VERSION 5.8 ;
BUSBITCHARS "[]" ;
DIVIDERCHAR "/" ;
UNITS
    DATABASE MICRONS 1000 ;
END UNITS

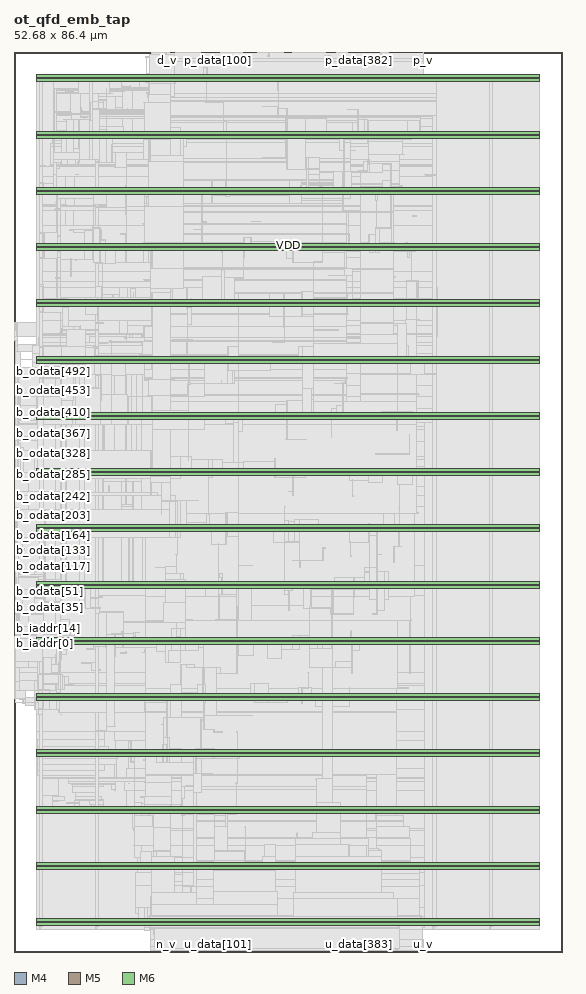
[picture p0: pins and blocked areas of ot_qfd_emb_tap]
MACRO ot_qfd_emb_tap
  FOREIGN ot_qfd_emb_tap 0 0 ;
  CLASS BLOCK ;
  SIZE 52.68 BY 86.4 ;
  PIN b_iaddr[0]
    DIRECTION OUTPUT ;
    USE SIGNAL ;
    PORT
      LAYER M4 ;
        RECT  0 30.384 0.084 30.408 ;
    END
  END b_iaddr[0]
  PIN b_iaddr[10]
    DIRECTION OUTPUT ;
    USE SIGNAL ;
    PORT
      LAYER M4 ;
        RECT  0 30.864 0.084 30.888 ;
    END
  END b_iaddr[10]
  PIN b_iaddr[11]
    DIRECTION OUTPUT ;
    USE SIGNAL ;
    PORT
      LAYER M4 ;
        RECT  0 30.912 0.084 30.936 ;
    END
  END b_iaddr[11]
  PIN b_iaddr[12]
    DIRECTION OUTPUT ;
    USE SIGNAL ;
    PORT
      LAYER M4 ;
        RECT  0 30.96 0.084 30.984 ;
    END
  END b_iaddr[12]
  PIN b_iaddr[13]
    DIRECTION OUTPUT ;
    USE SIGNAL ;
    PORT
      LAYER M4 ;
        RECT  0 31.008 0.084 31.032 ;
    END
  END b_iaddr[13]
  PIN b_iaddr[14]
    DIRECTION OUTPUT ;
    USE SIGNAL ;
    PORT
      LAYER M4 ;
        RECT  0 31.056 0.084 31.08 ;
    END
  END b_iaddr[14]
  PIN b_iaddr[15]
    DIRECTION OUTPUT ;
    USE SIGNAL ;
    PORT
      LAYER M4 ;
        RECT  0 31.104 0.084 31.128 ;
    END
  END b_iaddr[15]
  PIN b_iaddr[16]
    DIRECTION OUTPUT ;
    USE SIGNAL ;
    PORT
      LAYER M4 ;
        RECT  0 31.152 0.084 31.176 ;
    END
  END b_iaddr[16]
  PIN b_iaddr[17]
    DIRECTION OUTPUT ;
    USE SIGNAL ;
    PORT
      LAYER M4 ;
        RECT  0 31.2 0.084 31.224 ;
    END
  END b_iaddr[17]
  PIN b_iaddr[1]
    DIRECTION OUTPUT ;
    USE SIGNAL ;
    PORT
      LAYER M4 ;
        RECT  0 30.432 0.084 30.456 ;
    END
  END b_iaddr[1]
  PIN b_iaddr[2]
    DIRECTION OUTPUT ;
    USE SIGNAL ;
    PORT
      LAYER M4 ;
        RECT  0 30.48 0.084 30.504 ;
    END
  END b_iaddr[2]
  PIN b_iaddr[3]
    DIRECTION OUTPUT ;
    USE SIGNAL ;
    PORT
      LAYER M4 ;
        RECT  0 30.528 0.084 30.552 ;
    END
  END b_iaddr[3]
  PIN b_iaddr[4]
    DIRECTION OUTPUT ;
    USE SIGNAL ;
    PORT
      LAYER M4 ;
        RECT  0 30.576 0.084 30.6 ;
    END
  END b_iaddr[4]
  PIN b_iaddr[5]
    DIRECTION OUTPUT ;
    USE SIGNAL ;
    PORT
      LAYER M4 ;
        RECT  0 30.624 0.084 30.648 ;
    END
  END b_iaddr[5]
  PIN b_iaddr[6]
    DIRECTION OUTPUT ;
    USE SIGNAL ;
    PORT
      LAYER M4 ;
        RECT  0 30.672 0.084 30.696 ;
    END
  END b_iaddr[6]
  PIN b_iaddr[7]
    DIRECTION OUTPUT ;
    USE SIGNAL ;
    PORT
      LAYER M4 ;
        RECT  0 30.72 0.084 30.744 ;
    END
  END b_iaddr[7]
  PIN b_iaddr[8]
    DIRECTION OUTPUT ;
    USE SIGNAL ;
    PORT
      LAYER M4 ;
        RECT  0 30.768 0.084 30.792 ;
    END
  END b_iaddr[8]
  PIN b_iaddr[9]
    DIRECTION OUTPUT ;
    USE SIGNAL ;
    PORT
      LAYER M4 ;
        RECT  0 30.816 0.084 30.84 ;
    END
  END b_iaddr[9]
  PIN b_icr
    DIRECTION INPUT ;
    USE SIGNAL ;
    PORT
      LAYER M4 ;
        RECT  0 31.248 0.084 31.272 ;
    END
  END b_icr
  PIN b_iv
    DIRECTION OUTPUT ;
    USE SIGNAL ;
    PORT
      LAYER M4 ;
        RECT  0 31.296 0.084 31.32 ;
    END
  END b_iv
  PIN b_ocr
    DIRECTION OUTPUT ;
    USE SIGNAL ;
    PORT
      LAYER M4 ;
        RECT  0 31.344 0.084 31.368 ;
    END
  END b_ocr
  PIN b_odata[0]
    DIRECTION INPUT ;
    USE SIGNAL ;
    PORT
      LAYER M4 ;
        RECT  0 31.392 0.084 31.416 ;
    END
  END b_odata[0]
  PIN b_odata[100]
    DIRECTION INPUT ;
    USE SIGNAL ;
    PORT
      LAYER M4 ;
        RECT  0 36.192 0.084 36.216 ;
    END
  END b_odata[100]
  PIN b_odata[101]
    DIRECTION INPUT ;
    USE SIGNAL ;
    PORT
      LAYER M4 ;
        RECT  0 36.24 0.084 36.264 ;
    END
  END b_odata[101]
  PIN b_odata[102]
    DIRECTION INPUT ;
    USE SIGNAL ;
    PORT
      LAYER M4 ;
        RECT  0 36.288 0.084 36.312 ;
    END
  END b_odata[102]
  PIN b_odata[103]
    DIRECTION INPUT ;
    USE SIGNAL ;
    PORT
      LAYER M4 ;
        RECT  0 36.336 0.084 36.36 ;
    END
  END b_odata[103]
  PIN b_odata[104]
    DIRECTION INPUT ;
    USE SIGNAL ;
    PORT
      LAYER M4 ;
        RECT  0 36.384 0.084 36.408 ;
    END
  END b_odata[104]
  PIN b_odata[105]
    DIRECTION INPUT ;
    USE SIGNAL ;
    PORT
      LAYER M4 ;
        RECT  0 36.432 0.084 36.456 ;
    END
  END b_odata[105]
  PIN b_odata[106]
    DIRECTION INPUT ;
    USE SIGNAL ;
    PORT
      LAYER M4 ;
        RECT  0 36.48 0.084 36.504 ;
    END
  END b_odata[106]
  PIN b_odata[107]
    DIRECTION INPUT ;
    USE SIGNAL ;
    PORT
      LAYER M4 ;
        RECT  0 36.528 0.084 36.552 ;
    END
  END b_odata[107]
  PIN b_odata[108]
    DIRECTION INPUT ;
    USE SIGNAL ;
    PORT
      LAYER M4 ;
        RECT  0 36.576 0.084 36.6 ;
    END
  END b_odata[108]
  PIN b_odata[109]
    DIRECTION INPUT ;
    USE SIGNAL ;
    PORT
      LAYER M4 ;
        RECT  0 36.624 0.084 36.648 ;
    END
  END b_odata[109]
  PIN b_odata[10]
    DIRECTION INPUT ;
    USE SIGNAL ;
    PORT
      LAYER M4 ;
        RECT  0 31.872 0.084 31.896 ;
    END
  END b_odata[10]
  PIN b_odata[110]
    DIRECTION INPUT ;
    USE SIGNAL ;
    PORT
      LAYER M4 ;
        RECT  0 36.672 0.084 36.696 ;
    END
  END b_odata[110]
  PIN b_odata[111]
    DIRECTION INPUT ;
    USE SIGNAL ;
    PORT
      LAYER M4 ;
        RECT  0 36.72 0.084 36.744 ;
    END
  END b_odata[111]
  PIN b_odata[112]
    DIRECTION INPUT ;
    USE SIGNAL ;
    PORT
      LAYER M4 ;
        RECT  0 36.768 0.084 36.792 ;
    END
  END b_odata[112]
  PIN b_odata[113]
    DIRECTION INPUT ;
    USE SIGNAL ;
    PORT
      LAYER M4 ;
        RECT  0 36.816 0.084 36.84 ;
    END
  END b_odata[113]
  PIN b_odata[114]
    DIRECTION INPUT ;
    USE SIGNAL ;
    PORT
      LAYER M4 ;
        RECT  0 36.864 0.084 36.888 ;
    END
  END b_odata[114]
  PIN b_odata[115]
    DIRECTION INPUT ;
    USE SIGNAL ;
    PORT
      LAYER M4 ;
        RECT  0 36.912 0.084 36.936 ;
    END
  END b_odata[115]
  PIN b_odata[116]
    DIRECTION INPUT ;
    USE SIGNAL ;
    PORT
      LAYER M4 ;
        RECT  0 36.96 0.084 36.984 ;
    END
  END b_odata[116]
  PIN b_odata[117]
    DIRECTION INPUT ;
    USE SIGNAL ;
    PORT
      LAYER M4 ;
        RECT  0 37.008 0.084 37.032 ;
    END
  END b_odata[117]
  PIN b_odata[118]
    DIRECTION INPUT ;
    USE SIGNAL ;
    PORT
      LAYER M4 ;
        RECT  0 37.056 0.084 37.08 ;
    END
  END b_odata[118]
  PIN b_odata[119]
    DIRECTION INPUT ;
    USE SIGNAL ;
    PORT
      LAYER M4 ;
        RECT  0 37.104 0.084 37.128 ;
    END
  END b_odata[119]
  PIN b_odata[11]
    DIRECTION INPUT ;
    USE SIGNAL ;
    PORT
      LAYER M4 ;
        RECT  0 31.92 0.084 31.944 ;
    END
  END b_odata[11]
  PIN b_odata[120]
    DIRECTION INPUT ;
    USE SIGNAL ;
    PORT
      LAYER M4 ;
        RECT  0 37.152 0.084 37.176 ;
    END
  END b_odata[120]
  PIN b_odata[121]
    DIRECTION INPUT ;
    USE SIGNAL ;
    PORT
      LAYER M4 ;
        RECT  0 37.2 0.084 37.224 ;
    END
  END b_odata[121]
  PIN b_odata[122]
    DIRECTION INPUT ;
    USE SIGNAL ;
    PORT
      LAYER M4 ;
        RECT  0 37.248 0.084 37.272 ;
    END
  END b_odata[122]
  PIN b_odata[123]
    DIRECTION INPUT ;
    USE SIGNAL ;
    PORT
      LAYER M4 ;
        RECT  0 37.296 0.084 37.32 ;
    END
  END b_odata[123]
  PIN b_odata[124]
    DIRECTION INPUT ;
    USE SIGNAL ;
    PORT
      LAYER M4 ;
        RECT  0 37.344 0.084 37.368 ;
    END
  END b_odata[124]
  PIN b_odata[125]
    DIRECTION INPUT ;
    USE SIGNAL ;
    PORT
      LAYER M4 ;
        RECT  0 37.392 0.084 37.416 ;
    END
  END b_odata[125]
  PIN b_odata[126]
    DIRECTION INPUT ;
    USE SIGNAL ;
    PORT
      LAYER M4 ;
        RECT  0 37.44 0.084 37.464 ;
    END
  END b_odata[126]
  PIN b_odata[127]
    DIRECTION INPUT ;
    USE SIGNAL ;
    PORT
      LAYER M4 ;
        RECT  0 37.488 0.084 37.512 ;
    END
  END b_odata[127]
  PIN b_odata[128]
    DIRECTION INPUT ;
    USE SIGNAL ;
    PORT
      LAYER M4 ;
        RECT  0 37.536 0.084 37.56 ;
    END
  END b_odata[128]
  PIN b_odata[129]
    DIRECTION INPUT ;
    USE SIGNAL ;
    PORT
      LAYER M4 ;
        RECT  0 37.584 0.084 37.608 ;
    END
  END b_odata[129]
  PIN b_odata[12]
    DIRECTION INPUT ;
    USE SIGNAL ;
    PORT
      LAYER M4 ;
        RECT  0 31.968 0.084 31.992 ;
    END
  END b_odata[12]
  PIN b_odata[130]
    DIRECTION INPUT ;
    USE SIGNAL ;
    PORT
      LAYER M4 ;
        RECT  0 37.632 0.084 37.656 ;
    END
  END b_odata[130]
  PIN b_odata[131]
    DIRECTION INPUT ;
    USE SIGNAL ;
    PORT
      LAYER M4 ;
        RECT  0 37.68 0.084 37.704 ;
    END
  END b_odata[131]
  PIN b_odata[132]
    DIRECTION INPUT ;
    USE SIGNAL ;
    PORT
      LAYER M4 ;
        RECT  0 37.728 0.084 37.752 ;
    END
  END b_odata[132]
  PIN b_odata[133]
    DIRECTION INPUT ;
    USE SIGNAL ;
    PORT
      LAYER M4 ;
        RECT  0 37.776 0.084 37.8 ;
    END
  END b_odata[133]
  PIN b_odata[134]
    DIRECTION INPUT ;
    USE SIGNAL ;
    PORT
      LAYER M4 ;
        RECT  0 37.824 0.084 37.848 ;
    END
  END b_odata[134]
  PIN b_odata[135]
    DIRECTION INPUT ;
    USE SIGNAL ;
    PORT
      LAYER M4 ;
        RECT  0 37.872 0.084 37.896 ;
    END
  END b_odata[135]
  PIN b_odata[136]
    DIRECTION INPUT ;
    USE SIGNAL ;
    PORT
      LAYER M4 ;
        RECT  0 37.92 0.084 37.944 ;
    END
  END b_odata[136]
  PIN b_odata[137]
    DIRECTION INPUT ;
    USE SIGNAL ;
    PORT
      LAYER M4 ;
        RECT  0 37.968 0.084 37.992 ;
    END
  END b_odata[137]
  PIN b_odata[138]
    DIRECTION INPUT ;
    USE SIGNAL ;
    PORT
      LAYER M4 ;
        RECT  0 38.016 0.084 38.04 ;
    END
  END b_odata[138]
  PIN b_odata[139]
    DIRECTION INPUT ;
    USE SIGNAL ;
    PORT
      LAYER M4 ;
        RECT  0 38.064 0.084 38.088 ;
    END
  END b_odata[139]
  PIN b_odata[13]
    DIRECTION INPUT ;
    USE SIGNAL ;
    PORT
      LAYER M4 ;
        RECT  0 32.016 0.084 32.04 ;
    END
  END b_odata[13]
  PIN b_odata[140]
    DIRECTION INPUT ;
    USE SIGNAL ;
    PORT
      LAYER M4 ;
        RECT  0 38.112 0.084 38.136 ;
    END
  END b_odata[140]
  PIN b_odata[141]
    DIRECTION INPUT ;
    USE SIGNAL ;
    PORT
      LAYER M4 ;
        RECT  0 38.16 0.084 38.184 ;
    END
  END b_odata[141]
  PIN b_odata[142]
    DIRECTION INPUT ;
    USE SIGNAL ;
    PORT
      LAYER M4 ;
        RECT  0 38.208 0.084 38.232 ;
    END
  END b_odata[142]
  PIN b_odata[143]
    DIRECTION INPUT ;
    USE SIGNAL ;
    PORT
      LAYER M4 ;
        RECT  0 38.256 0.084 38.28 ;
    END
  END b_odata[143]
  PIN b_odata[144]
    DIRECTION INPUT ;
    USE SIGNAL ;
    PORT
      LAYER M4 ;
        RECT  0 38.304 0.084 38.328 ;
    END
  END b_odata[144]
  PIN b_odata[145]
    DIRECTION INPUT ;
    USE SIGNAL ;
    PORT
      LAYER M4 ;
        RECT  0 38.352 0.084 38.376 ;
    END
  END b_odata[145]
  PIN b_odata[146]
    DIRECTION INPUT ;
    USE SIGNAL ;
    PORT
      LAYER M4 ;
        RECT  0 38.4 0.084 38.424 ;
    END
  END b_odata[146]
  PIN b_odata[147]
    DIRECTION INPUT ;
    USE SIGNAL ;
    PORT
      LAYER M4 ;
        RECT  0 38.448 0.084 38.472 ;
    END
  END b_odata[147]
  PIN b_odata[148]
    DIRECTION INPUT ;
    USE SIGNAL ;
    PORT
      LAYER M4 ;
        RECT  0 38.496 0.084 38.52 ;
    END
  END b_odata[148]
  PIN b_odata[149]
    DIRECTION INPUT ;
    USE SIGNAL ;
    PORT
      LAYER M4 ;
        RECT  0 38.544 0.084 38.568 ;
    END
  END b_odata[149]
  PIN b_odata[14]
    DIRECTION INPUT ;
    USE SIGNAL ;
    PORT
      LAYER M4 ;
        RECT  0 32.064 0.084 32.088 ;
    END
  END b_odata[14]
  PIN b_odata[150]
    DIRECTION INPUT ;
    USE SIGNAL ;
    PORT
      LAYER M4 ;
        RECT  0 38.592 0.084 38.616 ;
    END
  END b_odata[150]
  PIN b_odata[151]
    DIRECTION INPUT ;
    USE SIGNAL ;
    PORT
      LAYER M4 ;
        RECT  0 38.64 0.084 38.664 ;
    END
  END b_odata[151]
  PIN b_odata[152]
    DIRECTION INPUT ;
    USE SIGNAL ;
    PORT
      LAYER M4 ;
        RECT  0 38.688 0.084 38.712 ;
    END
  END b_odata[152]
  PIN b_odata[153]
    DIRECTION INPUT ;
    USE SIGNAL ;
    PORT
      LAYER M4 ;
        RECT  0 38.736 0.084 38.76 ;
    END
  END b_odata[153]
  PIN b_odata[154]
    DIRECTION INPUT ;
    USE SIGNAL ;
    PORT
      LAYER M4 ;
        RECT  0 38.784 0.084 38.808 ;
    END
  END b_odata[154]
  PIN b_odata[155]
    DIRECTION INPUT ;
    USE SIGNAL ;
    PORT
      LAYER M4 ;
        RECT  0 38.832 0.084 38.856 ;
    END
  END b_odata[155]
  PIN b_odata[156]
    DIRECTION INPUT ;
    USE SIGNAL ;
    PORT
      LAYER M4 ;
        RECT  0 38.88 0.084 38.904 ;
    END
  END b_odata[156]
  PIN b_odata[157]
    DIRECTION INPUT ;
    USE SIGNAL ;
    PORT
      LAYER M4 ;
        RECT  0 38.928 0.084 38.952 ;
    END
  END b_odata[157]
  PIN b_odata[158]
    DIRECTION INPUT ;
    USE SIGNAL ;
    PORT
      LAYER M4 ;
        RECT  0 38.976 0.084 39 ;
    END
  END b_odata[158]
  PIN b_odata[159]
    DIRECTION INPUT ;
    USE SIGNAL ;
    PORT
      LAYER M4 ;
        RECT  0 39.024 0.084 39.048 ;
    END
  END b_odata[159]
  PIN b_odata[15]
    DIRECTION INPUT ;
    USE SIGNAL ;
    PORT
      LAYER M4 ;
        RECT  0 32.112 0.084 32.136 ;
    END
  END b_odata[15]
  PIN b_odata[160]
    DIRECTION INPUT ;
    USE SIGNAL ;
    PORT
      LAYER M4 ;
        RECT  0 39.072 0.084 39.096 ;
    END
  END b_odata[160]
  PIN b_odata[161]
    DIRECTION INPUT ;
    USE SIGNAL ;
    PORT
      LAYER M4 ;
        RECT  0 39.12 0.084 39.144 ;
    END
  END b_odata[161]
  PIN b_odata[162]
    DIRECTION INPUT ;
    USE SIGNAL ;
    PORT
      LAYER M4 ;
        RECT  0 39.168 0.084 39.192 ;
    END
  END b_odata[162]
  PIN b_odata[163]
    DIRECTION INPUT ;
    USE SIGNAL ;
    PORT
      LAYER M4 ;
        RECT  0 39.216 0.084 39.24 ;
    END
  END b_odata[163]
  PIN b_odata[164]
    DIRECTION INPUT ;
    USE SIGNAL ;
    PORT
      LAYER M4 ;
        RECT  0 39.264 0.084 39.288 ;
    END
  END b_odata[164]
  PIN b_odata[165]
    DIRECTION INPUT ;
    USE SIGNAL ;
    PORT
      LAYER M4 ;
        RECT  0 39.312 0.084 39.336 ;
    END
  END b_odata[165]
  PIN b_odata[166]
    DIRECTION INPUT ;
    USE SIGNAL ;
    PORT
      LAYER M4 ;
        RECT  0 39.36 0.084 39.384 ;
    END
  END b_odata[166]
  PIN b_odata[167]
    DIRECTION INPUT ;
    USE SIGNAL ;
    PORT
      LAYER M4 ;
        RECT  0 39.408 0.084 39.432 ;
    END
  END b_odata[167]
  PIN b_odata[168]
    DIRECTION INPUT ;
    USE SIGNAL ;
    PORT
      LAYER M4 ;
        RECT  0 39.456 0.084 39.48 ;
    END
  END b_odata[168]
  PIN b_odata[169]
    DIRECTION INPUT ;
    USE SIGNAL ;
    PORT
      LAYER M4 ;
        RECT  0 39.504 0.084 39.528 ;
    END
  END b_odata[169]
  PIN b_odata[16]
    DIRECTION INPUT ;
    USE SIGNAL ;
    PORT
      LAYER M4 ;
        RECT  0 32.16 0.084 32.184 ;
    END
  END b_odata[16]
  PIN b_odata[170]
    DIRECTION INPUT ;
    USE SIGNAL ;
    PORT
      LAYER M4 ;
        RECT  0 39.552 0.084 39.576 ;
    END
  END b_odata[170]
  PIN b_odata[171]
    DIRECTION INPUT ;
    USE SIGNAL ;
    PORT
      LAYER M4 ;
        RECT  0 39.6 0.084 39.624 ;
    END
  END b_odata[171]
  PIN b_odata[172]
    DIRECTION INPUT ;
    USE SIGNAL ;
    PORT
      LAYER M4 ;
        RECT  0 39.648 0.084 39.672 ;
    END
  END b_odata[172]
  PIN b_odata[173]
    DIRECTION INPUT ;
    USE SIGNAL ;
    PORT
      LAYER M4 ;
        RECT  0 39.696 0.084 39.72 ;
    END
  END b_odata[173]
  PIN b_odata[174]
    DIRECTION INPUT ;
    USE SIGNAL ;
    PORT
      LAYER M4 ;
        RECT  0 39.744 0.084 39.768 ;
    END
  END b_odata[174]
  PIN b_odata[175]
    DIRECTION INPUT ;
    USE SIGNAL ;
    PORT
      LAYER M4 ;
        RECT  0 39.792 0.084 39.816 ;
    END
  END b_odata[175]
  PIN b_odata[176]
    DIRECTION INPUT ;
    USE SIGNAL ;
    PORT
      LAYER M4 ;
        RECT  0 39.84 0.084 39.864 ;
    END
  END b_odata[176]
  PIN b_odata[177]
    DIRECTION INPUT ;
    USE SIGNAL ;
    PORT
      LAYER M4 ;
        RECT  0 39.888 0.084 39.912 ;
    END
  END b_odata[177]
  PIN b_odata[178]
    DIRECTION INPUT ;
    USE SIGNAL ;
    PORT
      LAYER M4 ;
        RECT  0 39.936 0.084 39.96 ;
    END
  END b_odata[178]
  PIN b_odata[179]
    DIRECTION INPUT ;
    USE SIGNAL ;
    PORT
      LAYER M4 ;
        RECT  0 39.984 0.084 40.008 ;
    END
  END b_odata[179]
  PIN b_odata[17]
    DIRECTION INPUT ;
    USE SIGNAL ;
    PORT
      LAYER M4 ;
        RECT  0 32.208 0.084 32.232 ;
    END
  END b_odata[17]
  PIN b_odata[180]
    DIRECTION INPUT ;
    USE SIGNAL ;
    PORT
      LAYER M4 ;
        RECT  0 40.032 0.084 40.056 ;
    END
  END b_odata[180]
  PIN b_odata[181]
    DIRECTION INPUT ;
    USE SIGNAL ;
    PORT
      LAYER M4 ;
        RECT  0 40.08 0.084 40.104 ;
    END
  END b_odata[181]
  PIN b_odata[182]
    DIRECTION INPUT ;
    USE SIGNAL ;
    PORT
      LAYER M4 ;
        RECT  0 40.128 0.084 40.152 ;
    END
  END b_odata[182]
  PIN b_odata[183]
    DIRECTION INPUT ;
    USE SIGNAL ;
    PORT
      LAYER M4 ;
        RECT  0 40.176 0.084 40.2 ;
    END
  END b_odata[183]
  PIN b_odata[184]
    DIRECTION INPUT ;
    USE SIGNAL ;
    PORT
      LAYER M4 ;
        RECT  0 40.224 0.084 40.248 ;
    END
  END b_odata[184]
  PIN b_odata[185]
    DIRECTION INPUT ;
    USE SIGNAL ;
    PORT
      LAYER M4 ;
        RECT  0 40.272 0.084 40.296 ;
    END
  END b_odata[185]
  PIN b_odata[186]
    DIRECTION INPUT ;
    USE SIGNAL ;
    PORT
      LAYER M4 ;
        RECT  0 40.32 0.084 40.344 ;
    END
  END b_odata[186]
  PIN b_odata[187]
    DIRECTION INPUT ;
    USE SIGNAL ;
    PORT
      LAYER M4 ;
        RECT  0 40.368 0.084 40.392 ;
    END
  END b_odata[187]
  PIN b_odata[188]
    DIRECTION INPUT ;
    USE SIGNAL ;
    PORT
      LAYER M4 ;
        RECT  0 40.416 0.084 40.44 ;
    END
  END b_odata[188]
  PIN b_odata[189]
    DIRECTION INPUT ;
    USE SIGNAL ;
    PORT
      LAYER M4 ;
        RECT  0 40.464 0.084 40.488 ;
    END
  END b_odata[189]
  PIN b_odata[18]
    DIRECTION INPUT ;
    USE SIGNAL ;
    PORT
      LAYER M4 ;
        RECT  0 32.256 0.084 32.28 ;
    END
  END b_odata[18]
  PIN b_odata[190]
    DIRECTION INPUT ;
    USE SIGNAL ;
    PORT
      LAYER M4 ;
        RECT  0 40.512 0.084 40.536 ;
    END
  END b_odata[190]
  PIN b_odata[191]
    DIRECTION INPUT ;
    USE SIGNAL ;
    PORT
      LAYER M4 ;
        RECT  0 40.56 0.084 40.584 ;
    END
  END b_odata[191]
  PIN b_odata[192]
    DIRECTION INPUT ;
    USE SIGNAL ;
    PORT
      LAYER M4 ;
        RECT  0 40.608 0.084 40.632 ;
    END
  END b_odata[192]
  PIN b_odata[193]
    DIRECTION INPUT ;
    USE SIGNAL ;
    PORT
      LAYER M4 ;
        RECT  0 40.656 0.084 40.68 ;
    END
  END b_odata[193]
  PIN b_odata[194]
    DIRECTION INPUT ;
    USE SIGNAL ;
    PORT
      LAYER M4 ;
        RECT  0 40.704 0.084 40.728 ;
    END
  END b_odata[194]
  PIN b_odata[195]
    DIRECTION INPUT ;
    USE SIGNAL ;
    PORT
      LAYER M4 ;
        RECT  0 40.752 0.084 40.776 ;
    END
  END b_odata[195]
  PIN b_odata[196]
    DIRECTION INPUT ;
    USE SIGNAL ;
    PORT
      LAYER M4 ;
        RECT  0 40.8 0.084 40.824 ;
    END
  END b_odata[196]
  PIN b_odata[197]
    DIRECTION INPUT ;
    USE SIGNAL ;
    PORT
      LAYER M4 ;
        RECT  0 40.848 0.084 40.872 ;
    END
  END b_odata[197]
  PIN b_odata[198]
    DIRECTION INPUT ;
    USE SIGNAL ;
    PORT
      LAYER M4 ;
        RECT  0 40.896 0.084 40.92 ;
    END
  END b_odata[198]
  PIN b_odata[199]
    DIRECTION INPUT ;
    USE SIGNAL ;
    PORT
      LAYER M4 ;
        RECT  0 40.944 0.084 40.968 ;
    END
  END b_odata[199]
  PIN b_odata[19]
    DIRECTION INPUT ;
    USE SIGNAL ;
    PORT
      LAYER M4 ;
        RECT  0 32.304 0.084 32.328 ;
    END
  END b_odata[19]
  PIN b_odata[1]
    DIRECTION INPUT ;
    USE SIGNAL ;
    PORT
      LAYER M4 ;
        RECT  0 31.44 0.084 31.464 ;
    END
  END b_odata[1]
  PIN b_odata[200]
    DIRECTION INPUT ;
    USE SIGNAL ;
    PORT
      LAYER M4 ;
        RECT  0 40.992 0.084 41.016 ;
    END
  END b_odata[200]
  PIN b_odata[201]
    DIRECTION INPUT ;
    USE SIGNAL ;
    PORT
      LAYER M4 ;
        RECT  0 41.04 0.084 41.064 ;
    END
  END b_odata[201]
  PIN b_odata[202]
    DIRECTION INPUT ;
    USE SIGNAL ;
    PORT
      LAYER M4 ;
        RECT  0 41.088 0.084 41.112 ;
    END
  END b_odata[202]
  PIN b_odata[203]
    DIRECTION INPUT ;
    USE SIGNAL ;
    PORT
      LAYER M4 ;
        RECT  0 41.136 0.084 41.16 ;
    END
  END b_odata[203]
  PIN b_odata[204]
    DIRECTION INPUT ;
    USE SIGNAL ;
    PORT
      LAYER M4 ;
        RECT  0 41.184 0.084 41.208 ;
    END
  END b_odata[204]
  PIN b_odata[205]
    DIRECTION INPUT ;
    USE SIGNAL ;
    PORT
      LAYER M4 ;
        RECT  0 41.232 0.084 41.256 ;
    END
  END b_odata[205]
  PIN b_odata[206]
    DIRECTION INPUT ;
    USE SIGNAL ;
    PORT
      LAYER M4 ;
        RECT  0 41.28 0.084 41.304 ;
    END
  END b_odata[206]
  PIN b_odata[207]
    DIRECTION INPUT ;
    USE SIGNAL ;
    PORT
      LAYER M4 ;
        RECT  0 41.328 0.084 41.352 ;
    END
  END b_odata[207]
  PIN b_odata[208]
    DIRECTION INPUT ;
    USE SIGNAL ;
    PORT
      LAYER M4 ;
        RECT  0 41.376 0.084 41.4 ;
    END
  END b_odata[208]
  PIN b_odata[209]
    DIRECTION INPUT ;
    USE SIGNAL ;
    PORT
      LAYER M4 ;
        RECT  0 41.424 0.084 41.448 ;
    END
  END b_odata[209]
  PIN b_odata[20]
    DIRECTION INPUT ;
    USE SIGNAL ;
    PORT
      LAYER M4 ;
        RECT  0 32.352 0.084 32.376 ;
    END
  END b_odata[20]
  PIN b_odata[210]
    DIRECTION INPUT ;
    USE SIGNAL ;
    PORT
      LAYER M4 ;
        RECT  0 41.472 0.084 41.496 ;
    END
  END b_odata[210]
  PIN b_odata[211]
    DIRECTION INPUT ;
    USE SIGNAL ;
    PORT
      LAYER M4 ;
        RECT  0 41.52 0.084 41.544 ;
    END
  END b_odata[211]
  PIN b_odata[212]
    DIRECTION INPUT ;
    USE SIGNAL ;
    PORT
      LAYER M4 ;
        RECT  0 41.568 0.084 41.592 ;
    END
  END b_odata[212]
  PIN b_odata[213]
    DIRECTION INPUT ;
    USE SIGNAL ;
    PORT
      LAYER M4 ;
        RECT  0 41.616 0.084 41.64 ;
    END
  END b_odata[213]
  PIN b_odata[214]
    DIRECTION INPUT ;
    USE SIGNAL ;
    PORT
      LAYER M4 ;
        RECT  0 41.664 0.084 41.688 ;
    END
  END b_odata[214]
  PIN b_odata[215]
    DIRECTION INPUT ;
    USE SIGNAL ;
    PORT
      LAYER M4 ;
        RECT  0 41.712 0.084 41.736 ;
    END
  END b_odata[215]
  PIN b_odata[216]
    DIRECTION INPUT ;
    USE SIGNAL ;
    PORT
      LAYER M4 ;
        RECT  0 41.76 0.084 41.784 ;
    END
  END b_odata[216]
  PIN b_odata[217]
    DIRECTION INPUT ;
    USE SIGNAL ;
    PORT
      LAYER M4 ;
        RECT  0 41.808 0.084 41.832 ;
    END
  END b_odata[217]
  PIN b_odata[218]
    DIRECTION INPUT ;
    USE SIGNAL ;
    PORT
      LAYER M4 ;
        RECT  0 41.856 0.084 41.88 ;
    END
  END b_odata[218]
  PIN b_odata[219]
    DIRECTION INPUT ;
    USE SIGNAL ;
    PORT
      LAYER M4 ;
        RECT  0 41.904 0.084 41.928 ;
    END
  END b_odata[219]
  PIN b_odata[21]
    DIRECTION INPUT ;
    USE SIGNAL ;
    PORT
      LAYER M4 ;
        RECT  0 32.4 0.084 32.424 ;
    END
  END b_odata[21]
  PIN b_odata[220]
    DIRECTION INPUT ;
    USE SIGNAL ;
    PORT
      LAYER M4 ;
        RECT  0 41.952 0.084 41.976 ;
    END
  END b_odata[220]
  PIN b_odata[221]
    DIRECTION INPUT ;
    USE SIGNAL ;
    PORT
      LAYER M4 ;
        RECT  0 42 0.084 42.024 ;
    END
  END b_odata[221]
  PIN b_odata[222]
    DIRECTION INPUT ;
    USE SIGNAL ;
    PORT
      LAYER M4 ;
        RECT  0 42.048 0.084 42.072 ;
    END
  END b_odata[222]
  PIN b_odata[223]
    DIRECTION INPUT ;
    USE SIGNAL ;
    PORT
      LAYER M4 ;
        RECT  0 42.096 0.084 42.12 ;
    END
  END b_odata[223]
  PIN b_odata[224]
    DIRECTION INPUT ;
    USE SIGNAL ;
    PORT
      LAYER M4 ;
        RECT  0 42.144 0.084 42.168 ;
    END
  END b_odata[224]
  PIN b_odata[225]
    DIRECTION INPUT ;
    USE SIGNAL ;
    PORT
      LAYER M4 ;
        RECT  0 42.192 0.084 42.216 ;
    END
  END b_odata[225]
  PIN b_odata[226]
    DIRECTION INPUT ;
    USE SIGNAL ;
    PORT
      LAYER M4 ;
        RECT  0 42.24 0.084 42.264 ;
    END
  END b_odata[226]
  PIN b_odata[227]
    DIRECTION INPUT ;
    USE SIGNAL ;
    PORT
      LAYER M4 ;
        RECT  0 42.288 0.084 42.312 ;
    END
  END b_odata[227]
  PIN b_odata[228]
    DIRECTION INPUT ;
    USE SIGNAL ;
    PORT
      LAYER M4 ;
        RECT  0 42.336 0.084 42.36 ;
    END
  END b_odata[228]
  PIN b_odata[229]
    DIRECTION INPUT ;
    USE SIGNAL ;
    PORT
      LAYER M4 ;
        RECT  0 42.384 0.084 42.408 ;
    END
  END b_odata[229]
  PIN b_odata[22]
    DIRECTION INPUT ;
    USE SIGNAL ;
    PORT
      LAYER M4 ;
        RECT  0 32.448 0.084 32.472 ;
    END
  END b_odata[22]
  PIN b_odata[230]
    DIRECTION INPUT ;
    USE SIGNAL ;
    PORT
      LAYER M4 ;
        RECT  0 42.432 0.084 42.456 ;
    END
  END b_odata[230]
  PIN b_odata[231]
    DIRECTION INPUT ;
    USE SIGNAL ;
    PORT
      LAYER M4 ;
        RECT  0 42.48 0.084 42.504 ;
    END
  END b_odata[231]
  PIN b_odata[232]
    DIRECTION INPUT ;
    USE SIGNAL ;
    PORT
      LAYER M4 ;
        RECT  0 42.528 0.084 42.552 ;
    END
  END b_odata[232]
  PIN b_odata[233]
    DIRECTION INPUT ;
    USE SIGNAL ;
    PORT
      LAYER M4 ;
        RECT  0 42.576 0.084 42.6 ;
    END
  END b_odata[233]
  PIN b_odata[234]
    DIRECTION INPUT ;
    USE SIGNAL ;
    PORT
      LAYER M4 ;
        RECT  0 42.624 0.084 42.648 ;
    END
  END b_odata[234]
  PIN b_odata[235]
    DIRECTION INPUT ;
    USE SIGNAL ;
    PORT
      LAYER M4 ;
        RECT  0 42.672 0.084 42.696 ;
    END
  END b_odata[235]
  PIN b_odata[236]
    DIRECTION INPUT ;
    USE SIGNAL ;
    PORT
      LAYER M4 ;
        RECT  0 42.72 0.084 42.744 ;
    END
  END b_odata[236]
  PIN b_odata[237]
    DIRECTION INPUT ;
    USE SIGNAL ;
    PORT
      LAYER M4 ;
        RECT  0 42.768 0.084 42.792 ;
    END
  END b_odata[237]
  PIN b_odata[238]
    DIRECTION INPUT ;
    USE SIGNAL ;
    PORT
      LAYER M4 ;
        RECT  0 42.816 0.084 42.84 ;
    END
  END b_odata[238]
  PIN b_odata[239]
    DIRECTION INPUT ;
    USE SIGNAL ;
    PORT
      LAYER M4 ;
        RECT  0 42.864 0.084 42.888 ;
    END
  END b_odata[239]
  PIN b_odata[23]
    DIRECTION INPUT ;
    USE SIGNAL ;
    PORT
      LAYER M4 ;
        RECT  0 32.496 0.084 32.52 ;
    END
  END b_odata[23]
  PIN b_odata[240]
    DIRECTION INPUT ;
    USE SIGNAL ;
    PORT
      LAYER M4 ;
        RECT  0 42.912 0.084 42.936 ;
    END
  END b_odata[240]
  PIN b_odata[241]
    DIRECTION INPUT ;
    USE SIGNAL ;
    PORT
      LAYER M4 ;
        RECT  0 42.96 0.084 42.984 ;
    END
  END b_odata[241]
  PIN b_odata[242]
    DIRECTION INPUT ;
    USE SIGNAL ;
    PORT
      LAYER M4 ;
        RECT  0 43.008 0.084 43.032 ;
    END
  END b_odata[242]
  PIN b_odata[243]
    DIRECTION INPUT ;
    USE SIGNAL ;
    PORT
      LAYER M4 ;
        RECT  0 43.056 0.084 43.08 ;
    END
  END b_odata[243]
  PIN b_odata[244]
    DIRECTION INPUT ;
    USE SIGNAL ;
    PORT
      LAYER M4 ;
        RECT  0 43.104 0.084 43.128 ;
    END
  END b_odata[244]
  PIN b_odata[245]
    DIRECTION INPUT ;
    USE SIGNAL ;
    PORT
      LAYER M4 ;
        RECT  0 43.152 0.084 43.176 ;
    END
  END b_odata[245]
  PIN b_odata[246]
    DIRECTION INPUT ;
    USE SIGNAL ;
    PORT
      LAYER M4 ;
        RECT  0 43.2 0.084 43.224 ;
    END
  END b_odata[246]
  PIN b_odata[247]
    DIRECTION INPUT ;
    USE SIGNAL ;
    PORT
      LAYER M4 ;
        RECT  0 43.248 0.084 43.272 ;
    END
  END b_odata[247]
  PIN b_odata[248]
    DIRECTION INPUT ;
    USE SIGNAL ;
    PORT
      LAYER M4 ;
        RECT  0 43.296 0.084 43.32 ;
    END
  END b_odata[248]
  PIN b_odata[249]
    DIRECTION INPUT ;
    USE SIGNAL ;
    PORT
      LAYER M4 ;
        RECT  0 43.344 0.084 43.368 ;
    END
  END b_odata[249]
  PIN b_odata[24]
    DIRECTION INPUT ;
    USE SIGNAL ;
    PORT
      LAYER M4 ;
        RECT  0 32.544 0.084 32.568 ;
    END
  END b_odata[24]
  PIN b_odata[250]
    DIRECTION INPUT ;
    USE SIGNAL ;
    PORT
      LAYER M4 ;
        RECT  0 43.392 0.084 43.416 ;
    END
  END b_odata[250]
  PIN b_odata[251]
    DIRECTION INPUT ;
    USE SIGNAL ;
    PORT
      LAYER M4 ;
        RECT  0 43.44 0.084 43.464 ;
    END
  END b_odata[251]
  PIN b_odata[252]
    DIRECTION INPUT ;
    USE SIGNAL ;
    PORT
      LAYER M4 ;
        RECT  0 43.488 0.084 43.512 ;
    END
  END b_odata[252]
  PIN b_odata[253]
    DIRECTION INPUT ;
    USE SIGNAL ;
    PORT
      LAYER M4 ;
        RECT  0 43.536 0.084 43.56 ;
    END
  END b_odata[253]
  PIN b_odata[254]
    DIRECTION INPUT ;
    USE SIGNAL ;
    PORT
      LAYER M4 ;
        RECT  0 43.584 0.084 43.608 ;
    END
  END b_odata[254]
  PIN b_odata[255]
    DIRECTION INPUT ;
    USE SIGNAL ;
    PORT
      LAYER M4 ;
        RECT  0 43.632 0.084 43.656 ;
    END
  END b_odata[255]
  PIN b_odata[256]
    DIRECTION INPUT ;
    USE SIGNAL ;
    PORT
      LAYER M4 ;
        RECT  0 43.68 0.084 43.704 ;
    END
  END b_odata[256]
  PIN b_odata[257]
    DIRECTION INPUT ;
    USE SIGNAL ;
    PORT
      LAYER M4 ;
        RECT  0 43.728 0.084 43.752 ;
    END
  END b_odata[257]
  PIN b_odata[258]
    DIRECTION INPUT ;
    USE SIGNAL ;
    PORT
      LAYER M4 ;
        RECT  0 43.776 0.084 43.8 ;
    END
  END b_odata[258]
  PIN b_odata[259]
    DIRECTION INPUT ;
    USE SIGNAL ;
    PORT
      LAYER M4 ;
        RECT  0 43.824 0.084 43.848 ;
    END
  END b_odata[259]
  PIN b_odata[25]
    DIRECTION INPUT ;
    USE SIGNAL ;
    PORT
      LAYER M4 ;
        RECT  0 32.592 0.084 32.616 ;
    END
  END b_odata[25]
  PIN b_odata[260]
    DIRECTION INPUT ;
    USE SIGNAL ;
    PORT
      LAYER M4 ;
        RECT  0 43.872 0.084 43.896 ;
    END
  END b_odata[260]
  PIN b_odata[261]
    DIRECTION INPUT ;
    USE SIGNAL ;
    PORT
      LAYER M4 ;
        RECT  0 43.92 0.084 43.944 ;
    END
  END b_odata[261]
  PIN b_odata[262]
    DIRECTION INPUT ;
    USE SIGNAL ;
    PORT
      LAYER M4 ;
        RECT  0 43.968 0.084 43.992 ;
    END
  END b_odata[262]
  PIN b_odata[263]
    DIRECTION INPUT ;
    USE SIGNAL ;
    PORT
      LAYER M4 ;
        RECT  0 44.016 0.084 44.04 ;
    END
  END b_odata[263]
  PIN b_odata[264]
    DIRECTION INPUT ;
    USE SIGNAL ;
    PORT
      LAYER M4 ;
        RECT  0 44.064 0.084 44.088 ;
    END
  END b_odata[264]
  PIN b_odata[265]
    DIRECTION INPUT ;
    USE SIGNAL ;
    PORT
      LAYER M4 ;
        RECT  0 44.112 0.084 44.136 ;
    END
  END b_odata[265]
  PIN b_odata[266]
    DIRECTION INPUT ;
    USE SIGNAL ;
    PORT
      LAYER M4 ;
        RECT  0 44.16 0.084 44.184 ;
    END
  END b_odata[266]
  PIN b_odata[267]
    DIRECTION INPUT ;
    USE SIGNAL ;
    PORT
      LAYER M4 ;
        RECT  0 44.208 0.084 44.232 ;
    END
  END b_odata[267]
  PIN b_odata[268]
    DIRECTION INPUT ;
    USE SIGNAL ;
    PORT
      LAYER M4 ;
        RECT  0 44.256 0.084 44.28 ;
    END
  END b_odata[268]
  PIN b_odata[269]
    DIRECTION INPUT ;
    USE SIGNAL ;
    PORT
      LAYER M4 ;
        RECT  0 44.304 0.084 44.328 ;
    END
  END b_odata[269]
  PIN b_odata[26]
    DIRECTION INPUT ;
    USE SIGNAL ;
    PORT
      LAYER M4 ;
        RECT  0 32.64 0.084 32.664 ;
    END
  END b_odata[26]
  PIN b_odata[270]
    DIRECTION INPUT ;
    USE SIGNAL ;
    PORT
      LAYER M4 ;
        RECT  0 44.352 0.084 44.376 ;
    END
  END b_odata[270]
  PIN b_odata[271]
    DIRECTION INPUT ;
    USE SIGNAL ;
    PORT
      LAYER M4 ;
        RECT  0 44.4 0.084 44.424 ;
    END
  END b_odata[271]
  PIN b_odata[272]
    DIRECTION INPUT ;
    USE SIGNAL ;
    PORT
      LAYER M4 ;
        RECT  0 44.448 0.084 44.472 ;
    END
  END b_odata[272]
  PIN b_odata[273]
    DIRECTION INPUT ;
    USE SIGNAL ;
    PORT
      LAYER M4 ;
        RECT  0 44.496 0.084 44.52 ;
    END
  END b_odata[273]
  PIN b_odata[274]
    DIRECTION INPUT ;
    USE SIGNAL ;
    PORT
      LAYER M4 ;
        RECT  0 44.544 0.084 44.568 ;
    END
  END b_odata[274]
  PIN b_odata[275]
    DIRECTION INPUT ;
    USE SIGNAL ;
    PORT
      LAYER M4 ;
        RECT  0 44.592 0.084 44.616 ;
    END
  END b_odata[275]
  PIN b_odata[276]
    DIRECTION INPUT ;
    USE SIGNAL ;
    PORT
      LAYER M4 ;
        RECT  0 44.64 0.084 44.664 ;
    END
  END b_odata[276]
  PIN b_odata[277]
    DIRECTION INPUT ;
    USE SIGNAL ;
    PORT
      LAYER M4 ;
        RECT  0 44.688 0.084 44.712 ;
    END
  END b_odata[277]
  PIN b_odata[278]
    DIRECTION INPUT ;
    USE SIGNAL ;
    PORT
      LAYER M4 ;
        RECT  0 44.736 0.084 44.76 ;
    END
  END b_odata[278]
  PIN b_odata[279]
    DIRECTION INPUT ;
    USE SIGNAL ;
    PORT
      LAYER M4 ;
        RECT  0 44.784 0.084 44.808 ;
    END
  END b_odata[279]
  PIN b_odata[27]
    DIRECTION INPUT ;
    USE SIGNAL ;
    PORT
      LAYER M4 ;
        RECT  0 32.688 0.084 32.712 ;
    END
  END b_odata[27]
  PIN b_odata[280]
    DIRECTION INPUT ;
    USE SIGNAL ;
    PORT
      LAYER M4 ;
        RECT  0 44.832 0.084 44.856 ;
    END
  END b_odata[280]
  PIN b_odata[281]
    DIRECTION INPUT ;
    USE SIGNAL ;
    PORT
      LAYER M4 ;
        RECT  0 44.88 0.084 44.904 ;
    END
  END b_odata[281]
  PIN b_odata[282]
    DIRECTION INPUT ;
    USE SIGNAL ;
    PORT
      LAYER M4 ;
        RECT  0 44.928 0.084 44.952 ;
    END
  END b_odata[282]
  PIN b_odata[283]
    DIRECTION INPUT ;
    USE SIGNAL ;
    PORT
      LAYER M4 ;
        RECT  0 44.976 0.084 45 ;
    END
  END b_odata[283]
  PIN b_odata[284]
    DIRECTION INPUT ;
    USE SIGNAL ;
    PORT
      LAYER M4 ;
        RECT  0 45.024 0.084 45.048 ;
    END
  END b_odata[284]
  PIN b_odata[285]
    DIRECTION INPUT ;
    USE SIGNAL ;
    PORT
      LAYER M4 ;
        RECT  0 45.072 0.084 45.096 ;
    END
  END b_odata[285]
  PIN b_odata[286]
    DIRECTION INPUT ;
    USE SIGNAL ;
    PORT
      LAYER M4 ;
        RECT  0 45.12 0.084 45.144 ;
    END
  END b_odata[286]
  PIN b_odata[287]
    DIRECTION INPUT ;
    USE SIGNAL ;
    PORT
      LAYER M4 ;
        RECT  0 45.168 0.084 45.192 ;
    END
  END b_odata[287]
  PIN b_odata[288]
    DIRECTION INPUT ;
    USE SIGNAL ;
    PORT
      LAYER M4 ;
        RECT  0 45.216 0.084 45.24 ;
    END
  END b_odata[288]
  PIN b_odata[289]
    DIRECTION INPUT ;
    USE SIGNAL ;
    PORT
      LAYER M4 ;
        RECT  0 45.264 0.084 45.288 ;
    END
  END b_odata[289]
  PIN b_odata[28]
    DIRECTION INPUT ;
    USE SIGNAL ;
    PORT
      LAYER M4 ;
        RECT  0 32.736 0.084 32.76 ;
    END
  END b_odata[28]
  PIN b_odata[290]
    DIRECTION INPUT ;
    USE SIGNAL ;
    PORT
      LAYER M4 ;
        RECT  0 45.312 0.084 45.336 ;
    END
  END b_odata[290]
  PIN b_odata[291]
    DIRECTION INPUT ;
    USE SIGNAL ;
    PORT
      LAYER M4 ;
        RECT  0 45.36 0.084 45.384 ;
    END
  END b_odata[291]
  PIN b_odata[292]
    DIRECTION INPUT ;
    USE SIGNAL ;
    PORT
      LAYER M4 ;
        RECT  0 45.408 0.084 45.432 ;
    END
  END b_odata[292]
  PIN b_odata[293]
    DIRECTION INPUT ;
    USE SIGNAL ;
    PORT
      LAYER M4 ;
        RECT  0 45.456 0.084 45.48 ;
    END
  END b_odata[293]
  PIN b_odata[294]
    DIRECTION INPUT ;
    USE SIGNAL ;
    PORT
      LAYER M4 ;
        RECT  0 45.504 0.084 45.528 ;
    END
  END b_odata[294]
  PIN b_odata[295]
    DIRECTION INPUT ;
    USE SIGNAL ;
    PORT
      LAYER M4 ;
        RECT  0 45.552 0.084 45.576 ;
    END
  END b_odata[295]
  PIN b_odata[296]
    DIRECTION INPUT ;
    USE SIGNAL ;
    PORT
      LAYER M4 ;
        RECT  0 45.6 0.084 45.624 ;
    END
  END b_odata[296]
  PIN b_odata[297]
    DIRECTION INPUT ;
    USE SIGNAL ;
    PORT
      LAYER M4 ;
        RECT  0 45.648 0.084 45.672 ;
    END
  END b_odata[297]
  PIN b_odata[298]
    DIRECTION INPUT ;
    USE SIGNAL ;
    PORT
      LAYER M4 ;
        RECT  0 45.696 0.084 45.72 ;
    END
  END b_odata[298]
  PIN b_odata[299]
    DIRECTION INPUT ;
    USE SIGNAL ;
    PORT
      LAYER M4 ;
        RECT  0 45.744 0.084 45.768 ;
    END
  END b_odata[299]
  PIN b_odata[29]
    DIRECTION INPUT ;
    USE SIGNAL ;
    PORT
      LAYER M4 ;
        RECT  0 32.784 0.084 32.808 ;
    END
  END b_odata[29]
  PIN b_odata[2]
    DIRECTION INPUT ;
    USE SIGNAL ;
    PORT
      LAYER M4 ;
        RECT  0 31.488 0.084 31.512 ;
    END
  END b_odata[2]
  PIN b_odata[300]
    DIRECTION INPUT ;
    USE SIGNAL ;
    PORT
      LAYER M4 ;
        RECT  0 45.792 0.084 45.816 ;
    END
  END b_odata[300]
  PIN b_odata[301]
    DIRECTION INPUT ;
    USE SIGNAL ;
    PORT
      LAYER M4 ;
        RECT  0 45.84 0.084 45.864 ;
    END
  END b_odata[301]
  PIN b_odata[302]
    DIRECTION INPUT ;
    USE SIGNAL ;
    PORT
      LAYER M4 ;
        RECT  0 45.888 0.084 45.912 ;
    END
  END b_odata[302]
  PIN b_odata[303]
    DIRECTION INPUT ;
    USE SIGNAL ;
    PORT
      LAYER M4 ;
        RECT  0 45.936 0.084 45.96 ;
    END
  END b_odata[303]
  PIN b_odata[304]
    DIRECTION INPUT ;
    USE SIGNAL ;
    PORT
      LAYER M4 ;
        RECT  0 45.984 0.084 46.008 ;
    END
  END b_odata[304]
  PIN b_odata[305]
    DIRECTION INPUT ;
    USE SIGNAL ;
    PORT
      LAYER M4 ;
        RECT  0 46.032 0.084 46.056 ;
    END
  END b_odata[305]
  PIN b_odata[306]
    DIRECTION INPUT ;
    USE SIGNAL ;
    PORT
      LAYER M4 ;
        RECT  0 46.08 0.084 46.104 ;
    END
  END b_odata[306]
  PIN b_odata[307]
    DIRECTION INPUT ;
    USE SIGNAL ;
    PORT
      LAYER M4 ;
        RECT  0 46.128 0.084 46.152 ;
    END
  END b_odata[307]
  PIN b_odata[308]
    DIRECTION INPUT ;
    USE SIGNAL ;
    PORT
      LAYER M4 ;
        RECT  0 46.176 0.084 46.2 ;
    END
  END b_odata[308]
  PIN b_odata[309]
    DIRECTION INPUT ;
    USE SIGNAL ;
    PORT
      LAYER M4 ;
        RECT  0 46.224 0.084 46.248 ;
    END
  END b_odata[309]
  PIN b_odata[30]
    DIRECTION INPUT ;
    USE SIGNAL ;
    PORT
      LAYER M4 ;
        RECT  0 32.832 0.084 32.856 ;
    END
  END b_odata[30]
  PIN b_odata[310]
    DIRECTION INPUT ;
    USE SIGNAL ;
    PORT
      LAYER M4 ;
        RECT  0 46.272 0.084 46.296 ;
    END
  END b_odata[310]
  PIN b_odata[311]
    DIRECTION INPUT ;
    USE SIGNAL ;
    PORT
      LAYER M4 ;
        RECT  0 46.32 0.084 46.344 ;
    END
  END b_odata[311]
  PIN b_odata[312]
    DIRECTION INPUT ;
    USE SIGNAL ;
    PORT
      LAYER M4 ;
        RECT  0 46.368 0.084 46.392 ;
    END
  END b_odata[312]
  PIN b_odata[313]
    DIRECTION INPUT ;
    USE SIGNAL ;
    PORT
      LAYER M4 ;
        RECT  0 46.416 0.084 46.44 ;
    END
  END b_odata[313]
  PIN b_odata[314]
    DIRECTION INPUT ;
    USE SIGNAL ;
    PORT
      LAYER M4 ;
        RECT  0 46.464 0.084 46.488 ;
    END
  END b_odata[314]
  PIN b_odata[315]
    DIRECTION INPUT ;
    USE SIGNAL ;
    PORT
      LAYER M4 ;
        RECT  0 46.512 0.084 46.536 ;
    END
  END b_odata[315]
  PIN b_odata[316]
    DIRECTION INPUT ;
    USE SIGNAL ;
    PORT
      LAYER M4 ;
        RECT  0 46.56 0.084 46.584 ;
    END
  END b_odata[316]
  PIN b_odata[317]
    DIRECTION INPUT ;
    USE SIGNAL ;
    PORT
      LAYER M4 ;
        RECT  0 46.608 0.084 46.632 ;
    END
  END b_odata[317]
  PIN b_odata[318]
    DIRECTION INPUT ;
    USE SIGNAL ;
    PORT
      LAYER M4 ;
        RECT  0 46.656 0.084 46.68 ;
    END
  END b_odata[318]
  PIN b_odata[319]
    DIRECTION INPUT ;
    USE SIGNAL ;
    PORT
      LAYER M4 ;
        RECT  0 46.704 0.084 46.728 ;
    END
  END b_odata[319]
  PIN b_odata[31]
    DIRECTION INPUT ;
    USE SIGNAL ;
    PORT
      LAYER M4 ;
        RECT  0 32.88 0.084 32.904 ;
    END
  END b_odata[31]
  PIN b_odata[320]
    DIRECTION INPUT ;
    USE SIGNAL ;
    PORT
      LAYER M4 ;
        RECT  0 46.752 0.084 46.776 ;
    END
  END b_odata[320]
  PIN b_odata[321]
    DIRECTION INPUT ;
    USE SIGNAL ;
    PORT
      LAYER M4 ;
        RECT  0 46.8 0.084 46.824 ;
    END
  END b_odata[321]
  PIN b_odata[322]
    DIRECTION INPUT ;
    USE SIGNAL ;
    PORT
      LAYER M4 ;
        RECT  0 46.848 0.084 46.872 ;
    END
  END b_odata[322]
  PIN b_odata[323]
    DIRECTION INPUT ;
    USE SIGNAL ;
    PORT
      LAYER M4 ;
        RECT  0 46.896 0.084 46.92 ;
    END
  END b_odata[323]
  PIN b_odata[324]
    DIRECTION INPUT ;
    USE SIGNAL ;
    PORT
      LAYER M4 ;
        RECT  0 46.944 0.084 46.968 ;
    END
  END b_odata[324]
  PIN b_odata[325]
    DIRECTION INPUT ;
    USE SIGNAL ;
    PORT
      LAYER M4 ;
        RECT  0 46.992 0.084 47.016 ;
    END
  END b_odata[325]
  PIN b_odata[326]
    DIRECTION INPUT ;
    USE SIGNAL ;
    PORT
      LAYER M4 ;
        RECT  0 47.04 0.084 47.064 ;
    END
  END b_odata[326]
  PIN b_odata[327]
    DIRECTION INPUT ;
    USE SIGNAL ;
    PORT
      LAYER M4 ;
        RECT  0 47.088 0.084 47.112 ;
    END
  END b_odata[327]
  PIN b_odata[328]
    DIRECTION INPUT ;
    USE SIGNAL ;
    PORT
      LAYER M4 ;
        RECT  0 47.136 0.084 47.16 ;
    END
  END b_odata[328]
  PIN b_odata[329]
    DIRECTION INPUT ;
    USE SIGNAL ;
    PORT
      LAYER M4 ;
        RECT  0 47.184 0.084 47.208 ;
    END
  END b_odata[329]
  PIN b_odata[32]
    DIRECTION INPUT ;
    USE SIGNAL ;
    PORT
      LAYER M4 ;
        RECT  0 32.928 0.084 32.952 ;
    END
  END b_odata[32]
  PIN b_odata[330]
    DIRECTION INPUT ;
    USE SIGNAL ;
    PORT
      LAYER M4 ;
        RECT  0 47.232 0.084 47.256 ;
    END
  END b_odata[330]
  PIN b_odata[331]
    DIRECTION INPUT ;
    USE SIGNAL ;
    PORT
      LAYER M4 ;
        RECT  0 47.28 0.084 47.304 ;
    END
  END b_odata[331]
  PIN b_odata[332]
    DIRECTION INPUT ;
    USE SIGNAL ;
    PORT
      LAYER M4 ;
        RECT  0 47.328 0.084 47.352 ;
    END
  END b_odata[332]
  PIN b_odata[333]
    DIRECTION INPUT ;
    USE SIGNAL ;
    PORT
      LAYER M4 ;
        RECT  0 47.376 0.084 47.4 ;
    END
  END b_odata[333]
  PIN b_odata[334]
    DIRECTION INPUT ;
    USE SIGNAL ;
    PORT
      LAYER M4 ;
        RECT  0 47.424 0.084 47.448 ;
    END
  END b_odata[334]
  PIN b_odata[335]
    DIRECTION INPUT ;
    USE SIGNAL ;
    PORT
      LAYER M4 ;
        RECT  0 47.472 0.084 47.496 ;
    END
  END b_odata[335]
  PIN b_odata[336]
    DIRECTION INPUT ;
    USE SIGNAL ;
    PORT
      LAYER M4 ;
        RECT  0 47.52 0.084 47.544 ;
    END
  END b_odata[336]
  PIN b_odata[337]
    DIRECTION INPUT ;
    USE SIGNAL ;
    PORT
      LAYER M4 ;
        RECT  0 47.568 0.084 47.592 ;
    END
  END b_odata[337]
  PIN b_odata[338]
    DIRECTION INPUT ;
    USE SIGNAL ;
    PORT
      LAYER M4 ;
        RECT  0 47.616 0.084 47.64 ;
    END
  END b_odata[338]
  PIN b_odata[339]
    DIRECTION INPUT ;
    USE SIGNAL ;
    PORT
      LAYER M4 ;
        RECT  0 47.664 0.084 47.688 ;
    END
  END b_odata[339]
  PIN b_odata[33]
    DIRECTION INPUT ;
    USE SIGNAL ;
    PORT
      LAYER M4 ;
        RECT  0 32.976 0.084 33 ;
    END
  END b_odata[33]
  PIN b_odata[340]
    DIRECTION INPUT ;
    USE SIGNAL ;
    PORT
      LAYER M4 ;
        RECT  0 47.712 0.084 47.736 ;
    END
  END b_odata[340]
  PIN b_odata[341]
    DIRECTION INPUT ;
    USE SIGNAL ;
    PORT
      LAYER M4 ;
        RECT  0 47.76 0.084 47.784 ;
    END
  END b_odata[341]
  PIN b_odata[342]
    DIRECTION INPUT ;
    USE SIGNAL ;
    PORT
      LAYER M4 ;
        RECT  0 47.808 0.084 47.832 ;
    END
  END b_odata[342]
  PIN b_odata[343]
    DIRECTION INPUT ;
    USE SIGNAL ;
    PORT
      LAYER M4 ;
        RECT  0 47.856 0.084 47.88 ;
    END
  END b_odata[343]
  PIN b_odata[344]
    DIRECTION INPUT ;
    USE SIGNAL ;
    PORT
      LAYER M4 ;
        RECT  0 47.904 0.084 47.928 ;
    END
  END b_odata[344]
  PIN b_odata[345]
    DIRECTION INPUT ;
    USE SIGNAL ;
    PORT
      LAYER M4 ;
        RECT  0 47.952 0.084 47.976 ;
    END
  END b_odata[345]
  PIN b_odata[346]
    DIRECTION INPUT ;
    USE SIGNAL ;
    PORT
      LAYER M4 ;
        RECT  0 48 0.084 48.024 ;
    END
  END b_odata[346]
  PIN b_odata[347]
    DIRECTION INPUT ;
    USE SIGNAL ;
    PORT
      LAYER M4 ;
        RECT  0 48.048 0.084 48.072 ;
    END
  END b_odata[347]
  PIN b_odata[348]
    DIRECTION INPUT ;
    USE SIGNAL ;
    PORT
      LAYER M4 ;
        RECT  0 48.096 0.084 48.12 ;
    END
  END b_odata[348]
  PIN b_odata[349]
    DIRECTION INPUT ;
    USE SIGNAL ;
    PORT
      LAYER M4 ;
        RECT  0 48.144 0.084 48.168 ;
    END
  END b_odata[349]
  PIN b_odata[34]
    DIRECTION INPUT ;
    USE SIGNAL ;
    PORT
      LAYER M4 ;
        RECT  0 33.024 0.084 33.048 ;
    END
  END b_odata[34]
  PIN b_odata[350]
    DIRECTION INPUT ;
    USE SIGNAL ;
    PORT
      LAYER M4 ;
        RECT  0 48.192 0.084 48.216 ;
    END
  END b_odata[350]
  PIN b_odata[351]
    DIRECTION INPUT ;
    USE SIGNAL ;
    PORT
      LAYER M4 ;
        RECT  0 48.24 0.084 48.264 ;
    END
  END b_odata[351]
  PIN b_odata[352]
    DIRECTION INPUT ;
    USE SIGNAL ;
    PORT
      LAYER M4 ;
        RECT  0 48.288 0.084 48.312 ;
    END
  END b_odata[352]
  PIN b_odata[353]
    DIRECTION INPUT ;
    USE SIGNAL ;
    PORT
      LAYER M4 ;
        RECT  0 48.336 0.084 48.36 ;
    END
  END b_odata[353]
  PIN b_odata[354]
    DIRECTION INPUT ;
    USE SIGNAL ;
    PORT
      LAYER M4 ;
        RECT  0 48.384 0.084 48.408 ;
    END
  END b_odata[354]
  PIN b_odata[355]
    DIRECTION INPUT ;
    USE SIGNAL ;
    PORT
      LAYER M4 ;
        RECT  0 48.432 0.084 48.456 ;
    END
  END b_odata[355]
  PIN b_odata[356]
    DIRECTION INPUT ;
    USE SIGNAL ;
    PORT
      LAYER M4 ;
        RECT  0 48.48 0.084 48.504 ;
    END
  END b_odata[356]
  PIN b_odata[357]
    DIRECTION INPUT ;
    USE SIGNAL ;
    PORT
      LAYER M4 ;
        RECT  0 48.528 0.084 48.552 ;
    END
  END b_odata[357]
  PIN b_odata[358]
    DIRECTION INPUT ;
    USE SIGNAL ;
    PORT
      LAYER M4 ;
        RECT  0 48.576 0.084 48.6 ;
    END
  END b_odata[358]
  PIN b_odata[359]
    DIRECTION INPUT ;
    USE SIGNAL ;
    PORT
      LAYER M4 ;
        RECT  0 48.624 0.084 48.648 ;
    END
  END b_odata[359]
  PIN b_odata[35]
    DIRECTION INPUT ;
    USE SIGNAL ;
    PORT
      LAYER M4 ;
        RECT  0 33.072 0.084 33.096 ;
    END
  END b_odata[35]
  PIN b_odata[360]
    DIRECTION INPUT ;
    USE SIGNAL ;
    PORT
      LAYER M4 ;
        RECT  0 48.672 0.084 48.696 ;
    END
  END b_odata[360]
  PIN b_odata[361]
    DIRECTION INPUT ;
    USE SIGNAL ;
    PORT
      LAYER M4 ;
        RECT  0 48.72 0.084 48.744 ;
    END
  END b_odata[361]
  PIN b_odata[362]
    DIRECTION INPUT ;
    USE SIGNAL ;
    PORT
      LAYER M4 ;
        RECT  0 48.768 0.084 48.792 ;
    END
  END b_odata[362]
  PIN b_odata[363]
    DIRECTION INPUT ;
    USE SIGNAL ;
    PORT
      LAYER M4 ;
        RECT  0 48.816 0.084 48.84 ;
    END
  END b_odata[363]
  PIN b_odata[364]
    DIRECTION INPUT ;
    USE SIGNAL ;
    PORT
      LAYER M4 ;
        RECT  0 48.864 0.084 48.888 ;
    END
  END b_odata[364]
  PIN b_odata[365]
    DIRECTION INPUT ;
    USE SIGNAL ;
    PORT
      LAYER M4 ;
        RECT  0 48.912 0.084 48.936 ;
    END
  END b_odata[365]
  PIN b_odata[366]
    DIRECTION INPUT ;
    USE SIGNAL ;
    PORT
      LAYER M4 ;
        RECT  0 48.96 0.084 48.984 ;
    END
  END b_odata[366]
  PIN b_odata[367]
    DIRECTION INPUT ;
    USE SIGNAL ;
    PORT
      LAYER M4 ;
        RECT  0 49.008 0.084 49.032 ;
    END
  END b_odata[367]
  PIN b_odata[368]
    DIRECTION INPUT ;
    USE SIGNAL ;
    PORT
      LAYER M4 ;
        RECT  0 49.056 0.084 49.08 ;
    END
  END b_odata[368]
  PIN b_odata[369]
    DIRECTION INPUT ;
    USE SIGNAL ;
    PORT
      LAYER M4 ;
        RECT  0 49.104 0.084 49.128 ;
    END
  END b_odata[369]
  PIN b_odata[36]
    DIRECTION INPUT ;
    USE SIGNAL ;
    PORT
      LAYER M4 ;
        RECT  0 33.12 0.084 33.144 ;
    END
  END b_odata[36]
  PIN b_odata[370]
    DIRECTION INPUT ;
    USE SIGNAL ;
    PORT
      LAYER M4 ;
        RECT  0 49.152 0.084 49.176 ;
    END
  END b_odata[370]
  PIN b_odata[371]
    DIRECTION INPUT ;
    USE SIGNAL ;
    PORT
      LAYER M4 ;
        RECT  0 49.2 0.084 49.224 ;
    END
  END b_odata[371]
  PIN b_odata[372]
    DIRECTION INPUT ;
    USE SIGNAL ;
    PORT
      LAYER M4 ;
        RECT  0 49.248 0.084 49.272 ;
    END
  END b_odata[372]
  PIN b_odata[373]
    DIRECTION INPUT ;
    USE SIGNAL ;
    PORT
      LAYER M4 ;
        RECT  0 49.296 0.084 49.32 ;
    END
  END b_odata[373]
  PIN b_odata[374]
    DIRECTION INPUT ;
    USE SIGNAL ;
    PORT
      LAYER M4 ;
        RECT  0 49.344 0.084 49.368 ;
    END
  END b_odata[374]
  PIN b_odata[375]
    DIRECTION INPUT ;
    USE SIGNAL ;
    PORT
      LAYER M4 ;
        RECT  0 49.392 0.084 49.416 ;
    END
  END b_odata[375]
  PIN b_odata[376]
    DIRECTION INPUT ;
    USE SIGNAL ;
    PORT
      LAYER M4 ;
        RECT  0 49.44 0.084 49.464 ;
    END
  END b_odata[376]
  PIN b_odata[377]
    DIRECTION INPUT ;
    USE SIGNAL ;
    PORT
      LAYER M4 ;
        RECT  0 49.488 0.084 49.512 ;
    END
  END b_odata[377]
  PIN b_odata[378]
    DIRECTION INPUT ;
    USE SIGNAL ;
    PORT
      LAYER M4 ;
        RECT  0 49.536 0.084 49.56 ;
    END
  END b_odata[378]
  PIN b_odata[379]
    DIRECTION INPUT ;
    USE SIGNAL ;
    PORT
      LAYER M4 ;
        RECT  0 49.584 0.084 49.608 ;
    END
  END b_odata[379]
  PIN b_odata[37]
    DIRECTION INPUT ;
    USE SIGNAL ;
    PORT
      LAYER M4 ;
        RECT  0 33.168 0.084 33.192 ;
    END
  END b_odata[37]
  PIN b_odata[380]
    DIRECTION INPUT ;
    USE SIGNAL ;
    PORT
      LAYER M4 ;
        RECT  0 49.632 0.084 49.656 ;
    END
  END b_odata[380]
  PIN b_odata[381]
    DIRECTION INPUT ;
    USE SIGNAL ;
    PORT
      LAYER M4 ;
        RECT  0 49.68 0.084 49.704 ;
    END
  END b_odata[381]
  PIN b_odata[382]
    DIRECTION INPUT ;
    USE SIGNAL ;
    PORT
      LAYER M4 ;
        RECT  0 49.728 0.084 49.752 ;
    END
  END b_odata[382]
  PIN b_odata[383]
    DIRECTION INPUT ;
    USE SIGNAL ;
    PORT
      LAYER M4 ;
        RECT  0 49.776 0.084 49.8 ;
    END
  END b_odata[383]
  PIN b_odata[384]
    DIRECTION INPUT ;
    USE SIGNAL ;
    PORT
      LAYER M4 ;
        RECT  0 49.824 0.084 49.848 ;
    END
  END b_odata[384]
  PIN b_odata[385]
    DIRECTION INPUT ;
    USE SIGNAL ;
    PORT
      LAYER M4 ;
        RECT  0 49.872 0.084 49.896 ;
    END
  END b_odata[385]
  PIN b_odata[386]
    DIRECTION INPUT ;
    USE SIGNAL ;
    PORT
      LAYER M4 ;
        RECT  0 49.92 0.084 49.944 ;
    END
  END b_odata[386]
  PIN b_odata[387]
    DIRECTION INPUT ;
    USE SIGNAL ;
    PORT
      LAYER M4 ;
        RECT  0 49.968 0.084 49.992 ;
    END
  END b_odata[387]
  PIN b_odata[388]
    DIRECTION INPUT ;
    USE SIGNAL ;
    PORT
      LAYER M4 ;
        RECT  0 50.016 0.084 50.04 ;
    END
  END b_odata[388]
  PIN b_odata[389]
    DIRECTION INPUT ;
    USE SIGNAL ;
    PORT
      LAYER M4 ;
        RECT  0 50.064 0.084 50.088 ;
    END
  END b_odata[389]
  PIN b_odata[38]
    DIRECTION INPUT ;
    USE SIGNAL ;
    PORT
      LAYER M4 ;
        RECT  0 33.216 0.084 33.24 ;
    END
  END b_odata[38]
  PIN b_odata[390]
    DIRECTION INPUT ;
    USE SIGNAL ;
    PORT
      LAYER M4 ;
        RECT  0 50.112 0.084 50.136 ;
    END
  END b_odata[390]
  PIN b_odata[391]
    DIRECTION INPUT ;
    USE SIGNAL ;
    PORT
      LAYER M4 ;
        RECT  0 50.16 0.084 50.184 ;
    END
  END b_odata[391]
  PIN b_odata[392]
    DIRECTION INPUT ;
    USE SIGNAL ;
    PORT
      LAYER M4 ;
        RECT  0 50.208 0.084 50.232 ;
    END
  END b_odata[392]
  PIN b_odata[393]
    DIRECTION INPUT ;
    USE SIGNAL ;
    PORT
      LAYER M4 ;
        RECT  0 50.256 0.084 50.28 ;
    END
  END b_odata[393]
  PIN b_odata[394]
    DIRECTION INPUT ;
    USE SIGNAL ;
    PORT
      LAYER M4 ;
        RECT  0 50.304 0.084 50.328 ;
    END
  END b_odata[394]
  PIN b_odata[395]
    DIRECTION INPUT ;
    USE SIGNAL ;
    PORT
      LAYER M4 ;
        RECT  0 50.352 0.084 50.376 ;
    END
  END b_odata[395]
  PIN b_odata[396]
    DIRECTION INPUT ;
    USE SIGNAL ;
    PORT
      LAYER M4 ;
        RECT  0 50.4 0.084 50.424 ;
    END
  END b_odata[396]
  PIN b_odata[397]
    DIRECTION INPUT ;
    USE SIGNAL ;
    PORT
      LAYER M4 ;
        RECT  0 50.448 0.084 50.472 ;
    END
  END b_odata[397]
  PIN b_odata[398]
    DIRECTION INPUT ;
    USE SIGNAL ;
    PORT
      LAYER M4 ;
        RECT  0 50.496 0.084 50.52 ;
    END
  END b_odata[398]
  PIN b_odata[399]
    DIRECTION INPUT ;
    USE SIGNAL ;
    PORT
      LAYER M4 ;
        RECT  0 50.544 0.084 50.568 ;
    END
  END b_odata[399]
  PIN b_odata[39]
    DIRECTION INPUT ;
    USE SIGNAL ;
    PORT
      LAYER M4 ;
        RECT  0 33.264 0.084 33.288 ;
    END
  END b_odata[39]
  PIN b_odata[3]
    DIRECTION INPUT ;
    USE SIGNAL ;
    PORT
      LAYER M4 ;
        RECT  0 31.536 0.084 31.56 ;
    END
  END b_odata[3]
  PIN b_odata[400]
    DIRECTION INPUT ;
    USE SIGNAL ;
    PORT
      LAYER M4 ;
        RECT  0 50.592 0.084 50.616 ;
    END
  END b_odata[400]
  PIN b_odata[401]
    DIRECTION INPUT ;
    USE SIGNAL ;
    PORT
      LAYER M4 ;
        RECT  0 50.64 0.084 50.664 ;
    END
  END b_odata[401]
  PIN b_odata[402]
    DIRECTION INPUT ;
    USE SIGNAL ;
    PORT
      LAYER M4 ;
        RECT  0 50.688 0.084 50.712 ;
    END
  END b_odata[402]
  PIN b_odata[403]
    DIRECTION INPUT ;
    USE SIGNAL ;
    PORT
      LAYER M4 ;
        RECT  0 50.736 0.084 50.76 ;
    END
  END b_odata[403]
  PIN b_odata[404]
    DIRECTION INPUT ;
    USE SIGNAL ;
    PORT
      LAYER M4 ;
        RECT  0 50.784 0.084 50.808 ;
    END
  END b_odata[404]
  PIN b_odata[405]
    DIRECTION INPUT ;
    USE SIGNAL ;
    PORT
      LAYER M4 ;
        RECT  0 50.832 0.084 50.856 ;
    END
  END b_odata[405]
  PIN b_odata[406]
    DIRECTION INPUT ;
    USE SIGNAL ;
    PORT
      LAYER M4 ;
        RECT  0 50.88 0.084 50.904 ;
    END
  END b_odata[406]
  PIN b_odata[407]
    DIRECTION INPUT ;
    USE SIGNAL ;
    PORT
      LAYER M4 ;
        RECT  0 50.928 0.084 50.952 ;
    END
  END b_odata[407]
  PIN b_odata[408]
    DIRECTION INPUT ;
    USE SIGNAL ;
    PORT
      LAYER M4 ;
        RECT  0 50.976 0.084 51 ;
    END
  END b_odata[408]
  PIN b_odata[409]
    DIRECTION INPUT ;
    USE SIGNAL ;
    PORT
      LAYER M4 ;
        RECT  0 51.024 0.084 51.048 ;
    END
  END b_odata[409]
  PIN b_odata[40]
    DIRECTION INPUT ;
    USE SIGNAL ;
    PORT
      LAYER M4 ;
        RECT  0 33.312 0.084 33.336 ;
    END
  END b_odata[40]
  PIN b_odata[410]
    DIRECTION INPUT ;
    USE SIGNAL ;
    PORT
      LAYER M4 ;
        RECT  0 51.072 0.084 51.096 ;
    END
  END b_odata[410]
  PIN b_odata[411]
    DIRECTION INPUT ;
    USE SIGNAL ;
    PORT
      LAYER M4 ;
        RECT  0 51.12 0.084 51.144 ;
    END
  END b_odata[411]
  PIN b_odata[412]
    DIRECTION INPUT ;
    USE SIGNAL ;
    PORT
      LAYER M4 ;
        RECT  0 51.168 0.084 51.192 ;
    END
  END b_odata[412]
  PIN b_odata[413]
    DIRECTION INPUT ;
    USE SIGNAL ;
    PORT
      LAYER M4 ;
        RECT  0 51.216 0.084 51.24 ;
    END
  END b_odata[413]
  PIN b_odata[414]
    DIRECTION INPUT ;
    USE SIGNAL ;
    PORT
      LAYER M4 ;
        RECT  0 51.264 0.084 51.288 ;
    END
  END b_odata[414]
  PIN b_odata[415]
    DIRECTION INPUT ;
    USE SIGNAL ;
    PORT
      LAYER M4 ;
        RECT  0 51.312 0.084 51.336 ;
    END
  END b_odata[415]
  PIN b_odata[416]
    DIRECTION INPUT ;
    USE SIGNAL ;
    PORT
      LAYER M4 ;
        RECT  0 51.36 0.084 51.384 ;
    END
  END b_odata[416]
  PIN b_odata[417]
    DIRECTION INPUT ;
    USE SIGNAL ;
    PORT
      LAYER M4 ;
        RECT  0 51.408 0.084 51.432 ;
    END
  END b_odata[417]
  PIN b_odata[418]
    DIRECTION INPUT ;
    USE SIGNAL ;
    PORT
      LAYER M4 ;
        RECT  0 51.456 0.084 51.48 ;
    END
  END b_odata[418]
  PIN b_odata[419]
    DIRECTION INPUT ;
    USE SIGNAL ;
    PORT
      LAYER M4 ;
        RECT  0 51.504 0.084 51.528 ;
    END
  END b_odata[419]
  PIN b_odata[41]
    DIRECTION INPUT ;
    USE SIGNAL ;
    PORT
      LAYER M4 ;
        RECT  0 33.36 0.084 33.384 ;
    END
  END b_odata[41]
  PIN b_odata[420]
    DIRECTION INPUT ;
    USE SIGNAL ;
    PORT
      LAYER M4 ;
        RECT  0 51.552 0.084 51.576 ;
    END
  END b_odata[420]
  PIN b_odata[421]
    DIRECTION INPUT ;
    USE SIGNAL ;
    PORT
      LAYER M4 ;
        RECT  0 51.6 0.084 51.624 ;
    END
  END b_odata[421]
  PIN b_odata[422]
    DIRECTION INPUT ;
    USE SIGNAL ;
    PORT
      LAYER M4 ;
        RECT  0 51.648 0.084 51.672 ;
    END
  END b_odata[422]
  PIN b_odata[423]
    DIRECTION INPUT ;
    USE SIGNAL ;
    PORT
      LAYER M4 ;
        RECT  0 51.696 0.084 51.72 ;
    END
  END b_odata[423]
  PIN b_odata[424]
    DIRECTION INPUT ;
    USE SIGNAL ;
    PORT
      LAYER M4 ;
        RECT  0 51.744 0.084 51.768 ;
    END
  END b_odata[424]
  PIN b_odata[425]
    DIRECTION INPUT ;
    USE SIGNAL ;
    PORT
      LAYER M4 ;
        RECT  0 51.792 0.084 51.816 ;
    END
  END b_odata[425]
  PIN b_odata[426]
    DIRECTION INPUT ;
    USE SIGNAL ;
    PORT
      LAYER M4 ;
        RECT  0 51.84 0.084 51.864 ;
    END
  END b_odata[426]
  PIN b_odata[427]
    DIRECTION INPUT ;
    USE SIGNAL ;
    PORT
      LAYER M4 ;
        RECT  0 51.888 0.084 51.912 ;
    END
  END b_odata[427]
  PIN b_odata[428]
    DIRECTION INPUT ;
    USE SIGNAL ;
    PORT
      LAYER M4 ;
        RECT  0 51.936 0.084 51.96 ;
    END
  END b_odata[428]
  PIN b_odata[429]
    DIRECTION INPUT ;
    USE SIGNAL ;
    PORT
      LAYER M4 ;
        RECT  0 51.984 0.084 52.008 ;
    END
  END b_odata[429]
  PIN b_odata[42]
    DIRECTION INPUT ;
    USE SIGNAL ;
    PORT
      LAYER M4 ;
        RECT  0 33.408 0.084 33.432 ;
    END
  END b_odata[42]
  PIN b_odata[430]
    DIRECTION INPUT ;
    USE SIGNAL ;
    PORT
      LAYER M4 ;
        RECT  0 52.032 0.084 52.056 ;
    END
  END b_odata[430]
  PIN b_odata[431]
    DIRECTION INPUT ;
    USE SIGNAL ;
    PORT
      LAYER M4 ;
        RECT  0 52.08 0.084 52.104 ;
    END
  END b_odata[431]
  PIN b_odata[432]
    DIRECTION INPUT ;
    USE SIGNAL ;
    PORT
      LAYER M4 ;
        RECT  0 52.128 0.084 52.152 ;
    END
  END b_odata[432]
  PIN b_odata[433]
    DIRECTION INPUT ;
    USE SIGNAL ;
    PORT
      LAYER M4 ;
        RECT  0 52.176 0.084 52.2 ;
    END
  END b_odata[433]
  PIN b_odata[434]
    DIRECTION INPUT ;
    USE SIGNAL ;
    PORT
      LAYER M4 ;
        RECT  0 52.224 0.084 52.248 ;
    END
  END b_odata[434]
  PIN b_odata[435]
    DIRECTION INPUT ;
    USE SIGNAL ;
    PORT
      LAYER M4 ;
        RECT  0 52.272 0.084 52.296 ;
    END
  END b_odata[435]
  PIN b_odata[436]
    DIRECTION INPUT ;
    USE SIGNAL ;
    PORT
      LAYER M4 ;
        RECT  0 52.32 0.084 52.344 ;
    END
  END b_odata[436]
  PIN b_odata[437]
    DIRECTION INPUT ;
    USE SIGNAL ;
    PORT
      LAYER M4 ;
        RECT  0 52.368 0.084 52.392 ;
    END
  END b_odata[437]
  PIN b_odata[438]
    DIRECTION INPUT ;
    USE SIGNAL ;
    PORT
      LAYER M4 ;
        RECT  0 52.416 0.084 52.44 ;
    END
  END b_odata[438]
  PIN b_odata[439]
    DIRECTION INPUT ;
    USE SIGNAL ;
    PORT
      LAYER M4 ;
        RECT  0 52.464 0.084 52.488 ;
    END
  END b_odata[439]
  PIN b_odata[43]
    DIRECTION INPUT ;
    USE SIGNAL ;
    PORT
      LAYER M4 ;
        RECT  0 33.456 0.084 33.48 ;
    END
  END b_odata[43]
  PIN b_odata[440]
    DIRECTION INPUT ;
    USE SIGNAL ;
    PORT
      LAYER M4 ;
        RECT  0 52.512 0.084 52.536 ;
    END
  END b_odata[440]
  PIN b_odata[441]
    DIRECTION INPUT ;
    USE SIGNAL ;
    PORT
      LAYER M4 ;
        RECT  0 52.56 0.084 52.584 ;
    END
  END b_odata[441]
  PIN b_odata[442]
    DIRECTION INPUT ;
    USE SIGNAL ;
    PORT
      LAYER M4 ;
        RECT  0 52.608 0.084 52.632 ;
    END
  END b_odata[442]
  PIN b_odata[443]
    DIRECTION INPUT ;
    USE SIGNAL ;
    PORT
      LAYER M4 ;
        RECT  0 52.656 0.084 52.68 ;
    END
  END b_odata[443]
  PIN b_odata[444]
    DIRECTION INPUT ;
    USE SIGNAL ;
    PORT
      LAYER M4 ;
        RECT  0 52.704 0.084 52.728 ;
    END
  END b_odata[444]
  PIN b_odata[445]
    DIRECTION INPUT ;
    USE SIGNAL ;
    PORT
      LAYER M4 ;
        RECT  0 52.752 0.084 52.776 ;
    END
  END b_odata[445]
  PIN b_odata[446]
    DIRECTION INPUT ;
    USE SIGNAL ;
    PORT
      LAYER M4 ;
        RECT  0 52.8 0.084 52.824 ;
    END
  END b_odata[446]
  PIN b_odata[447]
    DIRECTION INPUT ;
    USE SIGNAL ;
    PORT
      LAYER M4 ;
        RECT  0 52.848 0.084 52.872 ;
    END
  END b_odata[447]
  PIN b_odata[448]
    DIRECTION INPUT ;
    USE SIGNAL ;
    PORT
      LAYER M4 ;
        RECT  0 52.896 0.084 52.92 ;
    END
  END b_odata[448]
  PIN b_odata[449]
    DIRECTION INPUT ;
    USE SIGNAL ;
    PORT
      LAYER M4 ;
        RECT  0 52.944 0.084 52.968 ;
    END
  END b_odata[449]
  PIN b_odata[44]
    DIRECTION INPUT ;
    USE SIGNAL ;
    PORT
      LAYER M4 ;
        RECT  0 33.504 0.084 33.528 ;
    END
  END b_odata[44]
  PIN b_odata[450]
    DIRECTION INPUT ;
    USE SIGNAL ;
    PORT
      LAYER M4 ;
        RECT  0 52.992 0.084 53.016 ;
    END
  END b_odata[450]
  PIN b_odata[451]
    DIRECTION INPUT ;
    USE SIGNAL ;
    PORT
      LAYER M4 ;
        RECT  0 53.04 0.084 53.064 ;
    END
  END b_odata[451]
  PIN b_odata[452]
    DIRECTION INPUT ;
    USE SIGNAL ;
    PORT
      LAYER M4 ;
        RECT  0 53.088 0.084 53.112 ;
    END
  END b_odata[452]
  PIN b_odata[453]
    DIRECTION INPUT ;
    USE SIGNAL ;
    PORT
      LAYER M4 ;
        RECT  0 53.136 0.084 53.16 ;
    END
  END b_odata[453]
  PIN b_odata[454]
    DIRECTION INPUT ;
    USE SIGNAL ;
    PORT
      LAYER M4 ;
        RECT  0 53.184 0.084 53.208 ;
    END
  END b_odata[454]
  PIN b_odata[455]
    DIRECTION INPUT ;
    USE SIGNAL ;
    PORT
      LAYER M4 ;
        RECT  0 53.232 0.084 53.256 ;
    END
  END b_odata[455]
  PIN b_odata[456]
    DIRECTION INPUT ;
    USE SIGNAL ;
    PORT
      LAYER M4 ;
        RECT  0 53.28 0.084 53.304 ;
    END
  END b_odata[456]
  PIN b_odata[457]
    DIRECTION INPUT ;
    USE SIGNAL ;
    PORT
      LAYER M4 ;
        RECT  0 53.328 0.084 53.352 ;
    END
  END b_odata[457]
  PIN b_odata[458]
    DIRECTION INPUT ;
    USE SIGNAL ;
    PORT
      LAYER M4 ;
        RECT  0 53.376 0.084 53.4 ;
    END
  END b_odata[458]
  PIN b_odata[459]
    DIRECTION INPUT ;
    USE SIGNAL ;
    PORT
      LAYER M4 ;
        RECT  0 53.424 0.084 53.448 ;
    END
  END b_odata[459]
  PIN b_odata[45]
    DIRECTION INPUT ;
    USE SIGNAL ;
    PORT
      LAYER M4 ;
        RECT  0 33.552 0.084 33.576 ;
    END
  END b_odata[45]
  PIN b_odata[460]
    DIRECTION INPUT ;
    USE SIGNAL ;
    PORT
      LAYER M4 ;
        RECT  0 53.472 0.084 53.496 ;
    END
  END b_odata[460]
  PIN b_odata[461]
    DIRECTION INPUT ;
    USE SIGNAL ;
    PORT
      LAYER M4 ;
        RECT  0 53.52 0.084 53.544 ;
    END
  END b_odata[461]
  PIN b_odata[462]
    DIRECTION INPUT ;
    USE SIGNAL ;
    PORT
      LAYER M4 ;
        RECT  0 53.568 0.084 53.592 ;
    END
  END b_odata[462]
  PIN b_odata[463]
    DIRECTION INPUT ;
    USE SIGNAL ;
    PORT
      LAYER M4 ;
        RECT  0 53.616 0.084 53.64 ;
    END
  END b_odata[463]
  PIN b_odata[464]
    DIRECTION INPUT ;
    USE SIGNAL ;
    PORT
      LAYER M4 ;
        RECT  0 53.664 0.084 53.688 ;
    END
  END b_odata[464]
  PIN b_odata[465]
    DIRECTION INPUT ;
    USE SIGNAL ;
    PORT
      LAYER M4 ;
        RECT  0 53.712 0.084 53.736 ;
    END
  END b_odata[465]
  PIN b_odata[466]
    DIRECTION INPUT ;
    USE SIGNAL ;
    PORT
      LAYER M4 ;
        RECT  0 53.76 0.084 53.784 ;
    END
  END b_odata[466]
  PIN b_odata[467]
    DIRECTION INPUT ;
    USE SIGNAL ;
    PORT
      LAYER M4 ;
        RECT  0 53.808 0.084 53.832 ;
    END
  END b_odata[467]
  PIN b_odata[468]
    DIRECTION INPUT ;
    USE SIGNAL ;
    PORT
      LAYER M4 ;
        RECT  0 53.856 0.084 53.88 ;
    END
  END b_odata[468]
  PIN b_odata[469]
    DIRECTION INPUT ;
    USE SIGNAL ;
    PORT
      LAYER M4 ;
        RECT  0 53.904 0.084 53.928 ;
    END
  END b_odata[469]
  PIN b_odata[46]
    DIRECTION INPUT ;
    USE SIGNAL ;
    PORT
      LAYER M4 ;
        RECT  0 33.6 0.084 33.624 ;
    END
  END b_odata[46]
  PIN b_odata[470]
    DIRECTION INPUT ;
    USE SIGNAL ;
    PORT
      LAYER M4 ;
        RECT  0 53.952 0.084 53.976 ;
    END
  END b_odata[470]
  PIN b_odata[471]
    DIRECTION INPUT ;
    USE SIGNAL ;
    PORT
      LAYER M4 ;
        RECT  0 54 0.084 54.024 ;
    END
  END b_odata[471]
  PIN b_odata[472]
    DIRECTION INPUT ;
    USE SIGNAL ;
    PORT
      LAYER M4 ;
        RECT  0 54.048 0.084 54.072 ;
    END
  END b_odata[472]
  PIN b_odata[473]
    DIRECTION INPUT ;
    USE SIGNAL ;
    PORT
      LAYER M4 ;
        RECT  0 54.096 0.084 54.12 ;
    END
  END b_odata[473]
  PIN b_odata[474]
    DIRECTION INPUT ;
    USE SIGNAL ;
    PORT
      LAYER M4 ;
        RECT  0 54.144 0.084 54.168 ;
    END
  END b_odata[474]
  PIN b_odata[475]
    DIRECTION INPUT ;
    USE SIGNAL ;
    PORT
      LAYER M4 ;
        RECT  0 54.192 0.084 54.216 ;
    END
  END b_odata[475]
  PIN b_odata[476]
    DIRECTION INPUT ;
    USE SIGNAL ;
    PORT
      LAYER M4 ;
        RECT  0 54.24 0.084 54.264 ;
    END
  END b_odata[476]
  PIN b_odata[477]
    DIRECTION INPUT ;
    USE SIGNAL ;
    PORT
      LAYER M4 ;
        RECT  0 54.288 0.084 54.312 ;
    END
  END b_odata[477]
  PIN b_odata[478]
    DIRECTION INPUT ;
    USE SIGNAL ;
    PORT
      LAYER M4 ;
        RECT  0 54.336 0.084 54.36 ;
    END
  END b_odata[478]
  PIN b_odata[479]
    DIRECTION INPUT ;
    USE SIGNAL ;
    PORT
      LAYER M4 ;
        RECT  0 54.384 0.084 54.408 ;
    END
  END b_odata[479]
  PIN b_odata[47]
    DIRECTION INPUT ;
    USE SIGNAL ;
    PORT
      LAYER M4 ;
        RECT  0 33.648 0.084 33.672 ;
    END
  END b_odata[47]
  PIN b_odata[480]
    DIRECTION INPUT ;
    USE SIGNAL ;
    PORT
      LAYER M4 ;
        RECT  0 54.432 0.084 54.456 ;
    END
  END b_odata[480]
  PIN b_odata[481]
    DIRECTION INPUT ;
    USE SIGNAL ;
    PORT
      LAYER M4 ;
        RECT  0 54.48 0.084 54.504 ;
    END
  END b_odata[481]
  PIN b_odata[482]
    DIRECTION INPUT ;
    USE SIGNAL ;
    PORT
      LAYER M4 ;
        RECT  0 54.528 0.084 54.552 ;
    END
  END b_odata[482]
  PIN b_odata[483]
    DIRECTION INPUT ;
    USE SIGNAL ;
    PORT
      LAYER M4 ;
        RECT  0 54.576 0.084 54.6 ;
    END
  END b_odata[483]
  PIN b_odata[484]
    DIRECTION INPUT ;
    USE SIGNAL ;
    PORT
      LAYER M4 ;
        RECT  0 54.624 0.084 54.648 ;
    END
  END b_odata[484]
  PIN b_odata[485]
    DIRECTION INPUT ;
    USE SIGNAL ;
    PORT
      LAYER M4 ;
        RECT  0 54.672 0.084 54.696 ;
    END
  END b_odata[485]
  PIN b_odata[486]
    DIRECTION INPUT ;
    USE SIGNAL ;
    PORT
      LAYER M4 ;
        RECT  0 54.72 0.084 54.744 ;
    END
  END b_odata[486]
  PIN b_odata[487]
    DIRECTION INPUT ;
    USE SIGNAL ;
    PORT
      LAYER M4 ;
        RECT  0 54.768 0.084 54.792 ;
    END
  END b_odata[487]
  PIN b_odata[488]
    DIRECTION INPUT ;
    USE SIGNAL ;
    PORT
      LAYER M4 ;
        RECT  0 54.816 0.084 54.84 ;
    END
  END b_odata[488]
  PIN b_odata[489]
    DIRECTION INPUT ;
    USE SIGNAL ;
    PORT
      LAYER M4 ;
        RECT  0 54.864 0.084 54.888 ;
    END
  END b_odata[489]
  PIN b_odata[48]
    DIRECTION INPUT ;
    USE SIGNAL ;
    PORT
      LAYER M4 ;
        RECT  0 33.696 0.084 33.72 ;
    END
  END b_odata[48]
  PIN b_odata[490]
    DIRECTION INPUT ;
    USE SIGNAL ;
    PORT
      LAYER M4 ;
        RECT  0 54.912 0.084 54.936 ;
    END
  END b_odata[490]
  PIN b_odata[491]
    DIRECTION INPUT ;
    USE SIGNAL ;
    PORT
      LAYER M4 ;
        RECT  0 54.96 0.084 54.984 ;
    END
  END b_odata[491]
  PIN b_odata[492]
    DIRECTION INPUT ;
    USE SIGNAL ;
    PORT
      LAYER M4 ;
        RECT  0 55.008 0.084 55.032 ;
    END
  END b_odata[492]
  PIN b_odata[493]
    DIRECTION INPUT ;
    USE SIGNAL ;
    PORT
      LAYER M4 ;
        RECT  0 55.056 0.084 55.08 ;
    END
  END b_odata[493]
  PIN b_odata[494]
    DIRECTION INPUT ;
    USE SIGNAL ;
    PORT
      LAYER M4 ;
        RECT  0 55.104 0.084 55.128 ;
    END
  END b_odata[494]
  PIN b_odata[495]
    DIRECTION INPUT ;
    USE SIGNAL ;
    PORT
      LAYER M4 ;
        RECT  0 55.152 0.084 55.176 ;
    END
  END b_odata[495]
  PIN b_odata[496]
    DIRECTION INPUT ;
    USE SIGNAL ;
    PORT
      LAYER M4 ;
        RECT  0 55.2 0.084 55.224 ;
    END
  END b_odata[496]
  PIN b_odata[497]
    DIRECTION INPUT ;
    USE SIGNAL ;
    PORT
      LAYER M4 ;
        RECT  0 55.248 0.084 55.272 ;
    END
  END b_odata[497]
  PIN b_odata[498]
    DIRECTION INPUT ;
    USE SIGNAL ;
    PORT
      LAYER M4 ;
        RECT  0 55.296 0.084 55.32 ;
    END
  END b_odata[498]
  PIN b_odata[499]
    DIRECTION INPUT ;
    USE SIGNAL ;
    PORT
      LAYER M4 ;
        RECT  0 55.344 0.084 55.368 ;
    END
  END b_odata[499]
  PIN b_odata[49]
    DIRECTION INPUT ;
    USE SIGNAL ;
    PORT
      LAYER M4 ;
        RECT  0 33.744 0.084 33.768 ;
    END
  END b_odata[49]
  PIN b_odata[4]
    DIRECTION INPUT ;
    USE SIGNAL ;
    PORT
      LAYER M4 ;
        RECT  0 31.584 0.084 31.608 ;
    END
  END b_odata[4]
  PIN b_odata[500]
    DIRECTION INPUT ;
    USE SIGNAL ;
    PORT
      LAYER M4 ;
        RECT  0 55.392 0.084 55.416 ;
    END
  END b_odata[500]
  PIN b_odata[501]
    DIRECTION INPUT ;
    USE SIGNAL ;
    PORT
      LAYER M4 ;
        RECT  0 55.44 0.084 55.464 ;
    END
  END b_odata[501]
  PIN b_odata[502]
    DIRECTION INPUT ;
    USE SIGNAL ;
    PORT
      LAYER M4 ;
        RECT  0 55.488 0.084 55.512 ;
    END
  END b_odata[502]
  PIN b_odata[503]
    DIRECTION INPUT ;
    USE SIGNAL ;
    PORT
      LAYER M4 ;
        RECT  0 55.536 0.084 55.56 ;
    END
  END b_odata[503]
  PIN b_odata[504]
    DIRECTION INPUT ;
    USE SIGNAL ;
    PORT
      LAYER M4 ;
        RECT  0 55.584 0.084 55.608 ;
    END
  END b_odata[504]
  PIN b_odata[505]
    DIRECTION INPUT ;
    USE SIGNAL ;
    PORT
      LAYER M4 ;
        RECT  0 55.632 0.084 55.656 ;
    END
  END b_odata[505]
  PIN b_odata[506]
    DIRECTION INPUT ;
    USE SIGNAL ;
    PORT
      LAYER M4 ;
        RECT  0 55.68 0.084 55.704 ;
    END
  END b_odata[506]
  PIN b_odata[507]
    DIRECTION INPUT ;
    USE SIGNAL ;
    PORT
      LAYER M4 ;
        RECT  0 55.728 0.084 55.752 ;
    END
  END b_odata[507]
  PIN b_odata[508]
    DIRECTION INPUT ;
    USE SIGNAL ;
    PORT
      LAYER M4 ;
        RECT  0 55.776 0.084 55.8 ;
    END
  END b_odata[508]
  PIN b_odata[509]
    DIRECTION INPUT ;
    USE SIGNAL ;
    PORT
      LAYER M4 ;
        RECT  0 55.824 0.084 55.848 ;
    END
  END b_odata[509]
  PIN b_odata[50]
    DIRECTION INPUT ;
    USE SIGNAL ;
    PORT
      LAYER M4 ;
        RECT  0 33.792 0.084 33.816 ;
    END
  END b_odata[50]
  PIN b_odata[510]
    DIRECTION INPUT ;
    USE SIGNAL ;
    PORT
      LAYER M4 ;
        RECT  0 55.872 0.084 55.896 ;
    END
  END b_odata[510]
  PIN b_odata[511]
    DIRECTION INPUT ;
    USE SIGNAL ;
    PORT
      LAYER M4 ;
        RECT  0 55.92 0.084 55.944 ;
    END
  END b_odata[511]
  PIN b_odata[51]
    DIRECTION INPUT ;
    USE SIGNAL ;
    PORT
      LAYER M4 ;
        RECT  0 33.84 0.084 33.864 ;
    END
  END b_odata[51]
  PIN b_odata[52]
    DIRECTION INPUT ;
    USE SIGNAL ;
    PORT
      LAYER M4 ;
        RECT  0 33.888 0.084 33.912 ;
    END
  END b_odata[52]
  PIN b_odata[53]
    DIRECTION INPUT ;
    USE SIGNAL ;
    PORT
      LAYER M4 ;
        RECT  0 33.936 0.084 33.96 ;
    END
  END b_odata[53]
  PIN b_odata[54]
    DIRECTION INPUT ;
    USE SIGNAL ;
    PORT
      LAYER M4 ;
        RECT  0 33.984 0.084 34.008 ;
    END
  END b_odata[54]
  PIN b_odata[55]
    DIRECTION INPUT ;
    USE SIGNAL ;
    PORT
      LAYER M4 ;
        RECT  0 34.032 0.084 34.056 ;
    END
  END b_odata[55]
  PIN b_odata[56]
    DIRECTION INPUT ;
    USE SIGNAL ;
    PORT
      LAYER M4 ;
        RECT  0 34.08 0.084 34.104 ;
    END
  END b_odata[56]
  PIN b_odata[57]
    DIRECTION INPUT ;
    USE SIGNAL ;
    PORT
      LAYER M4 ;
        RECT  0 34.128 0.084 34.152 ;
    END
  END b_odata[57]
  PIN b_odata[58]
    DIRECTION INPUT ;
    USE SIGNAL ;
    PORT
      LAYER M4 ;
        RECT  0 34.176 0.084 34.2 ;
    END
  END b_odata[58]
  PIN b_odata[59]
    DIRECTION INPUT ;
    USE SIGNAL ;
    PORT
      LAYER M4 ;
        RECT  0 34.224 0.084 34.248 ;
    END
  END b_odata[59]
  PIN b_odata[5]
    DIRECTION INPUT ;
    USE SIGNAL ;
    PORT
      LAYER M4 ;
        RECT  0 31.632 0.084 31.656 ;
    END
  END b_odata[5]
  PIN b_odata[60]
    DIRECTION INPUT ;
    USE SIGNAL ;
    PORT
      LAYER M4 ;
        RECT  0 34.272 0.084 34.296 ;
    END
  END b_odata[60]
  PIN b_odata[61]
    DIRECTION INPUT ;
    USE SIGNAL ;
    PORT
      LAYER M4 ;
        RECT  0 34.32 0.084 34.344 ;
    END
  END b_odata[61]
  PIN b_odata[62]
    DIRECTION INPUT ;
    USE SIGNAL ;
    PORT
      LAYER M4 ;
        RECT  0 34.368 0.084 34.392 ;
    END
  END b_odata[62]
  PIN b_odata[63]
    DIRECTION INPUT ;
    USE SIGNAL ;
    PORT
      LAYER M4 ;
        RECT  0 34.416 0.084 34.44 ;
    END
  END b_odata[63]
  PIN b_odata[64]
    DIRECTION INPUT ;
    USE SIGNAL ;
    PORT
      LAYER M4 ;
        RECT  0 34.464 0.084 34.488 ;
    END
  END b_odata[64]
  PIN b_odata[65]
    DIRECTION INPUT ;
    USE SIGNAL ;
    PORT
      LAYER M4 ;
        RECT  0 34.512 0.084 34.536 ;
    END
  END b_odata[65]
  PIN b_odata[66]
    DIRECTION INPUT ;
    USE SIGNAL ;
    PORT
      LAYER M4 ;
        RECT  0 34.56 0.084 34.584 ;
    END
  END b_odata[66]
  PIN b_odata[67]
    DIRECTION INPUT ;
    USE SIGNAL ;
    PORT
      LAYER M4 ;
        RECT  0 34.608 0.084 34.632 ;
    END
  END b_odata[67]
  PIN b_odata[68]
    DIRECTION INPUT ;
    USE SIGNAL ;
    PORT
      LAYER M4 ;
        RECT  0 34.656 0.084 34.68 ;
    END
  END b_odata[68]
  PIN b_odata[69]
    DIRECTION INPUT ;
    USE SIGNAL ;
    PORT
      LAYER M4 ;
        RECT  0 34.704 0.084 34.728 ;
    END
  END b_odata[69]
  PIN b_odata[6]
    DIRECTION INPUT ;
    USE SIGNAL ;
    PORT
      LAYER M4 ;
        RECT  0 31.68 0.084 31.704 ;
    END
  END b_odata[6]
  PIN b_odata[70]
    DIRECTION INPUT ;
    USE SIGNAL ;
    PORT
      LAYER M4 ;
        RECT  0 34.752 0.084 34.776 ;
    END
  END b_odata[70]
  PIN b_odata[71]
    DIRECTION INPUT ;
    USE SIGNAL ;
    PORT
      LAYER M4 ;
        RECT  0 34.8 0.084 34.824 ;
    END
  END b_odata[71]
  PIN b_odata[72]
    DIRECTION INPUT ;
    USE SIGNAL ;
    PORT
      LAYER M4 ;
        RECT  0 34.848 0.084 34.872 ;
    END
  END b_odata[72]
  PIN b_odata[73]
    DIRECTION INPUT ;
    USE SIGNAL ;
    PORT
      LAYER M4 ;
        RECT  0 34.896 0.084 34.92 ;
    END
  END b_odata[73]
  PIN b_odata[74]
    DIRECTION INPUT ;
    USE SIGNAL ;
    PORT
      LAYER M4 ;
        RECT  0 34.944 0.084 34.968 ;
    END
  END b_odata[74]
  PIN b_odata[75]
    DIRECTION INPUT ;
    USE SIGNAL ;
    PORT
      LAYER M4 ;
        RECT  0 34.992 0.084 35.016 ;
    END
  END b_odata[75]
  PIN b_odata[76]
    DIRECTION INPUT ;
    USE SIGNAL ;
    PORT
      LAYER M4 ;
        RECT  0 35.04 0.084 35.064 ;
    END
  END b_odata[76]
  PIN b_odata[77]
    DIRECTION INPUT ;
    USE SIGNAL ;
    PORT
      LAYER M4 ;
        RECT  0 35.088 0.084 35.112 ;
    END
  END b_odata[77]
  PIN b_odata[78]
    DIRECTION INPUT ;
    USE SIGNAL ;
    PORT
      LAYER M4 ;
        RECT  0 35.136 0.084 35.16 ;
    END
  END b_odata[78]
  PIN b_odata[79]
    DIRECTION INPUT ;
    USE SIGNAL ;
    PORT
      LAYER M4 ;
        RECT  0 35.184 0.084 35.208 ;
    END
  END b_odata[79]
  PIN b_odata[7]
    DIRECTION INPUT ;
    USE SIGNAL ;
    PORT
      LAYER M4 ;
        RECT  0 31.728 0.084 31.752 ;
    END
  END b_odata[7]
  PIN b_odata[80]
    DIRECTION INPUT ;
    USE SIGNAL ;
    PORT
      LAYER M4 ;
        RECT  0 35.232 0.084 35.256 ;
    END
  END b_odata[80]
  PIN b_odata[81]
    DIRECTION INPUT ;
    USE SIGNAL ;
    PORT
      LAYER M4 ;
        RECT  0 35.28 0.084 35.304 ;
    END
  END b_odata[81]
  PIN b_odata[82]
    DIRECTION INPUT ;
    USE SIGNAL ;
    PORT
      LAYER M4 ;
        RECT  0 35.328 0.084 35.352 ;
    END
  END b_odata[82]
  PIN b_odata[83]
    DIRECTION INPUT ;
    USE SIGNAL ;
    PORT
      LAYER M4 ;
        RECT  0 35.376 0.084 35.4 ;
    END
  END b_odata[83]
  PIN b_odata[84]
    DIRECTION INPUT ;
    USE SIGNAL ;
    PORT
      LAYER M4 ;
        RECT  0 35.424 0.084 35.448 ;
    END
  END b_odata[84]
  PIN b_odata[85]
    DIRECTION INPUT ;
    USE SIGNAL ;
    PORT
      LAYER M4 ;
        RECT  0 35.472 0.084 35.496 ;
    END
  END b_odata[85]
  PIN b_odata[86]
    DIRECTION INPUT ;
    USE SIGNAL ;
    PORT
      LAYER M4 ;
        RECT  0 35.52 0.084 35.544 ;
    END
  END b_odata[86]
  PIN b_odata[87]
    DIRECTION INPUT ;
    USE SIGNAL ;
    PORT
      LAYER M4 ;
        RECT  0 35.568 0.084 35.592 ;
    END
  END b_odata[87]
  PIN b_odata[88]
    DIRECTION INPUT ;
    USE SIGNAL ;
    PORT
      LAYER M4 ;
        RECT  0 35.616 0.084 35.64 ;
    END
  END b_odata[88]
  PIN b_odata[89]
    DIRECTION INPUT ;
    USE SIGNAL ;
    PORT
      LAYER M4 ;
        RECT  0 35.664 0.084 35.688 ;
    END
  END b_odata[89]
  PIN b_odata[8]
    DIRECTION INPUT ;
    USE SIGNAL ;
    PORT
      LAYER M4 ;
        RECT  0 31.776 0.084 31.8 ;
    END
  END b_odata[8]
  PIN b_odata[90]
    DIRECTION INPUT ;
    USE SIGNAL ;
    PORT
      LAYER M4 ;
        RECT  0 35.712 0.084 35.736 ;
    END
  END b_odata[90]
  PIN b_odata[91]
    DIRECTION INPUT ;
    USE SIGNAL ;
    PORT
      LAYER M4 ;
        RECT  0 35.76 0.084 35.784 ;
    END
  END b_odata[91]
  PIN b_odata[92]
    DIRECTION INPUT ;
    USE SIGNAL ;
    PORT
      LAYER M4 ;
        RECT  0 35.808 0.084 35.832 ;
    END
  END b_odata[92]
  PIN b_odata[93]
    DIRECTION INPUT ;
    USE SIGNAL ;
    PORT
      LAYER M4 ;
        RECT  0 35.856 0.084 35.88 ;
    END
  END b_odata[93]
  PIN b_odata[94]
    DIRECTION INPUT ;
    USE SIGNAL ;
    PORT
      LAYER M4 ;
        RECT  0 35.904 0.084 35.928 ;
    END
  END b_odata[94]
  PIN b_odata[95]
    DIRECTION INPUT ;
    USE SIGNAL ;
    PORT
      LAYER M4 ;
        RECT  0 35.952 0.084 35.976 ;
    END
  END b_odata[95]
  PIN b_odata[96]
    DIRECTION INPUT ;
    USE SIGNAL ;
    PORT
      LAYER M4 ;
        RECT  0 36 0.084 36.024 ;
    END
  END b_odata[96]
  PIN b_odata[97]
    DIRECTION INPUT ;
    USE SIGNAL ;
    PORT
      LAYER M4 ;
        RECT  0 36.048 0.084 36.072 ;
    END
  END b_odata[97]
  PIN b_odata[98]
    DIRECTION INPUT ;
    USE SIGNAL ;
    PORT
      LAYER M4 ;
        RECT  0 36.096 0.084 36.12 ;
    END
  END b_odata[98]
  PIN b_odata[99]
    DIRECTION INPUT ;
    USE SIGNAL ;
    PORT
      LAYER M4 ;
        RECT  0 36.144 0.084 36.168 ;
    END
  END b_odata[99]
  PIN b_odata[9]
    DIRECTION INPUT ;
    USE SIGNAL ;
    PORT
      LAYER M4 ;
        RECT  0 31.824 0.084 31.848 ;
    END
  END b_odata[9]
  PIN b_ov
    DIRECTION INPUT ;
    USE SIGNAL ;
    PORT
      LAYER M4 ;
        RECT  0 55.968 0.084 55.992 ;
    END
  END b_ov
  PIN clk
    DIRECTION INPUT ;
    USE SIGNAL ;
    PORT
      LAYER M5 ;
        RECT  13.296 86.316 13.32 86.4 ;
    END
  END clk
  PIN d_line[0]
    DIRECTION INPUT ;
    USE SIGNAL ;
    PORT
      LAYER M5 ;
        RECT  13.392 86.316 13.416 86.4 ;
    END
  END d_line[0]
  PIN d_line[10]
    DIRECTION INPUT ;
    USE SIGNAL ;
    PORT
      LAYER M5 ;
        RECT  13.872 86.316 13.896 86.4 ;
    END
  END d_line[10]
  PIN d_line[11]
    DIRECTION INPUT ;
    USE SIGNAL ;
    PORT
      LAYER M5 ;
        RECT  13.92 86.316 13.944 86.4 ;
    END
  END d_line[11]
  PIN d_line[12]
    DIRECTION INPUT ;
    USE SIGNAL ;
    PORT
      LAYER M5 ;
        RECT  13.968 86.316 13.992 86.4 ;
    END
  END d_line[12]
  PIN d_line[13]
    DIRECTION INPUT ;
    USE SIGNAL ;
    PORT
      LAYER M5 ;
        RECT  14.016 86.316 14.04 86.4 ;
    END
  END d_line[13]
  PIN d_line[14]
    DIRECTION INPUT ;
    USE SIGNAL ;
    PORT
      LAYER M5 ;
        RECT  14.064 86.316 14.088 86.4 ;
    END
  END d_line[14]
  PIN d_line[15]
    DIRECTION INPUT ;
    USE SIGNAL ;
    PORT
      LAYER M5 ;
        RECT  14.112 86.316 14.136 86.4 ;
    END
  END d_line[15]
  PIN d_line[16]
    DIRECTION INPUT ;
    USE SIGNAL ;
    PORT
      LAYER M5 ;
        RECT  14.16 86.316 14.184 86.4 ;
    END
  END d_line[16]
  PIN d_line[17]
    DIRECTION INPUT ;
    USE SIGNAL ;
    PORT
      LAYER M5 ;
        RECT  14.208 86.316 14.232 86.4 ;
    END
  END d_line[17]
  PIN d_line[1]
    DIRECTION INPUT ;
    USE SIGNAL ;
    PORT
      LAYER M5 ;
        RECT  13.44 86.316 13.464 86.4 ;
    END
  END d_line[1]
  PIN d_line[2]
    DIRECTION INPUT ;
    USE SIGNAL ;
    PORT
      LAYER M5 ;
        RECT  13.488 86.316 13.512 86.4 ;
    END
  END d_line[2]
  PIN d_line[3]
    DIRECTION INPUT ;
    USE SIGNAL ;
    PORT
      LAYER M5 ;
        RECT  13.536 86.316 13.56 86.4 ;
    END
  END d_line[3]
  PIN d_line[4]
    DIRECTION INPUT ;
    USE SIGNAL ;
    PORT
      LAYER M5 ;
        RECT  13.584 86.316 13.608 86.4 ;
    END
  END d_line[4]
  PIN d_line[5]
    DIRECTION INPUT ;
    USE SIGNAL ;
    PORT
      LAYER M5 ;
        RECT  13.632 86.316 13.656 86.4 ;
    END
  END d_line[5]
  PIN d_line[6]
    DIRECTION INPUT ;
    USE SIGNAL ;
    PORT
      LAYER M5 ;
        RECT  13.68 86.316 13.704 86.4 ;
    END
  END d_line[6]
  PIN d_line[7]
    DIRECTION INPUT ;
    USE SIGNAL ;
    PORT
      LAYER M5 ;
        RECT  13.728 86.316 13.752 86.4 ;
    END
  END d_line[7]
  PIN d_line[8]
    DIRECTION INPUT ;
    USE SIGNAL ;
    PORT
      LAYER M5 ;
        RECT  13.776 86.316 13.8 86.4 ;
    END
  END d_line[8]
  PIN d_line[9]
    DIRECTION INPUT ;
    USE SIGNAL ;
    PORT
      LAYER M5 ;
        RECT  13.824 86.316 13.848 86.4 ;
    END
  END d_line[9]
  PIN d_tap[0]
    DIRECTION INPUT ;
    USE SIGNAL ;
    PORT
      LAYER M5 ;
        RECT  14.256 86.316 14.28 86.4 ;
    END
  END d_tap[0]
  PIN d_tap[1]
    DIRECTION INPUT ;
    USE SIGNAL ;
    PORT
      LAYER M5 ;
        RECT  14.304 86.316 14.328 86.4 ;
    END
  END d_tap[1]
  PIN d_tap[2]
    DIRECTION INPUT ;
    USE SIGNAL ;
    PORT
      LAYER M5 ;
        RECT  14.352 86.316 14.376 86.4 ;
    END
  END d_tap[2]
  PIN d_tap[3]
    DIRECTION INPUT ;
    USE SIGNAL ;
    PORT
      LAYER M5 ;
        RECT  14.4 86.316 14.424 86.4 ;
    END
  END d_tap[3]
  PIN d_tap[4]
    DIRECTION INPUT ;
    USE SIGNAL ;
    PORT
      LAYER M5 ;
        RECT  14.448 86.316 14.472 86.4 ;
    END
  END d_tap[4]
  PIN d_tap[5]
    DIRECTION INPUT ;
    USE SIGNAL ;
    PORT
      LAYER M5 ;
        RECT  14.496 86.316 14.52 86.4 ;
    END
  END d_tap[5]
  PIN d_tap[6]
    DIRECTION INPUT ;
    USE SIGNAL ;
    PORT
      LAYER M5 ;
        RECT  14.544 86.316 14.568 86.4 ;
    END
  END d_tap[6]
  PIN d_tap[7]
    DIRECTION INPUT ;
    USE SIGNAL ;
    PORT
      LAYER M5 ;
        RECT  14.592 86.316 14.616 86.4 ;
    END
  END d_tap[7]
  PIN d_tap[8]
    DIRECTION INPUT ;
    USE SIGNAL ;
    PORT
      LAYER M5 ;
        RECT  14.64 86.316 14.664 86.4 ;
    END
  END d_tap[8]
  PIN d_v
    DIRECTION INPUT ;
    USE SIGNAL ;
    PORT
      LAYER M5 ;
        RECT  14.688 86.316 14.712 86.4 ;
    END
  END d_v
  PIN fault
    DIRECTION OUTPUT ;
    USE SIGNAL ;
    PORT
      LAYER M4 ;
        RECT  0 56.016 0.084 56.04 ;
    END
  END fault
  PIN n_line[0]
    DIRECTION OUTPUT ;
    USE SIGNAL ;
    PORT
      LAYER M5 ;
        RECT  13.344 0 13.368 0.084 ;
    END
  END n_line[0]
  PIN n_line[10]
    DIRECTION OUTPUT ;
    USE SIGNAL ;
    PORT
      LAYER M5 ;
        RECT  13.824 0 13.848 0.084 ;
    END
  END n_line[10]
  PIN n_line[11]
    DIRECTION OUTPUT ;
    USE SIGNAL ;
    PORT
      LAYER M5 ;
        RECT  13.872 0 13.896 0.084 ;
    END
  END n_line[11]
  PIN n_line[12]
    DIRECTION OUTPUT ;
    USE SIGNAL ;
    PORT
      LAYER M5 ;
        RECT  13.92 0 13.944 0.084 ;
    END
  END n_line[12]
  PIN n_line[13]
    DIRECTION OUTPUT ;
    USE SIGNAL ;
    PORT
      LAYER M5 ;
        RECT  13.968 0 13.992 0.084 ;
    END
  END n_line[13]
  PIN n_line[14]
    DIRECTION OUTPUT ;
    USE SIGNAL ;
    PORT
      LAYER M5 ;
        RECT  14.016 0 14.04 0.084 ;
    END
  END n_line[14]
  PIN n_line[15]
    DIRECTION OUTPUT ;
    USE SIGNAL ;
    PORT
      LAYER M5 ;
        RECT  14.064 0 14.088 0.084 ;
    END
  END n_line[15]
  PIN n_line[16]
    DIRECTION OUTPUT ;
    USE SIGNAL ;
    PORT
      LAYER M5 ;
        RECT  14.112 0 14.136 0.084 ;
    END
  END n_line[16]
  PIN n_line[17]
    DIRECTION OUTPUT ;
    USE SIGNAL ;
    PORT
      LAYER M5 ;
        RECT  14.16 0 14.184 0.084 ;
    END
  END n_line[17]
  PIN n_line[1]
    DIRECTION OUTPUT ;
    USE SIGNAL ;
    PORT
      LAYER M5 ;
        RECT  13.392 0 13.416 0.084 ;
    END
  END n_line[1]
  PIN n_line[2]
    DIRECTION OUTPUT ;
    USE SIGNAL ;
    PORT
      LAYER M5 ;
        RECT  13.44 0 13.464 0.084 ;
    END
  END n_line[2]
  PIN n_line[3]
    DIRECTION OUTPUT ;
    USE SIGNAL ;
    PORT
      LAYER M5 ;
        RECT  13.488 0 13.512 0.084 ;
    END
  END n_line[3]
  PIN n_line[4]
    DIRECTION OUTPUT ;
    USE SIGNAL ;
    PORT
      LAYER M5 ;
        RECT  13.536 0 13.56 0.084 ;
    END
  END n_line[4]
  PIN n_line[5]
    DIRECTION OUTPUT ;
    USE SIGNAL ;
    PORT
      LAYER M5 ;
        RECT  13.584 0 13.608 0.084 ;
    END
  END n_line[5]
  PIN n_line[6]
    DIRECTION OUTPUT ;
    USE SIGNAL ;
    PORT
      LAYER M5 ;
        RECT  13.632 0 13.656 0.084 ;
    END
  END n_line[6]
  PIN n_line[7]
    DIRECTION OUTPUT ;
    USE SIGNAL ;
    PORT
      LAYER M5 ;
        RECT  13.68 0 13.704 0.084 ;
    END
  END n_line[7]
  PIN n_line[8]
    DIRECTION OUTPUT ;
    USE SIGNAL ;
    PORT
      LAYER M5 ;
        RECT  13.728 0 13.752 0.084 ;
    END
  END n_line[8]
  PIN n_line[9]
    DIRECTION OUTPUT ;
    USE SIGNAL ;
    PORT
      LAYER M5 ;
        RECT  13.776 0 13.8 0.084 ;
    END
  END n_line[9]
  PIN n_tap[0]
    DIRECTION OUTPUT ;
    USE SIGNAL ;
    PORT
      LAYER M5 ;
        RECT  14.208 0 14.232 0.084 ;
    END
  END n_tap[0]
  PIN n_tap[1]
    DIRECTION OUTPUT ;
    USE SIGNAL ;
    PORT
      LAYER M5 ;
        RECT  14.256 0 14.28 0.084 ;
    END
  END n_tap[1]
  PIN n_tap[2]
    DIRECTION OUTPUT ;
    USE SIGNAL ;
    PORT
      LAYER M5 ;
        RECT  14.304 0 14.328 0.084 ;
    END
  END n_tap[2]
  PIN n_tap[3]
    DIRECTION OUTPUT ;
    USE SIGNAL ;
    PORT
      LAYER M5 ;
        RECT  14.352 0 14.376 0.084 ;
    END
  END n_tap[3]
  PIN n_tap[4]
    DIRECTION OUTPUT ;
    USE SIGNAL ;
    PORT
      LAYER M5 ;
        RECT  14.4 0 14.424 0.084 ;
    END
  END n_tap[4]
  PIN n_tap[5]
    DIRECTION OUTPUT ;
    USE SIGNAL ;
    PORT
      LAYER M5 ;
        RECT  14.448 0 14.472 0.084 ;
    END
  END n_tap[5]
  PIN n_tap[6]
    DIRECTION OUTPUT ;
    USE SIGNAL ;
    PORT
      LAYER M5 ;
        RECT  14.496 0 14.52 0.084 ;
    END
  END n_tap[6]
  PIN n_tap[7]
    DIRECTION OUTPUT ;
    USE SIGNAL ;
    PORT
      LAYER M5 ;
        RECT  14.544 0 14.568 0.084 ;
    END
  END n_tap[7]
  PIN n_tap[8]
    DIRECTION OUTPUT ;
    USE SIGNAL ;
    PORT
      LAYER M5 ;
        RECT  14.592 0 14.616 0.084 ;
    END
  END n_tap[8]
  PIN n_v
    DIRECTION OUTPUT ;
    USE SIGNAL ;
    PORT
      LAYER M5 ;
        RECT  14.64 0 14.664 0.084 ;
    END
  END n_v
  PIN p_data[0]
    DIRECTION OUTPUT ;
    USE SIGNAL ;
    PORT
      LAYER M5 ;
        RECT  14.736 86.316 14.76 86.4 ;
    END
  END p_data[0]
  PIN p_data[100]
    DIRECTION OUTPUT ;
    USE SIGNAL ;
    PORT
      LAYER M5 ;
        RECT  19.536 86.316 19.56 86.4 ;
    END
  END p_data[100]
  PIN p_data[101]
    DIRECTION OUTPUT ;
    USE SIGNAL ;
    PORT
      LAYER M5 ;
        RECT  19.584 86.316 19.608 86.4 ;
    END
  END p_data[101]
  PIN p_data[102]
    DIRECTION OUTPUT ;
    USE SIGNAL ;
    PORT
      LAYER M5 ;
        RECT  19.632 86.316 19.656 86.4 ;
    END
  END p_data[102]
  PIN p_data[103]
    DIRECTION OUTPUT ;
    USE SIGNAL ;
    PORT
      LAYER M5 ;
        RECT  19.68 86.316 19.704 86.4 ;
    END
  END p_data[103]
  PIN p_data[104]
    DIRECTION OUTPUT ;
    USE SIGNAL ;
    PORT
      LAYER M5 ;
        RECT  19.728 86.316 19.752 86.4 ;
    END
  END p_data[104]
  PIN p_data[105]
    DIRECTION OUTPUT ;
    USE SIGNAL ;
    PORT
      LAYER M5 ;
        RECT  19.776 86.316 19.8 86.4 ;
    END
  END p_data[105]
  PIN p_data[106]
    DIRECTION OUTPUT ;
    USE SIGNAL ;
    PORT
      LAYER M5 ;
        RECT  19.824 86.316 19.848 86.4 ;
    END
  END p_data[106]
  PIN p_data[107]
    DIRECTION OUTPUT ;
    USE SIGNAL ;
    PORT
      LAYER M5 ;
        RECT  19.872 86.316 19.896 86.4 ;
    END
  END p_data[107]
  PIN p_data[108]
    DIRECTION OUTPUT ;
    USE SIGNAL ;
    PORT
      LAYER M5 ;
        RECT  19.92 86.316 19.944 86.4 ;
    END
  END p_data[108]
  PIN p_data[109]
    DIRECTION OUTPUT ;
    USE SIGNAL ;
    PORT
      LAYER M5 ;
        RECT  19.968 86.316 19.992 86.4 ;
    END
  END p_data[109]
  PIN p_data[10]
    DIRECTION OUTPUT ;
    USE SIGNAL ;
    PORT
      LAYER M5 ;
        RECT  15.216 86.316 15.24 86.4 ;
    END
  END p_data[10]
  PIN p_data[110]
    DIRECTION OUTPUT ;
    USE SIGNAL ;
    PORT
      LAYER M5 ;
        RECT  20.016 86.316 20.04 86.4 ;
    END
  END p_data[110]
  PIN p_data[111]
    DIRECTION OUTPUT ;
    USE SIGNAL ;
    PORT
      LAYER M5 ;
        RECT  20.064 86.316 20.088 86.4 ;
    END
  END p_data[111]
  PIN p_data[112]
    DIRECTION OUTPUT ;
    USE SIGNAL ;
    PORT
      LAYER M5 ;
        RECT  20.112 86.316 20.136 86.4 ;
    END
  END p_data[112]
  PIN p_data[113]
    DIRECTION OUTPUT ;
    USE SIGNAL ;
    PORT
      LAYER M5 ;
        RECT  20.16 86.316 20.184 86.4 ;
    END
  END p_data[113]
  PIN p_data[114]
    DIRECTION OUTPUT ;
    USE SIGNAL ;
    PORT
      LAYER M5 ;
        RECT  20.208 86.316 20.232 86.4 ;
    END
  END p_data[114]
  PIN p_data[115]
    DIRECTION OUTPUT ;
    USE SIGNAL ;
    PORT
      LAYER M5 ;
        RECT  20.256 86.316 20.28 86.4 ;
    END
  END p_data[115]
  PIN p_data[116]
    DIRECTION OUTPUT ;
    USE SIGNAL ;
    PORT
      LAYER M5 ;
        RECT  20.304 86.316 20.328 86.4 ;
    END
  END p_data[116]
  PIN p_data[117]
    DIRECTION OUTPUT ;
    USE SIGNAL ;
    PORT
      LAYER M5 ;
        RECT  20.352 86.316 20.376 86.4 ;
    END
  END p_data[117]
  PIN p_data[118]
    DIRECTION OUTPUT ;
    USE SIGNAL ;
    PORT
      LAYER M5 ;
        RECT  20.4 86.316 20.424 86.4 ;
    END
  END p_data[118]
  PIN p_data[119]
    DIRECTION OUTPUT ;
    USE SIGNAL ;
    PORT
      LAYER M5 ;
        RECT  20.448 86.316 20.472 86.4 ;
    END
  END p_data[119]
  PIN p_data[11]
    DIRECTION OUTPUT ;
    USE SIGNAL ;
    PORT
      LAYER M5 ;
        RECT  15.264 86.316 15.288 86.4 ;
    END
  END p_data[11]
  PIN p_data[120]
    DIRECTION OUTPUT ;
    USE SIGNAL ;
    PORT
      LAYER M5 ;
        RECT  20.496 86.316 20.52 86.4 ;
    END
  END p_data[120]
  PIN p_data[121]
    DIRECTION OUTPUT ;
    USE SIGNAL ;
    PORT
      LAYER M5 ;
        RECT  20.544 86.316 20.568 86.4 ;
    END
  END p_data[121]
  PIN p_data[122]
    DIRECTION OUTPUT ;
    USE SIGNAL ;
    PORT
      LAYER M5 ;
        RECT  20.592 86.316 20.616 86.4 ;
    END
  END p_data[122]
  PIN p_data[123]
    DIRECTION OUTPUT ;
    USE SIGNAL ;
    PORT
      LAYER M5 ;
        RECT  20.64 86.316 20.664 86.4 ;
    END
  END p_data[123]
  PIN p_data[124]
    DIRECTION OUTPUT ;
    USE SIGNAL ;
    PORT
      LAYER M5 ;
        RECT  20.688 86.316 20.712 86.4 ;
    END
  END p_data[124]
  PIN p_data[125]
    DIRECTION OUTPUT ;
    USE SIGNAL ;
    PORT
      LAYER M5 ;
        RECT  20.736 86.316 20.76 86.4 ;
    END
  END p_data[125]
  PIN p_data[126]
    DIRECTION OUTPUT ;
    USE SIGNAL ;
    PORT
      LAYER M5 ;
        RECT  20.784 86.316 20.808 86.4 ;
    END
  END p_data[126]
  PIN p_data[127]
    DIRECTION OUTPUT ;
    USE SIGNAL ;
    PORT
      LAYER M5 ;
        RECT  20.832 86.316 20.856 86.4 ;
    END
  END p_data[127]
  PIN p_data[128]
    DIRECTION OUTPUT ;
    USE SIGNAL ;
    PORT
      LAYER M5 ;
        RECT  20.88 86.316 20.904 86.4 ;
    END
  END p_data[128]
  PIN p_data[129]
    DIRECTION OUTPUT ;
    USE SIGNAL ;
    PORT
      LAYER M5 ;
        RECT  20.928 86.316 20.952 86.4 ;
    END
  END p_data[129]
  PIN p_data[12]
    DIRECTION OUTPUT ;
    USE SIGNAL ;
    PORT
      LAYER M5 ;
        RECT  15.312 86.316 15.336 86.4 ;
    END
  END p_data[12]
  PIN p_data[130]
    DIRECTION OUTPUT ;
    USE SIGNAL ;
    PORT
      LAYER M5 ;
        RECT  20.976 86.316 21 86.4 ;
    END
  END p_data[130]
  PIN p_data[131]
    DIRECTION OUTPUT ;
    USE SIGNAL ;
    PORT
      LAYER M5 ;
        RECT  21.024 86.316 21.048 86.4 ;
    END
  END p_data[131]
  PIN p_data[132]
    DIRECTION OUTPUT ;
    USE SIGNAL ;
    PORT
      LAYER M5 ;
        RECT  21.072 86.316 21.096 86.4 ;
    END
  END p_data[132]
  PIN p_data[133]
    DIRECTION OUTPUT ;
    USE SIGNAL ;
    PORT
      LAYER M5 ;
        RECT  21.12 86.316 21.144 86.4 ;
    END
  END p_data[133]
  PIN p_data[134]
    DIRECTION OUTPUT ;
    USE SIGNAL ;
    PORT
      LAYER M5 ;
        RECT  21.168 86.316 21.192 86.4 ;
    END
  END p_data[134]
  PIN p_data[135]
    DIRECTION OUTPUT ;
    USE SIGNAL ;
    PORT
      LAYER M5 ;
        RECT  21.216 86.316 21.24 86.4 ;
    END
  END p_data[135]
  PIN p_data[136]
    DIRECTION OUTPUT ;
    USE SIGNAL ;
    PORT
      LAYER M5 ;
        RECT  21.264 86.316 21.288 86.4 ;
    END
  END p_data[136]
  PIN p_data[137]
    DIRECTION OUTPUT ;
    USE SIGNAL ;
    PORT
      LAYER M5 ;
        RECT  21.312 86.316 21.336 86.4 ;
    END
  END p_data[137]
  PIN p_data[138]
    DIRECTION OUTPUT ;
    USE SIGNAL ;
    PORT
      LAYER M5 ;
        RECT  21.36 86.316 21.384 86.4 ;
    END
  END p_data[138]
  PIN p_data[139]
    DIRECTION OUTPUT ;
    USE SIGNAL ;
    PORT
      LAYER M5 ;
        RECT  21.408 86.316 21.432 86.4 ;
    END
  END p_data[139]
  PIN p_data[13]
    DIRECTION OUTPUT ;
    USE SIGNAL ;
    PORT
      LAYER M5 ;
        RECT  15.36 86.316 15.384 86.4 ;
    END
  END p_data[13]
  PIN p_data[140]
    DIRECTION OUTPUT ;
    USE SIGNAL ;
    PORT
      LAYER M5 ;
        RECT  21.456 86.316 21.48 86.4 ;
    END
  END p_data[140]
  PIN p_data[141]
    DIRECTION OUTPUT ;
    USE SIGNAL ;
    PORT
      LAYER M5 ;
        RECT  21.504 86.316 21.528 86.4 ;
    END
  END p_data[141]
  PIN p_data[142]
    DIRECTION OUTPUT ;
    USE SIGNAL ;
    PORT
      LAYER M5 ;
        RECT  21.552 86.316 21.576 86.4 ;
    END
  END p_data[142]
  PIN p_data[143]
    DIRECTION OUTPUT ;
    USE SIGNAL ;
    PORT
      LAYER M5 ;
        RECT  21.6 86.316 21.624 86.4 ;
    END
  END p_data[143]
  PIN p_data[144]
    DIRECTION OUTPUT ;
    USE SIGNAL ;
    PORT
      LAYER M5 ;
        RECT  21.648 86.316 21.672 86.4 ;
    END
  END p_data[144]
  PIN p_data[145]
    DIRECTION OUTPUT ;
    USE SIGNAL ;
    PORT
      LAYER M5 ;
        RECT  21.696 86.316 21.72 86.4 ;
    END
  END p_data[145]
  PIN p_data[146]
    DIRECTION OUTPUT ;
    USE SIGNAL ;
    PORT
      LAYER M5 ;
        RECT  21.744 86.316 21.768 86.4 ;
    END
  END p_data[146]
  PIN p_data[147]
    DIRECTION OUTPUT ;
    USE SIGNAL ;
    PORT
      LAYER M5 ;
        RECT  21.792 86.316 21.816 86.4 ;
    END
  END p_data[147]
  PIN p_data[148]
    DIRECTION OUTPUT ;
    USE SIGNAL ;
    PORT
      LAYER M5 ;
        RECT  21.84 86.316 21.864 86.4 ;
    END
  END p_data[148]
  PIN p_data[149]
    DIRECTION OUTPUT ;
    USE SIGNAL ;
    PORT
      LAYER M5 ;
        RECT  21.888 86.316 21.912 86.4 ;
    END
  END p_data[149]
  PIN p_data[14]
    DIRECTION OUTPUT ;
    USE SIGNAL ;
    PORT
      LAYER M5 ;
        RECT  15.408 86.316 15.432 86.4 ;
    END
  END p_data[14]
  PIN p_data[150]
    DIRECTION OUTPUT ;
    USE SIGNAL ;
    PORT
      LAYER M5 ;
        RECT  21.936 86.316 21.96 86.4 ;
    END
  END p_data[150]
  PIN p_data[151]
    DIRECTION OUTPUT ;
    USE SIGNAL ;
    PORT
      LAYER M5 ;
        RECT  21.984 86.316 22.008 86.4 ;
    END
  END p_data[151]
  PIN p_data[152]
    DIRECTION OUTPUT ;
    USE SIGNAL ;
    PORT
      LAYER M5 ;
        RECT  22.032 86.316 22.056 86.4 ;
    END
  END p_data[152]
  PIN p_data[153]
    DIRECTION OUTPUT ;
    USE SIGNAL ;
    PORT
      LAYER M5 ;
        RECT  22.08 86.316 22.104 86.4 ;
    END
  END p_data[153]
  PIN p_data[154]
    DIRECTION OUTPUT ;
    USE SIGNAL ;
    PORT
      LAYER M5 ;
        RECT  22.128 86.316 22.152 86.4 ;
    END
  END p_data[154]
  PIN p_data[155]
    DIRECTION OUTPUT ;
    USE SIGNAL ;
    PORT
      LAYER M5 ;
        RECT  22.176 86.316 22.2 86.4 ;
    END
  END p_data[155]
  PIN p_data[156]
    DIRECTION OUTPUT ;
    USE SIGNAL ;
    PORT
      LAYER M5 ;
        RECT  22.224 86.316 22.248 86.4 ;
    END
  END p_data[156]
  PIN p_data[157]
    DIRECTION OUTPUT ;
    USE SIGNAL ;
    PORT
      LAYER M5 ;
        RECT  22.272 86.316 22.296 86.4 ;
    END
  END p_data[157]
  PIN p_data[158]
    DIRECTION OUTPUT ;
    USE SIGNAL ;
    PORT
      LAYER M5 ;
        RECT  22.32 86.316 22.344 86.4 ;
    END
  END p_data[158]
  PIN p_data[159]
    DIRECTION OUTPUT ;
    USE SIGNAL ;
    PORT
      LAYER M5 ;
        RECT  22.368 86.316 22.392 86.4 ;
    END
  END p_data[159]
  PIN p_data[15]
    DIRECTION OUTPUT ;
    USE SIGNAL ;
    PORT
      LAYER M5 ;
        RECT  15.456 86.316 15.48 86.4 ;
    END
  END p_data[15]
  PIN p_data[160]
    DIRECTION OUTPUT ;
    USE SIGNAL ;
    PORT
      LAYER M5 ;
        RECT  22.416 86.316 22.44 86.4 ;
    END
  END p_data[160]
  PIN p_data[161]
    DIRECTION OUTPUT ;
    USE SIGNAL ;
    PORT
      LAYER M5 ;
        RECT  22.464 86.316 22.488 86.4 ;
    END
  END p_data[161]
  PIN p_data[162]
    DIRECTION OUTPUT ;
    USE SIGNAL ;
    PORT
      LAYER M5 ;
        RECT  22.512 86.316 22.536 86.4 ;
    END
  END p_data[162]
  PIN p_data[163]
    DIRECTION OUTPUT ;
    USE SIGNAL ;
    PORT
      LAYER M5 ;
        RECT  22.56 86.316 22.584 86.4 ;
    END
  END p_data[163]
  PIN p_data[164]
    DIRECTION OUTPUT ;
    USE SIGNAL ;
    PORT
      LAYER M5 ;
        RECT  22.608 86.316 22.632 86.4 ;
    END
  END p_data[164]
  PIN p_data[165]
    DIRECTION OUTPUT ;
    USE SIGNAL ;
    PORT
      LAYER M5 ;
        RECT  22.656 86.316 22.68 86.4 ;
    END
  END p_data[165]
  PIN p_data[166]
    DIRECTION OUTPUT ;
    USE SIGNAL ;
    PORT
      LAYER M5 ;
        RECT  22.704 86.316 22.728 86.4 ;
    END
  END p_data[166]
  PIN p_data[167]
    DIRECTION OUTPUT ;
    USE SIGNAL ;
    PORT
      LAYER M5 ;
        RECT  22.752 86.316 22.776 86.4 ;
    END
  END p_data[167]
  PIN p_data[168]
    DIRECTION OUTPUT ;
    USE SIGNAL ;
    PORT
      LAYER M5 ;
        RECT  22.8 86.316 22.824 86.4 ;
    END
  END p_data[168]
  PIN p_data[169]
    DIRECTION OUTPUT ;
    USE SIGNAL ;
    PORT
      LAYER M5 ;
        RECT  22.848 86.316 22.872 86.4 ;
    END
  END p_data[169]
  PIN p_data[16]
    DIRECTION OUTPUT ;
    USE SIGNAL ;
    PORT
      LAYER M5 ;
        RECT  15.504 86.316 15.528 86.4 ;
    END
  END p_data[16]
  PIN p_data[170]
    DIRECTION OUTPUT ;
    USE SIGNAL ;
    PORT
      LAYER M5 ;
        RECT  22.896 86.316 22.92 86.4 ;
    END
  END p_data[170]
  PIN p_data[171]
    DIRECTION OUTPUT ;
    USE SIGNAL ;
    PORT
      LAYER M5 ;
        RECT  22.944 86.316 22.968 86.4 ;
    END
  END p_data[171]
  PIN p_data[172]
    DIRECTION OUTPUT ;
    USE SIGNAL ;
    PORT
      LAYER M5 ;
        RECT  22.992 86.316 23.016 86.4 ;
    END
  END p_data[172]
  PIN p_data[173]
    DIRECTION OUTPUT ;
    USE SIGNAL ;
    PORT
      LAYER M5 ;
        RECT  23.04 86.316 23.064 86.4 ;
    END
  END p_data[173]
  PIN p_data[174]
    DIRECTION OUTPUT ;
    USE SIGNAL ;
    PORT
      LAYER M5 ;
        RECT  23.088 86.316 23.112 86.4 ;
    END
  END p_data[174]
  PIN p_data[175]
    DIRECTION OUTPUT ;
    USE SIGNAL ;
    PORT
      LAYER M5 ;
        RECT  23.136 86.316 23.16 86.4 ;
    END
  END p_data[175]
  PIN p_data[176]
    DIRECTION OUTPUT ;
    USE SIGNAL ;
    PORT
      LAYER M5 ;
        RECT  23.184 86.316 23.208 86.4 ;
    END
  END p_data[176]
  PIN p_data[177]
    DIRECTION OUTPUT ;
    USE SIGNAL ;
    PORT
      LAYER M5 ;
        RECT  23.232 86.316 23.256 86.4 ;
    END
  END p_data[177]
  PIN p_data[178]
    DIRECTION OUTPUT ;
    USE SIGNAL ;
    PORT
      LAYER M5 ;
        RECT  23.28 86.316 23.304 86.4 ;
    END
  END p_data[178]
  PIN p_data[179]
    DIRECTION OUTPUT ;
    USE SIGNAL ;
    PORT
      LAYER M5 ;
        RECT  23.328 86.316 23.352 86.4 ;
    END
  END p_data[179]
  PIN p_data[17]
    DIRECTION OUTPUT ;
    USE SIGNAL ;
    PORT
      LAYER M5 ;
        RECT  15.552 86.316 15.576 86.4 ;
    END
  END p_data[17]
  PIN p_data[180]
    DIRECTION OUTPUT ;
    USE SIGNAL ;
    PORT
      LAYER M5 ;
        RECT  23.376 86.316 23.4 86.4 ;
    END
  END p_data[180]
  PIN p_data[181]
    DIRECTION OUTPUT ;
    USE SIGNAL ;
    PORT
      LAYER M5 ;
        RECT  23.424 86.316 23.448 86.4 ;
    END
  END p_data[181]
  PIN p_data[182]
    DIRECTION OUTPUT ;
    USE SIGNAL ;
    PORT
      LAYER M5 ;
        RECT  23.472 86.316 23.496 86.4 ;
    END
  END p_data[182]
  PIN p_data[183]
    DIRECTION OUTPUT ;
    USE SIGNAL ;
    PORT
      LAYER M5 ;
        RECT  23.52 86.316 23.544 86.4 ;
    END
  END p_data[183]
  PIN p_data[184]
    DIRECTION OUTPUT ;
    USE SIGNAL ;
    PORT
      LAYER M5 ;
        RECT  23.568 86.316 23.592 86.4 ;
    END
  END p_data[184]
  PIN p_data[185]
    DIRECTION OUTPUT ;
    USE SIGNAL ;
    PORT
      LAYER M5 ;
        RECT  23.616 86.316 23.64 86.4 ;
    END
  END p_data[185]
  PIN p_data[186]
    DIRECTION OUTPUT ;
    USE SIGNAL ;
    PORT
      LAYER M5 ;
        RECT  23.664 86.316 23.688 86.4 ;
    END
  END p_data[186]
  PIN p_data[187]
    DIRECTION OUTPUT ;
    USE SIGNAL ;
    PORT
      LAYER M5 ;
        RECT  23.712 86.316 23.736 86.4 ;
    END
  END p_data[187]
  PIN p_data[188]
    DIRECTION OUTPUT ;
    USE SIGNAL ;
    PORT
      LAYER M5 ;
        RECT  23.76 86.316 23.784 86.4 ;
    END
  END p_data[188]
  PIN p_data[189]
    DIRECTION OUTPUT ;
    USE SIGNAL ;
    PORT
      LAYER M5 ;
        RECT  23.808 86.316 23.832 86.4 ;
    END
  END p_data[189]
  PIN p_data[18]
    DIRECTION OUTPUT ;
    USE SIGNAL ;
    PORT
      LAYER M5 ;
        RECT  15.6 86.316 15.624 86.4 ;
    END
  END p_data[18]
  PIN p_data[190]
    DIRECTION OUTPUT ;
    USE SIGNAL ;
    PORT
      LAYER M5 ;
        RECT  23.856 86.316 23.88 86.4 ;
    END
  END p_data[190]
  PIN p_data[191]
    DIRECTION OUTPUT ;
    USE SIGNAL ;
    PORT
      LAYER M5 ;
        RECT  23.904 86.316 23.928 86.4 ;
    END
  END p_data[191]
  PIN p_data[192]
    DIRECTION OUTPUT ;
    USE SIGNAL ;
    PORT
      LAYER M5 ;
        RECT  23.952 86.316 23.976 86.4 ;
    END
  END p_data[192]
  PIN p_data[193]
    DIRECTION OUTPUT ;
    USE SIGNAL ;
    PORT
      LAYER M5 ;
        RECT  24 86.316 24.024 86.4 ;
    END
  END p_data[193]
  PIN p_data[194]
    DIRECTION OUTPUT ;
    USE SIGNAL ;
    PORT
      LAYER M5 ;
        RECT  24.048 86.316 24.072 86.4 ;
    END
  END p_data[194]
  PIN p_data[195]
    DIRECTION OUTPUT ;
    USE SIGNAL ;
    PORT
      LAYER M5 ;
        RECT  24.096 86.316 24.12 86.4 ;
    END
  END p_data[195]
  PIN p_data[196]
    DIRECTION OUTPUT ;
    USE SIGNAL ;
    PORT
      LAYER M5 ;
        RECT  24.144 86.316 24.168 86.4 ;
    END
  END p_data[196]
  PIN p_data[197]
    DIRECTION OUTPUT ;
    USE SIGNAL ;
    PORT
      LAYER M5 ;
        RECT  24.192 86.316 24.216 86.4 ;
    END
  END p_data[197]
  PIN p_data[198]
    DIRECTION OUTPUT ;
    USE SIGNAL ;
    PORT
      LAYER M5 ;
        RECT  24.24 86.316 24.264 86.4 ;
    END
  END p_data[198]
  PIN p_data[199]
    DIRECTION OUTPUT ;
    USE SIGNAL ;
    PORT
      LAYER M5 ;
        RECT  24.288 86.316 24.312 86.4 ;
    END
  END p_data[199]
  PIN p_data[19]
    DIRECTION OUTPUT ;
    USE SIGNAL ;
    PORT
      LAYER M5 ;
        RECT  15.648 86.316 15.672 86.4 ;
    END
  END p_data[19]
  PIN p_data[1]
    DIRECTION OUTPUT ;
    USE SIGNAL ;
    PORT
      LAYER M5 ;
        RECT  14.784 86.316 14.808 86.4 ;
    END
  END p_data[1]
  PIN p_data[200]
    DIRECTION OUTPUT ;
    USE SIGNAL ;
    PORT
      LAYER M5 ;
        RECT  24.336 86.316 24.36 86.4 ;
    END
  END p_data[200]
  PIN p_data[201]
    DIRECTION OUTPUT ;
    USE SIGNAL ;
    PORT
      LAYER M5 ;
        RECT  24.384 86.316 24.408 86.4 ;
    END
  END p_data[201]
  PIN p_data[202]
    DIRECTION OUTPUT ;
    USE SIGNAL ;
    PORT
      LAYER M5 ;
        RECT  24.432 86.316 24.456 86.4 ;
    END
  END p_data[202]
  PIN p_data[203]
    DIRECTION OUTPUT ;
    USE SIGNAL ;
    PORT
      LAYER M5 ;
        RECT  24.48 86.316 24.504 86.4 ;
    END
  END p_data[203]
  PIN p_data[204]
    DIRECTION OUTPUT ;
    USE SIGNAL ;
    PORT
      LAYER M5 ;
        RECT  24.528 86.316 24.552 86.4 ;
    END
  END p_data[204]
  PIN p_data[205]
    DIRECTION OUTPUT ;
    USE SIGNAL ;
    PORT
      LAYER M5 ;
        RECT  24.576 86.316 24.6 86.4 ;
    END
  END p_data[205]
  PIN p_data[206]
    DIRECTION OUTPUT ;
    USE SIGNAL ;
    PORT
      LAYER M5 ;
        RECT  24.624 86.316 24.648 86.4 ;
    END
  END p_data[206]
  PIN p_data[207]
    DIRECTION OUTPUT ;
    USE SIGNAL ;
    PORT
      LAYER M5 ;
        RECT  24.672 86.316 24.696 86.4 ;
    END
  END p_data[207]
  PIN p_data[208]
    DIRECTION OUTPUT ;
    USE SIGNAL ;
    PORT
      LAYER M5 ;
        RECT  24.72 86.316 24.744 86.4 ;
    END
  END p_data[208]
  PIN p_data[209]
    DIRECTION OUTPUT ;
    USE SIGNAL ;
    PORT
      LAYER M5 ;
        RECT  24.768 86.316 24.792 86.4 ;
    END
  END p_data[209]
  PIN p_data[20]
    DIRECTION OUTPUT ;
    USE SIGNAL ;
    PORT
      LAYER M5 ;
        RECT  15.696 86.316 15.72 86.4 ;
    END
  END p_data[20]
  PIN p_data[210]
    DIRECTION OUTPUT ;
    USE SIGNAL ;
    PORT
      LAYER M5 ;
        RECT  24.816 86.316 24.84 86.4 ;
    END
  END p_data[210]
  PIN p_data[211]
    DIRECTION OUTPUT ;
    USE SIGNAL ;
    PORT
      LAYER M5 ;
        RECT  24.864 86.316 24.888 86.4 ;
    END
  END p_data[211]
  PIN p_data[212]
    DIRECTION OUTPUT ;
    USE SIGNAL ;
    PORT
      LAYER M5 ;
        RECT  24.912 86.316 24.936 86.4 ;
    END
  END p_data[212]
  PIN p_data[213]
    DIRECTION OUTPUT ;
    USE SIGNAL ;
    PORT
      LAYER M5 ;
        RECT  24.96 86.316 24.984 86.4 ;
    END
  END p_data[213]
  PIN p_data[214]
    DIRECTION OUTPUT ;
    USE SIGNAL ;
    PORT
      LAYER M5 ;
        RECT  25.008 86.316 25.032 86.4 ;
    END
  END p_data[214]
  PIN p_data[215]
    DIRECTION OUTPUT ;
    USE SIGNAL ;
    PORT
      LAYER M5 ;
        RECT  25.056 86.316 25.08 86.4 ;
    END
  END p_data[215]
  PIN p_data[216]
    DIRECTION OUTPUT ;
    USE SIGNAL ;
    PORT
      LAYER M5 ;
        RECT  25.104 86.316 25.128 86.4 ;
    END
  END p_data[216]
  PIN p_data[217]
    DIRECTION OUTPUT ;
    USE SIGNAL ;
    PORT
      LAYER M5 ;
        RECT  25.152 86.316 25.176 86.4 ;
    END
  END p_data[217]
  PIN p_data[218]
    DIRECTION OUTPUT ;
    USE SIGNAL ;
    PORT
      LAYER M5 ;
        RECT  25.2 86.316 25.224 86.4 ;
    END
  END p_data[218]
  PIN p_data[219]
    DIRECTION OUTPUT ;
    USE SIGNAL ;
    PORT
      LAYER M5 ;
        RECT  25.248 86.316 25.272 86.4 ;
    END
  END p_data[219]
  PIN p_data[21]
    DIRECTION OUTPUT ;
    USE SIGNAL ;
    PORT
      LAYER M5 ;
        RECT  15.744 86.316 15.768 86.4 ;
    END
  END p_data[21]
  PIN p_data[220]
    DIRECTION OUTPUT ;
    USE SIGNAL ;
    PORT
      LAYER M5 ;
        RECT  25.296 86.316 25.32 86.4 ;
    END
  END p_data[220]
  PIN p_data[221]
    DIRECTION OUTPUT ;
    USE SIGNAL ;
    PORT
      LAYER M5 ;
        RECT  25.344 86.316 25.368 86.4 ;
    END
  END p_data[221]
  PIN p_data[222]
    DIRECTION OUTPUT ;
    USE SIGNAL ;
    PORT
      LAYER M5 ;
        RECT  25.392 86.316 25.416 86.4 ;
    END
  END p_data[222]
  PIN p_data[223]
    DIRECTION OUTPUT ;
    USE SIGNAL ;
    PORT
      LAYER M5 ;
        RECT  25.44 86.316 25.464 86.4 ;
    END
  END p_data[223]
  PIN p_data[224]
    DIRECTION OUTPUT ;
    USE SIGNAL ;
    PORT
      LAYER M5 ;
        RECT  25.488 86.316 25.512 86.4 ;
    END
  END p_data[224]
  PIN p_data[225]
    DIRECTION OUTPUT ;
    USE SIGNAL ;
    PORT
      LAYER M5 ;
        RECT  25.536 86.316 25.56 86.4 ;
    END
  END p_data[225]
  PIN p_data[226]
    DIRECTION OUTPUT ;
    USE SIGNAL ;
    PORT
      LAYER M5 ;
        RECT  25.584 86.316 25.608 86.4 ;
    END
  END p_data[226]
  PIN p_data[227]
    DIRECTION OUTPUT ;
    USE SIGNAL ;
    PORT
      LAYER M5 ;
        RECT  25.632 86.316 25.656 86.4 ;
    END
  END p_data[227]
  PIN p_data[228]
    DIRECTION OUTPUT ;
    USE SIGNAL ;
    PORT
      LAYER M5 ;
        RECT  25.68 86.316 25.704 86.4 ;
    END
  END p_data[228]
  PIN p_data[229]
    DIRECTION OUTPUT ;
    USE SIGNAL ;
    PORT
      LAYER M5 ;
        RECT  25.728 86.316 25.752 86.4 ;
    END
  END p_data[229]
  PIN p_data[22]
    DIRECTION OUTPUT ;
    USE SIGNAL ;
    PORT
      LAYER M5 ;
        RECT  15.792 86.316 15.816 86.4 ;
    END
  END p_data[22]
  PIN p_data[230]
    DIRECTION OUTPUT ;
    USE SIGNAL ;
    PORT
      LAYER M5 ;
        RECT  25.776 86.316 25.8 86.4 ;
    END
  END p_data[230]
  PIN p_data[231]
    DIRECTION OUTPUT ;
    USE SIGNAL ;
    PORT
      LAYER M5 ;
        RECT  25.824 86.316 25.848 86.4 ;
    END
  END p_data[231]
  PIN p_data[232]
    DIRECTION OUTPUT ;
    USE SIGNAL ;
    PORT
      LAYER M5 ;
        RECT  25.872 86.316 25.896 86.4 ;
    END
  END p_data[232]
  PIN p_data[233]
    DIRECTION OUTPUT ;
    USE SIGNAL ;
    PORT
      LAYER M5 ;
        RECT  25.92 86.316 25.944 86.4 ;
    END
  END p_data[233]
  PIN p_data[234]
    DIRECTION OUTPUT ;
    USE SIGNAL ;
    PORT
      LAYER M5 ;
        RECT  25.968 86.316 25.992 86.4 ;
    END
  END p_data[234]
  PIN p_data[235]
    DIRECTION OUTPUT ;
    USE SIGNAL ;
    PORT
      LAYER M5 ;
        RECT  26.016 86.316 26.04 86.4 ;
    END
  END p_data[235]
  PIN p_data[236]
    DIRECTION OUTPUT ;
    USE SIGNAL ;
    PORT
      LAYER M5 ;
        RECT  26.064 86.316 26.088 86.4 ;
    END
  END p_data[236]
  PIN p_data[237]
    DIRECTION OUTPUT ;
    USE SIGNAL ;
    PORT
      LAYER M5 ;
        RECT  26.112 86.316 26.136 86.4 ;
    END
  END p_data[237]
  PIN p_data[238]
    DIRECTION OUTPUT ;
    USE SIGNAL ;
    PORT
      LAYER M5 ;
        RECT  26.16 86.316 26.184 86.4 ;
    END
  END p_data[238]
  PIN p_data[239]
    DIRECTION OUTPUT ;
    USE SIGNAL ;
    PORT
      LAYER M5 ;
        RECT  26.208 86.316 26.232 86.4 ;
    END
  END p_data[239]
  PIN p_data[23]
    DIRECTION OUTPUT ;
    USE SIGNAL ;
    PORT
      LAYER M5 ;
        RECT  15.84 86.316 15.864 86.4 ;
    END
  END p_data[23]
  PIN p_data[240]
    DIRECTION OUTPUT ;
    USE SIGNAL ;
    PORT
      LAYER M5 ;
        RECT  26.256 86.316 26.28 86.4 ;
    END
  END p_data[240]
  PIN p_data[241]
    DIRECTION OUTPUT ;
    USE SIGNAL ;
    PORT
      LAYER M5 ;
        RECT  26.304 86.316 26.328 86.4 ;
    END
  END p_data[241]
  PIN p_data[242]
    DIRECTION OUTPUT ;
    USE SIGNAL ;
    PORT
      LAYER M5 ;
        RECT  26.352 86.316 26.376 86.4 ;
    END
  END p_data[242]
  PIN p_data[243]
    DIRECTION OUTPUT ;
    USE SIGNAL ;
    PORT
      LAYER M5 ;
        RECT  26.4 86.316 26.424 86.4 ;
    END
  END p_data[243]
  PIN p_data[244]
    DIRECTION OUTPUT ;
    USE SIGNAL ;
    PORT
      LAYER M5 ;
        RECT  26.448 86.316 26.472 86.4 ;
    END
  END p_data[244]
  PIN p_data[245]
    DIRECTION OUTPUT ;
    USE SIGNAL ;
    PORT
      LAYER M5 ;
        RECT  26.496 86.316 26.52 86.4 ;
    END
  END p_data[245]
  PIN p_data[246]
    DIRECTION OUTPUT ;
    USE SIGNAL ;
    PORT
      LAYER M5 ;
        RECT  26.544 86.316 26.568 86.4 ;
    END
  END p_data[246]
  PIN p_data[247]
    DIRECTION OUTPUT ;
    USE SIGNAL ;
    PORT
      LAYER M5 ;
        RECT  26.592 86.316 26.616 86.4 ;
    END
  END p_data[247]
  PIN p_data[248]
    DIRECTION OUTPUT ;
    USE SIGNAL ;
    PORT
      LAYER M5 ;
        RECT  26.64 86.316 26.664 86.4 ;
    END
  END p_data[248]
  PIN p_data[249]
    DIRECTION OUTPUT ;
    USE SIGNAL ;
    PORT
      LAYER M5 ;
        RECT  26.688 86.316 26.712 86.4 ;
    END
  END p_data[249]
  PIN p_data[24]
    DIRECTION OUTPUT ;
    USE SIGNAL ;
    PORT
      LAYER M5 ;
        RECT  15.888 86.316 15.912 86.4 ;
    END
  END p_data[24]
  PIN p_data[250]
    DIRECTION OUTPUT ;
    USE SIGNAL ;
    PORT
      LAYER M5 ;
        RECT  26.736 86.316 26.76 86.4 ;
    END
  END p_data[250]
  PIN p_data[251]
    DIRECTION OUTPUT ;
    USE SIGNAL ;
    PORT
      LAYER M5 ;
        RECT  26.784 86.316 26.808 86.4 ;
    END
  END p_data[251]
  PIN p_data[252]
    DIRECTION OUTPUT ;
    USE SIGNAL ;
    PORT
      LAYER M5 ;
        RECT  26.832 86.316 26.856 86.4 ;
    END
  END p_data[252]
  PIN p_data[253]
    DIRECTION OUTPUT ;
    USE SIGNAL ;
    PORT
      LAYER M5 ;
        RECT  26.88 86.316 26.904 86.4 ;
    END
  END p_data[253]
  PIN p_data[254]
    DIRECTION OUTPUT ;
    USE SIGNAL ;
    PORT
      LAYER M5 ;
        RECT  26.928 86.316 26.952 86.4 ;
    END
  END p_data[254]
  PIN p_data[255]
    DIRECTION OUTPUT ;
    USE SIGNAL ;
    PORT
      LAYER M5 ;
        RECT  26.976 86.316 27 86.4 ;
    END
  END p_data[255]
  PIN p_data[256]
    DIRECTION OUTPUT ;
    USE SIGNAL ;
    PORT
      LAYER M5 ;
        RECT  27.024 86.316 27.048 86.4 ;
    END
  END p_data[256]
  PIN p_data[257]
    DIRECTION OUTPUT ;
    USE SIGNAL ;
    PORT
      LAYER M5 ;
        RECT  27.072 86.316 27.096 86.4 ;
    END
  END p_data[257]
  PIN p_data[258]
    DIRECTION OUTPUT ;
    USE SIGNAL ;
    PORT
      LAYER M5 ;
        RECT  27.12 86.316 27.144 86.4 ;
    END
  END p_data[258]
  PIN p_data[259]
    DIRECTION OUTPUT ;
    USE SIGNAL ;
    PORT
      LAYER M5 ;
        RECT  27.168 86.316 27.192 86.4 ;
    END
  END p_data[259]
  PIN p_data[25]
    DIRECTION OUTPUT ;
    USE SIGNAL ;
    PORT
      LAYER M5 ;
        RECT  15.936 86.316 15.96 86.4 ;
    END
  END p_data[25]
  PIN p_data[260]
    DIRECTION OUTPUT ;
    USE SIGNAL ;
    PORT
      LAYER M5 ;
        RECT  27.216 86.316 27.24 86.4 ;
    END
  END p_data[260]
  PIN p_data[261]
    DIRECTION OUTPUT ;
    USE SIGNAL ;
    PORT
      LAYER M5 ;
        RECT  27.264 86.316 27.288 86.4 ;
    END
  END p_data[261]
  PIN p_data[262]
    DIRECTION OUTPUT ;
    USE SIGNAL ;
    PORT
      LAYER M5 ;
        RECT  27.312 86.316 27.336 86.4 ;
    END
  END p_data[262]
  PIN p_data[263]
    DIRECTION OUTPUT ;
    USE SIGNAL ;
    PORT
      LAYER M5 ;
        RECT  27.36 86.316 27.384 86.4 ;
    END
  END p_data[263]
  PIN p_data[264]
    DIRECTION OUTPUT ;
    USE SIGNAL ;
    PORT
      LAYER M5 ;
        RECT  27.408 86.316 27.432 86.4 ;
    END
  END p_data[264]
  PIN p_data[265]
    DIRECTION OUTPUT ;
    USE SIGNAL ;
    PORT
      LAYER M5 ;
        RECT  27.456 86.316 27.48 86.4 ;
    END
  END p_data[265]
  PIN p_data[266]
    DIRECTION OUTPUT ;
    USE SIGNAL ;
    PORT
      LAYER M5 ;
        RECT  27.504 86.316 27.528 86.4 ;
    END
  END p_data[266]
  PIN p_data[267]
    DIRECTION OUTPUT ;
    USE SIGNAL ;
    PORT
      LAYER M5 ;
        RECT  27.552 86.316 27.576 86.4 ;
    END
  END p_data[267]
  PIN p_data[268]
    DIRECTION OUTPUT ;
    USE SIGNAL ;
    PORT
      LAYER M5 ;
        RECT  27.6 86.316 27.624 86.4 ;
    END
  END p_data[268]
  PIN p_data[269]
    DIRECTION OUTPUT ;
    USE SIGNAL ;
    PORT
      LAYER M5 ;
        RECT  27.648 86.316 27.672 86.4 ;
    END
  END p_data[269]
  PIN p_data[26]
    DIRECTION OUTPUT ;
    USE SIGNAL ;
    PORT
      LAYER M5 ;
        RECT  15.984 86.316 16.008 86.4 ;
    END
  END p_data[26]
  PIN p_data[270]
    DIRECTION OUTPUT ;
    USE SIGNAL ;
    PORT
      LAYER M5 ;
        RECT  27.696 86.316 27.72 86.4 ;
    END
  END p_data[270]
  PIN p_data[271]
    DIRECTION OUTPUT ;
    USE SIGNAL ;
    PORT
      LAYER M5 ;
        RECT  27.744 86.316 27.768 86.4 ;
    END
  END p_data[271]
  PIN p_data[272]
    DIRECTION OUTPUT ;
    USE SIGNAL ;
    PORT
      LAYER M5 ;
        RECT  27.792 86.316 27.816 86.4 ;
    END
  END p_data[272]
  PIN p_data[273]
    DIRECTION OUTPUT ;
    USE SIGNAL ;
    PORT
      LAYER M5 ;
        RECT  27.84 86.316 27.864 86.4 ;
    END
  END p_data[273]
  PIN p_data[274]
    DIRECTION OUTPUT ;
    USE SIGNAL ;
    PORT
      LAYER M5 ;
        RECT  27.888 86.316 27.912 86.4 ;
    END
  END p_data[274]
  PIN p_data[275]
    DIRECTION OUTPUT ;
    USE SIGNAL ;
    PORT
      LAYER M5 ;
        RECT  27.936 86.316 27.96 86.4 ;
    END
  END p_data[275]
  PIN p_data[276]
    DIRECTION OUTPUT ;
    USE SIGNAL ;
    PORT
      LAYER M5 ;
        RECT  27.984 86.316 28.008 86.4 ;
    END
  END p_data[276]
  PIN p_data[277]
    DIRECTION OUTPUT ;
    USE SIGNAL ;
    PORT
      LAYER M5 ;
        RECT  28.032 86.316 28.056 86.4 ;
    END
  END p_data[277]
  PIN p_data[278]
    DIRECTION OUTPUT ;
    USE SIGNAL ;
    PORT
      LAYER M5 ;
        RECT  28.08 86.316 28.104 86.4 ;
    END
  END p_data[278]
  PIN p_data[279]
    DIRECTION OUTPUT ;
    USE SIGNAL ;
    PORT
      LAYER M5 ;
        RECT  28.128 86.316 28.152 86.4 ;
    END
  END p_data[279]
  PIN p_data[27]
    DIRECTION OUTPUT ;
    USE SIGNAL ;
    PORT
      LAYER M5 ;
        RECT  16.032 86.316 16.056 86.4 ;
    END
  END p_data[27]
  PIN p_data[280]
    DIRECTION OUTPUT ;
    USE SIGNAL ;
    PORT
      LAYER M5 ;
        RECT  28.176 86.316 28.2 86.4 ;
    END
  END p_data[280]
  PIN p_data[281]
    DIRECTION OUTPUT ;
    USE SIGNAL ;
    PORT
      LAYER M5 ;
        RECT  28.224 86.316 28.248 86.4 ;
    END
  END p_data[281]
  PIN p_data[282]
    DIRECTION OUTPUT ;
    USE SIGNAL ;
    PORT
      LAYER M5 ;
        RECT  28.272 86.316 28.296 86.4 ;
    END
  END p_data[282]
  PIN p_data[283]
    DIRECTION OUTPUT ;
    USE SIGNAL ;
    PORT
      LAYER M5 ;
        RECT  28.32 86.316 28.344 86.4 ;
    END
  END p_data[283]
  PIN p_data[284]
    DIRECTION OUTPUT ;
    USE SIGNAL ;
    PORT
      LAYER M5 ;
        RECT  28.368 86.316 28.392 86.4 ;
    END
  END p_data[284]
  PIN p_data[285]
    DIRECTION OUTPUT ;
    USE SIGNAL ;
    PORT
      LAYER M5 ;
        RECT  28.416 86.316 28.44 86.4 ;
    END
  END p_data[285]
  PIN p_data[286]
    DIRECTION OUTPUT ;
    USE SIGNAL ;
    PORT
      LAYER M5 ;
        RECT  28.464 86.316 28.488 86.4 ;
    END
  END p_data[286]
  PIN p_data[287]
    DIRECTION OUTPUT ;
    USE SIGNAL ;
    PORT
      LAYER M5 ;
        RECT  28.512 86.316 28.536 86.4 ;
    END
  END p_data[287]
  PIN p_data[288]
    DIRECTION OUTPUT ;
    USE SIGNAL ;
    PORT
      LAYER M5 ;
        RECT  28.56 86.316 28.584 86.4 ;
    END
  END p_data[288]
  PIN p_data[289]
    DIRECTION OUTPUT ;
    USE SIGNAL ;
    PORT
      LAYER M5 ;
        RECT  28.608 86.316 28.632 86.4 ;
    END
  END p_data[289]
  PIN p_data[28]
    DIRECTION OUTPUT ;
    USE SIGNAL ;
    PORT
      LAYER M5 ;
        RECT  16.08 86.316 16.104 86.4 ;
    END
  END p_data[28]
  PIN p_data[290]
    DIRECTION OUTPUT ;
    USE SIGNAL ;
    PORT
      LAYER M5 ;
        RECT  28.656 86.316 28.68 86.4 ;
    END
  END p_data[290]
  PIN p_data[291]
    DIRECTION OUTPUT ;
    USE SIGNAL ;
    PORT
      LAYER M5 ;
        RECT  28.704 86.316 28.728 86.4 ;
    END
  END p_data[291]
  PIN p_data[292]
    DIRECTION OUTPUT ;
    USE SIGNAL ;
    PORT
      LAYER M5 ;
        RECT  28.752 86.316 28.776 86.4 ;
    END
  END p_data[292]
  PIN p_data[293]
    DIRECTION OUTPUT ;
    USE SIGNAL ;
    PORT
      LAYER M5 ;
        RECT  28.8 86.316 28.824 86.4 ;
    END
  END p_data[293]
  PIN p_data[294]
    DIRECTION OUTPUT ;
    USE SIGNAL ;
    PORT
      LAYER M5 ;
        RECT  28.848 86.316 28.872 86.4 ;
    END
  END p_data[294]
  PIN p_data[295]
    DIRECTION OUTPUT ;
    USE SIGNAL ;
    PORT
      LAYER M5 ;
        RECT  28.896 86.316 28.92 86.4 ;
    END
  END p_data[295]
  PIN p_data[296]
    DIRECTION OUTPUT ;
    USE SIGNAL ;
    PORT
      LAYER M5 ;
        RECT  28.944 86.316 28.968 86.4 ;
    END
  END p_data[296]
  PIN p_data[297]
    DIRECTION OUTPUT ;
    USE SIGNAL ;
    PORT
      LAYER M5 ;
        RECT  28.992 86.316 29.016 86.4 ;
    END
  END p_data[297]
  PIN p_data[298]
    DIRECTION OUTPUT ;
    USE SIGNAL ;
    PORT
      LAYER M5 ;
        RECT  29.04 86.316 29.064 86.4 ;
    END
  END p_data[298]
  PIN p_data[299]
    DIRECTION OUTPUT ;
    USE SIGNAL ;
    PORT
      LAYER M5 ;
        RECT  29.088 86.316 29.112 86.4 ;
    END
  END p_data[299]
  PIN p_data[29]
    DIRECTION OUTPUT ;
    USE SIGNAL ;
    PORT
      LAYER M5 ;
        RECT  16.128 86.316 16.152 86.4 ;
    END
  END p_data[29]
  PIN p_data[2]
    DIRECTION OUTPUT ;
    USE SIGNAL ;
    PORT
      LAYER M5 ;
        RECT  14.832 86.316 14.856 86.4 ;
    END
  END p_data[2]
  PIN p_data[300]
    DIRECTION OUTPUT ;
    USE SIGNAL ;
    PORT
      LAYER M5 ;
        RECT  29.136 86.316 29.16 86.4 ;
    END
  END p_data[300]
  PIN p_data[301]
    DIRECTION OUTPUT ;
    USE SIGNAL ;
    PORT
      LAYER M5 ;
        RECT  29.184 86.316 29.208 86.4 ;
    END
  END p_data[301]
  PIN p_data[302]
    DIRECTION OUTPUT ;
    USE SIGNAL ;
    PORT
      LAYER M5 ;
        RECT  29.232 86.316 29.256 86.4 ;
    END
  END p_data[302]
  PIN p_data[303]
    DIRECTION OUTPUT ;
    USE SIGNAL ;
    PORT
      LAYER M5 ;
        RECT  29.28 86.316 29.304 86.4 ;
    END
  END p_data[303]
  PIN p_data[304]
    DIRECTION OUTPUT ;
    USE SIGNAL ;
    PORT
      LAYER M5 ;
        RECT  29.328 86.316 29.352 86.4 ;
    END
  END p_data[304]
  PIN p_data[305]
    DIRECTION OUTPUT ;
    USE SIGNAL ;
    PORT
      LAYER M5 ;
        RECT  29.376 86.316 29.4 86.4 ;
    END
  END p_data[305]
  PIN p_data[306]
    DIRECTION OUTPUT ;
    USE SIGNAL ;
    PORT
      LAYER M5 ;
        RECT  29.424 86.316 29.448 86.4 ;
    END
  END p_data[306]
  PIN p_data[307]
    DIRECTION OUTPUT ;
    USE SIGNAL ;
    PORT
      LAYER M5 ;
        RECT  29.472 86.316 29.496 86.4 ;
    END
  END p_data[307]
  PIN p_data[308]
    DIRECTION OUTPUT ;
    USE SIGNAL ;
    PORT
      LAYER M5 ;
        RECT  29.52 86.316 29.544 86.4 ;
    END
  END p_data[308]
  PIN p_data[309]
    DIRECTION OUTPUT ;
    USE SIGNAL ;
    PORT
      LAYER M5 ;
        RECT  29.568 86.316 29.592 86.4 ;
    END
  END p_data[309]
  PIN p_data[30]
    DIRECTION OUTPUT ;
    USE SIGNAL ;
    PORT
      LAYER M5 ;
        RECT  16.176 86.316 16.2 86.4 ;
    END
  END p_data[30]
  PIN p_data[310]
    DIRECTION OUTPUT ;
    USE SIGNAL ;
    PORT
      LAYER M5 ;
        RECT  29.616 86.316 29.64 86.4 ;
    END
  END p_data[310]
  PIN p_data[311]
    DIRECTION OUTPUT ;
    USE SIGNAL ;
    PORT
      LAYER M5 ;
        RECT  29.664 86.316 29.688 86.4 ;
    END
  END p_data[311]
  PIN p_data[312]
    DIRECTION OUTPUT ;
    USE SIGNAL ;
    PORT
      LAYER M5 ;
        RECT  29.712 86.316 29.736 86.4 ;
    END
  END p_data[312]
  PIN p_data[313]
    DIRECTION OUTPUT ;
    USE SIGNAL ;
    PORT
      LAYER M5 ;
        RECT  29.76 86.316 29.784 86.4 ;
    END
  END p_data[313]
  PIN p_data[314]
    DIRECTION OUTPUT ;
    USE SIGNAL ;
    PORT
      LAYER M5 ;
        RECT  29.808 86.316 29.832 86.4 ;
    END
  END p_data[314]
  PIN p_data[315]
    DIRECTION OUTPUT ;
    USE SIGNAL ;
    PORT
      LAYER M5 ;
        RECT  29.856 86.316 29.88 86.4 ;
    END
  END p_data[315]
  PIN p_data[316]
    DIRECTION OUTPUT ;
    USE SIGNAL ;
    PORT
      LAYER M5 ;
        RECT  29.904 86.316 29.928 86.4 ;
    END
  END p_data[316]
  PIN p_data[317]
    DIRECTION OUTPUT ;
    USE SIGNAL ;
    PORT
      LAYER M5 ;
        RECT  29.952 86.316 29.976 86.4 ;
    END
  END p_data[317]
  PIN p_data[318]
    DIRECTION OUTPUT ;
    USE SIGNAL ;
    PORT
      LAYER M5 ;
        RECT  30 86.316 30.024 86.4 ;
    END
  END p_data[318]
  PIN p_data[319]
    DIRECTION OUTPUT ;
    USE SIGNAL ;
    PORT
      LAYER M5 ;
        RECT  30.048 86.316 30.072 86.4 ;
    END
  END p_data[319]
  PIN p_data[31]
    DIRECTION OUTPUT ;
    USE SIGNAL ;
    PORT
      LAYER M5 ;
        RECT  16.224 86.316 16.248 86.4 ;
    END
  END p_data[31]
  PIN p_data[320]
    DIRECTION OUTPUT ;
    USE SIGNAL ;
    PORT
      LAYER M5 ;
        RECT  30.096 86.316 30.12 86.4 ;
    END
  END p_data[320]
  PIN p_data[321]
    DIRECTION OUTPUT ;
    USE SIGNAL ;
    PORT
      LAYER M5 ;
        RECT  30.144 86.316 30.168 86.4 ;
    END
  END p_data[321]
  PIN p_data[322]
    DIRECTION OUTPUT ;
    USE SIGNAL ;
    PORT
      LAYER M5 ;
        RECT  30.192 86.316 30.216 86.4 ;
    END
  END p_data[322]
  PIN p_data[323]
    DIRECTION OUTPUT ;
    USE SIGNAL ;
    PORT
      LAYER M5 ;
        RECT  30.24 86.316 30.264 86.4 ;
    END
  END p_data[323]
  PIN p_data[324]
    DIRECTION OUTPUT ;
    USE SIGNAL ;
    PORT
      LAYER M5 ;
        RECT  30.288 86.316 30.312 86.4 ;
    END
  END p_data[324]
  PIN p_data[325]
    DIRECTION OUTPUT ;
    USE SIGNAL ;
    PORT
      LAYER M5 ;
        RECT  30.336 86.316 30.36 86.4 ;
    END
  END p_data[325]
  PIN p_data[326]
    DIRECTION OUTPUT ;
    USE SIGNAL ;
    PORT
      LAYER M5 ;
        RECT  30.384 86.316 30.408 86.4 ;
    END
  END p_data[326]
  PIN p_data[327]
    DIRECTION OUTPUT ;
    USE SIGNAL ;
    PORT
      LAYER M5 ;
        RECT  30.432 86.316 30.456 86.4 ;
    END
  END p_data[327]
  PIN p_data[328]
    DIRECTION OUTPUT ;
    USE SIGNAL ;
    PORT
      LAYER M5 ;
        RECT  30.48 86.316 30.504 86.4 ;
    END
  END p_data[328]
  PIN p_data[329]
    DIRECTION OUTPUT ;
    USE SIGNAL ;
    PORT
      LAYER M5 ;
        RECT  30.528 86.316 30.552 86.4 ;
    END
  END p_data[329]
  PIN p_data[32]
    DIRECTION OUTPUT ;
    USE SIGNAL ;
    PORT
      LAYER M5 ;
        RECT  16.272 86.316 16.296 86.4 ;
    END
  END p_data[32]
  PIN p_data[330]
    DIRECTION OUTPUT ;
    USE SIGNAL ;
    PORT
      LAYER M5 ;
        RECT  30.576 86.316 30.6 86.4 ;
    END
  END p_data[330]
  PIN p_data[331]
    DIRECTION OUTPUT ;
    USE SIGNAL ;
    PORT
      LAYER M5 ;
        RECT  30.624 86.316 30.648 86.4 ;
    END
  END p_data[331]
  PIN p_data[332]
    DIRECTION OUTPUT ;
    USE SIGNAL ;
    PORT
      LAYER M5 ;
        RECT  30.672 86.316 30.696 86.4 ;
    END
  END p_data[332]
  PIN p_data[333]
    DIRECTION OUTPUT ;
    USE SIGNAL ;
    PORT
      LAYER M5 ;
        RECT  30.72 86.316 30.744 86.4 ;
    END
  END p_data[333]
  PIN p_data[334]
    DIRECTION OUTPUT ;
    USE SIGNAL ;
    PORT
      LAYER M5 ;
        RECT  30.768 86.316 30.792 86.4 ;
    END
  END p_data[334]
  PIN p_data[335]
    DIRECTION OUTPUT ;
    USE SIGNAL ;
    PORT
      LAYER M5 ;
        RECT  30.816 86.316 30.84 86.4 ;
    END
  END p_data[335]
  PIN p_data[336]
    DIRECTION OUTPUT ;
    USE SIGNAL ;
    PORT
      LAYER M5 ;
        RECT  30.864 86.316 30.888 86.4 ;
    END
  END p_data[336]
  PIN p_data[337]
    DIRECTION OUTPUT ;
    USE SIGNAL ;
    PORT
      LAYER M5 ;
        RECT  30.912 86.316 30.936 86.4 ;
    END
  END p_data[337]
  PIN p_data[338]
    DIRECTION OUTPUT ;
    USE SIGNAL ;
    PORT
      LAYER M5 ;
        RECT  30.96 86.316 30.984 86.4 ;
    END
  END p_data[338]
  PIN p_data[339]
    DIRECTION OUTPUT ;
    USE SIGNAL ;
    PORT
      LAYER M5 ;
        RECT  31.008 86.316 31.032 86.4 ;
    END
  END p_data[339]
  PIN p_data[33]
    DIRECTION OUTPUT ;
    USE SIGNAL ;
    PORT
      LAYER M5 ;
        RECT  16.32 86.316 16.344 86.4 ;
    END
  END p_data[33]
  PIN p_data[340]
    DIRECTION OUTPUT ;
    USE SIGNAL ;
    PORT
      LAYER M5 ;
        RECT  31.056 86.316 31.08 86.4 ;
    END
  END p_data[340]
  PIN p_data[341]
    DIRECTION OUTPUT ;
    USE SIGNAL ;
    PORT
      LAYER M5 ;
        RECT  31.104 86.316 31.128 86.4 ;
    END
  END p_data[341]
  PIN p_data[342]
    DIRECTION OUTPUT ;
    USE SIGNAL ;
    PORT
      LAYER M5 ;
        RECT  31.152 86.316 31.176 86.4 ;
    END
  END p_data[342]
  PIN p_data[343]
    DIRECTION OUTPUT ;
    USE SIGNAL ;
    PORT
      LAYER M5 ;
        RECT  31.2 86.316 31.224 86.4 ;
    END
  END p_data[343]
  PIN p_data[344]
    DIRECTION OUTPUT ;
    USE SIGNAL ;
    PORT
      LAYER M5 ;
        RECT  31.248 86.316 31.272 86.4 ;
    END
  END p_data[344]
  PIN p_data[345]
    DIRECTION OUTPUT ;
    USE SIGNAL ;
    PORT
      LAYER M5 ;
        RECT  31.296 86.316 31.32 86.4 ;
    END
  END p_data[345]
  PIN p_data[346]
    DIRECTION OUTPUT ;
    USE SIGNAL ;
    PORT
      LAYER M5 ;
        RECT  31.344 86.316 31.368 86.4 ;
    END
  END p_data[346]
  PIN p_data[347]
    DIRECTION OUTPUT ;
    USE SIGNAL ;
    PORT
      LAYER M5 ;
        RECT  31.392 86.316 31.416 86.4 ;
    END
  END p_data[347]
  PIN p_data[348]
    DIRECTION OUTPUT ;
    USE SIGNAL ;
    PORT
      LAYER M5 ;
        RECT  31.44 86.316 31.464 86.4 ;
    END
  END p_data[348]
  PIN p_data[349]
    DIRECTION OUTPUT ;
    USE SIGNAL ;
    PORT
      LAYER M5 ;
        RECT  31.488 86.316 31.512 86.4 ;
    END
  END p_data[349]
  PIN p_data[34]
    DIRECTION OUTPUT ;
    USE SIGNAL ;
    PORT
      LAYER M5 ;
        RECT  16.368 86.316 16.392 86.4 ;
    END
  END p_data[34]
  PIN p_data[350]
    DIRECTION OUTPUT ;
    USE SIGNAL ;
    PORT
      LAYER M5 ;
        RECT  31.536 86.316 31.56 86.4 ;
    END
  END p_data[350]
  PIN p_data[351]
    DIRECTION OUTPUT ;
    USE SIGNAL ;
    PORT
      LAYER M5 ;
        RECT  31.584 86.316 31.608 86.4 ;
    END
  END p_data[351]
  PIN p_data[352]
    DIRECTION OUTPUT ;
    USE SIGNAL ;
    PORT
      LAYER M5 ;
        RECT  31.632 86.316 31.656 86.4 ;
    END
  END p_data[352]
  PIN p_data[353]
    DIRECTION OUTPUT ;
    USE SIGNAL ;
    PORT
      LAYER M5 ;
        RECT  31.68 86.316 31.704 86.4 ;
    END
  END p_data[353]
  PIN p_data[354]
    DIRECTION OUTPUT ;
    USE SIGNAL ;
    PORT
      LAYER M5 ;
        RECT  31.728 86.316 31.752 86.4 ;
    END
  END p_data[354]
  PIN p_data[355]
    DIRECTION OUTPUT ;
    USE SIGNAL ;
    PORT
      LAYER M5 ;
        RECT  31.776 86.316 31.8 86.4 ;
    END
  END p_data[355]
  PIN p_data[356]
    DIRECTION OUTPUT ;
    USE SIGNAL ;
    PORT
      LAYER M5 ;
        RECT  31.824 86.316 31.848 86.4 ;
    END
  END p_data[356]
  PIN p_data[357]
    DIRECTION OUTPUT ;
    USE SIGNAL ;
    PORT
      LAYER M5 ;
        RECT  31.872 86.316 31.896 86.4 ;
    END
  END p_data[357]
  PIN p_data[358]
    DIRECTION OUTPUT ;
    USE SIGNAL ;
    PORT
      LAYER M5 ;
        RECT  31.92 86.316 31.944 86.4 ;
    END
  END p_data[358]
  PIN p_data[359]
    DIRECTION OUTPUT ;
    USE SIGNAL ;
    PORT
      LAYER M5 ;
        RECT  31.968 86.316 31.992 86.4 ;
    END
  END p_data[359]
  PIN p_data[35]
    DIRECTION OUTPUT ;
    USE SIGNAL ;
    PORT
      LAYER M5 ;
        RECT  16.416 86.316 16.44 86.4 ;
    END
  END p_data[35]
  PIN p_data[360]
    DIRECTION OUTPUT ;
    USE SIGNAL ;
    PORT
      LAYER M5 ;
        RECT  32.016 86.316 32.04 86.4 ;
    END
  END p_data[360]
  PIN p_data[361]
    DIRECTION OUTPUT ;
    USE SIGNAL ;
    PORT
      LAYER M5 ;
        RECT  32.064 86.316 32.088 86.4 ;
    END
  END p_data[361]
  PIN p_data[362]
    DIRECTION OUTPUT ;
    USE SIGNAL ;
    PORT
      LAYER M5 ;
        RECT  32.112 86.316 32.136 86.4 ;
    END
  END p_data[362]
  PIN p_data[363]
    DIRECTION OUTPUT ;
    USE SIGNAL ;
    PORT
      LAYER M5 ;
        RECT  32.16 86.316 32.184 86.4 ;
    END
  END p_data[363]
  PIN p_data[364]
    DIRECTION OUTPUT ;
    USE SIGNAL ;
    PORT
      LAYER M5 ;
        RECT  32.208 86.316 32.232 86.4 ;
    END
  END p_data[364]
  PIN p_data[365]
    DIRECTION OUTPUT ;
    USE SIGNAL ;
    PORT
      LAYER M5 ;
        RECT  32.256 86.316 32.28 86.4 ;
    END
  END p_data[365]
  PIN p_data[366]
    DIRECTION OUTPUT ;
    USE SIGNAL ;
    PORT
      LAYER M5 ;
        RECT  32.304 86.316 32.328 86.4 ;
    END
  END p_data[366]
  PIN p_data[367]
    DIRECTION OUTPUT ;
    USE SIGNAL ;
    PORT
      LAYER M5 ;
        RECT  32.352 86.316 32.376 86.4 ;
    END
  END p_data[367]
  PIN p_data[368]
    DIRECTION OUTPUT ;
    USE SIGNAL ;
    PORT
      LAYER M5 ;
        RECT  32.4 86.316 32.424 86.4 ;
    END
  END p_data[368]
  PIN p_data[369]
    DIRECTION OUTPUT ;
    USE SIGNAL ;
    PORT
      LAYER M5 ;
        RECT  32.448 86.316 32.472 86.4 ;
    END
  END p_data[369]
  PIN p_data[36]
    DIRECTION OUTPUT ;
    USE SIGNAL ;
    PORT
      LAYER M5 ;
        RECT  16.464 86.316 16.488 86.4 ;
    END
  END p_data[36]
  PIN p_data[370]
    DIRECTION OUTPUT ;
    USE SIGNAL ;
    PORT
      LAYER M5 ;
        RECT  32.496 86.316 32.52 86.4 ;
    END
  END p_data[370]
  PIN p_data[371]
    DIRECTION OUTPUT ;
    USE SIGNAL ;
    PORT
      LAYER M5 ;
        RECT  32.544 86.316 32.568 86.4 ;
    END
  END p_data[371]
  PIN p_data[372]
    DIRECTION OUTPUT ;
    USE SIGNAL ;
    PORT
      LAYER M5 ;
        RECT  32.592 86.316 32.616 86.4 ;
    END
  END p_data[372]
  PIN p_data[373]
    DIRECTION OUTPUT ;
    USE SIGNAL ;
    PORT
      LAYER M5 ;
        RECT  32.64 86.316 32.664 86.4 ;
    END
  END p_data[373]
  PIN p_data[374]
    DIRECTION OUTPUT ;
    USE SIGNAL ;
    PORT
      LAYER M5 ;
        RECT  32.688 86.316 32.712 86.4 ;
    END
  END p_data[374]
  PIN p_data[375]
    DIRECTION OUTPUT ;
    USE SIGNAL ;
    PORT
      LAYER M5 ;
        RECT  32.736 86.316 32.76 86.4 ;
    END
  END p_data[375]
  PIN p_data[376]
    DIRECTION OUTPUT ;
    USE SIGNAL ;
    PORT
      LAYER M5 ;
        RECT  32.784 86.316 32.808 86.4 ;
    END
  END p_data[376]
  PIN p_data[377]
    DIRECTION OUTPUT ;
    USE SIGNAL ;
    PORT
      LAYER M5 ;
        RECT  32.832 86.316 32.856 86.4 ;
    END
  END p_data[377]
  PIN p_data[378]
    DIRECTION OUTPUT ;
    USE SIGNAL ;
    PORT
      LAYER M5 ;
        RECT  32.88 86.316 32.904 86.4 ;
    END
  END p_data[378]
  PIN p_data[379]
    DIRECTION OUTPUT ;
    USE SIGNAL ;
    PORT
      LAYER M5 ;
        RECT  32.928 86.316 32.952 86.4 ;
    END
  END p_data[379]
  PIN p_data[37]
    DIRECTION OUTPUT ;
    USE SIGNAL ;
    PORT
      LAYER M5 ;
        RECT  16.512 86.316 16.536 86.4 ;
    END
  END p_data[37]
  PIN p_data[380]
    DIRECTION OUTPUT ;
    USE SIGNAL ;
    PORT
      LAYER M5 ;
        RECT  32.976 86.316 33 86.4 ;
    END
  END p_data[380]
  PIN p_data[381]
    DIRECTION OUTPUT ;
    USE SIGNAL ;
    PORT
      LAYER M5 ;
        RECT  33.024 86.316 33.048 86.4 ;
    END
  END p_data[381]
  PIN p_data[382]
    DIRECTION OUTPUT ;
    USE SIGNAL ;
    PORT
      LAYER M5 ;
        RECT  33.072 86.316 33.096 86.4 ;
    END
  END p_data[382]
  PIN p_data[383]
    DIRECTION OUTPUT ;
    USE SIGNAL ;
    PORT
      LAYER M5 ;
        RECT  33.12 86.316 33.144 86.4 ;
    END
  END p_data[383]
  PIN p_data[384]
    DIRECTION OUTPUT ;
    USE SIGNAL ;
    PORT
      LAYER M5 ;
        RECT  33.168 86.316 33.192 86.4 ;
    END
  END p_data[384]
  PIN p_data[385]
    DIRECTION OUTPUT ;
    USE SIGNAL ;
    PORT
      LAYER M5 ;
        RECT  33.216 86.316 33.24 86.4 ;
    END
  END p_data[385]
  PIN p_data[386]
    DIRECTION OUTPUT ;
    USE SIGNAL ;
    PORT
      LAYER M5 ;
        RECT  33.264 86.316 33.288 86.4 ;
    END
  END p_data[386]
  PIN p_data[387]
    DIRECTION OUTPUT ;
    USE SIGNAL ;
    PORT
      LAYER M5 ;
        RECT  33.312 86.316 33.336 86.4 ;
    END
  END p_data[387]
  PIN p_data[388]
    DIRECTION OUTPUT ;
    USE SIGNAL ;
    PORT
      LAYER M5 ;
        RECT  33.36 86.316 33.384 86.4 ;
    END
  END p_data[388]
  PIN p_data[389]
    DIRECTION OUTPUT ;
    USE SIGNAL ;
    PORT
      LAYER M5 ;
        RECT  33.408 86.316 33.432 86.4 ;
    END
  END p_data[389]
  PIN p_data[38]
    DIRECTION OUTPUT ;
    USE SIGNAL ;
    PORT
      LAYER M5 ;
        RECT  16.56 86.316 16.584 86.4 ;
    END
  END p_data[38]
  PIN p_data[390]
    DIRECTION OUTPUT ;
    USE SIGNAL ;
    PORT
      LAYER M5 ;
        RECT  33.456 86.316 33.48 86.4 ;
    END
  END p_data[390]
  PIN p_data[391]
    DIRECTION OUTPUT ;
    USE SIGNAL ;
    PORT
      LAYER M5 ;
        RECT  33.504 86.316 33.528 86.4 ;
    END
  END p_data[391]
  PIN p_data[392]
    DIRECTION OUTPUT ;
    USE SIGNAL ;
    PORT
      LAYER M5 ;
        RECT  33.552 86.316 33.576 86.4 ;
    END
  END p_data[392]
  PIN p_data[393]
    DIRECTION OUTPUT ;
    USE SIGNAL ;
    PORT
      LAYER M5 ;
        RECT  33.6 86.316 33.624 86.4 ;
    END
  END p_data[393]
  PIN p_data[394]
    DIRECTION OUTPUT ;
    USE SIGNAL ;
    PORT
      LAYER M5 ;
        RECT  33.648 86.316 33.672 86.4 ;
    END
  END p_data[394]
  PIN p_data[395]
    DIRECTION OUTPUT ;
    USE SIGNAL ;
    PORT
      LAYER M5 ;
        RECT  33.696 86.316 33.72 86.4 ;
    END
  END p_data[395]
  PIN p_data[396]
    DIRECTION OUTPUT ;
    USE SIGNAL ;
    PORT
      LAYER M5 ;
        RECT  33.744 86.316 33.768 86.4 ;
    END
  END p_data[396]
  PIN p_data[397]
    DIRECTION OUTPUT ;
    USE SIGNAL ;
    PORT
      LAYER M5 ;
        RECT  33.792 86.316 33.816 86.4 ;
    END
  END p_data[397]
  PIN p_data[398]
    DIRECTION OUTPUT ;
    USE SIGNAL ;
    PORT
      LAYER M5 ;
        RECT  33.84 86.316 33.864 86.4 ;
    END
  END p_data[398]
  PIN p_data[399]
    DIRECTION OUTPUT ;
    USE SIGNAL ;
    PORT
      LAYER M5 ;
        RECT  33.888 86.316 33.912 86.4 ;
    END
  END p_data[399]
  PIN p_data[39]
    DIRECTION OUTPUT ;
    USE SIGNAL ;
    PORT
      LAYER M5 ;
        RECT  16.608 86.316 16.632 86.4 ;
    END
  END p_data[39]
  PIN p_data[3]
    DIRECTION OUTPUT ;
    USE SIGNAL ;
    PORT
      LAYER M5 ;
        RECT  14.88 86.316 14.904 86.4 ;
    END
  END p_data[3]
  PIN p_data[400]
    DIRECTION OUTPUT ;
    USE SIGNAL ;
    PORT
      LAYER M5 ;
        RECT  33.936 86.316 33.96 86.4 ;
    END
  END p_data[400]
  PIN p_data[401]
    DIRECTION OUTPUT ;
    USE SIGNAL ;
    PORT
      LAYER M5 ;
        RECT  33.984 86.316 34.008 86.4 ;
    END
  END p_data[401]
  PIN p_data[402]
    DIRECTION OUTPUT ;
    USE SIGNAL ;
    PORT
      LAYER M5 ;
        RECT  34.032 86.316 34.056 86.4 ;
    END
  END p_data[402]
  PIN p_data[403]
    DIRECTION OUTPUT ;
    USE SIGNAL ;
    PORT
      LAYER M5 ;
        RECT  34.08 86.316 34.104 86.4 ;
    END
  END p_data[403]
  PIN p_data[404]
    DIRECTION OUTPUT ;
    USE SIGNAL ;
    PORT
      LAYER M5 ;
        RECT  34.128 86.316 34.152 86.4 ;
    END
  END p_data[404]
  PIN p_data[405]
    DIRECTION OUTPUT ;
    USE SIGNAL ;
    PORT
      LAYER M5 ;
        RECT  34.176 86.316 34.2 86.4 ;
    END
  END p_data[405]
  PIN p_data[406]
    DIRECTION OUTPUT ;
    USE SIGNAL ;
    PORT
      LAYER M5 ;
        RECT  34.224 86.316 34.248 86.4 ;
    END
  END p_data[406]
  PIN p_data[407]
    DIRECTION OUTPUT ;
    USE SIGNAL ;
    PORT
      LAYER M5 ;
        RECT  34.272 86.316 34.296 86.4 ;
    END
  END p_data[407]
  PIN p_data[408]
    DIRECTION OUTPUT ;
    USE SIGNAL ;
    PORT
      LAYER M5 ;
        RECT  34.32 86.316 34.344 86.4 ;
    END
  END p_data[408]
  PIN p_data[409]
    DIRECTION OUTPUT ;
    USE SIGNAL ;
    PORT
      LAYER M5 ;
        RECT  34.368 86.316 34.392 86.4 ;
    END
  END p_data[409]
  PIN p_data[40]
    DIRECTION OUTPUT ;
    USE SIGNAL ;
    PORT
      LAYER M5 ;
        RECT  16.656 86.316 16.68 86.4 ;
    END
  END p_data[40]
  PIN p_data[410]
    DIRECTION OUTPUT ;
    USE SIGNAL ;
    PORT
      LAYER M5 ;
        RECT  34.416 86.316 34.44 86.4 ;
    END
  END p_data[410]
  PIN p_data[411]
    DIRECTION OUTPUT ;
    USE SIGNAL ;
    PORT
      LAYER M5 ;
        RECT  34.464 86.316 34.488 86.4 ;
    END
  END p_data[411]
  PIN p_data[412]
    DIRECTION OUTPUT ;
    USE SIGNAL ;
    PORT
      LAYER M5 ;
        RECT  34.512 86.316 34.536 86.4 ;
    END
  END p_data[412]
  PIN p_data[413]
    DIRECTION OUTPUT ;
    USE SIGNAL ;
    PORT
      LAYER M5 ;
        RECT  34.56 86.316 34.584 86.4 ;
    END
  END p_data[413]
  PIN p_data[414]
    DIRECTION OUTPUT ;
    USE SIGNAL ;
    PORT
      LAYER M5 ;
        RECT  34.608 86.316 34.632 86.4 ;
    END
  END p_data[414]
  PIN p_data[415]
    DIRECTION OUTPUT ;
    USE SIGNAL ;
    PORT
      LAYER M5 ;
        RECT  34.656 86.316 34.68 86.4 ;
    END
  END p_data[415]
  PIN p_data[416]
    DIRECTION OUTPUT ;
    USE SIGNAL ;
    PORT
      LAYER M5 ;
        RECT  34.704 86.316 34.728 86.4 ;
    END
  END p_data[416]
  PIN p_data[417]
    DIRECTION OUTPUT ;
    USE SIGNAL ;
    PORT
      LAYER M5 ;
        RECT  34.752 86.316 34.776 86.4 ;
    END
  END p_data[417]
  PIN p_data[418]
    DIRECTION OUTPUT ;
    USE SIGNAL ;
    PORT
      LAYER M5 ;
        RECT  34.8 86.316 34.824 86.4 ;
    END
  END p_data[418]
  PIN p_data[419]
    DIRECTION OUTPUT ;
    USE SIGNAL ;
    PORT
      LAYER M5 ;
        RECT  34.848 86.316 34.872 86.4 ;
    END
  END p_data[419]
  PIN p_data[41]
    DIRECTION OUTPUT ;
    USE SIGNAL ;
    PORT
      LAYER M5 ;
        RECT  16.704 86.316 16.728 86.4 ;
    END
  END p_data[41]
  PIN p_data[420]
    DIRECTION OUTPUT ;
    USE SIGNAL ;
    PORT
      LAYER M5 ;
        RECT  34.896 86.316 34.92 86.4 ;
    END
  END p_data[420]
  PIN p_data[421]
    DIRECTION OUTPUT ;
    USE SIGNAL ;
    PORT
      LAYER M5 ;
        RECT  34.944 86.316 34.968 86.4 ;
    END
  END p_data[421]
  PIN p_data[422]
    DIRECTION OUTPUT ;
    USE SIGNAL ;
    PORT
      LAYER M5 ;
        RECT  34.992 86.316 35.016 86.4 ;
    END
  END p_data[422]
  PIN p_data[423]
    DIRECTION OUTPUT ;
    USE SIGNAL ;
    PORT
      LAYER M5 ;
        RECT  35.04 86.316 35.064 86.4 ;
    END
  END p_data[423]
  PIN p_data[424]
    DIRECTION OUTPUT ;
    USE SIGNAL ;
    PORT
      LAYER M5 ;
        RECT  35.088 86.316 35.112 86.4 ;
    END
  END p_data[424]
  PIN p_data[425]
    DIRECTION OUTPUT ;
    USE SIGNAL ;
    PORT
      LAYER M5 ;
        RECT  35.136 86.316 35.16 86.4 ;
    END
  END p_data[425]
  PIN p_data[426]
    DIRECTION OUTPUT ;
    USE SIGNAL ;
    PORT
      LAYER M5 ;
        RECT  35.184 86.316 35.208 86.4 ;
    END
  END p_data[426]
  PIN p_data[427]
    DIRECTION OUTPUT ;
    USE SIGNAL ;
    PORT
      LAYER M5 ;
        RECT  35.232 86.316 35.256 86.4 ;
    END
  END p_data[427]
  PIN p_data[428]
    DIRECTION OUTPUT ;
    USE SIGNAL ;
    PORT
      LAYER M5 ;
        RECT  35.28 86.316 35.304 86.4 ;
    END
  END p_data[428]
  PIN p_data[429]
    DIRECTION OUTPUT ;
    USE SIGNAL ;
    PORT
      LAYER M5 ;
        RECT  35.328 86.316 35.352 86.4 ;
    END
  END p_data[429]
  PIN p_data[42]
    DIRECTION OUTPUT ;
    USE SIGNAL ;
    PORT
      LAYER M5 ;
        RECT  16.752 86.316 16.776 86.4 ;
    END
  END p_data[42]
  PIN p_data[430]
    DIRECTION OUTPUT ;
    USE SIGNAL ;
    PORT
      LAYER M5 ;
        RECT  35.376 86.316 35.4 86.4 ;
    END
  END p_data[430]
  PIN p_data[431]
    DIRECTION OUTPUT ;
    USE SIGNAL ;
    PORT
      LAYER M5 ;
        RECT  35.424 86.316 35.448 86.4 ;
    END
  END p_data[431]
  PIN p_data[432]
    DIRECTION OUTPUT ;
    USE SIGNAL ;
    PORT
      LAYER M5 ;
        RECT  35.472 86.316 35.496 86.4 ;
    END
  END p_data[432]
  PIN p_data[433]
    DIRECTION OUTPUT ;
    USE SIGNAL ;
    PORT
      LAYER M5 ;
        RECT  35.52 86.316 35.544 86.4 ;
    END
  END p_data[433]
  PIN p_data[434]
    DIRECTION OUTPUT ;
    USE SIGNAL ;
    PORT
      LAYER M5 ;
        RECT  35.568 86.316 35.592 86.4 ;
    END
  END p_data[434]
  PIN p_data[435]
    DIRECTION OUTPUT ;
    USE SIGNAL ;
    PORT
      LAYER M5 ;
        RECT  35.616 86.316 35.64 86.4 ;
    END
  END p_data[435]
  PIN p_data[436]
    DIRECTION OUTPUT ;
    USE SIGNAL ;
    PORT
      LAYER M5 ;
        RECT  35.664 86.316 35.688 86.4 ;
    END
  END p_data[436]
  PIN p_data[437]
    DIRECTION OUTPUT ;
    USE SIGNAL ;
    PORT
      LAYER M5 ;
        RECT  35.712 86.316 35.736 86.4 ;
    END
  END p_data[437]
  PIN p_data[438]
    DIRECTION OUTPUT ;
    USE SIGNAL ;
    PORT
      LAYER M5 ;
        RECT  35.76 86.316 35.784 86.4 ;
    END
  END p_data[438]
  PIN p_data[439]
    DIRECTION OUTPUT ;
    USE SIGNAL ;
    PORT
      LAYER M5 ;
        RECT  35.808 86.316 35.832 86.4 ;
    END
  END p_data[439]
  PIN p_data[43]
    DIRECTION OUTPUT ;
    USE SIGNAL ;
    PORT
      LAYER M5 ;
        RECT  16.8 86.316 16.824 86.4 ;
    END
  END p_data[43]
  PIN p_data[440]
    DIRECTION OUTPUT ;
    USE SIGNAL ;
    PORT
      LAYER M5 ;
        RECT  35.856 86.316 35.88 86.4 ;
    END
  END p_data[440]
  PIN p_data[441]
    DIRECTION OUTPUT ;
    USE SIGNAL ;
    PORT
      LAYER M5 ;
        RECT  35.904 86.316 35.928 86.4 ;
    END
  END p_data[441]
  PIN p_data[442]
    DIRECTION OUTPUT ;
    USE SIGNAL ;
    PORT
      LAYER M5 ;
        RECT  35.952 86.316 35.976 86.4 ;
    END
  END p_data[442]
  PIN p_data[443]
    DIRECTION OUTPUT ;
    USE SIGNAL ;
    PORT
      LAYER M5 ;
        RECT  36 86.316 36.024 86.4 ;
    END
  END p_data[443]
  PIN p_data[444]
    DIRECTION OUTPUT ;
    USE SIGNAL ;
    PORT
      LAYER M5 ;
        RECT  36.048 86.316 36.072 86.4 ;
    END
  END p_data[444]
  PIN p_data[445]
    DIRECTION OUTPUT ;
    USE SIGNAL ;
    PORT
      LAYER M5 ;
        RECT  36.096 86.316 36.12 86.4 ;
    END
  END p_data[445]
  PIN p_data[446]
    DIRECTION OUTPUT ;
    USE SIGNAL ;
    PORT
      LAYER M5 ;
        RECT  36.144 86.316 36.168 86.4 ;
    END
  END p_data[446]
  PIN p_data[447]
    DIRECTION OUTPUT ;
    USE SIGNAL ;
    PORT
      LAYER M5 ;
        RECT  36.192 86.316 36.216 86.4 ;
    END
  END p_data[447]
  PIN p_data[448]
    DIRECTION OUTPUT ;
    USE SIGNAL ;
    PORT
      LAYER M5 ;
        RECT  36.24 86.316 36.264 86.4 ;
    END
  END p_data[448]
  PIN p_data[449]
    DIRECTION OUTPUT ;
    USE SIGNAL ;
    PORT
      LAYER M5 ;
        RECT  36.288 86.316 36.312 86.4 ;
    END
  END p_data[449]
  PIN p_data[44]
    DIRECTION OUTPUT ;
    USE SIGNAL ;
    PORT
      LAYER M5 ;
        RECT  16.848 86.316 16.872 86.4 ;
    END
  END p_data[44]
  PIN p_data[450]
    DIRECTION OUTPUT ;
    USE SIGNAL ;
    PORT
      LAYER M5 ;
        RECT  36.336 86.316 36.36 86.4 ;
    END
  END p_data[450]
  PIN p_data[451]
    DIRECTION OUTPUT ;
    USE SIGNAL ;
    PORT
      LAYER M5 ;
        RECT  36.384 86.316 36.408 86.4 ;
    END
  END p_data[451]
  PIN p_data[452]
    DIRECTION OUTPUT ;
    USE SIGNAL ;
    PORT
      LAYER M5 ;
        RECT  36.432 86.316 36.456 86.4 ;
    END
  END p_data[452]
  PIN p_data[453]
    DIRECTION OUTPUT ;
    USE SIGNAL ;
    PORT
      LAYER M5 ;
        RECT  36.48 86.316 36.504 86.4 ;
    END
  END p_data[453]
  PIN p_data[454]
    DIRECTION OUTPUT ;
    USE SIGNAL ;
    PORT
      LAYER M5 ;
        RECT  36.528 86.316 36.552 86.4 ;
    END
  END p_data[454]
  PIN p_data[455]
    DIRECTION OUTPUT ;
    USE SIGNAL ;
    PORT
      LAYER M5 ;
        RECT  36.576 86.316 36.6 86.4 ;
    END
  END p_data[455]
  PIN p_data[456]
    DIRECTION OUTPUT ;
    USE SIGNAL ;
    PORT
      LAYER M5 ;
        RECT  36.624 86.316 36.648 86.4 ;
    END
  END p_data[456]
  PIN p_data[457]
    DIRECTION OUTPUT ;
    USE SIGNAL ;
    PORT
      LAYER M5 ;
        RECT  36.672 86.316 36.696 86.4 ;
    END
  END p_data[457]
  PIN p_data[458]
    DIRECTION OUTPUT ;
    USE SIGNAL ;
    PORT
      LAYER M5 ;
        RECT  36.72 86.316 36.744 86.4 ;
    END
  END p_data[458]
  PIN p_data[459]
    DIRECTION OUTPUT ;
    USE SIGNAL ;
    PORT
      LAYER M5 ;
        RECT  36.768 86.316 36.792 86.4 ;
    END
  END p_data[459]
  PIN p_data[45]
    DIRECTION OUTPUT ;
    USE SIGNAL ;
    PORT
      LAYER M5 ;
        RECT  16.896 86.316 16.92 86.4 ;
    END
  END p_data[45]
  PIN p_data[460]
    DIRECTION OUTPUT ;
    USE SIGNAL ;
    PORT
      LAYER M5 ;
        RECT  36.816 86.316 36.84 86.4 ;
    END
  END p_data[460]
  PIN p_data[461]
    DIRECTION OUTPUT ;
    USE SIGNAL ;
    PORT
      LAYER M5 ;
        RECT  36.864 86.316 36.888 86.4 ;
    END
  END p_data[461]
  PIN p_data[462]
    DIRECTION OUTPUT ;
    USE SIGNAL ;
    PORT
      LAYER M5 ;
        RECT  36.912 86.316 36.936 86.4 ;
    END
  END p_data[462]
  PIN p_data[463]
    DIRECTION OUTPUT ;
    USE SIGNAL ;
    PORT
      LAYER M5 ;
        RECT  36.96 86.316 36.984 86.4 ;
    END
  END p_data[463]
  PIN p_data[464]
    DIRECTION OUTPUT ;
    USE SIGNAL ;
    PORT
      LAYER M5 ;
        RECT  37.008 86.316 37.032 86.4 ;
    END
  END p_data[464]
  PIN p_data[465]
    DIRECTION OUTPUT ;
    USE SIGNAL ;
    PORT
      LAYER M5 ;
        RECT  37.056 86.316 37.08 86.4 ;
    END
  END p_data[465]
  PIN p_data[466]
    DIRECTION OUTPUT ;
    USE SIGNAL ;
    PORT
      LAYER M5 ;
        RECT  37.104 86.316 37.128 86.4 ;
    END
  END p_data[466]
  PIN p_data[467]
    DIRECTION OUTPUT ;
    USE SIGNAL ;
    PORT
      LAYER M5 ;
        RECT  37.152 86.316 37.176 86.4 ;
    END
  END p_data[467]
  PIN p_data[468]
    DIRECTION OUTPUT ;
    USE SIGNAL ;
    PORT
      LAYER M5 ;
        RECT  37.2 86.316 37.224 86.4 ;
    END
  END p_data[468]
  PIN p_data[469]
    DIRECTION OUTPUT ;
    USE SIGNAL ;
    PORT
      LAYER M5 ;
        RECT  37.248 86.316 37.272 86.4 ;
    END
  END p_data[469]
  PIN p_data[46]
    DIRECTION OUTPUT ;
    USE SIGNAL ;
    PORT
      LAYER M5 ;
        RECT  16.944 86.316 16.968 86.4 ;
    END
  END p_data[46]
  PIN p_data[470]
    DIRECTION OUTPUT ;
    USE SIGNAL ;
    PORT
      LAYER M5 ;
        RECT  37.296 86.316 37.32 86.4 ;
    END
  END p_data[470]
  PIN p_data[471]
    DIRECTION OUTPUT ;
    USE SIGNAL ;
    PORT
      LAYER M5 ;
        RECT  37.344 86.316 37.368 86.4 ;
    END
  END p_data[471]
  PIN p_data[472]
    DIRECTION OUTPUT ;
    USE SIGNAL ;
    PORT
      LAYER M5 ;
        RECT  37.392 86.316 37.416 86.4 ;
    END
  END p_data[472]
  PIN p_data[473]
    DIRECTION OUTPUT ;
    USE SIGNAL ;
    PORT
      LAYER M5 ;
        RECT  37.44 86.316 37.464 86.4 ;
    END
  END p_data[473]
  PIN p_data[474]
    DIRECTION OUTPUT ;
    USE SIGNAL ;
    PORT
      LAYER M5 ;
        RECT  37.488 86.316 37.512 86.4 ;
    END
  END p_data[474]
  PIN p_data[475]
    DIRECTION OUTPUT ;
    USE SIGNAL ;
    PORT
      LAYER M5 ;
        RECT  37.536 86.316 37.56 86.4 ;
    END
  END p_data[475]
  PIN p_data[476]
    DIRECTION OUTPUT ;
    USE SIGNAL ;
    PORT
      LAYER M5 ;
        RECT  37.584 86.316 37.608 86.4 ;
    END
  END p_data[476]
  PIN p_data[477]
    DIRECTION OUTPUT ;
    USE SIGNAL ;
    PORT
      LAYER M5 ;
        RECT  37.632 86.316 37.656 86.4 ;
    END
  END p_data[477]
  PIN p_data[478]
    DIRECTION OUTPUT ;
    USE SIGNAL ;
    PORT
      LAYER M5 ;
        RECT  37.68 86.316 37.704 86.4 ;
    END
  END p_data[478]
  PIN p_data[479]
    DIRECTION OUTPUT ;
    USE SIGNAL ;
    PORT
      LAYER M5 ;
        RECT  37.728 86.316 37.752 86.4 ;
    END
  END p_data[479]
  PIN p_data[47]
    DIRECTION OUTPUT ;
    USE SIGNAL ;
    PORT
      LAYER M5 ;
        RECT  16.992 86.316 17.016 86.4 ;
    END
  END p_data[47]
  PIN p_data[480]
    DIRECTION OUTPUT ;
    USE SIGNAL ;
    PORT
      LAYER M5 ;
        RECT  37.776 86.316 37.8 86.4 ;
    END
  END p_data[480]
  PIN p_data[481]
    DIRECTION OUTPUT ;
    USE SIGNAL ;
    PORT
      LAYER M5 ;
        RECT  37.824 86.316 37.848 86.4 ;
    END
  END p_data[481]
  PIN p_data[482]
    DIRECTION OUTPUT ;
    USE SIGNAL ;
    PORT
      LAYER M5 ;
        RECT  37.872 86.316 37.896 86.4 ;
    END
  END p_data[482]
  PIN p_data[483]
    DIRECTION OUTPUT ;
    USE SIGNAL ;
    PORT
      LAYER M5 ;
        RECT  37.92 86.316 37.944 86.4 ;
    END
  END p_data[483]
  PIN p_data[484]
    DIRECTION OUTPUT ;
    USE SIGNAL ;
    PORT
      LAYER M5 ;
        RECT  37.968 86.316 37.992 86.4 ;
    END
  END p_data[484]
  PIN p_data[485]
    DIRECTION OUTPUT ;
    USE SIGNAL ;
    PORT
      LAYER M5 ;
        RECT  38.016 86.316 38.04 86.4 ;
    END
  END p_data[485]
  PIN p_data[486]
    DIRECTION OUTPUT ;
    USE SIGNAL ;
    PORT
      LAYER M5 ;
        RECT  38.064 86.316 38.088 86.4 ;
    END
  END p_data[486]
  PIN p_data[487]
    DIRECTION OUTPUT ;
    USE SIGNAL ;
    PORT
      LAYER M5 ;
        RECT  38.112 86.316 38.136 86.4 ;
    END
  END p_data[487]
  PIN p_data[488]
    DIRECTION OUTPUT ;
    USE SIGNAL ;
    PORT
      LAYER M5 ;
        RECT  38.16 86.316 38.184 86.4 ;
    END
  END p_data[488]
  PIN p_data[489]
    DIRECTION OUTPUT ;
    USE SIGNAL ;
    PORT
      LAYER M5 ;
        RECT  38.208 86.316 38.232 86.4 ;
    END
  END p_data[489]
  PIN p_data[48]
    DIRECTION OUTPUT ;
    USE SIGNAL ;
    PORT
      LAYER M5 ;
        RECT  17.04 86.316 17.064 86.4 ;
    END
  END p_data[48]
  PIN p_data[490]
    DIRECTION OUTPUT ;
    USE SIGNAL ;
    PORT
      LAYER M5 ;
        RECT  38.256 86.316 38.28 86.4 ;
    END
  END p_data[490]
  PIN p_data[491]
    DIRECTION OUTPUT ;
    USE SIGNAL ;
    PORT
      LAYER M5 ;
        RECT  38.304 86.316 38.328 86.4 ;
    END
  END p_data[491]
  PIN p_data[492]
    DIRECTION OUTPUT ;
    USE SIGNAL ;
    PORT
      LAYER M5 ;
        RECT  38.352 86.316 38.376 86.4 ;
    END
  END p_data[492]
  PIN p_data[493]
    DIRECTION OUTPUT ;
    USE SIGNAL ;
    PORT
      LAYER M5 ;
        RECT  38.4 86.316 38.424 86.4 ;
    END
  END p_data[493]
  PIN p_data[494]
    DIRECTION OUTPUT ;
    USE SIGNAL ;
    PORT
      LAYER M5 ;
        RECT  38.448 86.316 38.472 86.4 ;
    END
  END p_data[494]
  PIN p_data[495]
    DIRECTION OUTPUT ;
    USE SIGNAL ;
    PORT
      LAYER M5 ;
        RECT  38.496 86.316 38.52 86.4 ;
    END
  END p_data[495]
  PIN p_data[496]
    DIRECTION OUTPUT ;
    USE SIGNAL ;
    PORT
      LAYER M5 ;
        RECT  38.544 86.316 38.568 86.4 ;
    END
  END p_data[496]
  PIN p_data[497]
    DIRECTION OUTPUT ;
    USE SIGNAL ;
    PORT
      LAYER M5 ;
        RECT  38.592 86.316 38.616 86.4 ;
    END
  END p_data[497]
  PIN p_data[498]
    DIRECTION OUTPUT ;
    USE SIGNAL ;
    PORT
      LAYER M5 ;
        RECT  38.64 86.316 38.664 86.4 ;
    END
  END p_data[498]
  PIN p_data[499]
    DIRECTION OUTPUT ;
    USE SIGNAL ;
    PORT
      LAYER M5 ;
        RECT  38.688 86.316 38.712 86.4 ;
    END
  END p_data[499]
  PIN p_data[49]
    DIRECTION OUTPUT ;
    USE SIGNAL ;
    PORT
      LAYER M5 ;
        RECT  17.088 86.316 17.112 86.4 ;
    END
  END p_data[49]
  PIN p_data[4]
    DIRECTION OUTPUT ;
    USE SIGNAL ;
    PORT
      LAYER M5 ;
        RECT  14.928 86.316 14.952 86.4 ;
    END
  END p_data[4]
  PIN p_data[500]
    DIRECTION OUTPUT ;
    USE SIGNAL ;
    PORT
      LAYER M5 ;
        RECT  38.736 86.316 38.76 86.4 ;
    END
  END p_data[500]
  PIN p_data[501]
    DIRECTION OUTPUT ;
    USE SIGNAL ;
    PORT
      LAYER M5 ;
        RECT  38.784 86.316 38.808 86.4 ;
    END
  END p_data[501]
  PIN p_data[502]
    DIRECTION OUTPUT ;
    USE SIGNAL ;
    PORT
      LAYER M5 ;
        RECT  38.832 86.316 38.856 86.4 ;
    END
  END p_data[502]
  PIN p_data[503]
    DIRECTION OUTPUT ;
    USE SIGNAL ;
    PORT
      LAYER M5 ;
        RECT  38.88 86.316 38.904 86.4 ;
    END
  END p_data[503]
  PIN p_data[504]
    DIRECTION OUTPUT ;
    USE SIGNAL ;
    PORT
      LAYER M5 ;
        RECT  38.928 86.316 38.952 86.4 ;
    END
  END p_data[504]
  PIN p_data[505]
    DIRECTION OUTPUT ;
    USE SIGNAL ;
    PORT
      LAYER M5 ;
        RECT  38.976 86.316 39 86.4 ;
    END
  END p_data[505]
  PIN p_data[506]
    DIRECTION OUTPUT ;
    USE SIGNAL ;
    PORT
      LAYER M5 ;
        RECT  39.024 86.316 39.048 86.4 ;
    END
  END p_data[506]
  PIN p_data[507]
    DIRECTION OUTPUT ;
    USE SIGNAL ;
    PORT
      LAYER M5 ;
        RECT  39.072 86.316 39.096 86.4 ;
    END
  END p_data[507]
  PIN p_data[508]
    DIRECTION OUTPUT ;
    USE SIGNAL ;
    PORT
      LAYER M5 ;
        RECT  39.12 86.316 39.144 86.4 ;
    END
  END p_data[508]
  PIN p_data[509]
    DIRECTION OUTPUT ;
    USE SIGNAL ;
    PORT
      LAYER M5 ;
        RECT  39.168 86.316 39.192 86.4 ;
    END
  END p_data[509]
  PIN p_data[50]
    DIRECTION OUTPUT ;
    USE SIGNAL ;
    PORT
      LAYER M5 ;
        RECT  17.136 86.316 17.16 86.4 ;
    END
  END p_data[50]
  PIN p_data[510]
    DIRECTION OUTPUT ;
    USE SIGNAL ;
    PORT
      LAYER M5 ;
        RECT  39.216 86.316 39.24 86.4 ;
    END
  END p_data[510]
  PIN p_data[511]
    DIRECTION OUTPUT ;
    USE SIGNAL ;
    PORT
      LAYER M5 ;
        RECT  39.264 86.316 39.288 86.4 ;
    END
  END p_data[511]
  PIN p_data[51]
    DIRECTION OUTPUT ;
    USE SIGNAL ;
    PORT
      LAYER M5 ;
        RECT  17.184 86.316 17.208 86.4 ;
    END
  END p_data[51]
  PIN p_data[52]
    DIRECTION OUTPUT ;
    USE SIGNAL ;
    PORT
      LAYER M5 ;
        RECT  17.232 86.316 17.256 86.4 ;
    END
  END p_data[52]
  PIN p_data[53]
    DIRECTION OUTPUT ;
    USE SIGNAL ;
    PORT
      LAYER M5 ;
        RECT  17.28 86.316 17.304 86.4 ;
    END
  END p_data[53]
  PIN p_data[54]
    DIRECTION OUTPUT ;
    USE SIGNAL ;
    PORT
      LAYER M5 ;
        RECT  17.328 86.316 17.352 86.4 ;
    END
  END p_data[54]
  PIN p_data[55]
    DIRECTION OUTPUT ;
    USE SIGNAL ;
    PORT
      LAYER M5 ;
        RECT  17.376 86.316 17.4 86.4 ;
    END
  END p_data[55]
  PIN p_data[56]
    DIRECTION OUTPUT ;
    USE SIGNAL ;
    PORT
      LAYER M5 ;
        RECT  17.424 86.316 17.448 86.4 ;
    END
  END p_data[56]
  PIN p_data[57]
    DIRECTION OUTPUT ;
    USE SIGNAL ;
    PORT
      LAYER M5 ;
        RECT  17.472 86.316 17.496 86.4 ;
    END
  END p_data[57]
  PIN p_data[58]
    DIRECTION OUTPUT ;
    USE SIGNAL ;
    PORT
      LAYER M5 ;
        RECT  17.52 86.316 17.544 86.4 ;
    END
  END p_data[58]
  PIN p_data[59]
    DIRECTION OUTPUT ;
    USE SIGNAL ;
    PORT
      LAYER M5 ;
        RECT  17.568 86.316 17.592 86.4 ;
    END
  END p_data[59]
  PIN p_data[5]
    DIRECTION OUTPUT ;
    USE SIGNAL ;
    PORT
      LAYER M5 ;
        RECT  14.976 86.316 15 86.4 ;
    END
  END p_data[5]
  PIN p_data[60]
    DIRECTION OUTPUT ;
    USE SIGNAL ;
    PORT
      LAYER M5 ;
        RECT  17.616 86.316 17.64 86.4 ;
    END
  END p_data[60]
  PIN p_data[61]
    DIRECTION OUTPUT ;
    USE SIGNAL ;
    PORT
      LAYER M5 ;
        RECT  17.664 86.316 17.688 86.4 ;
    END
  END p_data[61]
  PIN p_data[62]
    DIRECTION OUTPUT ;
    USE SIGNAL ;
    PORT
      LAYER M5 ;
        RECT  17.712 86.316 17.736 86.4 ;
    END
  END p_data[62]
  PIN p_data[63]
    DIRECTION OUTPUT ;
    USE SIGNAL ;
    PORT
      LAYER M5 ;
        RECT  17.76 86.316 17.784 86.4 ;
    END
  END p_data[63]
  PIN p_data[64]
    DIRECTION OUTPUT ;
    USE SIGNAL ;
    PORT
      LAYER M5 ;
        RECT  17.808 86.316 17.832 86.4 ;
    END
  END p_data[64]
  PIN p_data[65]
    DIRECTION OUTPUT ;
    USE SIGNAL ;
    PORT
      LAYER M5 ;
        RECT  17.856 86.316 17.88 86.4 ;
    END
  END p_data[65]
  PIN p_data[66]
    DIRECTION OUTPUT ;
    USE SIGNAL ;
    PORT
      LAYER M5 ;
        RECT  17.904 86.316 17.928 86.4 ;
    END
  END p_data[66]
  PIN p_data[67]
    DIRECTION OUTPUT ;
    USE SIGNAL ;
    PORT
      LAYER M5 ;
        RECT  17.952 86.316 17.976 86.4 ;
    END
  END p_data[67]
  PIN p_data[68]
    DIRECTION OUTPUT ;
    USE SIGNAL ;
    PORT
      LAYER M5 ;
        RECT  18 86.316 18.024 86.4 ;
    END
  END p_data[68]
  PIN p_data[69]
    DIRECTION OUTPUT ;
    USE SIGNAL ;
    PORT
      LAYER M5 ;
        RECT  18.048 86.316 18.072 86.4 ;
    END
  END p_data[69]
  PIN p_data[6]
    DIRECTION OUTPUT ;
    USE SIGNAL ;
    PORT
      LAYER M5 ;
        RECT  15.024 86.316 15.048 86.4 ;
    END
  END p_data[6]
  PIN p_data[70]
    DIRECTION OUTPUT ;
    USE SIGNAL ;
    PORT
      LAYER M5 ;
        RECT  18.096 86.316 18.12 86.4 ;
    END
  END p_data[70]
  PIN p_data[71]
    DIRECTION OUTPUT ;
    USE SIGNAL ;
    PORT
      LAYER M5 ;
        RECT  18.144 86.316 18.168 86.4 ;
    END
  END p_data[71]
  PIN p_data[72]
    DIRECTION OUTPUT ;
    USE SIGNAL ;
    PORT
      LAYER M5 ;
        RECT  18.192 86.316 18.216 86.4 ;
    END
  END p_data[72]
  PIN p_data[73]
    DIRECTION OUTPUT ;
    USE SIGNAL ;
    PORT
      LAYER M5 ;
        RECT  18.24 86.316 18.264 86.4 ;
    END
  END p_data[73]
  PIN p_data[74]
    DIRECTION OUTPUT ;
    USE SIGNAL ;
    PORT
      LAYER M5 ;
        RECT  18.288 86.316 18.312 86.4 ;
    END
  END p_data[74]
  PIN p_data[75]
    DIRECTION OUTPUT ;
    USE SIGNAL ;
    PORT
      LAYER M5 ;
        RECT  18.336 86.316 18.36 86.4 ;
    END
  END p_data[75]
  PIN p_data[76]
    DIRECTION OUTPUT ;
    USE SIGNAL ;
    PORT
      LAYER M5 ;
        RECT  18.384 86.316 18.408 86.4 ;
    END
  END p_data[76]
  PIN p_data[77]
    DIRECTION OUTPUT ;
    USE SIGNAL ;
    PORT
      LAYER M5 ;
        RECT  18.432 86.316 18.456 86.4 ;
    END
  END p_data[77]
  PIN p_data[78]
    DIRECTION OUTPUT ;
    USE SIGNAL ;
    PORT
      LAYER M5 ;
        RECT  18.48 86.316 18.504 86.4 ;
    END
  END p_data[78]
  PIN p_data[79]
    DIRECTION OUTPUT ;
    USE SIGNAL ;
    PORT
      LAYER M5 ;
        RECT  18.528 86.316 18.552 86.4 ;
    END
  END p_data[79]
  PIN p_data[7]
    DIRECTION OUTPUT ;
    USE SIGNAL ;
    PORT
      LAYER M5 ;
        RECT  15.072 86.316 15.096 86.4 ;
    END
  END p_data[7]
  PIN p_data[80]
    DIRECTION OUTPUT ;
    USE SIGNAL ;
    PORT
      LAYER M5 ;
        RECT  18.576 86.316 18.6 86.4 ;
    END
  END p_data[80]
  PIN p_data[81]
    DIRECTION OUTPUT ;
    USE SIGNAL ;
    PORT
      LAYER M5 ;
        RECT  18.624 86.316 18.648 86.4 ;
    END
  END p_data[81]
  PIN p_data[82]
    DIRECTION OUTPUT ;
    USE SIGNAL ;
    PORT
      LAYER M5 ;
        RECT  18.672 86.316 18.696 86.4 ;
    END
  END p_data[82]
  PIN p_data[83]
    DIRECTION OUTPUT ;
    USE SIGNAL ;
    PORT
      LAYER M5 ;
        RECT  18.72 86.316 18.744 86.4 ;
    END
  END p_data[83]
  PIN p_data[84]
    DIRECTION OUTPUT ;
    USE SIGNAL ;
    PORT
      LAYER M5 ;
        RECT  18.768 86.316 18.792 86.4 ;
    END
  END p_data[84]
  PIN p_data[85]
    DIRECTION OUTPUT ;
    USE SIGNAL ;
    PORT
      LAYER M5 ;
        RECT  18.816 86.316 18.84 86.4 ;
    END
  END p_data[85]
  PIN p_data[86]
    DIRECTION OUTPUT ;
    USE SIGNAL ;
    PORT
      LAYER M5 ;
        RECT  18.864 86.316 18.888 86.4 ;
    END
  END p_data[86]
  PIN p_data[87]
    DIRECTION OUTPUT ;
    USE SIGNAL ;
    PORT
      LAYER M5 ;
        RECT  18.912 86.316 18.936 86.4 ;
    END
  END p_data[87]
  PIN p_data[88]
    DIRECTION OUTPUT ;
    USE SIGNAL ;
    PORT
      LAYER M5 ;
        RECT  18.96 86.316 18.984 86.4 ;
    END
  END p_data[88]
  PIN p_data[89]
    DIRECTION OUTPUT ;
    USE SIGNAL ;
    PORT
      LAYER M5 ;
        RECT  19.008 86.316 19.032 86.4 ;
    END
  END p_data[89]
  PIN p_data[8]
    DIRECTION OUTPUT ;
    USE SIGNAL ;
    PORT
      LAYER M5 ;
        RECT  15.12 86.316 15.144 86.4 ;
    END
  END p_data[8]
  PIN p_data[90]
    DIRECTION OUTPUT ;
    USE SIGNAL ;
    PORT
      LAYER M5 ;
        RECT  19.056 86.316 19.08 86.4 ;
    END
  END p_data[90]
  PIN p_data[91]
    DIRECTION OUTPUT ;
    USE SIGNAL ;
    PORT
      LAYER M5 ;
        RECT  19.104 86.316 19.128 86.4 ;
    END
  END p_data[91]
  PIN p_data[92]
    DIRECTION OUTPUT ;
    USE SIGNAL ;
    PORT
      LAYER M5 ;
        RECT  19.152 86.316 19.176 86.4 ;
    END
  END p_data[92]
  PIN p_data[93]
    DIRECTION OUTPUT ;
    USE SIGNAL ;
    PORT
      LAYER M5 ;
        RECT  19.2 86.316 19.224 86.4 ;
    END
  END p_data[93]
  PIN p_data[94]
    DIRECTION OUTPUT ;
    USE SIGNAL ;
    PORT
      LAYER M5 ;
        RECT  19.248 86.316 19.272 86.4 ;
    END
  END p_data[94]
  PIN p_data[95]
    DIRECTION OUTPUT ;
    USE SIGNAL ;
    PORT
      LAYER M5 ;
        RECT  19.296 86.316 19.32 86.4 ;
    END
  END p_data[95]
  PIN p_data[96]
    DIRECTION OUTPUT ;
    USE SIGNAL ;
    PORT
      LAYER M5 ;
        RECT  19.344 86.316 19.368 86.4 ;
    END
  END p_data[96]
  PIN p_data[97]
    DIRECTION OUTPUT ;
    USE SIGNAL ;
    PORT
      LAYER M5 ;
        RECT  19.392 86.316 19.416 86.4 ;
    END
  END p_data[97]
  PIN p_data[98]
    DIRECTION OUTPUT ;
    USE SIGNAL ;
    PORT
      LAYER M5 ;
        RECT  19.44 86.316 19.464 86.4 ;
    END
  END p_data[98]
  PIN p_data[99]
    DIRECTION OUTPUT ;
    USE SIGNAL ;
    PORT
      LAYER M5 ;
        RECT  19.488 86.316 19.512 86.4 ;
    END
  END p_data[99]
  PIN p_data[9]
    DIRECTION OUTPUT ;
    USE SIGNAL ;
    PORT
      LAYER M5 ;
        RECT  15.168 86.316 15.192 86.4 ;
    END
  END p_data[9]
  PIN p_v
    DIRECTION OUTPUT ;
    USE SIGNAL ;
    PORT
      LAYER M5 ;
        RECT  39.312 86.316 39.336 86.4 ;
    END
  END p_v
  PIN rst_n
    DIRECTION INPUT ;
    USE SIGNAL ;
    PORT
      LAYER M5 ;
        RECT  13.344 86.316 13.368 86.4 ;
    END
  END rst_n
  PIN u_data[0]
    DIRECTION INPUT ;
    USE SIGNAL ;
    PORT
      LAYER M5 ;
        RECT  14.688 0 14.712 0.084 ;
    END
  END u_data[0]
  PIN u_data[100]
    DIRECTION INPUT ;
    USE SIGNAL ;
    PORT
      LAYER M5 ;
        RECT  19.488 0 19.512 0.084 ;
    END
  END u_data[100]
  PIN u_data[101]
    DIRECTION INPUT ;
    USE SIGNAL ;
    PORT
      LAYER M5 ;
        RECT  19.536 0 19.56 0.084 ;
    END
  END u_data[101]
  PIN u_data[102]
    DIRECTION INPUT ;
    USE SIGNAL ;
    PORT
      LAYER M5 ;
        RECT  19.584 0 19.608 0.084 ;
    END
  END u_data[102]
  PIN u_data[103]
    DIRECTION INPUT ;
    USE SIGNAL ;
    PORT
      LAYER M5 ;
        RECT  19.632 0 19.656 0.084 ;
    END
  END u_data[103]
  PIN u_data[104]
    DIRECTION INPUT ;
    USE SIGNAL ;
    PORT
      LAYER M5 ;
        RECT  19.68 0 19.704 0.084 ;
    END
  END u_data[104]
  PIN u_data[105]
    DIRECTION INPUT ;
    USE SIGNAL ;
    PORT
      LAYER M5 ;
        RECT  19.728 0 19.752 0.084 ;
    END
  END u_data[105]
  PIN u_data[106]
    DIRECTION INPUT ;
    USE SIGNAL ;
    PORT
      LAYER M5 ;
        RECT  19.776 0 19.8 0.084 ;
    END
  END u_data[106]
  PIN u_data[107]
    DIRECTION INPUT ;
    USE SIGNAL ;
    PORT
      LAYER M5 ;
        RECT  19.824 0 19.848 0.084 ;
    END
  END u_data[107]
  PIN u_data[108]
    DIRECTION INPUT ;
    USE SIGNAL ;
    PORT
      LAYER M5 ;
        RECT  19.872 0 19.896 0.084 ;
    END
  END u_data[108]
  PIN u_data[109]
    DIRECTION INPUT ;
    USE SIGNAL ;
    PORT
      LAYER M5 ;
        RECT  19.92 0 19.944 0.084 ;
    END
  END u_data[109]
  PIN u_data[10]
    DIRECTION INPUT ;
    USE SIGNAL ;
    PORT
      LAYER M5 ;
        RECT  15.168 0 15.192 0.084 ;
    END
  END u_data[10]
  PIN u_data[110]
    DIRECTION INPUT ;
    USE SIGNAL ;
    PORT
      LAYER M5 ;
        RECT  19.968 0 19.992 0.084 ;
    END
  END u_data[110]
  PIN u_data[111]
    DIRECTION INPUT ;
    USE SIGNAL ;
    PORT
      LAYER M5 ;
        RECT  20.016 0 20.04 0.084 ;
    END
  END u_data[111]
  PIN u_data[112]
    DIRECTION INPUT ;
    USE SIGNAL ;
    PORT
      LAYER M5 ;
        RECT  20.064 0 20.088 0.084 ;
    END
  END u_data[112]
  PIN u_data[113]
    DIRECTION INPUT ;
    USE SIGNAL ;
    PORT
      LAYER M5 ;
        RECT  20.112 0 20.136 0.084 ;
    END
  END u_data[113]
  PIN u_data[114]
    DIRECTION INPUT ;
    USE SIGNAL ;
    PORT
      LAYER M5 ;
        RECT  20.16 0 20.184 0.084 ;
    END
  END u_data[114]
  PIN u_data[115]
    DIRECTION INPUT ;
    USE SIGNAL ;
    PORT
      LAYER M5 ;
        RECT  20.208 0 20.232 0.084 ;
    END
  END u_data[115]
  PIN u_data[116]
    DIRECTION INPUT ;
    USE SIGNAL ;
    PORT
      LAYER M5 ;
        RECT  20.256 0 20.28 0.084 ;
    END
  END u_data[116]
  PIN u_data[117]
    DIRECTION INPUT ;
    USE SIGNAL ;
    PORT
      LAYER M5 ;
        RECT  20.304 0 20.328 0.084 ;
    END
  END u_data[117]
  PIN u_data[118]
    DIRECTION INPUT ;
    USE SIGNAL ;
    PORT
      LAYER M5 ;
        RECT  20.352 0 20.376 0.084 ;
    END
  END u_data[118]
  PIN u_data[119]
    DIRECTION INPUT ;
    USE SIGNAL ;
    PORT
      LAYER M5 ;
        RECT  20.4 0 20.424 0.084 ;
    END
  END u_data[119]
  PIN u_data[11]
    DIRECTION INPUT ;
    USE SIGNAL ;
    PORT
      LAYER M5 ;
        RECT  15.216 0 15.24 0.084 ;
    END
  END u_data[11]
  PIN u_data[120]
    DIRECTION INPUT ;
    USE SIGNAL ;
    PORT
      LAYER M5 ;
        RECT  20.448 0 20.472 0.084 ;
    END
  END u_data[120]
  PIN u_data[121]
    DIRECTION INPUT ;
    USE SIGNAL ;
    PORT
      LAYER M5 ;
        RECT  20.496 0 20.52 0.084 ;
    END
  END u_data[121]
  PIN u_data[122]
    DIRECTION INPUT ;
    USE SIGNAL ;
    PORT
      LAYER M5 ;
        RECT  20.544 0 20.568 0.084 ;
    END
  END u_data[122]
  PIN u_data[123]
    DIRECTION INPUT ;
    USE SIGNAL ;
    PORT
      LAYER M5 ;
        RECT  20.592 0 20.616 0.084 ;
    END
  END u_data[123]
  PIN u_data[124]
    DIRECTION INPUT ;
    USE SIGNAL ;
    PORT
      LAYER M5 ;
        RECT  20.64 0 20.664 0.084 ;
    END
  END u_data[124]
  PIN u_data[125]
    DIRECTION INPUT ;
    USE SIGNAL ;
    PORT
      LAYER M5 ;
        RECT  20.688 0 20.712 0.084 ;
    END
  END u_data[125]
  PIN u_data[126]
    DIRECTION INPUT ;
    USE SIGNAL ;
    PORT
      LAYER M5 ;
        RECT  20.736 0 20.76 0.084 ;
    END
  END u_data[126]
  PIN u_data[127]
    DIRECTION INPUT ;
    USE SIGNAL ;
    PORT
      LAYER M5 ;
        RECT  20.784 0 20.808 0.084 ;
    END
  END u_data[127]
  PIN u_data[128]
    DIRECTION INPUT ;
    USE SIGNAL ;
    PORT
      LAYER M5 ;
        RECT  20.832 0 20.856 0.084 ;
    END
  END u_data[128]
  PIN u_data[129]
    DIRECTION INPUT ;
    USE SIGNAL ;
    PORT
      LAYER M5 ;
        RECT  20.88 0 20.904 0.084 ;
    END
  END u_data[129]
  PIN u_data[12]
    DIRECTION INPUT ;
    USE SIGNAL ;
    PORT
      LAYER M5 ;
        RECT  15.264 0 15.288 0.084 ;
    END
  END u_data[12]
  PIN u_data[130]
    DIRECTION INPUT ;
    USE SIGNAL ;
    PORT
      LAYER M5 ;
        RECT  20.928 0 20.952 0.084 ;
    END
  END u_data[130]
  PIN u_data[131]
    DIRECTION INPUT ;
    USE SIGNAL ;
    PORT
      LAYER M5 ;
        RECT  20.976 0 21 0.084 ;
    END
  END u_data[131]
  PIN u_data[132]
    DIRECTION INPUT ;
    USE SIGNAL ;
    PORT
      LAYER M5 ;
        RECT  21.024 0 21.048 0.084 ;
    END
  END u_data[132]
  PIN u_data[133]
    DIRECTION INPUT ;
    USE SIGNAL ;
    PORT
      LAYER M5 ;
        RECT  21.072 0 21.096 0.084 ;
    END
  END u_data[133]
  PIN u_data[134]
    DIRECTION INPUT ;
    USE SIGNAL ;
    PORT
      LAYER M5 ;
        RECT  21.12 0 21.144 0.084 ;
    END
  END u_data[134]
  PIN u_data[135]
    DIRECTION INPUT ;
    USE SIGNAL ;
    PORT
      LAYER M5 ;
        RECT  21.168 0 21.192 0.084 ;
    END
  END u_data[135]
  PIN u_data[136]
    DIRECTION INPUT ;
    USE SIGNAL ;
    PORT
      LAYER M5 ;
        RECT  21.216 0 21.24 0.084 ;
    END
  END u_data[136]
  PIN u_data[137]
    DIRECTION INPUT ;
    USE SIGNAL ;
    PORT
      LAYER M5 ;
        RECT  21.264 0 21.288 0.084 ;
    END
  END u_data[137]
  PIN u_data[138]
    DIRECTION INPUT ;
    USE SIGNAL ;
    PORT
      LAYER M5 ;
        RECT  21.312 0 21.336 0.084 ;
    END
  END u_data[138]
  PIN u_data[139]
    DIRECTION INPUT ;
    USE SIGNAL ;
    PORT
      LAYER M5 ;
        RECT  21.36 0 21.384 0.084 ;
    END
  END u_data[139]
  PIN u_data[13]
    DIRECTION INPUT ;
    USE SIGNAL ;
    PORT
      LAYER M5 ;
        RECT  15.312 0 15.336 0.084 ;
    END
  END u_data[13]
  PIN u_data[140]
    DIRECTION INPUT ;
    USE SIGNAL ;
    PORT
      LAYER M5 ;
        RECT  21.408 0 21.432 0.084 ;
    END
  END u_data[140]
  PIN u_data[141]
    DIRECTION INPUT ;
    USE SIGNAL ;
    PORT
      LAYER M5 ;
        RECT  21.456 0 21.48 0.084 ;
    END
  END u_data[141]
  PIN u_data[142]
    DIRECTION INPUT ;
    USE SIGNAL ;
    PORT
      LAYER M5 ;
        RECT  21.504 0 21.528 0.084 ;
    END
  END u_data[142]
  PIN u_data[143]
    DIRECTION INPUT ;
    USE SIGNAL ;
    PORT
      LAYER M5 ;
        RECT  21.552 0 21.576 0.084 ;
    END
  END u_data[143]
  PIN u_data[144]
    DIRECTION INPUT ;
    USE SIGNAL ;
    PORT
      LAYER M5 ;
        RECT  21.6 0 21.624 0.084 ;
    END
  END u_data[144]
  PIN u_data[145]
    DIRECTION INPUT ;
    USE SIGNAL ;
    PORT
      LAYER M5 ;
        RECT  21.648 0 21.672 0.084 ;
    END
  END u_data[145]
  PIN u_data[146]
    DIRECTION INPUT ;
    USE SIGNAL ;
    PORT
      LAYER M5 ;
        RECT  21.696 0 21.72 0.084 ;
    END
  END u_data[146]
  PIN u_data[147]
    DIRECTION INPUT ;
    USE SIGNAL ;
    PORT
      LAYER M5 ;
        RECT  21.744 0 21.768 0.084 ;
    END
  END u_data[147]
  PIN u_data[148]
    DIRECTION INPUT ;
    USE SIGNAL ;
    PORT
      LAYER M5 ;
        RECT  21.792 0 21.816 0.084 ;
    END
  END u_data[148]
  PIN u_data[149]
    DIRECTION INPUT ;
    USE SIGNAL ;
    PORT
      LAYER M5 ;
        RECT  21.84 0 21.864 0.084 ;
    END
  END u_data[149]
  PIN u_data[14]
    DIRECTION INPUT ;
    USE SIGNAL ;
    PORT
      LAYER M5 ;
        RECT  15.36 0 15.384 0.084 ;
    END
  END u_data[14]
  PIN u_data[150]
    DIRECTION INPUT ;
    USE SIGNAL ;
    PORT
      LAYER M5 ;
        RECT  21.888 0 21.912 0.084 ;
    END
  END u_data[150]
  PIN u_data[151]
    DIRECTION INPUT ;
    USE SIGNAL ;
    PORT
      LAYER M5 ;
        RECT  21.936 0 21.96 0.084 ;
    END
  END u_data[151]
  PIN u_data[152]
    DIRECTION INPUT ;
    USE SIGNAL ;
    PORT
      LAYER M5 ;
        RECT  21.984 0 22.008 0.084 ;
    END
  END u_data[152]
  PIN u_data[153]
    DIRECTION INPUT ;
    USE SIGNAL ;
    PORT
      LAYER M5 ;
        RECT  22.032 0 22.056 0.084 ;
    END
  END u_data[153]
  PIN u_data[154]
    DIRECTION INPUT ;
    USE SIGNAL ;
    PORT
      LAYER M5 ;
        RECT  22.08 0 22.104 0.084 ;
    END
  END u_data[154]
  PIN u_data[155]
    DIRECTION INPUT ;
    USE SIGNAL ;
    PORT
      LAYER M5 ;
        RECT  22.128 0 22.152 0.084 ;
    END
  END u_data[155]
  PIN u_data[156]
    DIRECTION INPUT ;
    USE SIGNAL ;
    PORT
      LAYER M5 ;
        RECT  22.176 0 22.2 0.084 ;
    END
  END u_data[156]
  PIN u_data[157]
    DIRECTION INPUT ;
    USE SIGNAL ;
    PORT
      LAYER M5 ;
        RECT  22.224 0 22.248 0.084 ;
    END
  END u_data[157]
  PIN u_data[158]
    DIRECTION INPUT ;
    USE SIGNAL ;
    PORT
      LAYER M5 ;
        RECT  22.272 0 22.296 0.084 ;
    END
  END u_data[158]
  PIN u_data[159]
    DIRECTION INPUT ;
    USE SIGNAL ;
    PORT
      LAYER M5 ;
        RECT  22.32 0 22.344 0.084 ;
    END
  END u_data[159]
  PIN u_data[15]
    DIRECTION INPUT ;
    USE SIGNAL ;
    PORT
      LAYER M5 ;
        RECT  15.408 0 15.432 0.084 ;
    END
  END u_data[15]
  PIN u_data[160]
    DIRECTION INPUT ;
    USE SIGNAL ;
    PORT
      LAYER M5 ;
        RECT  22.368 0 22.392 0.084 ;
    END
  END u_data[160]
  PIN u_data[161]
    DIRECTION INPUT ;
    USE SIGNAL ;
    PORT
      LAYER M5 ;
        RECT  22.416 0 22.44 0.084 ;
    END
  END u_data[161]
  PIN u_data[162]
    DIRECTION INPUT ;
    USE SIGNAL ;
    PORT
      LAYER M5 ;
        RECT  22.464 0 22.488 0.084 ;
    END
  END u_data[162]
  PIN u_data[163]
    DIRECTION INPUT ;
    USE SIGNAL ;
    PORT
      LAYER M5 ;
        RECT  22.512 0 22.536 0.084 ;
    END
  END u_data[163]
  PIN u_data[164]
    DIRECTION INPUT ;
    USE SIGNAL ;
    PORT
      LAYER M5 ;
        RECT  22.56 0 22.584 0.084 ;
    END
  END u_data[164]
  PIN u_data[165]
    DIRECTION INPUT ;
    USE SIGNAL ;
    PORT
      LAYER M5 ;
        RECT  22.608 0 22.632 0.084 ;
    END
  END u_data[165]
  PIN u_data[166]
    DIRECTION INPUT ;
    USE SIGNAL ;
    PORT
      LAYER M5 ;
        RECT  22.656 0 22.68 0.084 ;
    END
  END u_data[166]
  PIN u_data[167]
    DIRECTION INPUT ;
    USE SIGNAL ;
    PORT
      LAYER M5 ;
        RECT  22.704 0 22.728 0.084 ;
    END
  END u_data[167]
  PIN u_data[168]
    DIRECTION INPUT ;
    USE SIGNAL ;
    PORT
      LAYER M5 ;
        RECT  22.752 0 22.776 0.084 ;
    END
  END u_data[168]
  PIN u_data[169]
    DIRECTION INPUT ;
    USE SIGNAL ;
    PORT
      LAYER M5 ;
        RECT  22.8 0 22.824 0.084 ;
    END
  END u_data[169]
  PIN u_data[16]
    DIRECTION INPUT ;
    USE SIGNAL ;
    PORT
      LAYER M5 ;
        RECT  15.456 0 15.48 0.084 ;
    END
  END u_data[16]
  PIN u_data[170]
    DIRECTION INPUT ;
    USE SIGNAL ;
    PORT
      LAYER M5 ;
        RECT  22.848 0 22.872 0.084 ;
    END
  END u_data[170]
  PIN u_data[171]
    DIRECTION INPUT ;
    USE SIGNAL ;
    PORT
      LAYER M5 ;
        RECT  22.896 0 22.92 0.084 ;
    END
  END u_data[171]
  PIN u_data[172]
    DIRECTION INPUT ;
    USE SIGNAL ;
    PORT
      LAYER M5 ;
        RECT  22.944 0 22.968 0.084 ;
    END
  END u_data[172]
  PIN u_data[173]
    DIRECTION INPUT ;
    USE SIGNAL ;
    PORT
      LAYER M5 ;
        RECT  22.992 0 23.016 0.084 ;
    END
  END u_data[173]
  PIN u_data[174]
    DIRECTION INPUT ;
    USE SIGNAL ;
    PORT
      LAYER M5 ;
        RECT  23.04 0 23.064 0.084 ;
    END
  END u_data[174]
  PIN u_data[175]
    DIRECTION INPUT ;
    USE SIGNAL ;
    PORT
      LAYER M5 ;
        RECT  23.088 0 23.112 0.084 ;
    END
  END u_data[175]
  PIN u_data[176]
    DIRECTION INPUT ;
    USE SIGNAL ;
    PORT
      LAYER M5 ;
        RECT  23.136 0 23.16 0.084 ;
    END
  END u_data[176]
  PIN u_data[177]
    DIRECTION INPUT ;
    USE SIGNAL ;
    PORT
      LAYER M5 ;
        RECT  23.184 0 23.208 0.084 ;
    END
  END u_data[177]
  PIN u_data[178]
    DIRECTION INPUT ;
    USE SIGNAL ;
    PORT
      LAYER M5 ;
        RECT  23.232 0 23.256 0.084 ;
    END
  END u_data[178]
  PIN u_data[179]
    DIRECTION INPUT ;
    USE SIGNAL ;
    PORT
      LAYER M5 ;
        RECT  23.28 0 23.304 0.084 ;
    END
  END u_data[179]
  PIN u_data[17]
    DIRECTION INPUT ;
    USE SIGNAL ;
    PORT
      LAYER M5 ;
        RECT  15.504 0 15.528 0.084 ;
    END
  END u_data[17]
  PIN u_data[180]
    DIRECTION INPUT ;
    USE SIGNAL ;
    PORT
      LAYER M5 ;
        RECT  23.328 0 23.352 0.084 ;
    END
  END u_data[180]
  PIN u_data[181]
    DIRECTION INPUT ;
    USE SIGNAL ;
    PORT
      LAYER M5 ;
        RECT  23.376 0 23.4 0.084 ;
    END
  END u_data[181]
  PIN u_data[182]
    DIRECTION INPUT ;
    USE SIGNAL ;
    PORT
      LAYER M5 ;
        RECT  23.424 0 23.448 0.084 ;
    END
  END u_data[182]
  PIN u_data[183]
    DIRECTION INPUT ;
    USE SIGNAL ;
    PORT
      LAYER M5 ;
        RECT  23.472 0 23.496 0.084 ;
    END
  END u_data[183]
  PIN u_data[184]
    DIRECTION INPUT ;
    USE SIGNAL ;
    PORT
      LAYER M5 ;
        RECT  23.52 0 23.544 0.084 ;
    END
  END u_data[184]
  PIN u_data[185]
    DIRECTION INPUT ;
    USE SIGNAL ;
    PORT
      LAYER M5 ;
        RECT  23.568 0 23.592 0.084 ;
    END
  END u_data[185]
  PIN u_data[186]
    DIRECTION INPUT ;
    USE SIGNAL ;
    PORT
      LAYER M5 ;
        RECT  23.616 0 23.64 0.084 ;
    END
  END u_data[186]
  PIN u_data[187]
    DIRECTION INPUT ;
    USE SIGNAL ;
    PORT
      LAYER M5 ;
        RECT  23.664 0 23.688 0.084 ;
    END
  END u_data[187]
  PIN u_data[188]
    DIRECTION INPUT ;
    USE SIGNAL ;
    PORT
      LAYER M5 ;
        RECT  23.712 0 23.736 0.084 ;
    END
  END u_data[188]
  PIN u_data[189]
    DIRECTION INPUT ;
    USE SIGNAL ;
    PORT
      LAYER M5 ;
        RECT  23.76 0 23.784 0.084 ;
    END
  END u_data[189]
  PIN u_data[18]
    DIRECTION INPUT ;
    USE SIGNAL ;
    PORT
      LAYER M5 ;
        RECT  15.552 0 15.576 0.084 ;
    END
  END u_data[18]
  PIN u_data[190]
    DIRECTION INPUT ;
    USE SIGNAL ;
    PORT
      LAYER M5 ;
        RECT  23.808 0 23.832 0.084 ;
    END
  END u_data[190]
  PIN u_data[191]
    DIRECTION INPUT ;
    USE SIGNAL ;
    PORT
      LAYER M5 ;
        RECT  23.856 0 23.88 0.084 ;
    END
  END u_data[191]
  PIN u_data[192]
    DIRECTION INPUT ;
    USE SIGNAL ;
    PORT
      LAYER M5 ;
        RECT  23.904 0 23.928 0.084 ;
    END
  END u_data[192]
  PIN u_data[193]
    DIRECTION INPUT ;
    USE SIGNAL ;
    PORT
      LAYER M5 ;
        RECT  23.952 0 23.976 0.084 ;
    END
  END u_data[193]
  PIN u_data[194]
    DIRECTION INPUT ;
    USE SIGNAL ;
    PORT
      LAYER M5 ;
        RECT  24 0 24.024 0.084 ;
    END
  END u_data[194]
  PIN u_data[195]
    DIRECTION INPUT ;
    USE SIGNAL ;
    PORT
      LAYER M5 ;
        RECT  24.048 0 24.072 0.084 ;
    END
  END u_data[195]
  PIN u_data[196]
    DIRECTION INPUT ;
    USE SIGNAL ;
    PORT
      LAYER M5 ;
        RECT  24.096 0 24.12 0.084 ;
    END
  END u_data[196]
  PIN u_data[197]
    DIRECTION INPUT ;
    USE SIGNAL ;
    PORT
      LAYER M5 ;
        RECT  24.144 0 24.168 0.084 ;
    END
  END u_data[197]
  PIN u_data[198]
    DIRECTION INPUT ;
    USE SIGNAL ;
    PORT
      LAYER M5 ;
        RECT  24.192 0 24.216 0.084 ;
    END
  END u_data[198]
  PIN u_data[199]
    DIRECTION INPUT ;
    USE SIGNAL ;
    PORT
      LAYER M5 ;
        RECT  24.24 0 24.264 0.084 ;
    END
  END u_data[199]
  PIN u_data[19]
    DIRECTION INPUT ;
    USE SIGNAL ;
    PORT
      LAYER M5 ;
        RECT  15.6 0 15.624 0.084 ;
    END
  END u_data[19]
  PIN u_data[1]
    DIRECTION INPUT ;
    USE SIGNAL ;
    PORT
      LAYER M5 ;
        RECT  14.736 0 14.76 0.084 ;
    END
  END u_data[1]
  PIN u_data[200]
    DIRECTION INPUT ;
    USE SIGNAL ;
    PORT
      LAYER M5 ;
        RECT  24.288 0 24.312 0.084 ;
    END
  END u_data[200]
  PIN u_data[201]
    DIRECTION INPUT ;
    USE SIGNAL ;
    PORT
      LAYER M5 ;
        RECT  24.336 0 24.36 0.084 ;
    END
  END u_data[201]
  PIN u_data[202]
    DIRECTION INPUT ;
    USE SIGNAL ;
    PORT
      LAYER M5 ;
        RECT  24.384 0 24.408 0.084 ;
    END
  END u_data[202]
  PIN u_data[203]
    DIRECTION INPUT ;
    USE SIGNAL ;
    PORT
      LAYER M5 ;
        RECT  24.432 0 24.456 0.084 ;
    END
  END u_data[203]
  PIN u_data[204]
    DIRECTION INPUT ;
    USE SIGNAL ;
    PORT
      LAYER M5 ;
        RECT  24.48 0 24.504 0.084 ;
    END
  END u_data[204]
  PIN u_data[205]
    DIRECTION INPUT ;
    USE SIGNAL ;
    PORT
      LAYER M5 ;
        RECT  24.528 0 24.552 0.084 ;
    END
  END u_data[205]
  PIN u_data[206]
    DIRECTION INPUT ;
    USE SIGNAL ;
    PORT
      LAYER M5 ;
        RECT  24.576 0 24.6 0.084 ;
    END
  END u_data[206]
  PIN u_data[207]
    DIRECTION INPUT ;
    USE SIGNAL ;
    PORT
      LAYER M5 ;
        RECT  24.624 0 24.648 0.084 ;
    END
  END u_data[207]
  PIN u_data[208]
    DIRECTION INPUT ;
    USE SIGNAL ;
    PORT
      LAYER M5 ;
        RECT  24.672 0 24.696 0.084 ;
    END
  END u_data[208]
  PIN u_data[209]
    DIRECTION INPUT ;
    USE SIGNAL ;
    PORT
      LAYER M5 ;
        RECT  24.72 0 24.744 0.084 ;
    END
  END u_data[209]
  PIN u_data[20]
    DIRECTION INPUT ;
    USE SIGNAL ;
    PORT
      LAYER M5 ;
        RECT  15.648 0 15.672 0.084 ;
    END
  END u_data[20]
  PIN u_data[210]
    DIRECTION INPUT ;
    USE SIGNAL ;
    PORT
      LAYER M5 ;
        RECT  24.768 0 24.792 0.084 ;
    END
  END u_data[210]
  PIN u_data[211]
    DIRECTION INPUT ;
    USE SIGNAL ;
    PORT
      LAYER M5 ;
        RECT  24.816 0 24.84 0.084 ;
    END
  END u_data[211]
  PIN u_data[212]
    DIRECTION INPUT ;
    USE SIGNAL ;
    PORT
      LAYER M5 ;
        RECT  24.864 0 24.888 0.084 ;
    END
  END u_data[212]
  PIN u_data[213]
    DIRECTION INPUT ;
    USE SIGNAL ;
    PORT
      LAYER M5 ;
        RECT  24.912 0 24.936 0.084 ;
    END
  END u_data[213]
  PIN u_data[214]
    DIRECTION INPUT ;
    USE SIGNAL ;
    PORT
      LAYER M5 ;
        RECT  24.96 0 24.984 0.084 ;
    END
  END u_data[214]
  PIN u_data[215]
    DIRECTION INPUT ;
    USE SIGNAL ;
    PORT
      LAYER M5 ;
        RECT  25.008 0 25.032 0.084 ;
    END
  END u_data[215]
  PIN u_data[216]
    DIRECTION INPUT ;
    USE SIGNAL ;
    PORT
      LAYER M5 ;
        RECT  25.056 0 25.08 0.084 ;
    END
  END u_data[216]
  PIN u_data[217]
    DIRECTION INPUT ;
    USE SIGNAL ;
    PORT
      LAYER M5 ;
        RECT  25.104 0 25.128 0.084 ;
    END
  END u_data[217]
  PIN u_data[218]
    DIRECTION INPUT ;
    USE SIGNAL ;
    PORT
      LAYER M5 ;
        RECT  25.152 0 25.176 0.084 ;
    END
  END u_data[218]
  PIN u_data[219]
    DIRECTION INPUT ;
    USE SIGNAL ;
    PORT
      LAYER M5 ;
        RECT  25.2 0 25.224 0.084 ;
    END
  END u_data[219]
  PIN u_data[21]
    DIRECTION INPUT ;
    USE SIGNAL ;
    PORT
      LAYER M5 ;
        RECT  15.696 0 15.72 0.084 ;
    END
  END u_data[21]
  PIN u_data[220]
    DIRECTION INPUT ;
    USE SIGNAL ;
    PORT
      LAYER M5 ;
        RECT  25.248 0 25.272 0.084 ;
    END
  END u_data[220]
  PIN u_data[221]
    DIRECTION INPUT ;
    USE SIGNAL ;
    PORT
      LAYER M5 ;
        RECT  25.296 0 25.32 0.084 ;
    END
  END u_data[221]
  PIN u_data[222]
    DIRECTION INPUT ;
    USE SIGNAL ;
    PORT
      LAYER M5 ;
        RECT  25.344 0 25.368 0.084 ;
    END
  END u_data[222]
  PIN u_data[223]
    DIRECTION INPUT ;
    USE SIGNAL ;
    PORT
      LAYER M5 ;
        RECT  25.392 0 25.416 0.084 ;
    END
  END u_data[223]
  PIN u_data[224]
    DIRECTION INPUT ;
    USE SIGNAL ;
    PORT
      LAYER M5 ;
        RECT  25.44 0 25.464 0.084 ;
    END
  END u_data[224]
  PIN u_data[225]
    DIRECTION INPUT ;
    USE SIGNAL ;
    PORT
      LAYER M5 ;
        RECT  25.488 0 25.512 0.084 ;
    END
  END u_data[225]
  PIN u_data[226]
    DIRECTION INPUT ;
    USE SIGNAL ;
    PORT
      LAYER M5 ;
        RECT  25.536 0 25.56 0.084 ;
    END
  END u_data[226]
  PIN u_data[227]
    DIRECTION INPUT ;
    USE SIGNAL ;
    PORT
      LAYER M5 ;
        RECT  25.584 0 25.608 0.084 ;
    END
  END u_data[227]
  PIN u_data[228]
    DIRECTION INPUT ;
    USE SIGNAL ;
    PORT
      LAYER M5 ;
        RECT  25.632 0 25.656 0.084 ;
    END
  END u_data[228]
  PIN u_data[229]
    DIRECTION INPUT ;
    USE SIGNAL ;
    PORT
      LAYER M5 ;
        RECT  25.68 0 25.704 0.084 ;
    END
  END u_data[229]
  PIN u_data[22]
    DIRECTION INPUT ;
    USE SIGNAL ;
    PORT
      LAYER M5 ;
        RECT  15.744 0 15.768 0.084 ;
    END
  END u_data[22]
  PIN u_data[230]
    DIRECTION INPUT ;
    USE SIGNAL ;
    PORT
      LAYER M5 ;
        RECT  25.728 0 25.752 0.084 ;
    END
  END u_data[230]
  PIN u_data[231]
    DIRECTION INPUT ;
    USE SIGNAL ;
    PORT
      LAYER M5 ;
        RECT  25.776 0 25.8 0.084 ;
    END
  END u_data[231]
  PIN u_data[232]
    DIRECTION INPUT ;
    USE SIGNAL ;
    PORT
      LAYER M5 ;
        RECT  25.824 0 25.848 0.084 ;
    END
  END u_data[232]
  PIN u_data[233]
    DIRECTION INPUT ;
    USE SIGNAL ;
    PORT
      LAYER M5 ;
        RECT  25.872 0 25.896 0.084 ;
    END
  END u_data[233]
  PIN u_data[234]
    DIRECTION INPUT ;
    USE SIGNAL ;
    PORT
      LAYER M5 ;
        RECT  25.92 0 25.944 0.084 ;
    END
  END u_data[234]
  PIN u_data[235]
    DIRECTION INPUT ;
    USE SIGNAL ;
    PORT
      LAYER M5 ;
        RECT  25.968 0 25.992 0.084 ;
    END
  END u_data[235]
  PIN u_data[236]
    DIRECTION INPUT ;
    USE SIGNAL ;
    PORT
      LAYER M5 ;
        RECT  26.016 0 26.04 0.084 ;
    END
  END u_data[236]
  PIN u_data[237]
    DIRECTION INPUT ;
    USE SIGNAL ;
    PORT
      LAYER M5 ;
        RECT  26.064 0 26.088 0.084 ;
    END
  END u_data[237]
  PIN u_data[238]
    DIRECTION INPUT ;
    USE SIGNAL ;
    PORT
      LAYER M5 ;
        RECT  26.112 0 26.136 0.084 ;
    END
  END u_data[238]
  PIN u_data[239]
    DIRECTION INPUT ;
    USE SIGNAL ;
    PORT
      LAYER M5 ;
        RECT  26.16 0 26.184 0.084 ;
    END
  END u_data[239]
  PIN u_data[23]
    DIRECTION INPUT ;
    USE SIGNAL ;
    PORT
      LAYER M5 ;
        RECT  15.792 0 15.816 0.084 ;
    END
  END u_data[23]
  PIN u_data[240]
    DIRECTION INPUT ;
    USE SIGNAL ;
    PORT
      LAYER M5 ;
        RECT  26.208 0 26.232 0.084 ;
    END
  END u_data[240]
  PIN u_data[241]
    DIRECTION INPUT ;
    USE SIGNAL ;
    PORT
      LAYER M5 ;
        RECT  26.256 0 26.28 0.084 ;
    END
  END u_data[241]
  PIN u_data[242]
    DIRECTION INPUT ;
    USE SIGNAL ;
    PORT
      LAYER M5 ;
        RECT  26.304 0 26.328 0.084 ;
    END
  END u_data[242]
  PIN u_data[243]
    DIRECTION INPUT ;
    USE SIGNAL ;
    PORT
      LAYER M5 ;
        RECT  26.352 0 26.376 0.084 ;
    END
  END u_data[243]
  PIN u_data[244]
    DIRECTION INPUT ;
    USE SIGNAL ;
    PORT
      LAYER M5 ;
        RECT  26.4 0 26.424 0.084 ;
    END
  END u_data[244]
  PIN u_data[245]
    DIRECTION INPUT ;
    USE SIGNAL ;
    PORT
      LAYER M5 ;
        RECT  26.448 0 26.472 0.084 ;
    END
  END u_data[245]
  PIN u_data[246]
    DIRECTION INPUT ;
    USE SIGNAL ;
    PORT
      LAYER M5 ;
        RECT  26.496 0 26.52 0.084 ;
    END
  END u_data[246]
  PIN u_data[247]
    DIRECTION INPUT ;
    USE SIGNAL ;
    PORT
      LAYER M5 ;
        RECT  26.544 0 26.568 0.084 ;
    END
  END u_data[247]
  PIN u_data[248]
    DIRECTION INPUT ;
    USE SIGNAL ;
    PORT
      LAYER M5 ;
        RECT  26.592 0 26.616 0.084 ;
    END
  END u_data[248]
  PIN u_data[249]
    DIRECTION INPUT ;
    USE SIGNAL ;
    PORT
      LAYER M5 ;
        RECT  26.64 0 26.664 0.084 ;
    END
  END u_data[249]
  PIN u_data[24]
    DIRECTION INPUT ;
    USE SIGNAL ;
    PORT
      LAYER M5 ;
        RECT  15.84 0 15.864 0.084 ;
    END
  END u_data[24]
  PIN u_data[250]
    DIRECTION INPUT ;
    USE SIGNAL ;
    PORT
      LAYER M5 ;
        RECT  26.688 0 26.712 0.084 ;
    END
  END u_data[250]
  PIN u_data[251]
    DIRECTION INPUT ;
    USE SIGNAL ;
    PORT
      LAYER M5 ;
        RECT  26.736 0 26.76 0.084 ;
    END
  END u_data[251]
  PIN u_data[252]
    DIRECTION INPUT ;
    USE SIGNAL ;
    PORT
      LAYER M5 ;
        RECT  26.784 0 26.808 0.084 ;
    END
  END u_data[252]
  PIN u_data[253]
    DIRECTION INPUT ;
    USE SIGNAL ;
    PORT
      LAYER M5 ;
        RECT  26.832 0 26.856 0.084 ;
    END
  END u_data[253]
  PIN u_data[254]
    DIRECTION INPUT ;
    USE SIGNAL ;
    PORT
      LAYER M5 ;
        RECT  26.88 0 26.904 0.084 ;
    END
  END u_data[254]
  PIN u_data[255]
    DIRECTION INPUT ;
    USE SIGNAL ;
    PORT
      LAYER M5 ;
        RECT  26.928 0 26.952 0.084 ;
    END
  END u_data[255]
  PIN u_data[256]
    DIRECTION INPUT ;
    USE SIGNAL ;
    PORT
      LAYER M5 ;
        RECT  26.976 0 27 0.084 ;
    END
  END u_data[256]
  PIN u_data[257]
    DIRECTION INPUT ;
    USE SIGNAL ;
    PORT
      LAYER M5 ;
        RECT  27.024 0 27.048 0.084 ;
    END
  END u_data[257]
  PIN u_data[258]
    DIRECTION INPUT ;
    USE SIGNAL ;
    PORT
      LAYER M5 ;
        RECT  27.072 0 27.096 0.084 ;
    END
  END u_data[258]
  PIN u_data[259]
    DIRECTION INPUT ;
    USE SIGNAL ;
    PORT
      LAYER M5 ;
        RECT  27.12 0 27.144 0.084 ;
    END
  END u_data[259]
  PIN u_data[25]
    DIRECTION INPUT ;
    USE SIGNAL ;
    PORT
      LAYER M5 ;
        RECT  15.888 0 15.912 0.084 ;
    END
  END u_data[25]
  PIN u_data[260]
    DIRECTION INPUT ;
    USE SIGNAL ;
    PORT
      LAYER M5 ;
        RECT  27.168 0 27.192 0.084 ;
    END
  END u_data[260]
  PIN u_data[261]
    DIRECTION INPUT ;
    USE SIGNAL ;
    PORT
      LAYER M5 ;
        RECT  27.216 0 27.24 0.084 ;
    END
  END u_data[261]
  PIN u_data[262]
    DIRECTION INPUT ;
    USE SIGNAL ;
    PORT
      LAYER M5 ;
        RECT  27.264 0 27.288 0.084 ;
    END
  END u_data[262]
  PIN u_data[263]
    DIRECTION INPUT ;
    USE SIGNAL ;
    PORT
      LAYER M5 ;
        RECT  27.312 0 27.336 0.084 ;
    END
  END u_data[263]
  PIN u_data[264]
    DIRECTION INPUT ;
    USE SIGNAL ;
    PORT
      LAYER M5 ;
        RECT  27.36 0 27.384 0.084 ;
    END
  END u_data[264]
  PIN u_data[265]
    DIRECTION INPUT ;
    USE SIGNAL ;
    PORT
      LAYER M5 ;
        RECT  27.408 0 27.432 0.084 ;
    END
  END u_data[265]
  PIN u_data[266]
    DIRECTION INPUT ;
    USE SIGNAL ;
    PORT
      LAYER M5 ;
        RECT  27.456 0 27.48 0.084 ;
    END
  END u_data[266]
  PIN u_data[267]
    DIRECTION INPUT ;
    USE SIGNAL ;
    PORT
      LAYER M5 ;
        RECT  27.504 0 27.528 0.084 ;
    END
  END u_data[267]
  PIN u_data[268]
    DIRECTION INPUT ;
    USE SIGNAL ;
    PORT
      LAYER M5 ;
        RECT  27.552 0 27.576 0.084 ;
    END
  END u_data[268]
  PIN u_data[269]
    DIRECTION INPUT ;
    USE SIGNAL ;
    PORT
      LAYER M5 ;
        RECT  27.6 0 27.624 0.084 ;
    END
  END u_data[269]
  PIN u_data[26]
    DIRECTION INPUT ;
    USE SIGNAL ;
    PORT
      LAYER M5 ;
        RECT  15.936 0 15.96 0.084 ;
    END
  END u_data[26]
  PIN u_data[270]
    DIRECTION INPUT ;
    USE SIGNAL ;
    PORT
      LAYER M5 ;
        RECT  27.648 0 27.672 0.084 ;
    END
  END u_data[270]
  PIN u_data[271]
    DIRECTION INPUT ;
    USE SIGNAL ;
    PORT
      LAYER M5 ;
        RECT  27.696 0 27.72 0.084 ;
    END
  END u_data[271]
  PIN u_data[272]
    DIRECTION INPUT ;
    USE SIGNAL ;
    PORT
      LAYER M5 ;
        RECT  27.744 0 27.768 0.084 ;
    END
  END u_data[272]
  PIN u_data[273]
    DIRECTION INPUT ;
    USE SIGNAL ;
    PORT
      LAYER M5 ;
        RECT  27.792 0 27.816 0.084 ;
    END
  END u_data[273]
  PIN u_data[274]
    DIRECTION INPUT ;
    USE SIGNAL ;
    PORT
      LAYER M5 ;
        RECT  27.84 0 27.864 0.084 ;
    END
  END u_data[274]
  PIN u_data[275]
    DIRECTION INPUT ;
    USE SIGNAL ;
    PORT
      LAYER M5 ;
        RECT  27.888 0 27.912 0.084 ;
    END
  END u_data[275]
  PIN u_data[276]
    DIRECTION INPUT ;
    USE SIGNAL ;
    PORT
      LAYER M5 ;
        RECT  27.936 0 27.96 0.084 ;
    END
  END u_data[276]
  PIN u_data[277]
    DIRECTION INPUT ;
    USE SIGNAL ;
    PORT
      LAYER M5 ;
        RECT  27.984 0 28.008 0.084 ;
    END
  END u_data[277]
  PIN u_data[278]
    DIRECTION INPUT ;
    USE SIGNAL ;
    PORT
      LAYER M5 ;
        RECT  28.032 0 28.056 0.084 ;
    END
  END u_data[278]
  PIN u_data[279]
    DIRECTION INPUT ;
    USE SIGNAL ;
    PORT
      LAYER M5 ;
        RECT  28.08 0 28.104 0.084 ;
    END
  END u_data[279]
  PIN u_data[27]
    DIRECTION INPUT ;
    USE SIGNAL ;
    PORT
      LAYER M5 ;
        RECT  15.984 0 16.008 0.084 ;
    END
  END u_data[27]
  PIN u_data[280]
    DIRECTION INPUT ;
    USE SIGNAL ;
    PORT
      LAYER M5 ;
        RECT  28.128 0 28.152 0.084 ;
    END
  END u_data[280]
  PIN u_data[281]
    DIRECTION INPUT ;
    USE SIGNAL ;
    PORT
      LAYER M5 ;
        RECT  28.176 0 28.2 0.084 ;
    END
  END u_data[281]
  PIN u_data[282]
    DIRECTION INPUT ;
    USE SIGNAL ;
    PORT
      LAYER M5 ;
        RECT  28.224 0 28.248 0.084 ;
    END
  END u_data[282]
  PIN u_data[283]
    DIRECTION INPUT ;
    USE SIGNAL ;
    PORT
      LAYER M5 ;
        RECT  28.272 0 28.296 0.084 ;
    END
  END u_data[283]
  PIN u_data[284]
    DIRECTION INPUT ;
    USE SIGNAL ;
    PORT
      LAYER M5 ;
        RECT  28.32 0 28.344 0.084 ;
    END
  END u_data[284]
  PIN u_data[285]
    DIRECTION INPUT ;
    USE SIGNAL ;
    PORT
      LAYER M5 ;
        RECT  28.368 0 28.392 0.084 ;
    END
  END u_data[285]
  PIN u_data[286]
    DIRECTION INPUT ;
    USE SIGNAL ;
    PORT
      LAYER M5 ;
        RECT  28.416 0 28.44 0.084 ;
    END
  END u_data[286]
  PIN u_data[287]
    DIRECTION INPUT ;
    USE SIGNAL ;
    PORT
      LAYER M5 ;
        RECT  28.464 0 28.488 0.084 ;
    END
  END u_data[287]
  PIN u_data[288]
    DIRECTION INPUT ;
    USE SIGNAL ;
    PORT
      LAYER M5 ;
        RECT  28.512 0 28.536 0.084 ;
    END
  END u_data[288]
  PIN u_data[289]
    DIRECTION INPUT ;
    USE SIGNAL ;
    PORT
      LAYER M5 ;
        RECT  28.56 0 28.584 0.084 ;
    END
  END u_data[289]
  PIN u_data[28]
    DIRECTION INPUT ;
    USE SIGNAL ;
    PORT
      LAYER M5 ;
        RECT  16.032 0 16.056 0.084 ;
    END
  END u_data[28]
  PIN u_data[290]
    DIRECTION INPUT ;
    USE SIGNAL ;
    PORT
      LAYER M5 ;
        RECT  28.608 0 28.632 0.084 ;
    END
  END u_data[290]
  PIN u_data[291]
    DIRECTION INPUT ;
    USE SIGNAL ;
    PORT
      LAYER M5 ;
        RECT  28.656 0 28.68 0.084 ;
    END
  END u_data[291]
  PIN u_data[292]
    DIRECTION INPUT ;
    USE SIGNAL ;
    PORT
      LAYER M5 ;
        RECT  28.704 0 28.728 0.084 ;
    END
  END u_data[292]
  PIN u_data[293]
    DIRECTION INPUT ;
    USE SIGNAL ;
    PORT
      LAYER M5 ;
        RECT  28.752 0 28.776 0.084 ;
    END
  END u_data[293]
  PIN u_data[294]
    DIRECTION INPUT ;
    USE SIGNAL ;
    PORT
      LAYER M5 ;
        RECT  28.8 0 28.824 0.084 ;
    END
  END u_data[294]
  PIN u_data[295]
    DIRECTION INPUT ;
    USE SIGNAL ;
    PORT
      LAYER M5 ;
        RECT  28.848 0 28.872 0.084 ;
    END
  END u_data[295]
  PIN u_data[296]
    DIRECTION INPUT ;
    USE SIGNAL ;
    PORT
      LAYER M5 ;
        RECT  28.896 0 28.92 0.084 ;
    END
  END u_data[296]
  PIN u_data[297]
    DIRECTION INPUT ;
    USE SIGNAL ;
    PORT
      LAYER M5 ;
        RECT  28.944 0 28.968 0.084 ;
    END
  END u_data[297]
  PIN u_data[298]
    DIRECTION INPUT ;
    USE SIGNAL ;
    PORT
      LAYER M5 ;
        RECT  28.992 0 29.016 0.084 ;
    END
  END u_data[298]
  PIN u_data[299]
    DIRECTION INPUT ;
    USE SIGNAL ;
    PORT
      LAYER M5 ;
        RECT  29.04 0 29.064 0.084 ;
    END
  END u_data[299]
  PIN u_data[29]
    DIRECTION INPUT ;
    USE SIGNAL ;
    PORT
      LAYER M5 ;
        RECT  16.08 0 16.104 0.084 ;
    END
  END u_data[29]
  PIN u_data[2]
    DIRECTION INPUT ;
    USE SIGNAL ;
    PORT
      LAYER M5 ;
        RECT  14.784 0 14.808 0.084 ;
    END
  END u_data[2]
  PIN u_data[300]
    DIRECTION INPUT ;
    USE SIGNAL ;
    PORT
      LAYER M5 ;
        RECT  29.088 0 29.112 0.084 ;
    END
  END u_data[300]
  PIN u_data[301]
    DIRECTION INPUT ;
    USE SIGNAL ;
    PORT
      LAYER M5 ;
        RECT  29.136 0 29.16 0.084 ;
    END
  END u_data[301]
  PIN u_data[302]
    DIRECTION INPUT ;
    USE SIGNAL ;
    PORT
      LAYER M5 ;
        RECT  29.184 0 29.208 0.084 ;
    END
  END u_data[302]
  PIN u_data[303]
    DIRECTION INPUT ;
    USE SIGNAL ;
    PORT
      LAYER M5 ;
        RECT  29.232 0 29.256 0.084 ;
    END
  END u_data[303]
  PIN u_data[304]
    DIRECTION INPUT ;
    USE SIGNAL ;
    PORT
      LAYER M5 ;
        RECT  29.28 0 29.304 0.084 ;
    END
  END u_data[304]
  PIN u_data[305]
    DIRECTION INPUT ;
    USE SIGNAL ;
    PORT
      LAYER M5 ;
        RECT  29.328 0 29.352 0.084 ;
    END
  END u_data[305]
  PIN u_data[306]
    DIRECTION INPUT ;
    USE SIGNAL ;
    PORT
      LAYER M5 ;
        RECT  29.376 0 29.4 0.084 ;
    END
  END u_data[306]
  PIN u_data[307]
    DIRECTION INPUT ;
    USE SIGNAL ;
    PORT
      LAYER M5 ;
        RECT  29.424 0 29.448 0.084 ;
    END
  END u_data[307]
  PIN u_data[308]
    DIRECTION INPUT ;
    USE SIGNAL ;
    PORT
      LAYER M5 ;
        RECT  29.472 0 29.496 0.084 ;
    END
  END u_data[308]
  PIN u_data[309]
    DIRECTION INPUT ;
    USE SIGNAL ;
    PORT
      LAYER M5 ;
        RECT  29.52 0 29.544 0.084 ;
    END
  END u_data[309]
  PIN u_data[30]
    DIRECTION INPUT ;
    USE SIGNAL ;
    PORT
      LAYER M5 ;
        RECT  16.128 0 16.152 0.084 ;
    END
  END u_data[30]
  PIN u_data[310]
    DIRECTION INPUT ;
    USE SIGNAL ;
    PORT
      LAYER M5 ;
        RECT  29.568 0 29.592 0.084 ;
    END
  END u_data[310]
  PIN u_data[311]
    DIRECTION INPUT ;
    USE SIGNAL ;
    PORT
      LAYER M5 ;
        RECT  29.616 0 29.64 0.084 ;
    END
  END u_data[311]
  PIN u_data[312]
    DIRECTION INPUT ;
    USE SIGNAL ;
    PORT
      LAYER M5 ;
        RECT  29.664 0 29.688 0.084 ;
    END
  END u_data[312]
  PIN u_data[313]
    DIRECTION INPUT ;
    USE SIGNAL ;
    PORT
      LAYER M5 ;
        RECT  29.712 0 29.736 0.084 ;
    END
  END u_data[313]
  PIN u_data[314]
    DIRECTION INPUT ;
    USE SIGNAL ;
    PORT
      LAYER M5 ;
        RECT  29.76 0 29.784 0.084 ;
    END
  END u_data[314]
  PIN u_data[315]
    DIRECTION INPUT ;
    USE SIGNAL ;
    PORT
      LAYER M5 ;
        RECT  29.808 0 29.832 0.084 ;
    END
  END u_data[315]
  PIN u_data[316]
    DIRECTION INPUT ;
    USE SIGNAL ;
    PORT
      LAYER M5 ;
        RECT  29.856 0 29.88 0.084 ;
    END
  END u_data[316]
  PIN u_data[317]
    DIRECTION INPUT ;
    USE SIGNAL ;
    PORT
      LAYER M5 ;
        RECT  29.904 0 29.928 0.084 ;
    END
  END u_data[317]
  PIN u_data[318]
    DIRECTION INPUT ;
    USE SIGNAL ;
    PORT
      LAYER M5 ;
        RECT  29.952 0 29.976 0.084 ;
    END
  END u_data[318]
  PIN u_data[319]
    DIRECTION INPUT ;
    USE SIGNAL ;
    PORT
      LAYER M5 ;
        RECT  30 0 30.024 0.084 ;
    END
  END u_data[319]
  PIN u_data[31]
    DIRECTION INPUT ;
    USE SIGNAL ;
    PORT
      LAYER M5 ;
        RECT  16.176 0 16.2 0.084 ;
    END
  END u_data[31]
  PIN u_data[320]
    DIRECTION INPUT ;
    USE SIGNAL ;
    PORT
      LAYER M5 ;
        RECT  30.048 0 30.072 0.084 ;
    END
  END u_data[320]
  PIN u_data[321]
    DIRECTION INPUT ;
    USE SIGNAL ;
    PORT
      LAYER M5 ;
        RECT  30.096 0 30.12 0.084 ;
    END
  END u_data[321]
  PIN u_data[322]
    DIRECTION INPUT ;
    USE SIGNAL ;
    PORT
      LAYER M5 ;
        RECT  30.144 0 30.168 0.084 ;
    END
  END u_data[322]
  PIN u_data[323]
    DIRECTION INPUT ;
    USE SIGNAL ;
    PORT
      LAYER M5 ;
        RECT  30.192 0 30.216 0.084 ;
    END
  END u_data[323]
  PIN u_data[324]
    DIRECTION INPUT ;
    USE SIGNAL ;
    PORT
      LAYER M5 ;
        RECT  30.24 0 30.264 0.084 ;
    END
  END u_data[324]
  PIN u_data[325]
    DIRECTION INPUT ;
    USE SIGNAL ;
    PORT
      LAYER M5 ;
        RECT  30.288 0 30.312 0.084 ;
    END
  END u_data[325]
  PIN u_data[326]
    DIRECTION INPUT ;
    USE SIGNAL ;
    PORT
      LAYER M5 ;
        RECT  30.336 0 30.36 0.084 ;
    END
  END u_data[326]
  PIN u_data[327]
    DIRECTION INPUT ;
    USE SIGNAL ;
    PORT
      LAYER M5 ;
        RECT  30.384 0 30.408 0.084 ;
    END
  END u_data[327]
  PIN u_data[328]
    DIRECTION INPUT ;
    USE SIGNAL ;
    PORT
      LAYER M5 ;
        RECT  30.432 0 30.456 0.084 ;
    END
  END u_data[328]
  PIN u_data[329]
    DIRECTION INPUT ;
    USE SIGNAL ;
    PORT
      LAYER M5 ;
        RECT  30.48 0 30.504 0.084 ;
    END
  END u_data[329]
  PIN u_data[32]
    DIRECTION INPUT ;
    USE SIGNAL ;
    PORT
      LAYER M5 ;
        RECT  16.224 0 16.248 0.084 ;
    END
  END u_data[32]
  PIN u_data[330]
    DIRECTION INPUT ;
    USE SIGNAL ;
    PORT
      LAYER M5 ;
        RECT  30.528 0 30.552 0.084 ;
    END
  END u_data[330]
  PIN u_data[331]
    DIRECTION INPUT ;
    USE SIGNAL ;
    PORT
      LAYER M5 ;
        RECT  30.576 0 30.6 0.084 ;
    END
  END u_data[331]
  PIN u_data[332]
    DIRECTION INPUT ;
    USE SIGNAL ;
    PORT
      LAYER M5 ;
        RECT  30.624 0 30.648 0.084 ;
    END
  END u_data[332]
  PIN u_data[333]
    DIRECTION INPUT ;
    USE SIGNAL ;
    PORT
      LAYER M5 ;
        RECT  30.672 0 30.696 0.084 ;
    END
  END u_data[333]
  PIN u_data[334]
    DIRECTION INPUT ;
    USE SIGNAL ;
    PORT
      LAYER M5 ;
        RECT  30.72 0 30.744 0.084 ;
    END
  END u_data[334]
  PIN u_data[335]
    DIRECTION INPUT ;
    USE SIGNAL ;
    PORT
      LAYER M5 ;
        RECT  30.768 0 30.792 0.084 ;
    END
  END u_data[335]
  PIN u_data[336]
    DIRECTION INPUT ;
    USE SIGNAL ;
    PORT
      LAYER M5 ;
        RECT  30.816 0 30.84 0.084 ;
    END
  END u_data[336]
  PIN u_data[337]
    DIRECTION INPUT ;
    USE SIGNAL ;
    PORT
      LAYER M5 ;
        RECT  30.864 0 30.888 0.084 ;
    END
  END u_data[337]
  PIN u_data[338]
    DIRECTION INPUT ;
    USE SIGNAL ;
    PORT
      LAYER M5 ;
        RECT  30.912 0 30.936 0.084 ;
    END
  END u_data[338]
  PIN u_data[339]
    DIRECTION INPUT ;
    USE SIGNAL ;
    PORT
      LAYER M5 ;
        RECT  30.96 0 30.984 0.084 ;
    END
  END u_data[339]
  PIN u_data[33]
    DIRECTION INPUT ;
    USE SIGNAL ;
    PORT
      LAYER M5 ;
        RECT  16.272 0 16.296 0.084 ;
    END
  END u_data[33]
  PIN u_data[340]
    DIRECTION INPUT ;
    USE SIGNAL ;
    PORT
      LAYER M5 ;
        RECT  31.008 0 31.032 0.084 ;
    END
  END u_data[340]
  PIN u_data[341]
    DIRECTION INPUT ;
    USE SIGNAL ;
    PORT
      LAYER M5 ;
        RECT  31.056 0 31.08 0.084 ;
    END
  END u_data[341]
  PIN u_data[342]
    DIRECTION INPUT ;
    USE SIGNAL ;
    PORT
      LAYER M5 ;
        RECT  31.104 0 31.128 0.084 ;
    END
  END u_data[342]
  PIN u_data[343]
    DIRECTION INPUT ;
    USE SIGNAL ;
    PORT
      LAYER M5 ;
        RECT  31.152 0 31.176 0.084 ;
    END
  END u_data[343]
  PIN u_data[344]
    DIRECTION INPUT ;
    USE SIGNAL ;
    PORT
      LAYER M5 ;
        RECT  31.2 0 31.224 0.084 ;
    END
  END u_data[344]
  PIN u_data[345]
    DIRECTION INPUT ;
    USE SIGNAL ;
    PORT
      LAYER M5 ;
        RECT  31.248 0 31.272 0.084 ;
    END
  END u_data[345]
  PIN u_data[346]
    DIRECTION INPUT ;
    USE SIGNAL ;
    PORT
      LAYER M5 ;
        RECT  31.296 0 31.32 0.084 ;
    END
  END u_data[346]
  PIN u_data[347]
    DIRECTION INPUT ;
    USE SIGNAL ;
    PORT
      LAYER M5 ;
        RECT  31.344 0 31.368 0.084 ;
    END
  END u_data[347]
  PIN u_data[348]
    DIRECTION INPUT ;
    USE SIGNAL ;
    PORT
      LAYER M5 ;
        RECT  31.392 0 31.416 0.084 ;
    END
  END u_data[348]
  PIN u_data[349]
    DIRECTION INPUT ;
    USE SIGNAL ;
    PORT
      LAYER M5 ;
        RECT  31.44 0 31.464 0.084 ;
    END
  END u_data[349]
  PIN u_data[34]
    DIRECTION INPUT ;
    USE SIGNAL ;
    PORT
      LAYER M5 ;
        RECT  16.32 0 16.344 0.084 ;
    END
  END u_data[34]
  PIN u_data[350]
    DIRECTION INPUT ;
    USE SIGNAL ;
    PORT
      LAYER M5 ;
        RECT  31.488 0 31.512 0.084 ;
    END
  END u_data[350]
  PIN u_data[351]
    DIRECTION INPUT ;
    USE SIGNAL ;
    PORT
      LAYER M5 ;
        RECT  31.536 0 31.56 0.084 ;
    END
  END u_data[351]
  PIN u_data[352]
    DIRECTION INPUT ;
    USE SIGNAL ;
    PORT
      LAYER M5 ;
        RECT  31.584 0 31.608 0.084 ;
    END
  END u_data[352]
  PIN u_data[353]
    DIRECTION INPUT ;
    USE SIGNAL ;
    PORT
      LAYER M5 ;
        RECT  31.632 0 31.656 0.084 ;
    END
  END u_data[353]
  PIN u_data[354]
    DIRECTION INPUT ;
    USE SIGNAL ;
    PORT
      LAYER M5 ;
        RECT  31.68 0 31.704 0.084 ;
    END
  END u_data[354]
  PIN u_data[355]
    DIRECTION INPUT ;
    USE SIGNAL ;
    PORT
      LAYER M5 ;
        RECT  31.728 0 31.752 0.084 ;
    END
  END u_data[355]
  PIN u_data[356]
    DIRECTION INPUT ;
    USE SIGNAL ;
    PORT
      LAYER M5 ;
        RECT  31.776 0 31.8 0.084 ;
    END
  END u_data[356]
  PIN u_data[357]
    DIRECTION INPUT ;
    USE SIGNAL ;
    PORT
      LAYER M5 ;
        RECT  31.824 0 31.848 0.084 ;
    END
  END u_data[357]
  PIN u_data[358]
    DIRECTION INPUT ;
    USE SIGNAL ;
    PORT
      LAYER M5 ;
        RECT  31.872 0 31.896 0.084 ;
    END
  END u_data[358]
  PIN u_data[359]
    DIRECTION INPUT ;
    USE SIGNAL ;
    PORT
      LAYER M5 ;
        RECT  31.92 0 31.944 0.084 ;
    END
  END u_data[359]
  PIN u_data[35]
    DIRECTION INPUT ;
    USE SIGNAL ;
    PORT
      LAYER M5 ;
        RECT  16.368 0 16.392 0.084 ;
    END
  END u_data[35]
  PIN u_data[360]
    DIRECTION INPUT ;
    USE SIGNAL ;
    PORT
      LAYER M5 ;
        RECT  31.968 0 31.992 0.084 ;
    END
  END u_data[360]
  PIN u_data[361]
    DIRECTION INPUT ;
    USE SIGNAL ;
    PORT
      LAYER M5 ;
        RECT  32.016 0 32.04 0.084 ;
    END
  END u_data[361]
  PIN u_data[362]
    DIRECTION INPUT ;
    USE SIGNAL ;
    PORT
      LAYER M5 ;
        RECT  32.064 0 32.088 0.084 ;
    END
  END u_data[362]
  PIN u_data[363]
    DIRECTION INPUT ;
    USE SIGNAL ;
    PORT
      LAYER M5 ;
        RECT  32.112 0 32.136 0.084 ;
    END
  END u_data[363]
  PIN u_data[364]
    DIRECTION INPUT ;
    USE SIGNAL ;
    PORT
      LAYER M5 ;
        RECT  32.16 0 32.184 0.084 ;
    END
  END u_data[364]
  PIN u_data[365]
    DIRECTION INPUT ;
    USE SIGNAL ;
    PORT
      LAYER M5 ;
        RECT  32.208 0 32.232 0.084 ;
    END
  END u_data[365]
  PIN u_data[366]
    DIRECTION INPUT ;
    USE SIGNAL ;
    PORT
      LAYER M5 ;
        RECT  32.256 0 32.28 0.084 ;
    END
  END u_data[366]
  PIN u_data[367]
    DIRECTION INPUT ;
    USE SIGNAL ;
    PORT
      LAYER M5 ;
        RECT  32.304 0 32.328 0.084 ;
    END
  END u_data[367]
  PIN u_data[368]
    DIRECTION INPUT ;
    USE SIGNAL ;
    PORT
      LAYER M5 ;
        RECT  32.352 0 32.376 0.084 ;
    END
  END u_data[368]
  PIN u_data[369]
    DIRECTION INPUT ;
    USE SIGNAL ;
    PORT
      LAYER M5 ;
        RECT  32.4 0 32.424 0.084 ;
    END
  END u_data[369]
  PIN u_data[36]
    DIRECTION INPUT ;
    USE SIGNAL ;
    PORT
      LAYER M5 ;
        RECT  16.416 0 16.44 0.084 ;
    END
  END u_data[36]
  PIN u_data[370]
    DIRECTION INPUT ;
    USE SIGNAL ;
    PORT
      LAYER M5 ;
        RECT  32.448 0 32.472 0.084 ;
    END
  END u_data[370]
  PIN u_data[371]
    DIRECTION INPUT ;
    USE SIGNAL ;
    PORT
      LAYER M5 ;
        RECT  32.496 0 32.52 0.084 ;
    END
  END u_data[371]
  PIN u_data[372]
    DIRECTION INPUT ;
    USE SIGNAL ;
    PORT
      LAYER M5 ;
        RECT  32.544 0 32.568 0.084 ;
    END
  END u_data[372]
  PIN u_data[373]
    DIRECTION INPUT ;
    USE SIGNAL ;
    PORT
      LAYER M5 ;
        RECT  32.592 0 32.616 0.084 ;
    END
  END u_data[373]
  PIN u_data[374]
    DIRECTION INPUT ;
    USE SIGNAL ;
    PORT
      LAYER M5 ;
        RECT  32.64 0 32.664 0.084 ;
    END
  END u_data[374]
  PIN u_data[375]
    DIRECTION INPUT ;
    USE SIGNAL ;
    PORT
      LAYER M5 ;
        RECT  32.688 0 32.712 0.084 ;
    END
  END u_data[375]
  PIN u_data[376]
    DIRECTION INPUT ;
    USE SIGNAL ;
    PORT
      LAYER M5 ;
        RECT  32.736 0 32.76 0.084 ;
    END
  END u_data[376]
  PIN u_data[377]
    DIRECTION INPUT ;
    USE SIGNAL ;
    PORT
      LAYER M5 ;
        RECT  32.784 0 32.808 0.084 ;
    END
  END u_data[377]
  PIN u_data[378]
    DIRECTION INPUT ;
    USE SIGNAL ;
    PORT
      LAYER M5 ;
        RECT  32.832 0 32.856 0.084 ;
    END
  END u_data[378]
  PIN u_data[379]
    DIRECTION INPUT ;
    USE SIGNAL ;
    PORT
      LAYER M5 ;
        RECT  32.88 0 32.904 0.084 ;
    END
  END u_data[379]
  PIN u_data[37]
    DIRECTION INPUT ;
    USE SIGNAL ;
    PORT
      LAYER M5 ;
        RECT  16.464 0 16.488 0.084 ;
    END
  END u_data[37]
  PIN u_data[380]
    DIRECTION INPUT ;
    USE SIGNAL ;
    PORT
      LAYER M5 ;
        RECT  32.928 0 32.952 0.084 ;
    END
  END u_data[380]
  PIN u_data[381]
    DIRECTION INPUT ;
    USE SIGNAL ;
    PORT
      LAYER M5 ;
        RECT  32.976 0 33 0.084 ;
    END
  END u_data[381]
  PIN u_data[382]
    DIRECTION INPUT ;
    USE SIGNAL ;
    PORT
      LAYER M5 ;
        RECT  33.024 0 33.048 0.084 ;
    END
  END u_data[382]
  PIN u_data[383]
    DIRECTION INPUT ;
    USE SIGNAL ;
    PORT
      LAYER M5 ;
        RECT  33.072 0 33.096 0.084 ;
    END
  END u_data[383]
  PIN u_data[384]
    DIRECTION INPUT ;
    USE SIGNAL ;
    PORT
      LAYER M5 ;
        RECT  33.12 0 33.144 0.084 ;
    END
  END u_data[384]
  PIN u_data[385]
    DIRECTION INPUT ;
    USE SIGNAL ;
    PORT
      LAYER M5 ;
        RECT  33.168 0 33.192 0.084 ;
    END
  END u_data[385]
  PIN u_data[386]
    DIRECTION INPUT ;
    USE SIGNAL ;
    PORT
      LAYER M5 ;
        RECT  33.216 0 33.24 0.084 ;
    END
  END u_data[386]
  PIN u_data[387]
    DIRECTION INPUT ;
    USE SIGNAL ;
    PORT
      LAYER M5 ;
        RECT  33.264 0 33.288 0.084 ;
    END
  END u_data[387]
  PIN u_data[388]
    DIRECTION INPUT ;
    USE SIGNAL ;
    PORT
      LAYER M5 ;
        RECT  33.312 0 33.336 0.084 ;
    END
  END u_data[388]
  PIN u_data[389]
    DIRECTION INPUT ;
    USE SIGNAL ;
    PORT
      LAYER M5 ;
        RECT  33.36 0 33.384 0.084 ;
    END
  END u_data[389]
  PIN u_data[38]
    DIRECTION INPUT ;
    USE SIGNAL ;
    PORT
      LAYER M5 ;
        RECT  16.512 0 16.536 0.084 ;
    END
  END u_data[38]
  PIN u_data[390]
    DIRECTION INPUT ;
    USE SIGNAL ;
    PORT
      LAYER M5 ;
        RECT  33.408 0 33.432 0.084 ;
    END
  END u_data[390]
  PIN u_data[391]
    DIRECTION INPUT ;
    USE SIGNAL ;
    PORT
      LAYER M5 ;
        RECT  33.456 0 33.48 0.084 ;
    END
  END u_data[391]
  PIN u_data[392]
    DIRECTION INPUT ;
    USE SIGNAL ;
    PORT
      LAYER M5 ;
        RECT  33.504 0 33.528 0.084 ;
    END
  END u_data[392]
  PIN u_data[393]
    DIRECTION INPUT ;
    USE SIGNAL ;
    PORT
      LAYER M5 ;
        RECT  33.552 0 33.576 0.084 ;
    END
  END u_data[393]
  PIN u_data[394]
    DIRECTION INPUT ;
    USE SIGNAL ;
    PORT
      LAYER M5 ;
        RECT  33.6 0 33.624 0.084 ;
    END
  END u_data[394]
  PIN u_data[395]
    DIRECTION INPUT ;
    USE SIGNAL ;
    PORT
      LAYER M5 ;
        RECT  33.648 0 33.672 0.084 ;
    END
  END u_data[395]
  PIN u_data[396]
    DIRECTION INPUT ;
    USE SIGNAL ;
    PORT
      LAYER M5 ;
        RECT  33.696 0 33.72 0.084 ;
    END
  END u_data[396]
  PIN u_data[397]
    DIRECTION INPUT ;
    USE SIGNAL ;
    PORT
      LAYER M5 ;
        RECT  33.744 0 33.768 0.084 ;
    END
  END u_data[397]
  PIN u_data[398]
    DIRECTION INPUT ;
    USE SIGNAL ;
    PORT
      LAYER M5 ;
        RECT  33.792 0 33.816 0.084 ;
    END
  END u_data[398]
  PIN u_data[399]
    DIRECTION INPUT ;
    USE SIGNAL ;
    PORT
      LAYER M5 ;
        RECT  33.84 0 33.864 0.084 ;
    END
  END u_data[399]
  PIN u_data[39]
    DIRECTION INPUT ;
    USE SIGNAL ;
    PORT
      LAYER M5 ;
        RECT  16.56 0 16.584 0.084 ;
    END
  END u_data[39]
  PIN u_data[3]
    DIRECTION INPUT ;
    USE SIGNAL ;
    PORT
      LAYER M5 ;
        RECT  14.832 0 14.856 0.084 ;
    END
  END u_data[3]
  PIN u_data[400]
    DIRECTION INPUT ;
    USE SIGNAL ;
    PORT
      LAYER M5 ;
        RECT  33.888 0 33.912 0.084 ;
    END
  END u_data[400]
  PIN u_data[401]
    DIRECTION INPUT ;
    USE SIGNAL ;
    PORT
      LAYER M5 ;
        RECT  33.936 0 33.96 0.084 ;
    END
  END u_data[401]
  PIN u_data[402]
    DIRECTION INPUT ;
    USE SIGNAL ;
    PORT
      LAYER M5 ;
        RECT  33.984 0 34.008 0.084 ;
    END
  END u_data[402]
  PIN u_data[403]
    DIRECTION INPUT ;
    USE SIGNAL ;
    PORT
      LAYER M5 ;
        RECT  34.032 0 34.056 0.084 ;
    END
  END u_data[403]
  PIN u_data[404]
    DIRECTION INPUT ;
    USE SIGNAL ;
    PORT
      LAYER M5 ;
        RECT  34.08 0 34.104 0.084 ;
    END
  END u_data[404]
  PIN u_data[405]
    DIRECTION INPUT ;
    USE SIGNAL ;
    PORT
      LAYER M5 ;
        RECT  34.128 0 34.152 0.084 ;
    END
  END u_data[405]
  PIN u_data[406]
    DIRECTION INPUT ;
    USE SIGNAL ;
    PORT
      LAYER M5 ;
        RECT  34.176 0 34.2 0.084 ;
    END
  END u_data[406]
  PIN u_data[407]
    DIRECTION INPUT ;
    USE SIGNAL ;
    PORT
      LAYER M5 ;
        RECT  34.224 0 34.248 0.084 ;
    END
  END u_data[407]
  PIN u_data[408]
    DIRECTION INPUT ;
    USE SIGNAL ;
    PORT
      LAYER M5 ;
        RECT  34.272 0 34.296 0.084 ;
    END
  END u_data[408]
  PIN u_data[409]
    DIRECTION INPUT ;
    USE SIGNAL ;
    PORT
      LAYER M5 ;
        RECT  34.32 0 34.344 0.084 ;
    END
  END u_data[409]
  PIN u_data[40]
    DIRECTION INPUT ;
    USE SIGNAL ;
    PORT
      LAYER M5 ;
        RECT  16.608 0 16.632 0.084 ;
    END
  END u_data[40]
  PIN u_data[410]
    DIRECTION INPUT ;
    USE SIGNAL ;
    PORT
      LAYER M5 ;
        RECT  34.368 0 34.392 0.084 ;
    END
  END u_data[410]
  PIN u_data[411]
    DIRECTION INPUT ;
    USE SIGNAL ;
    PORT
      LAYER M5 ;
        RECT  34.416 0 34.44 0.084 ;
    END
  END u_data[411]
  PIN u_data[412]
    DIRECTION INPUT ;
    USE SIGNAL ;
    PORT
      LAYER M5 ;
        RECT  34.464 0 34.488 0.084 ;
    END
  END u_data[412]
  PIN u_data[413]
    DIRECTION INPUT ;
    USE SIGNAL ;
    PORT
      LAYER M5 ;
        RECT  34.512 0 34.536 0.084 ;
    END
  END u_data[413]
  PIN u_data[414]
    DIRECTION INPUT ;
    USE SIGNAL ;
    PORT
      LAYER M5 ;
        RECT  34.56 0 34.584 0.084 ;
    END
  END u_data[414]
  PIN u_data[415]
    DIRECTION INPUT ;
    USE SIGNAL ;
    PORT
      LAYER M5 ;
        RECT  34.608 0 34.632 0.084 ;
    END
  END u_data[415]
  PIN u_data[416]
    DIRECTION INPUT ;
    USE SIGNAL ;
    PORT
      LAYER M5 ;
        RECT  34.656 0 34.68 0.084 ;
    END
  END u_data[416]
  PIN u_data[417]
    DIRECTION INPUT ;
    USE SIGNAL ;
    PORT
      LAYER M5 ;
        RECT  34.704 0 34.728 0.084 ;
    END
  END u_data[417]
  PIN u_data[418]
    DIRECTION INPUT ;
    USE SIGNAL ;
    PORT
      LAYER M5 ;
        RECT  34.752 0 34.776 0.084 ;
    END
  END u_data[418]
  PIN u_data[419]
    DIRECTION INPUT ;
    USE SIGNAL ;
    PORT
      LAYER M5 ;
        RECT  34.8 0 34.824 0.084 ;
    END
  END u_data[419]
  PIN u_data[41]
    DIRECTION INPUT ;
    USE SIGNAL ;
    PORT
      LAYER M5 ;
        RECT  16.656 0 16.68 0.084 ;
    END
  END u_data[41]
  PIN u_data[420]
    DIRECTION INPUT ;
    USE SIGNAL ;
    PORT
      LAYER M5 ;
        RECT  34.848 0 34.872 0.084 ;
    END
  END u_data[420]
  PIN u_data[421]
    DIRECTION INPUT ;
    USE SIGNAL ;
    PORT
      LAYER M5 ;
        RECT  34.896 0 34.92 0.084 ;
    END
  END u_data[421]
  PIN u_data[422]
    DIRECTION INPUT ;
    USE SIGNAL ;
    PORT
      LAYER M5 ;
        RECT  34.944 0 34.968 0.084 ;
    END
  END u_data[422]
  PIN u_data[423]
    DIRECTION INPUT ;
    USE SIGNAL ;
    PORT
      LAYER M5 ;
        RECT  34.992 0 35.016 0.084 ;
    END
  END u_data[423]
  PIN u_data[424]
    DIRECTION INPUT ;
    USE SIGNAL ;
    PORT
      LAYER M5 ;
        RECT  35.04 0 35.064 0.084 ;
    END
  END u_data[424]
  PIN u_data[425]
    DIRECTION INPUT ;
    USE SIGNAL ;
    PORT
      LAYER M5 ;
        RECT  35.088 0 35.112 0.084 ;
    END
  END u_data[425]
  PIN u_data[426]
    DIRECTION INPUT ;
    USE SIGNAL ;
    PORT
      LAYER M5 ;
        RECT  35.136 0 35.16 0.084 ;
    END
  END u_data[426]
  PIN u_data[427]
    DIRECTION INPUT ;
    USE SIGNAL ;
    PORT
      LAYER M5 ;
        RECT  35.184 0 35.208 0.084 ;
    END
  END u_data[427]
  PIN u_data[428]
    DIRECTION INPUT ;
    USE SIGNAL ;
    PORT
      LAYER M5 ;
        RECT  35.232 0 35.256 0.084 ;
    END
  END u_data[428]
  PIN u_data[429]
    DIRECTION INPUT ;
    USE SIGNAL ;
    PORT
      LAYER M5 ;
        RECT  35.28 0 35.304 0.084 ;
    END
  END u_data[429]
  PIN u_data[42]
    DIRECTION INPUT ;
    USE SIGNAL ;
    PORT
      LAYER M5 ;
        RECT  16.704 0 16.728 0.084 ;
    END
  END u_data[42]
  PIN u_data[430]
    DIRECTION INPUT ;
    USE SIGNAL ;
    PORT
      LAYER M5 ;
        RECT  35.328 0 35.352 0.084 ;
    END
  END u_data[430]
  PIN u_data[431]
    DIRECTION INPUT ;
    USE SIGNAL ;
    PORT
      LAYER M5 ;
        RECT  35.376 0 35.4 0.084 ;
    END
  END u_data[431]
  PIN u_data[432]
    DIRECTION INPUT ;
    USE SIGNAL ;
    PORT
      LAYER M5 ;
        RECT  35.424 0 35.448 0.084 ;
    END
  END u_data[432]
  PIN u_data[433]
    DIRECTION INPUT ;
    USE SIGNAL ;
    PORT
      LAYER M5 ;
        RECT  35.472 0 35.496 0.084 ;
    END
  END u_data[433]
  PIN u_data[434]
    DIRECTION INPUT ;
    USE SIGNAL ;
    PORT
      LAYER M5 ;
        RECT  35.52 0 35.544 0.084 ;
    END
  END u_data[434]
  PIN u_data[435]
    DIRECTION INPUT ;
    USE SIGNAL ;
    PORT
      LAYER M5 ;
        RECT  35.568 0 35.592 0.084 ;
    END
  END u_data[435]
  PIN u_data[436]
    DIRECTION INPUT ;
    USE SIGNAL ;
    PORT
      LAYER M5 ;
        RECT  35.616 0 35.64 0.084 ;
    END
  END u_data[436]
  PIN u_data[437]
    DIRECTION INPUT ;
    USE SIGNAL ;
    PORT
      LAYER M5 ;
        RECT  35.664 0 35.688 0.084 ;
    END
  END u_data[437]
  PIN u_data[438]
    DIRECTION INPUT ;
    USE SIGNAL ;
    PORT
      LAYER M5 ;
        RECT  35.712 0 35.736 0.084 ;
    END
  END u_data[438]
  PIN u_data[439]
    DIRECTION INPUT ;
    USE SIGNAL ;
    PORT
      LAYER M5 ;
        RECT  35.76 0 35.784 0.084 ;
    END
  END u_data[439]
  PIN u_data[43]
    DIRECTION INPUT ;
    USE SIGNAL ;
    PORT
      LAYER M5 ;
        RECT  16.752 0 16.776 0.084 ;
    END
  END u_data[43]
  PIN u_data[440]
    DIRECTION INPUT ;
    USE SIGNAL ;
    PORT
      LAYER M5 ;
        RECT  35.808 0 35.832 0.084 ;
    END
  END u_data[440]
  PIN u_data[441]
    DIRECTION INPUT ;
    USE SIGNAL ;
    PORT
      LAYER M5 ;
        RECT  35.856 0 35.88 0.084 ;
    END
  END u_data[441]
  PIN u_data[442]
    DIRECTION INPUT ;
    USE SIGNAL ;
    PORT
      LAYER M5 ;
        RECT  35.904 0 35.928 0.084 ;
    END
  END u_data[442]
  PIN u_data[443]
    DIRECTION INPUT ;
    USE SIGNAL ;
    PORT
      LAYER M5 ;
        RECT  35.952 0 35.976 0.084 ;
    END
  END u_data[443]
  PIN u_data[444]
    DIRECTION INPUT ;
    USE SIGNAL ;
    PORT
      LAYER M5 ;
        RECT  36 0 36.024 0.084 ;
    END
  END u_data[444]
  PIN u_data[445]
    DIRECTION INPUT ;
    USE SIGNAL ;
    PORT
      LAYER M5 ;
        RECT  36.048 0 36.072 0.084 ;
    END
  END u_data[445]
  PIN u_data[446]
    DIRECTION INPUT ;
    USE SIGNAL ;
    PORT
      LAYER M5 ;
        RECT  36.096 0 36.12 0.084 ;
    END
  END u_data[446]
  PIN u_data[447]
    DIRECTION INPUT ;
    USE SIGNAL ;
    PORT
      LAYER M5 ;
        RECT  36.144 0 36.168 0.084 ;
    END
  END u_data[447]
  PIN u_data[448]
    DIRECTION INPUT ;
    USE SIGNAL ;
    PORT
      LAYER M5 ;
        RECT  36.192 0 36.216 0.084 ;
    END
  END u_data[448]
  PIN u_data[449]
    DIRECTION INPUT ;
    USE SIGNAL ;
    PORT
      LAYER M5 ;
        RECT  36.24 0 36.264 0.084 ;
    END
  END u_data[449]
  PIN u_data[44]
    DIRECTION INPUT ;
    USE SIGNAL ;
    PORT
      LAYER M5 ;
        RECT  16.8 0 16.824 0.084 ;
    END
  END u_data[44]
  PIN u_data[450]
    DIRECTION INPUT ;
    USE SIGNAL ;
    PORT
      LAYER M5 ;
        RECT  36.288 0 36.312 0.084 ;
    END
  END u_data[450]
  PIN u_data[451]
    DIRECTION INPUT ;
    USE SIGNAL ;
    PORT
      LAYER M5 ;
        RECT  36.336 0 36.36 0.084 ;
    END
  END u_data[451]
  PIN u_data[452]
    DIRECTION INPUT ;
    USE SIGNAL ;
    PORT
      LAYER M5 ;
        RECT  36.384 0 36.408 0.084 ;
    END
  END u_data[452]
  PIN u_data[453]
    DIRECTION INPUT ;
    USE SIGNAL ;
    PORT
      LAYER M5 ;
        RECT  36.432 0 36.456 0.084 ;
    END
  END u_data[453]
  PIN u_data[454]
    DIRECTION INPUT ;
    USE SIGNAL ;
    PORT
      LAYER M5 ;
        RECT  36.48 0 36.504 0.084 ;
    END
  END u_data[454]
  PIN u_data[455]
    DIRECTION INPUT ;
    USE SIGNAL ;
    PORT
      LAYER M5 ;
        RECT  36.528 0 36.552 0.084 ;
    END
  END u_data[455]
  PIN u_data[456]
    DIRECTION INPUT ;
    USE SIGNAL ;
    PORT
      LAYER M5 ;
        RECT  36.576 0 36.6 0.084 ;
    END
  END u_data[456]
  PIN u_data[457]
    DIRECTION INPUT ;
    USE SIGNAL ;
    PORT
      LAYER M5 ;
        RECT  36.624 0 36.648 0.084 ;
    END
  END u_data[457]
  PIN u_data[458]
    DIRECTION INPUT ;
    USE SIGNAL ;
    PORT
      LAYER M5 ;
        RECT  36.672 0 36.696 0.084 ;
    END
  END u_data[458]
  PIN u_data[459]
    DIRECTION INPUT ;
    USE SIGNAL ;
    PORT
      LAYER M5 ;
        RECT  36.72 0 36.744 0.084 ;
    END
  END u_data[459]
  PIN u_data[45]
    DIRECTION INPUT ;
    USE SIGNAL ;
    PORT
      LAYER M5 ;
        RECT  16.848 0 16.872 0.084 ;
    END
  END u_data[45]
  PIN u_data[460]
    DIRECTION INPUT ;
    USE SIGNAL ;
    PORT
      LAYER M5 ;
        RECT  36.768 0 36.792 0.084 ;
    END
  END u_data[460]
  PIN u_data[461]
    DIRECTION INPUT ;
    USE SIGNAL ;
    PORT
      LAYER M5 ;
        RECT  36.816 0 36.84 0.084 ;
    END
  END u_data[461]
  PIN u_data[462]
    DIRECTION INPUT ;
    USE SIGNAL ;
    PORT
      LAYER M5 ;
        RECT  36.864 0 36.888 0.084 ;
    END
  END u_data[462]
  PIN u_data[463]
    DIRECTION INPUT ;
    USE SIGNAL ;
    PORT
      LAYER M5 ;
        RECT  36.912 0 36.936 0.084 ;
    END
  END u_data[463]
  PIN u_data[464]
    DIRECTION INPUT ;
    USE SIGNAL ;
    PORT
      LAYER M5 ;
        RECT  36.96 0 36.984 0.084 ;
    END
  END u_data[464]
  PIN u_data[465]
    DIRECTION INPUT ;
    USE SIGNAL ;
    PORT
      LAYER M5 ;
        RECT  37.008 0 37.032 0.084 ;
    END
  END u_data[465]
  PIN u_data[466]
    DIRECTION INPUT ;
    USE SIGNAL ;
    PORT
      LAYER M5 ;
        RECT  37.056 0 37.08 0.084 ;
    END
  END u_data[466]
  PIN u_data[467]
    DIRECTION INPUT ;
    USE SIGNAL ;
    PORT
      LAYER M5 ;
        RECT  37.104 0 37.128 0.084 ;
    END
  END u_data[467]
  PIN u_data[468]
    DIRECTION INPUT ;
    USE SIGNAL ;
    PORT
      LAYER M5 ;
        RECT  37.152 0 37.176 0.084 ;
    END
  END u_data[468]
  PIN u_data[469]
    DIRECTION INPUT ;
    USE SIGNAL ;
    PORT
      LAYER M5 ;
        RECT  37.2 0 37.224 0.084 ;
    END
  END u_data[469]
  PIN u_data[46]
    DIRECTION INPUT ;
    USE SIGNAL ;
    PORT
      LAYER M5 ;
        RECT  16.896 0 16.92 0.084 ;
    END
  END u_data[46]
  PIN u_data[470]
    DIRECTION INPUT ;
    USE SIGNAL ;
    PORT
      LAYER M5 ;
        RECT  37.248 0 37.272 0.084 ;
    END
  END u_data[470]
  PIN u_data[471]
    DIRECTION INPUT ;
    USE SIGNAL ;
    PORT
      LAYER M5 ;
        RECT  37.296 0 37.32 0.084 ;
    END
  END u_data[471]
  PIN u_data[472]
    DIRECTION INPUT ;
    USE SIGNAL ;
    PORT
      LAYER M5 ;
        RECT  37.344 0 37.368 0.084 ;
    END
  END u_data[472]
  PIN u_data[473]
    DIRECTION INPUT ;
    USE SIGNAL ;
    PORT
      LAYER M5 ;
        RECT  37.392 0 37.416 0.084 ;
    END
  END u_data[473]
  PIN u_data[474]
    DIRECTION INPUT ;
    USE SIGNAL ;
    PORT
      LAYER M5 ;
        RECT  37.44 0 37.464 0.084 ;
    END
  END u_data[474]
  PIN u_data[475]
    DIRECTION INPUT ;
    USE SIGNAL ;
    PORT
      LAYER M5 ;
        RECT  37.488 0 37.512 0.084 ;
    END
  END u_data[475]
  PIN u_data[476]
    DIRECTION INPUT ;
    USE SIGNAL ;
    PORT
      LAYER M5 ;
        RECT  37.536 0 37.56 0.084 ;
    END
  END u_data[476]
  PIN u_data[477]
    DIRECTION INPUT ;
    USE SIGNAL ;
    PORT
      LAYER M5 ;
        RECT  37.584 0 37.608 0.084 ;
    END
  END u_data[477]
  PIN u_data[478]
    DIRECTION INPUT ;
    USE SIGNAL ;
    PORT
      LAYER M5 ;
        RECT  37.632 0 37.656 0.084 ;
    END
  END u_data[478]
  PIN u_data[479]
    DIRECTION INPUT ;
    USE SIGNAL ;
    PORT
      LAYER M5 ;
        RECT  37.68 0 37.704 0.084 ;
    END
  END u_data[479]
  PIN u_data[47]
    DIRECTION INPUT ;
    USE SIGNAL ;
    PORT
      LAYER M5 ;
        RECT  16.944 0 16.968 0.084 ;
    END
  END u_data[47]
  PIN u_data[480]
    DIRECTION INPUT ;
    USE SIGNAL ;
    PORT
      LAYER M5 ;
        RECT  37.728 0 37.752 0.084 ;
    END
  END u_data[480]
  PIN u_data[481]
    DIRECTION INPUT ;
    USE SIGNAL ;
    PORT
      LAYER M5 ;
        RECT  37.776 0 37.8 0.084 ;
    END
  END u_data[481]
  PIN u_data[482]
    DIRECTION INPUT ;
    USE SIGNAL ;
    PORT
      LAYER M5 ;
        RECT  37.824 0 37.848 0.084 ;
    END
  END u_data[482]
  PIN u_data[483]
    DIRECTION INPUT ;
    USE SIGNAL ;
    PORT
      LAYER M5 ;
        RECT  37.872 0 37.896 0.084 ;
    END
  END u_data[483]
  PIN u_data[484]
    DIRECTION INPUT ;
    USE SIGNAL ;
    PORT
      LAYER M5 ;
        RECT  37.92 0 37.944 0.084 ;
    END
  END u_data[484]
  PIN u_data[485]
    DIRECTION INPUT ;
    USE SIGNAL ;
    PORT
      LAYER M5 ;
        RECT  37.968 0 37.992 0.084 ;
    END
  END u_data[485]
  PIN u_data[486]
    DIRECTION INPUT ;
    USE SIGNAL ;
    PORT
      LAYER M5 ;
        RECT  38.016 0 38.04 0.084 ;
    END
  END u_data[486]
  PIN u_data[487]
    DIRECTION INPUT ;
    USE SIGNAL ;
    PORT
      LAYER M5 ;
        RECT  38.064 0 38.088 0.084 ;
    END
  END u_data[487]
  PIN u_data[488]
    DIRECTION INPUT ;
    USE SIGNAL ;
    PORT
      LAYER M5 ;
        RECT  38.112 0 38.136 0.084 ;
    END
  END u_data[488]
  PIN u_data[489]
    DIRECTION INPUT ;
    USE SIGNAL ;
    PORT
      LAYER M5 ;
        RECT  38.16 0 38.184 0.084 ;
    END
  END u_data[489]
  PIN u_data[48]
    DIRECTION INPUT ;
    USE SIGNAL ;
    PORT
      LAYER M5 ;
        RECT  16.992 0 17.016 0.084 ;
    END
  END u_data[48]
  PIN u_data[490]
    DIRECTION INPUT ;
    USE SIGNAL ;
    PORT
      LAYER M5 ;
        RECT  38.208 0 38.232 0.084 ;
    END
  END u_data[490]
  PIN u_data[491]
    DIRECTION INPUT ;
    USE SIGNAL ;
    PORT
      LAYER M5 ;
        RECT  38.256 0 38.28 0.084 ;
    END
  END u_data[491]
  PIN u_data[492]
    DIRECTION INPUT ;
    USE SIGNAL ;
    PORT
      LAYER M5 ;
        RECT  38.304 0 38.328 0.084 ;
    END
  END u_data[492]
  PIN u_data[493]
    DIRECTION INPUT ;
    USE SIGNAL ;
    PORT
      LAYER M5 ;
        RECT  38.352 0 38.376 0.084 ;
    END
  END u_data[493]
  PIN u_data[494]
    DIRECTION INPUT ;
    USE SIGNAL ;
    PORT
      LAYER M5 ;
        RECT  38.4 0 38.424 0.084 ;
    END
  END u_data[494]
  PIN u_data[495]
    DIRECTION INPUT ;
    USE SIGNAL ;
    PORT
      LAYER M5 ;
        RECT  38.448 0 38.472 0.084 ;
    END
  END u_data[495]
  PIN u_data[496]
    DIRECTION INPUT ;
    USE SIGNAL ;
    PORT
      LAYER M5 ;
        RECT  38.496 0 38.52 0.084 ;
    END
  END u_data[496]
  PIN u_data[497]
    DIRECTION INPUT ;
    USE SIGNAL ;
    PORT
      LAYER M5 ;
        RECT  38.544 0 38.568 0.084 ;
    END
  END u_data[497]
  PIN u_data[498]
    DIRECTION INPUT ;
    USE SIGNAL ;
    PORT
      LAYER M5 ;
        RECT  38.592 0 38.616 0.084 ;
    END
  END u_data[498]
  PIN u_data[499]
    DIRECTION INPUT ;
    USE SIGNAL ;
    PORT
      LAYER M5 ;
        RECT  38.64 0 38.664 0.084 ;
    END
  END u_data[499]
  PIN u_data[49]
    DIRECTION INPUT ;
    USE SIGNAL ;
    PORT
      LAYER M5 ;
        RECT  17.04 0 17.064 0.084 ;
    END
  END u_data[49]
  PIN u_data[4]
    DIRECTION INPUT ;
    USE SIGNAL ;
    PORT
      LAYER M5 ;
        RECT  14.88 0 14.904 0.084 ;
    END
  END u_data[4]
  PIN u_data[500]
    DIRECTION INPUT ;
    USE SIGNAL ;
    PORT
      LAYER M5 ;
        RECT  38.688 0 38.712 0.084 ;
    END
  END u_data[500]
  PIN u_data[501]
    DIRECTION INPUT ;
    USE SIGNAL ;
    PORT
      LAYER M5 ;
        RECT  38.736 0 38.76 0.084 ;
    END
  END u_data[501]
  PIN u_data[502]
    DIRECTION INPUT ;
    USE SIGNAL ;
    PORT
      LAYER M5 ;
        RECT  38.784 0 38.808 0.084 ;
    END
  END u_data[502]
  PIN u_data[503]
    DIRECTION INPUT ;
    USE SIGNAL ;
    PORT
      LAYER M5 ;
        RECT  38.832 0 38.856 0.084 ;
    END
  END u_data[503]
  PIN u_data[504]
    DIRECTION INPUT ;
    USE SIGNAL ;
    PORT
      LAYER M5 ;
        RECT  38.88 0 38.904 0.084 ;
    END
  END u_data[504]
  PIN u_data[505]
    DIRECTION INPUT ;
    USE SIGNAL ;
    PORT
      LAYER M5 ;
        RECT  38.928 0 38.952 0.084 ;
    END
  END u_data[505]
  PIN u_data[506]
    DIRECTION INPUT ;
    USE SIGNAL ;
    PORT
      LAYER M5 ;
        RECT  38.976 0 39 0.084 ;
    END
  END u_data[506]
  PIN u_data[507]
    DIRECTION INPUT ;
    USE SIGNAL ;
    PORT
      LAYER M5 ;
        RECT  39.024 0 39.048 0.084 ;
    END
  END u_data[507]
  PIN u_data[508]
    DIRECTION INPUT ;
    USE SIGNAL ;
    PORT
      LAYER M5 ;
        RECT  39.072 0 39.096 0.084 ;
    END
  END u_data[508]
  PIN u_data[509]
    DIRECTION INPUT ;
    USE SIGNAL ;
    PORT
      LAYER M5 ;
        RECT  39.12 0 39.144 0.084 ;
    END
  END u_data[509]
  PIN u_data[50]
    DIRECTION INPUT ;
    USE SIGNAL ;
    PORT
      LAYER M5 ;
        RECT  17.088 0 17.112 0.084 ;
    END
  END u_data[50]
  PIN u_data[510]
    DIRECTION INPUT ;
    USE SIGNAL ;
    PORT
      LAYER M5 ;
        RECT  39.168 0 39.192 0.084 ;
    END
  END u_data[510]
  PIN u_data[511]
    DIRECTION INPUT ;
    USE SIGNAL ;
    PORT
      LAYER M5 ;
        RECT  39.216 0 39.24 0.084 ;
    END
  END u_data[511]
  PIN u_data[51]
    DIRECTION INPUT ;
    USE SIGNAL ;
    PORT
      LAYER M5 ;
        RECT  17.136 0 17.16 0.084 ;
    END
  END u_data[51]
  PIN u_data[52]
    DIRECTION INPUT ;
    USE SIGNAL ;
    PORT
      LAYER M5 ;
        RECT  17.184 0 17.208 0.084 ;
    END
  END u_data[52]
  PIN u_data[53]
    DIRECTION INPUT ;
    USE SIGNAL ;
    PORT
      LAYER M5 ;
        RECT  17.232 0 17.256 0.084 ;
    END
  END u_data[53]
  PIN u_data[54]
    DIRECTION INPUT ;
    USE SIGNAL ;
    PORT
      LAYER M5 ;
        RECT  17.28 0 17.304 0.084 ;
    END
  END u_data[54]
  PIN u_data[55]
    DIRECTION INPUT ;
    USE SIGNAL ;
    PORT
      LAYER M5 ;
        RECT  17.328 0 17.352 0.084 ;
    END
  END u_data[55]
  PIN u_data[56]
    DIRECTION INPUT ;
    USE SIGNAL ;
    PORT
      LAYER M5 ;
        RECT  17.376 0 17.4 0.084 ;
    END
  END u_data[56]
  PIN u_data[57]
    DIRECTION INPUT ;
    USE SIGNAL ;
    PORT
      LAYER M5 ;
        RECT  17.424 0 17.448 0.084 ;
    END
  END u_data[57]
  PIN u_data[58]
    DIRECTION INPUT ;
    USE SIGNAL ;
    PORT
      LAYER M5 ;
        RECT  17.472 0 17.496 0.084 ;
    END
  END u_data[58]
  PIN u_data[59]
    DIRECTION INPUT ;
    USE SIGNAL ;
    PORT
      LAYER M5 ;
        RECT  17.52 0 17.544 0.084 ;
    END
  END u_data[59]
  PIN u_data[5]
    DIRECTION INPUT ;
    USE SIGNAL ;
    PORT
      LAYER M5 ;
        RECT  14.928 0 14.952 0.084 ;
    END
  END u_data[5]
  PIN u_data[60]
    DIRECTION INPUT ;
    USE SIGNAL ;
    PORT
      LAYER M5 ;
        RECT  17.568 0 17.592 0.084 ;
    END
  END u_data[60]
  PIN u_data[61]
    DIRECTION INPUT ;
    USE SIGNAL ;
    PORT
      LAYER M5 ;
        RECT  17.616 0 17.64 0.084 ;
    END
  END u_data[61]
  PIN u_data[62]
    DIRECTION INPUT ;
    USE SIGNAL ;
    PORT
      LAYER M5 ;
        RECT  17.664 0 17.688 0.084 ;
    END
  END u_data[62]
  PIN u_data[63]
    DIRECTION INPUT ;
    USE SIGNAL ;
    PORT
      LAYER M5 ;
        RECT  17.712 0 17.736 0.084 ;
    END
  END u_data[63]
  PIN u_data[64]
    DIRECTION INPUT ;
    USE SIGNAL ;
    PORT
      LAYER M5 ;
        RECT  17.76 0 17.784 0.084 ;
    END
  END u_data[64]
  PIN u_data[65]
    DIRECTION INPUT ;
    USE SIGNAL ;
    PORT
      LAYER M5 ;
        RECT  17.808 0 17.832 0.084 ;
    END
  END u_data[65]
  PIN u_data[66]
    DIRECTION INPUT ;
    USE SIGNAL ;
    PORT
      LAYER M5 ;
        RECT  17.856 0 17.88 0.084 ;
    END
  END u_data[66]
  PIN u_data[67]
    DIRECTION INPUT ;
    USE SIGNAL ;
    PORT
      LAYER M5 ;
        RECT  17.904 0 17.928 0.084 ;
    END
  END u_data[67]
  PIN u_data[68]
    DIRECTION INPUT ;
    USE SIGNAL ;
    PORT
      LAYER M5 ;
        RECT  17.952 0 17.976 0.084 ;
    END
  END u_data[68]
  PIN u_data[69]
    DIRECTION INPUT ;
    USE SIGNAL ;
    PORT
      LAYER M5 ;
        RECT  18 0 18.024 0.084 ;
    END
  END u_data[69]
  PIN u_data[6]
    DIRECTION INPUT ;
    USE SIGNAL ;
    PORT
      LAYER M5 ;
        RECT  14.976 0 15 0.084 ;
    END
  END u_data[6]
  PIN u_data[70]
    DIRECTION INPUT ;
    USE SIGNAL ;
    PORT
      LAYER M5 ;
        RECT  18.048 0 18.072 0.084 ;
    END
  END u_data[70]
  PIN u_data[71]
    DIRECTION INPUT ;
    USE SIGNAL ;
    PORT
      LAYER M5 ;
        RECT  18.096 0 18.12 0.084 ;
    END
  END u_data[71]
  PIN u_data[72]
    DIRECTION INPUT ;
    USE SIGNAL ;
    PORT
      LAYER M5 ;
        RECT  18.144 0 18.168 0.084 ;
    END
  END u_data[72]
  PIN u_data[73]
    DIRECTION INPUT ;
    USE SIGNAL ;
    PORT
      LAYER M5 ;
        RECT  18.192 0 18.216 0.084 ;
    END
  END u_data[73]
  PIN u_data[74]
    DIRECTION INPUT ;
    USE SIGNAL ;
    PORT
      LAYER M5 ;
        RECT  18.24 0 18.264 0.084 ;
    END
  END u_data[74]
  PIN u_data[75]
    DIRECTION INPUT ;
    USE SIGNAL ;
    PORT
      LAYER M5 ;
        RECT  18.288 0 18.312 0.084 ;
    END
  END u_data[75]
  PIN u_data[76]
    DIRECTION INPUT ;
    USE SIGNAL ;
    PORT
      LAYER M5 ;
        RECT  18.336 0 18.36 0.084 ;
    END
  END u_data[76]
  PIN u_data[77]
    DIRECTION INPUT ;
    USE SIGNAL ;
    PORT
      LAYER M5 ;
        RECT  18.384 0 18.408 0.084 ;
    END
  END u_data[77]
  PIN u_data[78]
    DIRECTION INPUT ;
    USE SIGNAL ;
    PORT
      LAYER M5 ;
        RECT  18.432 0 18.456 0.084 ;
    END
  END u_data[78]
  PIN u_data[79]
    DIRECTION INPUT ;
    USE SIGNAL ;
    PORT
      LAYER M5 ;
        RECT  18.48 0 18.504 0.084 ;
    END
  END u_data[79]
  PIN u_data[7]
    DIRECTION INPUT ;
    USE SIGNAL ;
    PORT
      LAYER M5 ;
        RECT  15.024 0 15.048 0.084 ;
    END
  END u_data[7]
  PIN u_data[80]
    DIRECTION INPUT ;
    USE SIGNAL ;
    PORT
      LAYER M5 ;
        RECT  18.528 0 18.552 0.084 ;
    END
  END u_data[80]
  PIN u_data[81]
    DIRECTION INPUT ;
    USE SIGNAL ;
    PORT
      LAYER M5 ;
        RECT  18.576 0 18.6 0.084 ;
    END
  END u_data[81]
  PIN u_data[82]
    DIRECTION INPUT ;
    USE SIGNAL ;
    PORT
      LAYER M5 ;
        RECT  18.624 0 18.648 0.084 ;
    END
  END u_data[82]
  PIN u_data[83]
    DIRECTION INPUT ;
    USE SIGNAL ;
    PORT
      LAYER M5 ;
        RECT  18.672 0 18.696 0.084 ;
    END
  END u_data[83]
  PIN u_data[84]
    DIRECTION INPUT ;
    USE SIGNAL ;
    PORT
      LAYER M5 ;
        RECT  18.72 0 18.744 0.084 ;
    END
  END u_data[84]
  PIN u_data[85]
    DIRECTION INPUT ;
    USE SIGNAL ;
    PORT
      LAYER M5 ;
        RECT  18.768 0 18.792 0.084 ;
    END
  END u_data[85]
  PIN u_data[86]
    DIRECTION INPUT ;
    USE SIGNAL ;
    PORT
      LAYER M5 ;
        RECT  18.816 0 18.84 0.084 ;
    END
  END u_data[86]
  PIN u_data[87]
    DIRECTION INPUT ;
    USE SIGNAL ;
    PORT
      LAYER M5 ;
        RECT  18.864 0 18.888 0.084 ;
    END
  END u_data[87]
  PIN u_data[88]
    DIRECTION INPUT ;
    USE SIGNAL ;
    PORT
      LAYER M5 ;
        RECT  18.912 0 18.936 0.084 ;
    END
  END u_data[88]
  PIN u_data[89]
    DIRECTION INPUT ;
    USE SIGNAL ;
    PORT
      LAYER M5 ;
        RECT  18.96 0 18.984 0.084 ;
    END
  END u_data[89]
  PIN u_data[8]
    DIRECTION INPUT ;
    USE SIGNAL ;
    PORT
      LAYER M5 ;
        RECT  15.072 0 15.096 0.084 ;
    END
  END u_data[8]
  PIN u_data[90]
    DIRECTION INPUT ;
    USE SIGNAL ;
    PORT
      LAYER M5 ;
        RECT  19.008 0 19.032 0.084 ;
    END
  END u_data[90]
  PIN u_data[91]
    DIRECTION INPUT ;
    USE SIGNAL ;
    PORT
      LAYER M5 ;
        RECT  19.056 0 19.08 0.084 ;
    END
  END u_data[91]
  PIN u_data[92]
    DIRECTION INPUT ;
    USE SIGNAL ;
    PORT
      LAYER M5 ;
        RECT  19.104 0 19.128 0.084 ;
    END
  END u_data[92]
  PIN u_data[93]
    DIRECTION INPUT ;
    USE SIGNAL ;
    PORT
      LAYER M5 ;
        RECT  19.152 0 19.176 0.084 ;
    END
  END u_data[93]
  PIN u_data[94]
    DIRECTION INPUT ;
    USE SIGNAL ;
    PORT
      LAYER M5 ;
        RECT  19.2 0 19.224 0.084 ;
    END
  END u_data[94]
  PIN u_data[95]
    DIRECTION INPUT ;
    USE SIGNAL ;
    PORT
      LAYER M5 ;
        RECT  19.248 0 19.272 0.084 ;
    END
  END u_data[95]
  PIN u_data[96]
    DIRECTION INPUT ;
    USE SIGNAL ;
    PORT
      LAYER M5 ;
        RECT  19.296 0 19.32 0.084 ;
    END
  END u_data[96]
  PIN u_data[97]
    DIRECTION INPUT ;
    USE SIGNAL ;
    PORT
      LAYER M5 ;
        RECT  19.344 0 19.368 0.084 ;
    END
  END u_data[97]
  PIN u_data[98]
    DIRECTION INPUT ;
    USE SIGNAL ;
    PORT
      LAYER M5 ;
        RECT  19.392 0 19.416 0.084 ;
    END
  END u_data[98]
  PIN u_data[99]
    DIRECTION INPUT ;
    USE SIGNAL ;
    PORT
      LAYER M5 ;
        RECT  19.44 0 19.464 0.084 ;
    END
  END u_data[99]
  PIN u_data[9]
    DIRECTION INPUT ;
    USE SIGNAL ;
    PORT
      LAYER M5 ;
        RECT  15.12 0 15.144 0.084 ;
    END
  END u_data[9]
  PIN u_v
    DIRECTION INPUT ;
    USE SIGNAL ;
    PORT
      LAYER M5 ;
        RECT  39.264 0 39.288 0.084 ;
    END
  END u_v
  PIN VDD
    DIRECTION INOUT ;
    USE POWER ;
    PORT
      LAYER M6 ;
        RECT  2.16 83.913 50.49 84.201 ;
        RECT  2.16 78.513 50.49 78.801 ;
        RECT  2.16 73.113 50.49 73.401 ;
        RECT  2.16 67.713 50.49 68.001 ;
        RECT  2.16 62.313 50.49 62.601 ;
        RECT  2.16 56.913 50.49 57.201 ;
        RECT  2.16 51.513 50.49 51.801 ;
        RECT  2.16 46.113 50.49 46.401 ;
        RECT  2.16 40.713 50.49 41.001 ;
        RECT  2.16 35.313 50.49 35.601 ;
        RECT  2.16 29.913 50.49 30.201 ;
        RECT  2.16 24.513 50.49 24.801 ;
        RECT  2.16 19.113 50.49 19.401 ;
        RECT  2.16 13.713 50.49 14.001 ;
        RECT  2.16 8.313 50.49 8.601 ;
        RECT  2.16 2.913 50.49 3.201 ;
    END
  END VDD
  PIN VSS
    DIRECTION INOUT ;
    USE GROUND ;
    PORT
      LAYER M6 ;
        RECT  2.16 83.529 50.49 83.817 ;
        RECT  2.16 78.129 50.49 78.417 ;
        RECT  2.16 72.729 50.49 73.017 ;
        RECT  2.16 67.329 50.49 67.617 ;
        RECT  2.16 61.929 50.49 62.217 ;
        RECT  2.16 56.529 50.49 56.817 ;
        RECT  2.16 51.129 50.49 51.417 ;
        RECT  2.16 45.729 50.49 46.017 ;
        RECT  2.16 40.329 50.49 40.617 ;
        RECT  2.16 34.929 50.49 35.217 ;
        RECT  2.16 29.529 50.49 29.817 ;
        RECT  2.16 24.129 50.49 24.417 ;
        RECT  2.16 18.729 50.49 19.017 ;
        RECT  2.16 13.329 50.49 13.617 ;
        RECT  2.16 7.929 50.49 8.217 ;
        RECT  2.16 2.529 50.49 2.817 ;
    END
  END VSS
  OBS
    LAYER RVTN ;
     RECT  2.16 2.16 50.49 2.295 ;
     RECT  2.16 2.565 50.49 2.835 ;
     RECT  2.16 3.105 50.49 3.375 ;
     RECT  2.16 3.645 50.49 3.915 ;
     RECT  2.16 4.185 50.49 4.455 ;
     RECT  2.16 4.725 50.49 4.995 ;
     RECT  2.16 5.265 50.49 5.535 ;
     RECT  2.16 5.805 50.49 6.075 ;
     RECT  2.16 6.345 50.49 6.615 ;
     RECT  2.16 6.885 50.49 7.155 ;
     RECT  2.16 7.425 50.49 7.695 ;
     RECT  2.16 7.965 50.49 8.235 ;
     RECT  2.16 8.505 50.49 8.775 ;
     RECT  2.16 9.045 50.49 9.315 ;
     RECT  2.16 9.585 50.49 9.855 ;
     RECT  2.16 10.125 50.49 10.395 ;
     RECT  2.16 10.665 50.49 10.935 ;
     RECT  2.16 11.205 50.49 11.475 ;
     RECT  2.16 11.745 50.49 12.015 ;
     RECT  2.16 12.285 50.49 12.555 ;
     RECT  2.16 12.825 50.49 13.095 ;
     RECT  2.16 13.365 50.49 13.635 ;
     RECT  2.16 13.905 50.49 14.175 ;
     RECT  2.16 14.445 50.49 14.715 ;
     RECT  2.16 14.985 50.49 15.255 ;
     RECT  2.16 15.525 50.49 15.795 ;
     RECT  2.16 16.065 50.49 16.335 ;
     RECT  2.16 16.605 50.49 16.875 ;
     RECT  2.16 17.145 50.49 17.415 ;
     RECT  2.16 17.685 50.49 17.955 ;
     RECT  2.16 18.225 50.49 18.495 ;
     RECT  2.16 18.765 50.49 19.035 ;
     RECT  2.16 19.305 50.49 19.575 ;
     RECT  2.16 19.845 50.49 20.115 ;
     RECT  2.16 20.385 50.49 20.655 ;
     RECT  2.16 20.925 50.49 21.195 ;
     RECT  2.16 21.465 50.49 21.735 ;
     RECT  2.16 22.005 50.49 22.275 ;
     RECT  2.16 22.545 50.49 22.815 ;
     RECT  2.16 23.085 50.49 23.355 ;
     RECT  2.16 23.625 50.49 23.895 ;
     RECT  2.16 24.165 50.49 24.435 ;
     RECT  2.16 24.705 50.49 24.975 ;
     RECT  2.16 25.245 50.49 25.515 ;
     RECT  2.16 25.785 50.49 26.055 ;
     RECT  2.16 26.325 50.49 26.595 ;
     RECT  2.16 26.865 50.49 27.135 ;
     RECT  2.16 27.405 50.49 27.675 ;
     RECT  2.16 27.945 50.49 28.215 ;
     RECT  2.16 28.485 50.49 28.755 ;
     RECT  2.16 29.025 50.49 29.295 ;
     RECT  2.16 29.565 50.49 29.835 ;
     RECT  2.16 30.105 50.49 30.375 ;
     RECT  2.16 30.645 50.49 30.915 ;
     RECT  2.16 31.185 50.49 31.455 ;
     RECT  2.16 31.725 50.49 31.995 ;
     RECT  2.16 32.265 50.49 32.535 ;
     RECT  2.16 32.805 50.49 33.075 ;
     RECT  2.16 33.345 50.49 33.615 ;
     RECT  2.16 33.885 50.49 34.155 ;
     RECT  2.16 34.425 50.49 34.695 ;
     RECT  2.16 34.965 50.49 35.235 ;
     RECT  2.16 35.505 50.49 35.775 ;
     RECT  2.16 36.045 50.49 36.315 ;
     RECT  2.16 36.585 50.49 36.855 ;
     RECT  2.16 37.125 50.49 37.395 ;
     RECT  2.16 37.665 50.49 37.935 ;
     RECT  2.16 38.205 50.49 38.475 ;
     RECT  2.16 38.745 50.49 39.015 ;
     RECT  2.16 39.285 50.49 39.555 ;
     RECT  2.16 39.825 50.49 40.095 ;
     RECT  2.16 40.365 50.49 40.635 ;
     RECT  2.16 40.905 50.49 41.175 ;
     RECT  2.16 41.445 50.49 41.715 ;
     RECT  2.16 41.985 50.49 42.255 ;
     RECT  2.16 42.525 50.49 42.795 ;
     RECT  2.16 43.065 50.49 43.335 ;
     RECT  2.16 43.605 50.49 43.875 ;
     RECT  2.16 44.145 50.49 44.415 ;
     RECT  2.16 44.685 50.49 44.955 ;
     RECT  2.16 45.225 50.49 45.495 ;
     RECT  2.16 45.765 50.49 46.035 ;
     RECT  2.16 46.305 50.49 46.575 ;
     RECT  2.16 46.845 50.49 47.115 ;
     RECT  2.16 47.385 50.49 47.655 ;
     RECT  2.16 47.925 50.49 48.195 ;
     RECT  2.16 48.465 50.49 48.735 ;
     RECT  2.16 49.005 50.49 49.275 ;
     RECT  2.16 49.545 50.49 49.815 ;
     RECT  2.16 50.085 50.49 50.355 ;
     RECT  2.16 50.625 50.49 50.895 ;
     RECT  2.16 51.165 50.49 51.435 ;
     RECT  2.16 51.705 50.49 51.975 ;
     RECT  2.16 52.245 50.49 52.515 ;
     RECT  2.16 52.785 50.49 53.055 ;
     RECT  2.16 53.325 50.49 53.595 ;
     RECT  2.16 53.865 50.49 54.135 ;
     RECT  2.16 54.405 50.49 54.675 ;
     RECT  2.16 54.945 50.49 55.215 ;
     RECT  2.16 55.485 50.49 55.755 ;
     RECT  2.16 56.025 50.49 56.295 ;
     RECT  2.16 56.565 50.49 56.835 ;
     RECT  2.16 57.105 50.49 57.375 ;
     RECT  2.16 57.645 50.49 57.915 ;
     RECT  2.16 58.185 50.49 58.455 ;
     RECT  2.16 58.725 50.49 58.995 ;
     RECT  2.16 59.265 50.49 59.535 ;
     RECT  2.16 59.805 50.49 60.075 ;
     RECT  2.16 60.345 50.49 60.615 ;
     RECT  2.16 60.885 50.49 61.155 ;
     RECT  2.16 61.425 50.49 61.695 ;
     RECT  2.16 61.965 50.49 62.235 ;
     RECT  2.16 62.505 50.49 62.775 ;
     RECT  2.16 63.045 50.49 63.315 ;
     RECT  2.16 63.585 50.49 63.855 ;
     RECT  2.16 64.125 50.49 64.395 ;
     RECT  2.16 64.665 50.49 64.935 ;
     RECT  2.16 65.205 50.49 65.475 ;
     RECT  2.16 65.745 50.49 66.015 ;
     RECT  2.16 66.285 50.49 66.555 ;
     RECT  2.16 66.825 50.49 67.095 ;
     RECT  2.16 67.365 50.49 67.635 ;
     RECT  2.16 67.905 50.49 68.175 ;
     RECT  2.16 68.445 50.49 68.715 ;
     RECT  2.16 68.985 50.49 69.255 ;
     RECT  2.16 69.525 50.49 69.795 ;
     RECT  2.16 70.065 50.49 70.335 ;
     RECT  2.16 70.605 50.49 70.875 ;
     RECT  2.16 71.145 50.49 71.415 ;
     RECT  2.16 71.685 50.49 71.955 ;
     RECT  2.16 72.225 50.49 72.495 ;
     RECT  2.16 72.765 50.49 73.035 ;
     RECT  2.16 73.305 50.49 73.575 ;
     RECT  2.16 73.845 50.49 74.115 ;
     RECT  2.16 74.385 50.49 74.655 ;
     RECT  2.16 74.925 50.49 75.195 ;
     RECT  2.16 75.465 50.49 75.735 ;
     RECT  2.16 76.005 50.49 76.275 ;
     RECT  2.16 76.545 50.49 76.815 ;
     RECT  2.16 77.085 50.49 77.355 ;
     RECT  2.16 77.625 50.49 77.895 ;
     RECT  2.16 78.165 50.49 78.435 ;
     RECT  2.16 78.705 50.49 78.975 ;
     RECT  2.16 79.245 50.49 79.515 ;
     RECT  2.16 79.785 50.49 80.055 ;
     RECT  2.16 80.325 50.49 80.595 ;
     RECT  2.16 80.865 50.49 81.135 ;
     RECT  2.16 81.405 50.49 81.675 ;
     RECT  2.16 81.945 50.49 82.215 ;
     RECT  2.16 82.485 50.49 82.755 ;
     RECT  2.16 83.025 50.49 83.295 ;
     RECT  2.16 83.565 50.49 83.835 ;
     RECT  2.16 84.105 50.49 84.24 ;
    LAYER RVTP ;
     RECT  2.16 2.295 50.49 2.565 ;
     RECT  2.16 2.835 50.49 3.105 ;
     RECT  2.16 3.375 50.49 3.645 ;
     RECT  2.16 3.915 50.49 4.185 ;
     RECT  2.16 4.455 50.49 4.725 ;
     RECT  2.16 4.995 50.49 5.265 ;
     RECT  2.16 5.535 50.49 5.805 ;
     RECT  2.16 6.075 50.49 6.345 ;
     RECT  2.16 6.615 50.49 6.885 ;
     RECT  2.16 7.155 50.49 7.425 ;
     RECT  2.16 7.695 50.49 7.965 ;
     RECT  2.16 8.235 50.49 8.505 ;
     RECT  2.16 8.775 50.49 9.045 ;
     RECT  2.16 9.315 50.49 9.585 ;
     RECT  2.16 9.855 50.49 10.125 ;
     RECT  2.16 10.395 50.49 10.665 ;
     RECT  2.16 10.935 50.49 11.205 ;
     RECT  2.16 11.475 50.49 11.745 ;
     RECT  2.16 12.015 50.49 12.285 ;
     RECT  2.16 12.555 50.49 12.825 ;
     RECT  2.16 13.095 50.49 13.365 ;
     RECT  2.16 13.635 50.49 13.905 ;
     RECT  2.16 14.175 50.49 14.445 ;
     RECT  2.16 14.715 50.49 14.985 ;
     RECT  2.16 15.255 50.49 15.525 ;
     RECT  2.16 15.795 50.49 16.065 ;
     RECT  2.16 16.335 50.49 16.605 ;
     RECT  2.16 16.875 50.49 17.145 ;
     RECT  2.16 17.415 50.49 17.685 ;
     RECT  2.16 17.955 50.49 18.225 ;
     RECT  2.16 18.495 50.49 18.765 ;
     RECT  2.16 19.035 50.49 19.305 ;
     RECT  2.16 19.575 50.49 19.845 ;
     RECT  2.16 20.115 50.49 20.385 ;
     RECT  2.16 20.655 50.49 20.925 ;
     RECT  2.16 21.195 50.49 21.465 ;
     RECT  2.16 21.735 50.49 22.005 ;
     RECT  2.16 22.275 50.49 22.545 ;
     RECT  2.16 22.815 50.49 23.085 ;
     RECT  2.16 23.355 50.49 23.625 ;
     RECT  2.16 23.895 50.49 24.165 ;
     RECT  2.16 24.435 50.49 24.705 ;
     RECT  2.16 24.975 50.49 25.245 ;
     RECT  2.16 25.515 50.49 25.785 ;
     RECT  2.16 26.055 50.49 26.325 ;
     RECT  2.16 26.595 50.49 26.865 ;
     RECT  2.16 27.135 50.49 27.405 ;
     RECT  2.16 27.675 50.49 27.945 ;
     RECT  2.16 28.215 50.49 28.485 ;
     RECT  2.16 28.755 50.49 29.025 ;
     RECT  2.16 29.295 50.49 29.565 ;
     RECT  2.16 29.835 50.49 30.105 ;
     RECT  2.16 30.375 50.49 30.645 ;
     RECT  2.16 30.915 50.49 31.185 ;
     RECT  2.16 31.455 50.49 31.725 ;
     RECT  2.16 31.995 50.49 32.265 ;
     RECT  2.16 32.535 50.49 32.805 ;
     RECT  2.16 33.075 50.49 33.345 ;
     RECT  2.16 33.615 50.49 33.885 ;
     RECT  2.16 34.155 50.49 34.425 ;
     RECT  2.16 34.695 50.49 34.965 ;
     RECT  2.16 35.235 50.49 35.505 ;
     RECT  2.16 35.775 50.49 36.045 ;
     RECT  2.16 36.315 50.49 36.585 ;
     RECT  2.16 36.855 50.49 37.125 ;
     RECT  2.16 37.395 50.49 37.665 ;
     RECT  2.16 37.935 50.49 38.205 ;
     RECT  2.16 38.475 50.49 38.745 ;
     RECT  2.16 39.015 50.49 39.285 ;
     RECT  2.16 39.555 50.49 39.825 ;
     RECT  2.16 40.095 50.49 40.365 ;
     RECT  2.16 40.635 50.49 40.905 ;
     RECT  2.16 41.175 50.49 41.445 ;
     RECT  2.16 41.715 50.49 41.985 ;
     RECT  2.16 42.255 50.49 42.525 ;
     RECT  2.16 42.795 50.49 43.065 ;
     RECT  2.16 43.335 50.49 43.605 ;
     RECT  2.16 43.875 50.49 44.145 ;
     RECT  2.16 44.415 50.49 44.685 ;
     RECT  2.16 44.955 50.49 45.225 ;
     RECT  2.16 45.495 50.49 45.765 ;
     RECT  2.16 46.035 50.49 46.305 ;
     RECT  2.16 46.575 50.49 46.845 ;
     RECT  2.16 47.115 50.49 47.385 ;
     RECT  2.16 47.655 50.49 47.925 ;
     RECT  2.16 48.195 50.49 48.465 ;
     RECT  2.16 48.735 50.49 49.005 ;
     RECT  2.16 49.275 50.49 49.545 ;
     RECT  2.16 49.815 50.49 50.085 ;
     RECT  2.16 50.355 50.49 50.625 ;
     RECT  2.16 50.895 50.49 51.165 ;
     RECT  2.16 51.435 50.49 51.705 ;
     RECT  2.16 51.975 50.49 52.245 ;
     RECT  2.16 52.515 50.49 52.785 ;
     RECT  2.16 53.055 50.49 53.325 ;
     RECT  2.16 53.595 50.49 53.865 ;
     RECT  2.16 54.135 50.49 54.405 ;
     RECT  2.16 54.675 50.49 54.945 ;
     RECT  2.16 55.215 50.49 55.485 ;
     RECT  2.16 55.755 50.49 56.025 ;
     RECT  2.16 56.295 50.49 56.565 ;
     RECT  2.16 56.835 50.49 57.105 ;
     RECT  2.16 57.375 50.49 57.645 ;
     RECT  2.16 57.915 50.49 58.185 ;
     RECT  2.16 58.455 50.49 58.725 ;
     RECT  2.16 58.995 50.49 59.265 ;
     RECT  2.16 59.535 50.49 59.805 ;
     RECT  2.16 60.075 50.49 60.345 ;
     RECT  2.16 60.615 50.49 60.885 ;
     RECT  2.16 61.155 50.49 61.425 ;
     RECT  2.16 61.695 50.49 61.965 ;
     RECT  2.16 62.235 50.49 62.505 ;
     RECT  2.16 62.775 50.49 63.045 ;
     RECT  2.16 63.315 50.49 63.585 ;
     RECT  2.16 63.855 50.49 64.125 ;
     RECT  2.16 64.395 50.49 64.665 ;
     RECT  2.16 64.935 50.49 65.205 ;
     RECT  2.16 65.475 50.49 65.745 ;
     RECT  2.16 66.015 50.49 66.285 ;
     RECT  2.16 66.555 50.49 66.825 ;
     RECT  2.16 67.095 50.49 67.365 ;
     RECT  2.16 67.635 50.49 67.905 ;
     RECT  2.16 68.175 50.49 68.445 ;
     RECT  2.16 68.715 50.49 68.985 ;
     RECT  2.16 69.255 50.49 69.525 ;
     RECT  2.16 69.795 50.49 70.065 ;
     RECT  2.16 70.335 50.49 70.605 ;
     RECT  2.16 70.875 50.49 71.145 ;
     RECT  2.16 71.415 50.49 71.685 ;
     RECT  2.16 71.955 50.49 72.225 ;
     RECT  2.16 72.495 50.49 72.765 ;
     RECT  2.16 73.035 50.49 73.305 ;
     RECT  2.16 73.575 50.49 73.845 ;
     RECT  2.16 74.115 50.49 74.385 ;
     RECT  2.16 74.655 50.49 74.925 ;
     RECT  2.16 75.195 50.49 75.465 ;
     RECT  2.16 75.735 50.49 76.005 ;
     RECT  2.16 76.275 50.49 76.545 ;
     RECT  2.16 76.815 50.49 77.085 ;
     RECT  2.16 77.355 50.49 77.625 ;
     RECT  2.16 77.895 50.49 78.165 ;
     RECT  2.16 78.435 50.49 78.705 ;
     RECT  2.16 78.975 50.49 79.245 ;
     RECT  2.16 79.515 50.49 79.785 ;
     RECT  2.16 80.055 50.49 80.325 ;
     RECT  2.16 80.595 50.49 80.865 ;
     RECT  2.16 81.135 50.49 81.405 ;
     RECT  2.16 81.675 50.49 81.945 ;
     RECT  2.16 82.215 50.49 82.485 ;
     RECT  2.16 82.755 50.49 83.025 ;
     RECT  2.16 83.295 50.49 83.565 ;
     RECT  2.16 83.835 50.49 84.105 ;
    LAYER M1 ;
     RECT  2.16 2.151 50.49 84.249 ;
    LAYER M2 ;
     RECT  0.031 26.802 0.067 26.82 ;
     RECT  0.031 30.924 0.067 31.14 ;
     RECT  0.031 40.806 0.067 40.824 ;
     RECT  0.031 42.732 0.067 42.75 ;
     RECT  0.031 51.642 0.067 52.038 ;
     RECT  0.031 54.306 0.067 54.324 ;
     RECT  0.067 26.802 0.103 27.234 ;
     RECT  0.067 30.852 0.103 31.14 ;
     RECT  0.031 34.2 0.103 34.218 ;
     RECT  0.031 45.81 0.103 45.828 ;
     RECT  0.031 47.592 0.103 47.61 ;
     RECT  0.067 54.144 0.103 54.324 ;
     RECT  0.031 60.426 0.103 60.444 ;
     RECT  0.103 30.852 0.139 31.212 ;
     RECT  0.067 32.202 0.139 32.292 ;
     RECT  0.103 33.624 0.139 34.218 ;
     RECT  0.031 37.062 0.139 37.08 ;
     RECT  0.103 38.826 0.139 38.844 ;
     RECT  0.067 40.608 0.139 40.824 ;
     RECT  0.103 45.396 0.139 45.828 ;
     RECT  0.103 47.052 0.139 47.61 ;
     RECT  0.103 49.671 0.139 49.689 ;
     RECT  0.067 51.516 0.139 52.119 ;
     RECT  0.139 30.852 0.175 31.446 ;
     RECT  0.139 32.202 0.175 34.218 ;
     RECT  0.139 38.826 0.175 39.429 ;
     RECT  0.139 40.41 0.175 40.824 ;
     RECT  0.103 48.402 0.175 48.42 ;
     RECT  0.139 49.671 0.175 52.119 ;
     RECT  0.031 58.698 0.175 58.716 ;
     RECT  0.031 30.042 0.211 30.06 ;
     RECT  0.175 30.852 0.211 35.802 ;
     RECT  0.175 38.826 0.211 40.824 ;
     RECT  0.139 45.396 0.211 47.61 ;
     RECT  0.175 48.402 0.211 52.119 ;
     RECT  0.103 53.37 0.211 53.388 ;
     RECT  0.103 54.144 0.211 54.936 ;
     RECT  0.103 59.886 0.211 60.444 ;
     RECT  0.139 36.792 0.247 37.08 ;
     RECT  0.067 42.732 0.247 42.894 ;
     RECT  0.139 43.686 0.247 44.514 ;
     RECT  0.211 45.306 0.247 52.119 ;
     RECT  0.175 58.356 0.247 58.716 ;
     RECT  0.211 38.826 0.283 41.004 ;
     RECT  0.175 41.922 0.283 41.94 ;
     RECT  0.247 57.726 0.283 58.716 ;
     RECT  0.211 59.616 0.283 60.444 ;
     RECT  0.283 57.726 0.311 60.444 ;
     RECT  0.103 26.802 0.319 27.63 ;
     RECT  0.211 30.042 0.319 35.802 ;
     RECT  0.247 36.792 0.319 37.539 ;
     RECT  0.311 57.726 0.355 58.284 ;
     RECT  0.247 45.306 0.391 52.389 ;
     RECT  0.211 53.37 0.391 55.044 ;
     RECT  0.319 26.37 0.427 27.63 ;
     RECT  0.391 45.27 0.427 55.044 ;
     RECT  0.247 42.732 0.463 44.514 ;
     RECT  0.427 45.27 0.463 55.278 ;
     RECT  0.463 42.732 0.491 55.278 ;
     RECT  0.427 26.37 0.499 28.044 ;
     RECT  0.283 38.826 0.499 41.94 ;
     RECT  0.491 42.732 0.499 52.272 ;
     RECT  0.031 24.372 0.535 24.39 ;
     RECT  0.319 30.042 0.535 37.539 ;
     RECT  0.499 38.826 0.571 52.272 ;
     RECT  0.499 26.37 0.679 28.314 ;
     RECT  0.535 30.042 0.715 37.62 ;
     RECT  0.535 24.21 0.859 24.39 ;
     RECT  0.679 26.37 0.895 28.98 ;
     RECT  0.715 29.772 0.895 37.62 ;
     RECT  0.355 25.452 0.967 25.47 ;
     RECT  0.895 26.37 0.967 37.62 ;
     RECT  0.859 23.832 1.111 24.39 ;
     RECT  0.967 25.452 1.147 37.62 ;
     RECT  0.571 38.556 1.147 52.272 ;
     RECT  0.491 53.37 1.471 55.278 ;
     RECT  1.147 25.452 1.543 52.272 ;
     RECT  1.543 25.452 1.615 52.578 ;
     RECT  1.471 53.334 1.615 55.278 ;
     RECT  1.111 23.67 1.939 24.39 ;
     RECT  1.615 25.452 1.939 55.278 ;
     RECT  1.939 23.67 2.011 55.278 ;
     RECT  2.011 23.292 2.16 55.278 ;
     RECT  0.535 56.844 2.16 56.862 ;
     RECT  0.355 57.618 2.16 58.284 ;
     RECT  0.311 59.076 2.16 60.444 ;
     RECT  2.16 2.151 12.523 84.249 ;
     RECT  12.523 2.106 14.099 84.249 ;
     RECT  14.099 2.151 15.259 84.249 ;
     RECT  15.259 2.151 15.395 84.906 ;
     RECT  15.395 2.151 16.375 84.249 ;
     RECT  16.375 2.151 16.511 84.366 ;
     RECT  15.979 1.152 16.843 1.17 ;
     RECT  16.843 1.152 16.979 1.206 ;
     RECT  16.979 1.188 17.087 1.206 ;
     RECT  16.511 2.151 21.343 84.249 ;
     RECT  21.343 2.151 21.443 84.906 ;
     RECT  21.443 2.151 22.531 84.294 ;
     RECT  22.531 2.151 23.215 84.564 ;
     RECT  23.215 2.151 23.891 84.906 ;
     RECT  23.891 2.151 24.467 84.708 ;
     RECT  24.467 2.151 26.131 84.249 ;
     RECT  26.131 2.106 27.455 84.249 ;
     RECT  27.455 2.151 33.655 84.249 ;
     RECT  33.655 2.151 34.619 84.906 ;
     RECT  34.771 1.152 35.195 1.17 ;
     RECT  34.619 2.151 50.49 84.249 ;
    LAYER M3 ;
     RECT  26.712 0.091 26.73 0.139 ;
     RECT  13.536 0.139 14.202 0.187 ;
     RECT  15.516 0.139 16.938 0.187 ;
     RECT  24.48 0.139 24.498 0.187 ;
     RECT  26.712 0.139 27.342 0.187 ;
     RECT  33.048 0.139 33.066 0.187 ;
     RECT  35.784 0.139 35.802 0.187 ;
     RECT  13.536 0.187 17.082 0.235 ;
     RECT  26.532 0.187 27.342 0.235 ;
     RECT  35.064 0.187 35.802 0.283 ;
     RECT  25.236 0.139 25.254 0.379 ;
     RECT  26.532 0.235 27.954 0.379 ;
     RECT  35.064 0.283 35.838 0.379 ;
     RECT  36.684 0.331 36.702 0.379 ;
     RECT  38.304 0.139 38.898 0.379 ;
     RECT  23.652 0.187 24.498 0.413 ;
     RECT  20.304 0.139 20.322 0.427 ;
     RECT  25.236 0.379 27.954 0.427 ;
     RECT  29.052 0.139 29.07 0.427 ;
     RECT  30.852 0.139 31.878 0.427 ;
     RECT  35.064 0.379 36.702 0.427 ;
     RECT  38.016 0.379 38.898 0.427 ;
     RECT  20.16 0.427 20.322 0.475 ;
     RECT  24.732 0.427 27.954 0.475 ;
     RECT  28.8 0.427 29.07 0.475 ;
     RECT  30.456 0.427 32.094 0.475 ;
     RECT  32.904 0.187 33.066 0.475 ;
     RECT  13.356 0.235 17.082 0.523 ;
     RECT  17.892 0.139 18.414 0.523 ;
     RECT  20.16 0.475 20.466 0.523 ;
     RECT  23.652 0.413 23.778 0.523 ;
     RECT  24.732 0.475 29.07 0.523 ;
     RECT  29.916 0.475 33.066 0.523 ;
     RECT  33.804 0.139 34.146 0.523 ;
     RECT  35.064 0.427 38.898 0.523 ;
     RECT  13.356 0.523 18.774 0.571 ;
     RECT  19.656 0.523 20.466 0.571 ;
     RECT  13.356 0.571 21.078 0.715 ;
     RECT  13.356 0.715 21.654 1.099 ;
     RECT  22.824 0.523 23.778 1.099 ;
     RECT  24.732 0.523 39.222 1.147 ;
     RECT  13.104 1.099 23.778 1.627 ;
     RECT  24.696 1.147 39.258 1.627 ;
     RECT  13.104 1.627 39.258 2.101 ;
     RECT  12.528 2.101 39.258 2.371 ;
     RECT  2.415 2.143 2.505 2.413 ;
     RECT  7.815 2.143 7.905 2.413 ;
     RECT  40.215 2.143 40.305 2.413 ;
     RECT  45.615 2.143 45.705 2.413 ;
     RECT  12.528 2.371 39.366 2.767 ;
     RECT  11.952 2.767 39.366 2.831 ;
     RECT  12.816 2.831 39.366 3.379 ;
     RECT  11.952 2.831 11.97 3.721 ;
     RECT  11.628 3.721 11.97 4.261 ;
     RECT  12.816 3.379 39.402 4.261 ;
     RECT  11.628 4.261 39.402 6.421 ;
     RECT  11.628 6.421 39.438 7.655 ;
     RECT  11.808 7.655 39.438 7.925 ;
     RECT  11.88 7.925 39.438 9.085 ;
     RECT  11.556 9.085 39.438 10.253 ;
     RECT  11.628 10.253 39.438 11.659 ;
     RECT  11.484 11.659 39.438 11.821 ;
     RECT  11.412 11.821 39.438 13.441 ;
     RECT  11.052 13.441 39.438 13.567 ;
     RECT  7.815 2.413 8.097 13.711 ;
     RECT  7.815 13.711 8.658 13.829 ;
     RECT  6.12 13.675 6.138 13.945 ;
     RECT  5.94 13.945 6.138 13.981 ;
     RECT  7.815 13.829 8.586 13.981 ;
     RECT  7.452 13.981 8.586 14.179 ;
     RECT  5.832 13.981 6.282 14.215 ;
     RECT  5.796 14.215 6.282 14.251 ;
     RECT  5.076 14.251 6.282 14.369 ;
     RECT  3.672 13.945 3.69 14.485 ;
     RECT  5.832 14.369 6.282 14.513 ;
     RECT  3.672 14.485 4.302 14.521 ;
     RECT  5.94 14.513 6.282 14.521 ;
     RECT  7.2 14.179 8.586 14.521 ;
     RECT  5.94 14.521 8.586 14.639 ;
     RECT  3.672 14.521 4.878 14.909 ;
     RECT  5.94 14.639 8.406 14.909 ;
     RECT  2.415 2.413 2.697 15.025 ;
     RECT  3.672 14.909 4.302 15.025 ;
     RECT  5.94 14.909 8.097 15.331 ;
     RECT  10.764 13.567 39.438 15.529 ;
     RECT  9.684 15.493 9.702 15.601 ;
     RECT  5.58 15.331 8.097 15.871 ;
     RECT  5.58 15.871 8.586 16.069 ;
     RECT  9.36 15.601 9.702 16.069 ;
     RECT  5.58 16.069 9.702 16.105 ;
     RECT  5.472 16.105 9.702 16.141 ;
     RECT  5.256 16.141 9.702 16.339 ;
     RECT  10.584 15.529 39.438 16.339 ;
     RECT  2.415 15.025 4.302 16.645 ;
     RECT  5.256 16.339 39.438 16.645 ;
     RECT  2.415 16.645 39.438 16.709 ;
     RECT  9.108 16.709 39.438 16.799 ;
     RECT  2.415 16.709 8.097 16.915 ;
     RECT  2.268 16.915 8.097 17.455 ;
     RECT  10.836 16.799 39.438 17.609 ;
     RECT  2.268 17.455 8.694 18.031 ;
     RECT  9.648 16.799 9.882 18.031 ;
     RECT  2.268 18.031 9.882 18.535 ;
     RECT  2.268 18.535 9.918 18.725 ;
     RECT  10.944 17.609 39.438 18.769 ;
     RECT  10.872 18.769 39.438 18.805 ;
     RECT  2.268 18.725 9.882 19.229 ;
     RECT  9.792 19.229 9.882 19.471 ;
     RECT  10.764 18.805 39.438 19.471 ;
     RECT  2.268 19.229 9.054 19.769 ;
     RECT  9.792 19.471 39.438 20.281 ;
     RECT  2.268 19.769 8.73 20.425 ;
     RECT  2.196 20.425 8.73 21.127 ;
     RECT  9.648 20.281 39.438 21.127 ;
     RECT  2.196 21.127 39.438 23.287 ;
     RECT  1.116 23.665 1.134 23.827 ;
     RECT  0.864 23.827 1.134 24.205 ;
     RECT  0.54 24.205 1.134 24.367 ;
     RECT  2.016 23.287 39.438 24.475 ;
     RECT  1.98 24.475 39.438 24.745 ;
     RECT  1.944 24.745 39.438 25.555 ;
     RECT  0.036 24.367 1.134 25.789 ;
     RECT  1.908 25.555 39.438 25.789 ;
     RECT  0.036 25.789 39.438 26.825 ;
     RECT  0.072 26.825 39.438 30.037 ;
     RECT  0.036 30.037 39.438 34.223 ;
     RECT  0.072 34.223 39.438 37.057 ;
     RECT  0.036 37.057 39.438 40.829 ;
     RECT  0.108 40.829 39.438 42.727 ;
     RECT  0.036 42.727 39.438 43.871 ;
     RECT  0.036 43.871 10.458 44.617 ;
     RECT  0.036 44.617 10.71 44.653 ;
     RECT  11.52 43.871 39.438 44.653 ;
     RECT  0.036 44.653 39.438 45.833 ;
     RECT  0.072 45.833 39.438 46.589 ;
     RECT  0.072 46.589 8.226 47.317 ;
     RECT  8.964 46.589 39.438 47.317 ;
     RECT  0.072 47.317 39.438 47.587 ;
     RECT  0.036 47.587 39.438 49.037 ;
     RECT  0.036 49.037 0.666 50.203 ;
     RECT  1.404 49.037 39.438 50.203 ;
     RECT  0.036 50.203 39.438 50.423 ;
     RECT  1.404 50.423 39.438 50.791 ;
     RECT  40.215 2.413 40.497 50.791 ;
     RECT  0.036 50.423 0.666 50.909 ;
     RECT  0.036 50.909 0.594 51.149 ;
     RECT  1.404 50.791 40.497 51.161 ;
     RECT  1.44 51.161 40.497 52.205 ;
     RECT  0.036 51.149 0.558 53.131 ;
     RECT  1.476 52.205 40.497 53.357 ;
     RECT  0.036 53.131 0.594 53.549 ;
     RECT  0.036 53.549 0.558 54.329 ;
     RECT  2.016 53.357 40.497 54.365 ;
     RECT  0.108 54.329 0.558 54.796 ;
     RECT  2.304 54.365 40.497 55.531 ;
     RECT  1.728 55.531 40.497 55.561 ;
     RECT  1.728 55.561 40.59 56.633 ;
     RECT  1.728 56.633 12.042 57.451 ;
     RECT  12.78 56.633 40.59 57.451 ;
     RECT  0.108 54.796 0.594 57.677 ;
     RECT  0.108 57.677 0.342 58.217 ;
     RECT  1.728 57.451 40.59 58.253 ;
     RECT  2.304 58.253 40.59 58.487 ;
     RECT  0.108 58.217 0.306 58.693 ;
     RECT  2.304 58.487 6.426 58.955 ;
     RECT  7.2 58.487 40.59 59.071 ;
     RECT  0.036 58.693 0.306 59.099 ;
     RECT  2.412 58.955 6.426 59.189 ;
     RECT  2.415 59.189 6.426 59.269 ;
     RECT  7.2 59.071 40.626 59.269 ;
     RECT  2.415 59.269 40.626 59.369 ;
     RECT  0.036 59.099 0.234 59.639 ;
     RECT  0.036 59.639 0.126 59.909 ;
     RECT  10.908 59.369 40.626 60.151 ;
     RECT  0.036 59.909 0.054 60.449 ;
     RECT  2.415 59.369 10.17 60.583 ;
     RECT  10.908 60.151 40.698 60.583 ;
     RECT  2.415 60.583 40.698 62.267 ;
     RECT  2.415 62.267 40.626 62.699 ;
     RECT  10.908 62.699 40.626 63.815 ;
     RECT  2.415 62.699 10.17 63.823 ;
     RECT  10.908 63.815 40.59 63.823 ;
     RECT  2.415 63.823 40.59 64.391 ;
     RECT  2.415 64.391 40.554 65.281 ;
     RECT  2.415 65.281 40.59 69.719 ;
     RECT  2.415 69.719 4.986 71.221 ;
     RECT  5.724 69.719 40.59 71.221 ;
     RECT  2.415 71.221 40.59 71.609 ;
     RECT  2.415 71.609 40.497 71.681 ;
     RECT  2.415 71.681 5.022 71.717 ;
     RECT  5.76 71.681 40.497 72.955 ;
     RECT  5.724 72.955 40.497 73.229 ;
     RECT  2.415 71.717 4.986 74.425 ;
     RECT  5.76 73.229 40.497 74.425 ;
     RECT  2.415 74.425 40.497 75.437 ;
     RECT  3.42 75.437 40.497 75.497 ;
     RECT  3.456 75.497 40.497 75.569 ;
     RECT  5.94 75.569 40.497 76.037 ;
     RECT  5.976 76.037 40.497 76.109 ;
     RECT  3.456 75.569 5.094 77.287 ;
     RECT  6.192 76.109 40.497 77.287 ;
     RECT  3.456 77.287 40.497 77.657 ;
     RECT  3.708 77.657 40.497 78.089 ;
     RECT  3.996 78.089 40.497 78.359 ;
     RECT  4.104 78.359 40.497 78.431 ;
     RECT  4.104 78.431 10.53 78.503 ;
     RECT  4.104 78.503 6.966 78.653 ;
     RECT  4.104 78.653 5.634 78.899 ;
     RECT  6.696 78.653 6.966 78.899 ;
     RECT  6.948 78.899 6.966 78.971 ;
     RECT  7.815 78.503 10.53 79.241 ;
     RECT  4.104 78.899 5.49 79.753 ;
     RECT  7.815 79.241 10.458 80.059 ;
     RECT  11.412 78.431 40.497 80.059 ;
     RECT  6.768 80.059 6.786 80.131 ;
     RECT  6.372 80.131 7.038 80.221 ;
     RECT  7.815 80.059 40.497 80.221 ;
     RECT  4.104 79.753 5.526 80.329 ;
     RECT  4.032 80.329 5.526 80.401 ;
     RECT  6.372 80.221 40.497 80.401 ;
     RECT  4.032 80.401 40.497 80.519 ;
     RECT  6.336 80.519 40.497 80.555 ;
     RECT  4.032 80.519 5.526 80.591 ;
     RECT  4.032 80.591 5.418 80.629 ;
     RECT  3.816 80.629 5.418 80.669 ;
     RECT  6.372 80.555 40.497 80.669 ;
     RECT  6.372 80.669 6.57 80.789 ;
     RECT  7.668 80.669 40.497 80.789 ;
     RECT  11.16 80.789 40.497 80.861 ;
     RECT  11.304 80.861 40.497 80.909 ;
     RECT  7.668 80.789 8.91 80.933 ;
     RECT  6.408 80.789 6.498 81.059 ;
     RECT  9.72 80.789 10.386 81.059 ;
     RECT  7.668 80.933 8.622 81.595 ;
     RECT  7.308 81.595 8.622 81.751 ;
     RECT  7.308 81.751 8.874 81.869 ;
     RECT  7.416 81.869 8.874 82.147 ;
     RECT  9.792 81.059 10.386 82.147 ;
     RECT  6.408 81.059 6.426 82.381 ;
     RECT  6.228 82.381 6.426 82.453 ;
     RECT  4.032 80.669 5.418 82.459 ;
     RECT  6.192 82.453 6.426 82.459 ;
     RECT  4.032 82.459 6.426 82.525 ;
     RECT  7.416 82.147 10.386 82.651 ;
     RECT  4.032 82.525 6.462 82.687 ;
     RECT  7.2 82.651 10.566 82.687 ;
     RECT  4.032 82.687 10.566 82.723 ;
     RECT  11.412 80.909 40.497 82.723 ;
     RECT  4.032 82.723 40.497 82.787 ;
     RECT  4.212 82.787 40.497 82.859 ;
     RECT  4.212 82.859 8.766 82.877 ;
     RECT  4.212 82.877 8.622 82.949 ;
     RECT  9.576 82.859 40.497 82.949 ;
     RECT  9.576 82.949 11.214 82.985 ;
     RECT  6.336 82.949 8.622 83.021 ;
     RECT  4.248 82.949 5.346 83.093 ;
     RECT  6.444 83.021 8.622 83.093 ;
     RECT  4.896 83.093 5.346 83.129 ;
     RECT  9.648 82.985 11.214 83.129 ;
     RECT  6.444 83.093 6.534 83.219 ;
     RECT  9.648 83.129 10.422 83.219 ;
     RECT  11.196 83.129 11.214 83.219 ;
     RECT  5.148 83.129 5.346 83.255 ;
     RECT  7.776 83.093 8.097 83.255 ;
     RECT  6.516 83.219 6.534 83.363 ;
     RECT  9.756 83.219 9.774 83.363 ;
     RECT  5.148 83.255 5.274 83.489 ;
     RECT  5.148 83.489 5.166 83.525 ;
     RECT  12.06 82.949 40.497 83.669 ;
     RECT  2.415 75.437 2.697 83.987 ;
     RECT  7.815 83.255 8.097 83.987 ;
     RECT  12.492 83.669 40.497 83.987 ;
     RECT  45.615 2.413 45.897 83.987 ;
     RECT  12.492 83.987 40.305 84.065 ;
     RECT  12.492 84.065 39.258 84.077 ;
     RECT  2.415 83.987 2.505 84.257 ;
     RECT  7.815 83.987 7.905 84.257 ;
     RECT  40.215 84.065 40.305 84.257 ;
     RECT  45.615 83.987 45.705 84.257 ;
     RECT  12.672 84.077 39.258 84.365 ;
     RECT  13.428 84.365 39.258 84.941 ;
     RECT  13.428 84.941 39.222 85.517 ;
     RECT  13.428 85.517 14.094 85.853 ;
     RECT  12.672 84.365 12.69 85.949 ;
     RECT  13.428 85.853 13.914 86.045 ;
     RECT  24.3 85.517 39.222 86.141 ;
     RECT  24.408 86.141 39.222 86.189 ;
     RECT  13.572 86.045 13.914 86.237 ;
     RECT  15.012 85.517 23.49 86.237 ;
     RECT  24.408 86.189 25.326 86.237 ;
     RECT  26.208 86.189 29.898 86.237 ;
     RECT  30.672 86.189 34.506 86.237 ;
     RECT  35.46 86.189 39.15 86.237 ;
     RECT  15.012 86.237 15.714 86.285 ;
     RECT  19.044 86.237 19.062 86.285 ;
     RECT  22.104 86.237 22.122 86.285 ;
     RECT  24.408 86.237 24.426 86.285 ;
     RECT  29.88 86.237 29.898 86.285 ;
     RECT  34.056 86.237 34.074 86.285 ;
     RECT  36.684 86.237 36.702 86.285 ;
    LAYER M4 ;
     RECT  0.037 30.144 0.06 30.168 ;
     RECT  0.06 30.144 0.133 56.04 ;
     RECT  0.133 30.144 0.325 56.088 ;
     RECT  0.325 29.52 0.385 56.088 ;
     RECT  0.229 25.152 0.469 25.176 ;
     RECT  0.469 25.104 0.517 25.176 ;
     RECT  0.517 25.104 0.569 26.04 ;
     RECT  0.085 27.936 1.381 27.96 ;
     RECT  0.569 25.152 2.005 26.04 ;
     RECT  2.005 25.104 2.293 26.04 ;
     RECT  1.381 27.36 2.293 27.96 ;
     RECT  2.293 22.8 2.408 22.824 ;
     RECT  0.133 23.952 2.408 23.976 ;
     RECT  2.293 25.104 2.408 27.96 ;
     RECT  0.385 29.52 2.408 56.136 ;
     RECT  2.408 2.148 2.512 84.252 ;
     RECT  2.512 2.418 2.704 83.982 ;
     RECT  2.704 29.52 2.801 56.232 ;
     RECT  2.704 61.392 2.819 61.416 ;
     RECT  2.704 64.08 2.819 64.104 ;
     RECT  2.704 25.104 2.837 28.296 ;
     RECT  2.704 23.28 2.867 23.544 ;
     RECT  2.704 57.696 2.867 58.152 ;
     RECT  2.704 69.024 2.867 69.048 ;
     RECT  2.704 73.776 2.867 73.8 ;
     RECT  2.704 66.624 2.917 67.272 ;
     RECT  2.704 75.408 3.011 75.432 ;
     RECT  2.867 57.696 3.017 57.72 ;
     RECT  2.837 26.688 3.635 28.296 ;
     RECT  2.867 23.472 3.769 23.544 ;
     RECT  3.692 77.952 3.779 77.976 ;
     RECT  3.788 80.64 3.875 80.664 ;
     RECT  2.917 67.248 3.925 67.272 ;
     RECT  3.635 27.648 3.949 28.296 ;
     RECT  2.801 29.568 3.953 56.232 ;
     RECT  3.925 66.672 3.971 67.272 ;
     RECT  3.769 23.472 3.98 23.928 ;
     RECT  2.837 25.104 3.98 25.704 ;
     RECT  3.905 71.28 3.989 71.304 ;
     RECT  3.949 27.648 4.057 28.584 ;
     RECT  3.973 68.736 4.061 68.76 ;
     RECT  3.98 23.472 4.067 25.704 ;
     RECT  4.028 64.704 4.115 64.728 ;
     RECT  4.028 71.952 4.115 71.976 ;
     RECT  4.021 73.248 4.115 73.272 ;
     RECT  4.067 25.2 4.237 25.704 ;
     RECT  4.165 82.896 4.252 82.92 ;
     RECT  4.067 23.472 4.316 23.928 ;
     RECT  4.057 27.648 4.349 29.064 ;
     RECT  4.349 27.744 4.355 29.064 ;
     RECT  4.309 59.376 4.381 59.4 ;
     RECT  4.309 75.216 4.396 75.24 ;
     RECT  4.316 23.04 4.403 23.928 ;
     RECT  4.355 27.84 4.421 29.064 ;
     RECT  3.953 30.432 4.421 56.232 ;
     RECT  4.403 23.904 4.451 23.928 ;
     RECT  3.971 66.672 4.46 66.696 ;
     RECT  4.405 72.96 4.493 72.984 ;
     RECT  4.381 59.376 4.525 59.496 ;
     RECT  4.421 28.08 4.529 29.064 ;
     RECT  4.46 66.48 4.529 66.696 ;
     RECT  4.529 66.48 4.547 66.504 ;
     RECT  4.453 75.744 4.547 75.768 ;
     RECT  4.417 22.8 4.565 22.824 ;
     RECT  4.421 32.928 4.565 56.232 ;
     RECT  4.501 57.456 4.588 57.48 ;
     RECT  4.237 25.2 4.637 26.664 ;
     RECT  4.201 62.64 4.693 62.664 ;
     RECT  4.525 59.376 4.7 59.592 ;
     RECT  4.565 32.928 4.745 33.48 ;
     RECT  4.637 25.2 4.817 26.472 ;
     RECT  4.844 77.52 4.931 77.544 ;
     RECT  4.565 34.464 4.94 56.232 ;
     RECT  4.94 34.464 5.027 56.712 ;
     RECT  4.693 62.64 5.033 62.76 ;
     RECT  4.529 28.56 5.069 29.064 ;
     RECT  4.741 79.92 5.123 79.944 ;
     RECT  5.069 29.04 5.141 29.064 ;
     RECT  4.7 59.376 5.141 59.784 ;
     RECT  5.033 62.64 5.149 62.712 ;
     RECT  4.817 25.68 5.213 26.472 ;
     RECT  5.173 62.16 5.257 62.184 ;
     RECT  4.421 30.432 5.357 31.944 ;
     RECT  4.957 82.656 5.413 82.68 ;
     RECT  5.357 30.432 5.465 31.368 ;
     RECT  5.413 64.896 5.5 64.92 ;
     RECT  4.745 33.216 5.501 33.48 ;
     RECT  5.413 82.656 5.501 82.824 ;
     RECT  5.281 69.312 5.677 69.336 ;
     RECT  5.213 25.68 5.681 25.704 ;
     RECT  5.501 82.656 5.713 82.68 ;
     RECT  5.713 82.464 5.753 82.68 ;
     RECT  5.465 30.432 5.825 30.648 ;
     RECT  5.9 66.384 5.987 66.408 ;
     RECT  5.948 76.08 6.035 76.104 ;
     RECT  5.893 74.64 6.149 74.664 ;
     RECT  5.825 30.624 6.221 30.648 ;
     RECT  6.073 75.744 6.227 75.768 ;
     RECT  5.753 82.464 6.227 82.488 ;
     RECT  5.501 33.36 6.325 33.48 ;
     RECT  5.027 34.464 6.325 56.376 ;
     RECT  5.141 59.76 6.325 59.784 ;
     RECT  6.325 59.76 6.412 60.072 ;
     RECT  6.325 33.36 6.793 56.376 ;
     RECT  5.677 69.072 6.865 69.336 ;
     RECT  6.613 57.984 6.973 58.008 ;
     RECT  7.244 80.64 7.285 80.664 ;
     RECT  5.713 72.96 7.429 72.984 ;
     RECT  7.285 80.64 7.429 81.624 ;
     RECT  7.1 82.848 7.429 82.872 ;
     RECT  6.145 78.624 7.436 78.648 ;
     RECT  6.469 27.744 7.477 27.768 ;
     RECT  7.436 78.288 7.477 78.648 ;
     RECT  6.865 69.024 7.58 69.336 ;
     RECT  7.429 66.48 7.585 66.504 ;
     RECT  7.429 72.432 7.621 72.984 ;
     RECT  6.973 29.088 7.669 29.112 ;
     RECT  6.973 57.696 7.669 58.008 ;
     RECT  7.477 27.072 7.808 27.768 ;
     RECT  7.669 29.088 7.808 29.496 ;
     RECT  6.793 33.12 7.808 56.376 ;
     RECT  7.669 57.696 7.808 58.104 ;
     RECT  6.412 59.76 7.808 59.784 ;
     RECT  6.829 61.2 7.808 61.224 ;
     RECT  7.669 62.784 7.808 62.808 ;
     RECT  7.585 66.24 7.808 66.504 ;
     RECT  7.58 69.024 7.808 69.72 ;
     RECT  7.621 71.856 7.808 72.984 ;
     RECT  7.477 78.192 7.808 78.648 ;
     RECT  7.429 80.64 7.808 82.872 ;
     RECT  7.808 2.148 7.912 84.252 ;
     RECT  7.912 2.418 8.104 83.982 ;
     RECT  8.104 78.48 8.165 78.648 ;
     RECT  8.104 32.592 8.243 33.048 ;
     RECT  8.104 79.872 8.243 79.896 ;
     RECT  8.243 33.024 8.273 33.048 ;
     RECT  8.104 75.888 8.281 75.912 ;
     RECT  8.104 27.072 8.309 27.096 ;
     RECT  8.104 68.352 8.417 69.336 ;
     RECT  8.104 34.08 8.489 34.104 ;
     RECT  8.104 35.184 8.489 56.904 ;
     RECT  8.104 62.256 8.489 63.816 ;
     RECT  8.104 66.144 8.524 66.168 ;
     RECT  8.489 35.424 8.597 56.904 ;
     RECT  8.104 60.384 8.62 60.408 ;
     RECT  8.597 46.32 8.705 56.904 ;
     RECT  8.417 68.352 8.813 68.376 ;
     RECT  8.104 82.848 8.819 82.872 ;
     RECT  8.104 21.168 8.867 21.192 ;
     RECT  8.104 71.472 8.915 71.496 ;
     RECT  8.104 80.88 8.956 80.904 ;
     RECT  8.104 58.464 8.957 58.488 ;
     RECT  9.164 58.656 9.251 58.68 ;
     RECT  8.104 77.088 9.301 77.112 ;
     RECT  9.301 76.704 9.308 77.112 ;
     RECT  8.165 78.624 9.353 78.648 ;
     RECT  9.308 76.704 9.388 77.544 ;
     RECT  9.388 77.52 9.395 77.544 ;
     RECT  9.109 82.416 9.425 82.44 ;
     RECT  8.489 62.256 9.461 63.144 ;
     RECT  9.461 62.304 9.533 63.144 ;
     RECT  9.452 32.688 9.539 32.712 ;
     RECT  8.705 46.512 9.641 56.904 ;
     RECT  9.596 21.648 9.683 21.672 ;
     RECT  9.596 28.368 9.683 28.392 ;
     RECT  9.685 66.096 9.772 66.12 ;
     RECT  9.692 75.36 9.779 75.384 ;
     RECT  9.356 30.528 9.781 30.552 ;
     RECT  9.533 63.12 10.037 63.144 ;
     RECT  9.889 57.024 10.217 57.048 ;
     RECT  10.213 82.656 10.249 82.68 ;
     RECT  9.205 73.008 10.253 73.032 ;
     RECT  10.249 82.656 10.333 82.92 ;
     RECT  9.781 30.24 10.357 30.552 ;
     RECT  8.597 35.424 10.361 45.192 ;
     RECT  10.357 30.24 10.499 30.744 ;
     RECT  10.333 82.656 10.577 82.68 ;
     RECT  9.641 46.512 10.681 55.896 ;
     RECT  10.177 28.704 10.717 28.728 ;
     RECT  10.361 43.008 10.717 45.192 ;
     RECT  10.717 43.008 10.753 45.336 ;
     RECT  10.681 46.32 10.753 56.376 ;
     RECT  10.7 70.8 10.787 70.824 ;
     RECT  10.609 58.944 10.789 58.968 ;
     RECT  10.213 68.928 10.828 68.952 ;
     RECT  10.741 73.488 10.828 73.512 ;
     RECT  10.717 28.704 10.829 28.824 ;
     RECT  10.753 43.008 10.829 56.376 ;
     RECT  10.796 76.704 10.883 76.728 ;
     RECT  10.825 21.168 10.973 21.192 ;
     RECT  10.361 35.424 11.005 41.976 ;
     RECT  10.988 20.256 11.075 20.28 ;
     RECT  11.005 35.376 11.077 41.976 ;
     RECT  10.969 16.176 11.081 16.2 ;
     RECT  10.789 58.944 11.113 59.256 ;
     RECT  10.933 62.736 11.185 62.76 ;
     RECT  11.173 18.384 11.26 18.408 ;
     RECT  10.829 46.272 11.297 56.376 ;
     RECT  11.077 35.28 11.329 41.976 ;
     RECT  10.829 43.008 11.329 45.192 ;
     RECT  10.837 80.88 11.333 80.904 ;
     RECT  11.113 58.704 11.413 59.256 ;
     RECT  10.499 30.24 11.441 30.6 ;
     RECT  11.441 30.336 11.473 30.6 ;
     RECT  11.329 35.28 11.513 45.192 ;
     RECT  11.468 11.664 11.555 11.688 ;
     RECT  11.509 10.224 11.596 10.248 ;
     RECT  11.473 30.336 11.621 30.696 ;
     RECT  11.185 62.736 11.693 63.672 ;
     RECT  11.297 46.32 11.729 56.376 ;
     RECT  11.996 57.024 12.013 57.048 ;
     RECT  11.621 30.672 12.053 30.696 ;
     RECT  12.013 57.024 12.083 57.288 ;
     RECT  11.996 71.616 12.083 71.64 ;
     RECT  11.413 58.656 12.277 59.256 ;
     RECT  12.083 57.264 12.337 57.288 ;
     RECT  12.277 58.32 12.337 59.256 ;
     RECT  11.513 35.376 12.373 45.192 ;
     RECT  11.729 46.32 12.373 55.944 ;
     RECT  12.337 57.264 12.428 59.256 ;
     RECT  12.049 78.144 12.469 78.168 ;
     RECT  12.337 28.752 12.481 28.776 ;
     RECT  12.121 14.88 12.517 14.904 ;
     RECT  12.481 84.048 12.589 84.072 ;
     RECT  12.517 23.088 12.661 23.112 ;
     RECT  12.517 71.808 12.697 71.832 ;
     RECT  12.445 18.432 12.709 18.456 ;
     RECT  12.733 21.648 12.757 21.672 ;
     RECT  12.733 82.464 12.769 82.488 ;
     RECT  12.769 82.368 12.805 82.488 ;
     RECT  12.709 18.432 12.841 18.792 ;
     RECT  12.805 82.272 12.86 82.488 ;
     RECT  12.86 82.08 12.908 82.488 ;
     RECT  12.181 9.648 12.949 9.672 ;
     RECT  12.985 2.256 13.045 2.28 ;
     RECT  12.877 11.952 13.045 11.976 ;
     RECT  12.517 13.872 13.045 14.904 ;
     RECT  12.565 16.272 13.045 16.296 ;
     RECT  12.613 67.872 13.093 67.896 ;
     RECT  12.38 69.936 13.093 69.96 ;
     RECT  12.86 75.888 13.093 75.912 ;
     RECT  13.093 0.192 13.129 1.128 ;
     RECT  13.045 2.256 13.129 3.336 ;
     RECT  13.093 25.536 13.129 25.56 ;
     RECT  13.093 32.688 13.129 32.712 ;
     RECT  12.908 81.744 13.129 82.488 ;
     RECT  12.589 83.52 13.129 84.072 ;
     RECT  13.045 13.056 13.165 14.904 ;
     RECT  13.045 16.08 13.165 16.296 ;
     RECT  12.661 85.92 13.189 85.944 ;
     RECT  13.093 80.112 13.201 80.136 ;
     RECT  13.129 81.744 13.201 84.36 ;
     RECT  13.129 0.192 13.208 3.336 ;
     RECT  13.093 4.656 13.208 5.304 ;
     RECT  13.093 8.448 13.208 8.472 ;
     RECT  12.949 9.648 13.208 9.816 ;
     RECT  13.045 11.952 13.208 12.072 ;
     RECT  13.165 13.056 13.208 16.296 ;
     RECT  12.841 17.616 13.208 18.792 ;
     RECT  12.757 21.072 13.208 21.672 ;
     RECT  12.661 22.8 13.208 23.112 ;
     RECT  13.129 25.536 13.208 26.136 ;
     RECT  12.481 28.752 13.208 29.016 ;
     RECT  13.129 32.496 13.208 32.712 ;
     RECT  12.373 35.376 13.208 55.944 ;
     RECT  12.428 57.264 13.208 60.024 ;
     RECT  12.229 62.592 13.208 62.616 ;
     RECT  12.476 64.56 13.208 64.584 ;
     RECT  13.093 65.616 13.208 65.64 ;
     RECT  13.093 67.872 13.208 69.96 ;
     RECT  12.697 71.808 13.208 72.408 ;
     RECT  13.093 74.16 13.208 74.184 ;
     RECT  13.093 75.888 13.208 76.056 ;
     RECT  12.469 77.712 13.208 78.168 ;
     RECT  13.201 80.112 13.208 84.36 ;
     RECT  13.189 85.92 13.331 86.376 ;
     RECT  13.208 0.192 13.333 84.36 ;
     RECT  13.333 0.144 13.475 84.36 ;
     RECT  13.475 0.144 13.504 84.216 ;
     RECT  13.504 69.744 13.565 70.152 ;
     RECT  13.504 30.768 13.667 32.04 ;
     RECT  13.504 14.112 13.673 16.056 ;
     RECT  13.504 56.976 13.673 57.432 ;
     RECT  13.504 9.168 13.681 11.4 ;
     RECT  13.667 30.768 13.681 31.608 ;
     RECT  13.504 17.04 13.709 18.216 ;
     RECT  13.681 10.8 13.715 11.4 ;
     RECT  13.504 72.912 13.715 74.712 ;
     RECT  13.504 26.112 13.745 26.136 ;
     RECT  13.709 18.192 13.763 18.216 ;
     RECT  13.504 28.992 13.763 29.64 ;
     RECT  13.504 58.608 13.763 58.632 ;
     RECT  13.673 14.112 13.811 14.568 ;
     RECT  13.715 73.536 13.825 73.56 ;
     RECT  13.504 24.096 13.859 24.12 ;
     RECT  13.504 63.36 13.859 63.384 ;
     RECT  13.673 56.976 13.889 57.336 ;
     RECT  13.715 74.688 13.907 74.712 ;
     RECT  13.811 14.112 13.925 14.136 ;
     RECT  13.709 17.04 13.997 17.064 ;
     RECT  13.715 10.8 14.033 10.824 ;
     RECT  13.504 60.432 14.051 60.456 ;
     RECT  13.331 85.92 14.065 86.232 ;
     RECT  13.504 21.648 14.177 22.776 ;
     RECT  13.889 57.312 14.177 57.336 ;
     RECT  13.504 6.72 14.195 7.416 ;
     RECT  13.504 0.144 14.213 5.736 ;
     RECT  13.681 9.168 14.213 9.672 ;
     RECT  13.565 70.128 14.213 70.152 ;
     RECT  14.177 21.792 14.243 22.776 ;
     RECT  13.504 68.112 14.243 68.136 ;
     RECT  13.504 76.656 14.243 84.216 ;
     RECT  14.243 76.656 14.249 76.92 ;
     RECT  13.504 27.888 14.285 27.912 ;
     RECT  14.243 78.048 14.291 84.216 ;
     RECT  14.291 80.4 14.483 84.216 ;
     RECT  13.504 19.92 14.492 20.04 ;
     RECT  14.213 0.192 14.533 5.736 ;
     RECT  14.195 6.72 14.533 6.888 ;
     RECT  14.065 85.824 14.533 86.232 ;
     RECT  14.492 19.92 14.579 20.76 ;
     RECT  14.54 27.792 14.627 27.816 ;
     RECT  14.569 71.808 14.653 71.832 ;
     RECT  14.569 84.384 14.677 84.456 ;
     RECT  14.533 85.488 14.677 86.232 ;
     RECT  13.504 13.104 14.681 13.128 ;
     RECT  13.504 66.672 14.681 66.696 ;
     RECT  14.243 22.752 14.684 22.776 ;
     RECT  13.504 36.24 14.713 55.272 ;
     RECT  14.291 78.048 14.723 79.272 ;
     RECT  13.504 33.504 14.753 34.968 ;
     RECT  14.677 84.384 14.771 86.232 ;
     RECT  14.723 78.048 14.819 79.224 ;
     RECT  14.213 9.168 14.821 9.192 ;
     RECT  14.753 33.504 14.821 34.392 ;
     RECT  14.713 35.952 14.821 55.272 ;
     RECT  14.785 74.256 14.849 74.28 ;
     RECT  14.533 0.192 14.861 6.888 ;
     RECT  14.483 81.84 14.867 83.352 ;
     RECT  14.861 6.192 14.915 6.888 ;
     RECT  14.849 74.112 14.924 74.28 ;
     RECT  13.681 30.768 14.929 31.128 ;
     RECT  14.924 74.112 14.933 74.712 ;
     RECT  14.771 85.488 14.957 86.232 ;
     RECT  14.579 19.92 14.963 20.616 ;
     RECT  14.771 84.384 14.963 84.456 ;
     RECT  14.821 8.448 14.969 9.192 ;
     RECT  14.821 35.472 14.969 55.272 ;
     RECT  14.725 24.192 14.972 24.216 ;
     RECT  14.933 74.688 15.011 74.712 ;
     RECT  14.929 62.736 15.037 62.76 ;
     RECT  14.861 0.192 15.059 5.064 ;
     RECT  14.972 24.192 15.059 25.704 ;
     RECT  13.763 29.616 15.068 29.64 ;
     RECT  14.929 30.672 15.068 31.128 ;
     RECT  15.068 29.616 15.109 31.128 ;
     RECT  14.917 66.048 15.113 66.072 ;
     RECT  14.483 80.4 15.113 80.472 ;
     RECT  15.001 14.16 15.145 14.184 ;
     RECT  15.109 29.472 15.155 31.128 ;
     RECT  15.109 63.792 15.164 63.816 ;
     RECT  15.037 62.592 15.181 62.76 ;
     RECT  15.164 63.792 15.181 63.96 ;
     RECT  14.963 84.384 15.196 84.408 ;
     RECT  15.181 62.592 15.26 63.96 ;
     RECT  15.26 62.592 15.265 64.344 ;
     RECT  15.181 70.704 15.265 70.728 ;
     RECT  15.265 62.592 15.293 62.76 ;
     RECT  15.212 59.136 15.299 59.16 ;
     RECT  15.113 80.448 15.299 80.472 ;
     RECT  15.293 62.592 15.347 62.616 ;
     RECT  15.265 64.32 15.347 64.344 ;
     RECT  15.155 29.472 15.349 29.784 ;
     RECT  14.684 22.752 15.365 23.208 ;
     RECT  15.059 24.192 15.365 25.416 ;
     RECT  14.969 9.168 15.395 9.192 ;
     RECT  14.915 6.864 15.397 6.888 ;
     RECT  15.397 6.864 15.401 7.368 ;
     RECT  14.969 35.568 15.401 45.72 ;
     RECT  15.349 29.232 15.436 29.784 ;
     RECT  14.821 32.64 15.436 34.392 ;
     RECT  14.819 78.048 15.437 79.08 ;
     RECT  15.436 32.64 15.443 34.248 ;
     RECT  14.867 82.08 15.445 83.352 ;
     RECT  15.059 0.192 15.461 1.224 ;
     RECT  15.401 7.344 15.509 7.368 ;
     RECT  15.436 29.28 15.587 29.784 ;
     RECT  15.365 22.8 15.589 23.208 ;
     RECT  15.365 24.192 15.589 25.128 ;
     RECT  15.401 35.568 15.635 42.072 ;
     RECT  15.644 16.992 15.685 17.016 ;
     RECT  15.589 22.8 15.725 25.128 ;
     RECT  15.685 16.992 15.731 17.112 ;
     RECT  15.443 32.64 15.757 34.104 ;
     RECT  15.437 78.672 15.761 79.08 ;
     RECT  15.461 0.144 15.779 1.224 ;
     RECT  15.445 82.08 15.779 83.784 ;
     RECT  14.957 85.488 15.779 86.28 ;
     RECT  15.788 20.736 15.875 20.76 ;
     RECT  15.757 32.256 15.905 34.104 ;
     RECT  15.325 26.4 15.925 26.424 ;
     RECT  15.925 26.4 15.937 27.144 ;
     RECT  15.145 13.68 15.973 14.184 ;
     RECT  15.212 19.68 15.973 19.704 ;
     RECT  15.937 26.4 15.98 27.576 ;
     RECT  15.973 13.296 16.037 14.184 ;
     RECT  16.037 13.296 16.045 14.232 ;
     RECT  15.779 82.56 16.049 83.784 ;
     RECT  15.973 79.152 16.057 79.176 ;
     RECT  16.045 13.104 16.121 14.232 ;
     RECT  16.081 80.592 16.153 80.616 ;
     RECT  15.973 19.104 16.157 20.184 ;
     RECT  15.059 2.208 16.165 5.064 ;
     RECT  16.157 20.16 16.193 20.184 ;
     RECT  16.117 56.448 16.201 56.472 ;
     RECT  16.165 2.208 16.225 5.112 ;
     RECT  16.153 80.592 16.229 81.528 ;
     RECT  16.225 2.208 16.259 5.352 ;
     RECT  16.049 82.656 16.259 83.784 ;
     RECT  15.731 17.04 16.261 17.112 ;
     RECT  15.401 43.056 16.261 45.72 ;
     RECT  15.635 35.568 16.301 37.656 ;
     RECT  16.121 13.104 16.307 13.32 ;
     RECT  15.779 85.488 16.309 86.232 ;
     RECT  16.309 84.912 16.333 86.232 ;
     RECT  16.307 13.104 16.337 13.128 ;
     RECT  16.261 63.696 16.345 63.72 ;
     RECT  16.261 14.784 16.355 14.808 ;
     RECT  15.155 30.864 16.364 30.888 ;
     RECT  16.297 73.536 16.381 73.56 ;
     RECT  15.635 38.688 16.403 42.072 ;
     RECT  16.364 30.864 16.405 31.032 ;
     RECT  16.333 83.808 16.417 86.232 ;
     RECT  16.225 68.64 16.445 68.664 ;
     RECT  16.405 30.768 16.453 31.032 ;
     RECT  16.403 40.368 16.477 42.072 ;
     RECT  16.261 43.056 16.477 45.768 ;
     RECT  16.333 56.976 16.477 57 ;
     RECT  16.301 35.568 16.481 37.608 ;
     RECT  16.261 17.04 16.547 17.64 ;
     RECT  16.477 56.976 16.547 57.288 ;
     RECT  16.453 30.768 16.553 31.464 ;
     RECT  15.587 29.28 16.597 29.304 ;
     RECT  15.905 32.832 16.621 34.104 ;
     RECT  16.259 2.352 16.645 5.352 ;
     RECT  16.157 19.104 16.657 19.128 ;
     RECT  15.725 23.28 16.657 25.128 ;
     RECT  16.547 57.168 16.657 57.288 ;
     RECT  16.441 58.752 16.657 58.776 ;
     RECT  16.549 67.104 16.657 67.128 ;
     RECT  16.621 32.832 16.661 34.824 ;
     RECT  14.969 46.752 16.693 55.272 ;
     RECT  16.657 58.704 16.729 58.776 ;
     RECT  16.501 62.448 16.733 62.712 ;
     RECT  16.657 23.28 16.765 25.224 ;
     RECT  15.98 26.4 16.765 27.624 ;
     RECT  16.597 28.704 16.765 29.304 ;
     RECT  16.645 2.352 16.769 5.736 ;
     RECT  16.733 62.448 16.805 62.664 ;
     RECT  14.249 76.896 16.805 76.92 ;
     RECT  16.403 38.688 16.837 39.288 ;
     RECT  16.661 34.176 16.841 34.824 ;
     RECT  16.693 46.752 16.913 55.944 ;
     RECT  16.805 62.544 16.931 62.664 ;
     RECT  16.553 30.864 16.933 31.464 ;
     RECT  16.661 32.832 16.933 33.144 ;
     RECT  16.913 46.752 16.949 54.936 ;
     RECT  16.837 63.84 16.949 63.864 ;
     RECT  16.477 40.368 17.017 45.768 ;
     RECT  16.949 46.752 17.017 54.744 ;
     RECT  15.973 21.552 17.021 21.576 ;
     RECT  16.837 38.592 17.021 39.288 ;
     RECT  16.789 74.688 17.021 74.712 ;
     RECT  16.909 76.368 17.027 76.392 ;
     RECT  15.779 0.144 17.036 1.176 ;
     RECT  16.913 55.92 17.057 55.944 ;
     RECT  16.885 79.632 17.057 79.704 ;
     RECT  16.981 6.288 17.065 6.312 ;
     RECT  16.769 2.352 17.075 5.16 ;
     RECT  16.765 22.992 17.077 25.224 ;
     RECT  16.729 58.704 17.089 59.016 ;
     RECT  16.229 80.928 17.089 81.528 ;
     RECT  16.259 82.656 17.089 82.68 ;
     RECT  16.841 34.176 17.093 34.296 ;
     RECT  16.417 83.808 17.093 83.832 ;
     RECT  16.931 62.592 17.101 62.616 ;
     RECT  17.029 60.192 17.116 60.216 ;
     RECT  16.657 57.168 17.125 57.48 ;
     RECT  16.657 66.72 17.125 67.128 ;
     RECT  17.021 38.688 17.129 39.288 ;
     RECT  17.057 79.68 17.129 79.704 ;
     RECT  17.084 20.208 17.171 20.232 ;
     RECT  17.089 58.704 17.173 59.16 ;
     RECT  16.933 30.864 17.219 33.144 ;
     RECT  17.089 77.52 17.267 78.12 ;
     RECT  16.547 17.04 17.273 17.16 ;
     RECT  17.017 40.368 17.273 54.744 ;
     RECT  17.125 57.168 17.273 57.672 ;
     RECT  16.645 71.808 17.276 71.832 ;
     RECT  17.129 38.928 17.309 39.288 ;
     RECT  17.093 34.272 17.315 34.296 ;
     RECT  17.228 69.36 17.315 69.384 ;
     RECT  16.657 18.864 17.333 19.128 ;
     RECT  16.405 15.936 17.341 15.96 ;
     RECT  17.036 0.144 17.372 1.272 ;
     RECT  17.075 2.352 17.372 3.528 ;
     RECT  17.173 58.704 17.381 59.064 ;
     RECT  17.341 15.648 17.413 15.96 ;
     RECT  17.125 66.72 17.413 67.704 ;
     RECT  17.276 71.808 17.413 72.264 ;
     RECT  17.267 78.096 17.413 78.12 ;
     RECT  16.481 35.808 17.449 37.608 ;
     RECT  17.197 60.336 17.449 60.36 ;
     RECT  17.333 18.864 17.497 19.56 ;
     RECT  17.413 70.704 17.509 70.728 ;
     RECT  17.413 66.576 17.555 67.704 ;
     RECT  17.413 71.808 17.555 72.504 ;
     RECT  17.413 78.096 17.555 78.168 ;
     RECT  17.077 22.176 17.557 25.224 ;
     RECT  16.765 26.4 17.557 29.304 ;
     RECT  17.413 15.648 17.561 16.008 ;
     RECT  17.557 22.176 17.593 29.304 ;
     RECT  17.593 22.176 17.597 29.784 ;
     RECT  17.089 80.928 17.701 82.68 ;
     RECT  17.075 4.56 17.737 5.16 ;
     RECT  17.561 15.648 17.809 15.96 ;
     RECT  17.737 4.56 17.842 5.256 ;
     RECT  17.485 13.536 17.845 13.56 ;
     RECT  17.842 4.56 17.893 5.304 ;
     RECT  17.845 13.536 17.996 13.656 ;
     RECT  17.509 70.704 18.017 70.824 ;
     RECT  17.555 71.808 18.017 72.408 ;
     RECT  17.989 63.84 18.037 63.864 ;
     RECT  18.025 64.848 18.037 64.872 ;
     RECT  17.701 80.928 18.085 82.728 ;
     RECT  17.497 18.864 18.097 19.416 ;
     RECT  17.309 38.976 18.181 39.288 ;
     RECT  17.372 0.144 18.197 3.528 ;
     RECT  17.893 4.56 18.197 6.264 ;
     RECT  17.881 20.544 18.229 20.568 ;
     RECT  17.597 22.176 18.229 24.216 ;
     RECT  18.037 63.84 18.229 64.872 ;
     RECT  18.017 70.704 18.229 72.408 ;
     RECT  18.085 80.16 18.229 82.728 ;
     RECT  16.417 84.912 18.229 86.232 ;
     RECT  17.273 40.368 18.236 54.696 ;
     RECT  17.273 57.168 18.241 57.576 ;
     RECT  17.381 58.704 18.241 58.968 ;
     RECT  18.229 62.88 18.241 64.872 ;
     RECT  18.181 38.976 18.349 39.336 ;
     RECT  18.236 40.368 18.349 55.608 ;
     RECT  18.229 84.768 18.385 86.232 ;
     RECT  18.097 18.528 18.413 19.416 ;
     RECT  17.773 74.592 18.421 74.616 ;
     RECT  17.555 78.096 18.421 78.12 ;
     RECT  18.421 74.112 18.457 74.616 ;
     RECT  18.229 70.656 18.469 72.408 ;
     RECT  18.385 84.432 18.469 86.232 ;
     RECT  17.449 35.328 18.529 37.608 ;
     RECT  18.197 0.144 18.608 6.264 ;
     RECT  17.917 9.072 18.608 9.096 ;
     RECT  18.373 10.848 18.608 10.872 ;
     RECT  17.996 12.912 18.608 13.656 ;
     RECT  17.809 14.784 18.608 15.96 ;
     RECT  17.273 17.04 18.608 17.064 ;
     RECT  18.413 18.24 18.608 19.416 ;
     RECT  18.229 20.544 18.608 24.216 ;
     RECT  17.597 25.536 18.608 29.784 ;
     RECT  17.219 30.864 18.608 32.856 ;
     RECT  18.373 34.128 18.608 34.152 ;
     RECT  18.529 35.184 18.608 37.608 ;
     RECT  18.349 38.976 18.608 55.608 ;
     RECT  18.241 57.168 18.608 58.968 ;
     RECT  17.449 60.336 18.608 60.984 ;
     RECT  18.241 62.64 18.608 64.872 ;
     RECT  17.555 66.672 18.608 67.704 ;
     RECT  18.469 70.032 18.608 72.408 ;
     RECT  18.457 74.112 18.608 74.712 ;
     RECT  18.373 75.792 18.608 75.816 ;
     RECT  18.421 77.52 18.608 78.12 ;
     RECT  18.229 80.16 18.608 83.256 ;
     RECT  18.469 84.384 18.608 86.232 ;
     RECT  18.608 0.144 18.659 86.232 ;
     RECT  18.659 2.148 18.712 86.232 ;
     RECT  18.659 0.144 18.899 1.176 ;
     RECT  18.712 2.256 18.904 86.232 ;
     RECT  18.904 83.664 18.989 86.232 ;
     RECT  18.904 26.784 19.001 29.784 ;
     RECT  18.904 71.856 19.043 74.136 ;
     RECT  19.043 71.856 19.045 72.984 ;
     RECT  18.989 83.664 19.073 86.28 ;
     RECT  19.045 71.856 19.081 71.88 ;
     RECT  18.904 17.04 19.091 17.64 ;
     RECT  18.904 76.944 19.091 78.84 ;
     RECT  18.904 23.376 19.139 25.56 ;
     RECT  19.073 83.664 19.139 86.232 ;
     RECT  18.904 79.824 19.217 80.424 ;
     RECT  18.904 81.408 19.217 82.632 ;
     RECT  18.904 19.68 19.235 19.704 ;
     RECT  18.904 20.976 19.235 21 ;
     RECT  19.091 77.52 19.253 78.84 ;
     RECT  18.904 15.456 19.283 15.96 ;
     RECT  19.001 26.784 19.361 27.384 ;
     RECT  19.361 27.12 19.379 27.384 ;
     RECT  19.001 28.512 19.397 29.784 ;
     RECT  18.904 12.912 19.427 13.512 ;
     RECT  18.904 22.176 19.427 22.2 ;
     RECT  18.904 30.864 19.427 33.96 ;
     RECT  19.045 72.96 19.427 72.984 ;
     RECT  18.904 51.936 19.469 54.744 ;
     RECT  18.904 10.224 19.477 10.872 ;
     RECT  19.217 81.504 19.523 82.632 ;
     RECT  19.139 25.536 19.541 25.56 ;
     RECT  18.904 61.584 19.571 64.056 ;
     RECT  18.904 7.92 19.613 8.904 ;
     RECT  19.477 10.224 19.613 10.776 ;
     RECT  19.091 17.04 19.613 17.112 ;
     RECT  18.904 55.728 19.613 58.968 ;
     RECT  19.571 62.064 19.613 64.056 ;
     RECT  19.139 84.288 19.685 86.232 ;
     RECT  18.899 0.528 19.717 1.176 ;
     RECT  18.904 2.256 19.717 5.64 ;
     RECT  19.613 63.84 19.757 64.056 ;
     RECT  18.904 68.4 19.859 68.424 ;
     RECT  18.904 66.144 19.865 67.368 ;
     RECT  18.904 36.432 19.897 37.656 ;
     RECT  19.253 78.672 19.909 78.84 ;
     RECT  19.217 79.824 19.909 80.376 ;
     RECT  19.469 54.528 19.925 54.744 ;
     RECT  19.613 55.728 19.925 56.664 ;
     RECT  19.283 15.456 19.933 15.72 ;
     RECT  19.757 63.84 19.937 63.864 ;
     RECT  19.253 77.52 19.945 77.544 ;
     RECT  19.925 54.528 19.955 56.664 ;
     RECT  19.865 66.672 19.955 67.368 ;
     RECT  19.717 0.528 19.957 5.64 ;
     RECT  19.897 35.952 19.981 37.656 ;
     RECT  19.613 62.064 20.003 62.76 ;
     RECT  19.613 17.088 20.009 17.112 ;
     RECT  19.981 36.288 20.045 37.656 ;
     RECT  18.904 38.976 20.077 50.952 ;
     RECT  19.469 51.936 20.077 53.112 ;
     RECT  19.933 14.832 20.081 15.72 ;
     RECT  19.957 21.648 20.081 21.672 ;
     RECT  20.003 62.112 20.099 62.76 ;
     RECT  19.955 67.248 20.117 67.368 ;
     RECT  19.957 0.384 20.149 5.64 ;
     RECT  20.045 36.48 20.149 37.656 ;
     RECT  20.101 65.616 20.197 65.64 ;
     RECT  19.613 10.752 20.225 10.776 ;
     RECT  19.427 30.864 20.225 33.048 ;
     RECT  20.099 62.736 20.243 62.76 ;
     RECT  20.197 65.376 20.243 65.64 ;
     RECT  19.139 23.376 20.245 24.216 ;
     RECT  20.149 36.48 20.252 37.704 ;
     RECT  20.077 38.976 20.252 53.112 ;
     RECT  20.245 23.376 20.261 24.312 ;
     RECT  20.243 65.376 20.284 65.4 ;
     RECT  19.613 8.88 20.285 8.904 ;
     RECT  20.149 0.144 20.333 6.312 ;
     RECT  20.221 12 20.387 12.024 ;
     RECT  20.293 76.128 20.387 76.152 ;
     RECT  20.252 36.48 20.435 53.112 ;
     RECT  18.904 69.984 20.435 70.008 ;
     RECT  19.397 28.512 20.483 29.304 ;
     RECT  20.435 36.576 20.483 53.112 ;
     RECT  20.117 67.248 20.483 67.272 ;
     RECT  19.523 81.792 20.485 82.632 ;
     RECT  19.427 13.488 20.501 13.512 ;
     RECT  20.485 81.792 20.513 83.208 ;
     RECT  20.333 0.336 20.531 6.312 ;
     RECT  20.261 23.616 20.54 24.312 ;
     RECT  20.197 25.344 20.54 25.368 ;
     RECT  20.285 8.88 20.545 9.096 ;
     RECT  20.54 23.616 20.581 25.368 ;
     RECT  20.501 13.056 20.585 13.512 ;
     RECT  20.501 74.688 20.585 74.712 ;
     RECT  20.509 18.672 20.593 18.696 ;
     RECT  20.54 6.816 20.627 6.84 ;
     RECT  20.365 64.992 20.627 65.016 ;
     RECT  20.533 72.48 20.629 72.504 ;
     RECT  20.585 13.488 20.653 13.512 ;
     RECT  19.379 27.12 20.689 27.336 ;
     RECT  20.581 23.616 20.693 25.608 ;
     RECT  20.513 82.08 20.693 83.208 ;
     RECT  20.629 72.48 20.716 72.696 ;
     RECT  20.689 26.832 20.725 27.336 ;
     RECT  20.629 17.52 20.729 17.544 ;
     RECT  20.081 15.648 20.764 15.72 ;
     RECT  20.693 83.184 20.765 83.208 ;
     RECT  19.957 60.912 20.797 60.984 ;
     RECT  19.909 78.672 20.797 80.376 ;
     RECT  20.725 26.736 20.833 27.336 ;
     RECT  20.797 72.384 20.915 72.408 ;
     RECT  20.483 28.704 20.917 29.304 ;
     RECT  20.764 15.696 20.945 15.72 ;
     RECT  20.693 23.616 20.963 25.368 ;
     RECT  19.955 54.624 20.965 56.664 ;
     RECT  20.963 25.344 20.981 25.368 ;
     RECT  20.483 38.208 21.011 53.112 ;
     RECT  20.545 8.88 21.059 9.768 ;
     RECT  20.653 13.488 21.059 13.656 ;
     RECT  20.972 64.704 21.059 64.728 ;
     RECT  19.613 58.272 21.085 58.968 ;
     RECT  20.797 60.432 21.085 60.984 ;
     RECT  20.677 6.864 21.097 7.464 ;
     RECT  20.965 54.624 21.101 57.048 ;
     RECT  21.059 13.488 21.107 13.512 ;
     RECT  21.101 54.576 21.107 57.048 ;
     RECT  20.797 78.096 21.133 80.376 ;
     RECT  21.107 56.304 21.161 57 ;
     RECT  21.085 35.328 21.193 35.352 ;
     RECT  20.437 75.84 21.197 75.96 ;
     RECT  21.116 83.232 21.203 83.256 ;
     RECT  21.149 21.12 21.221 21.144 ;
     RECT  21.193 35.328 21.305 35.496 ;
     RECT  21.26 15.888 21.347 16.248 ;
     RECT  21.109 7.776 21.373 7.8 ;
     RECT  21.059 8.88 21.373 8.904 ;
     RECT  21.085 58.272 21.377 60.984 ;
     RECT  21.133 78.096 21.377 80.28 ;
     RECT  21.377 58.272 21.413 59.88 ;
     RECT  21.329 70.848 21.413 70.872 ;
     RECT  21.373 7.776 21.457 8.904 ;
     RECT  21.221 21.12 21.484 21.672 ;
     RECT  21.107 54.576 21.521 55.32 ;
     RECT  21.161 56.352 21.521 57 ;
     RECT  21.011 38.784 21.539 53.112 ;
     RECT  20.693 82.08 21.541 82.104 ;
     RECT  20.833 26.496 21.548 27.336 ;
     RECT  20.917 28.704 21.548 29.64 ;
     RECT  21.521 56.832 21.557 57 ;
     RECT  21.52 61.056 21.581 61.08 ;
     RECT  20.531 0.336 21.587 5.736 ;
     RECT  21.548 26.496 21.589 29.64 ;
     RECT  20.225 30.864 21.589 32.856 ;
     RECT  21.413 58.464 21.593 59.88 ;
     RECT  21.377 79.824 21.593 80.28 ;
     RECT  21.581 61.056 21.635 61.224 ;
     RECT  21.557 56.832 21.665 56.856 ;
     RECT  21.635 61.2 21.665 61.224 ;
     RECT  21.541 81.792 21.665 82.104 ;
     RECT  21.589 18.672 21.676 18.696 ;
     RECT  21.457 7.776 21.683 7.992 ;
     RECT  20.483 36.576 21.683 37.176 ;
     RECT  19.685 84.336 21.685 86.232 ;
     RECT  21.589 26.496 21.701 32.856 ;
     RECT  21.539 38.976 21.733 53.112 ;
     RECT  21.587 0.624 21.769 5.736 ;
     RECT  21.484 21.648 21.773 21.672 ;
     RECT  21.521 54.576 21.773 54.648 ;
     RECT  21.397 76.368 21.809 76.392 ;
     RECT  21.829 69.648 21.841 69.672 ;
     RECT  21.769 74.112 21.853 74.136 ;
     RECT  21.841 69.552 21.877 69.672 ;
     RECT  21.781 75.216 21.917 75.24 ;
     RECT  21.347 15.888 21.923 15.912 ;
     RECT  21.593 79.872 21.923 80.28 ;
     RECT  21.877 69.552 21.961 70.728 ;
     RECT  21.701 26.784 21.985 32.856 ;
     RECT  21.733 38.976 22.021 53.448 ;
     RECT  21.913 66.672 22.069 66.696 ;
     RECT  21.665 82.032 22.069 82.104 ;
     RECT  22.069 66.672 22.07 66.744 ;
     RECT  21.685 83.808 22.093 86.232 ;
     RECT  21.985 26.784 22.115 33.096 ;
     RECT  22.021 38.976 22.115 54.12 ;
     RECT  21.769 0.624 22.129 6.792 ;
     RECT  22.115 38.976 22.133 53.256 ;
     RECT  22.129 0.624 22.141 7.464 ;
     RECT  22.057 9.168 22.141 9.192 ;
     RECT  22.133 38.976 22.156 53.16 ;
     RECT  21.961 69.552 22.163 69.624 ;
     RECT  22.093 83.808 22.177 86.28 ;
     RECT  22.117 74.064 22.205 74.088 ;
     RECT  21.877 12 22.211 12.024 ;
     RECT  22.141 7.44 22.213 7.464 ;
     RECT  22.156 38.976 22.213 53.112 ;
     RECT  21.923 80.256 22.213 80.28 ;
     RECT  20.963 23.616 22.237 24.312 ;
     RECT  22.165 25.632 22.237 25.656 ;
     RECT  21.961 70.704 22.241 70.728 ;
     RECT  22.213 80.256 22.241 81 ;
     RECT  22.165 9.648 22.249 9.672 ;
     RECT  22.213 46.608 22.259 53.112 ;
     RECT  22.163 69.552 22.277 69.576 ;
     RECT  22.115 26.784 22.349 32.856 ;
     RECT  22.069 13.056 22.385 13.08 ;
     RECT  22.069 82.032 22.417 82.488 ;
     RECT  22.417 82.032 22.501 82.68 ;
     RECT  22.177 83.808 22.501 86.232 ;
     RECT  22.259 46.704 22.529 53.112 ;
     RECT  22.309 68.592 22.549 68.904 ;
     RECT  22.349 28.656 22.573 32.856 ;
     RECT  22.501 56.496 22.589 56.52 ;
     RECT  21.377 78.096 22.595 78.648 ;
     RECT  22.517 18.768 22.601 18.792 ;
     RECT  22.241 80.4 22.633 81 ;
     RECT  22.501 82.032 22.633 86.232 ;
     RECT  22.549 68.304 22.637 68.904 ;
     RECT  22.633 80.4 22.637 86.232 ;
     RECT  22.573 28.656 22.643 29.448 ;
     RECT  22.645 8.496 22.669 8.52 ;
     RECT  22.237 23.616 22.68 25.656 ;
     RECT  22.529 46.8 22.739 53.112 ;
     RECT  22.739 49.776 22.745 53.112 ;
     RECT  22.07 66.72 22.745 66.744 ;
     RECT  22.669 7.968 22.753 8.52 ;
     RECT  22.417 76.944 22.787 76.968 ;
     RECT  21.305 35.328 22.789 35.352 ;
     RECT  22.141 0.624 22.813 6.264 ;
     RECT  22.561 22.176 22.813 22.2 ;
     RECT  22.789 34.368 22.813 35.352 ;
     RECT  21.683 36.576 22.813 36.6 ;
     RECT  22.68 23.616 22.817 25.8 ;
     RECT  22.813 21.792 22.837 22.2 ;
     RECT  22.817 23.616 22.837 24.888 ;
     RECT  22.813 34.368 22.837 36.6 ;
     RECT  22.589 56.448 22.849 56.52 ;
     RECT  22.837 34.368 22.853 37.032 ;
     RECT  22.745 49.776 22.853 50.952 ;
     RECT  22.417 75.84 22.883 75.864 ;
     RECT  21.593 58.944 22.885 59.88 ;
     RECT  22.853 34.368 22.889 34.536 ;
     RECT  22.853 35.856 22.897 37.032 ;
     RECT  22.889 34.512 22.931 34.536 ;
     RECT  22.637 80.4 22.979 82.68 ;
     RECT  22.349 26.784 23.029 27.144 ;
     RECT  22.885 58.944 23.125 60.408 ;
     RECT  22.813 0.528 23.173 6.264 ;
     RECT  22.745 52.032 23.173 53.112 ;
     RECT  22.849 56.448 23.173 57.336 ;
     RECT  22.381 71.28 23.221 71.304 ;
     RECT  22.595 78.096 23.281 78.12 ;
     RECT  23.221 71.28 23.365 71.784 ;
     RECT  22.753 8.304 23.389 8.52 ;
     RECT  23.173 0.528 23.413 6.888 ;
     RECT  23.389 74.112 23.461 74.136 ;
     RECT  22.643 28.656 23.509 29.304 ;
     RECT  23.365 71.28 23.533 71.832 ;
     RECT  23.413 0.288 23.557 6.888 ;
     RECT  23.533 71.28 23.557 71.88 ;
     RECT  23.389 8.304 23.605 9.144 ;
     RECT  23.173 52.032 23.653 53.16 ;
     RECT  23.557 71.28 23.653 72.408 ;
     RECT  22.979 81.072 23.653 82.68 ;
     RECT  22.637 83.664 23.653 86.232 ;
     RECT  23.497 79.248 23.677 79.272 ;
     RECT  23.125 58.944 23.701 61.032 ;
     RECT  23.425 66.672 23.713 66.696 ;
     RECT  23.509 28.464 23.893 29.304 ;
     RECT  22.213 38.976 23.893 45.624 ;
     RECT  22.739 46.8 23.893 48.744 ;
     RECT  23.497 76.224 23.893 76.344 ;
     RECT  22.853 49.776 23.929 50.904 ;
     RECT  23.701 58.944 23.929 61.128 ;
     RECT  23.221 62.16 23.929 62.184 ;
     RECT  22.573 30.768 23.965 32.856 ;
     RECT  23.605 8.304 24.001 9.624 ;
     RECT  22.897 36.576 24.001 37.032 ;
     RECT  23.557 0.192 24.008 6.888 ;
     RECT  24.001 8.304 24.008 9.912 ;
     RECT  22.501 11.376 24.008 11.4 ;
     RECT  23.605 14.832 24.008 14.856 ;
     RECT  23.749 20.4 24.008 20.424 ;
     RECT  22.837 21.792 24.008 24.888 ;
     RECT  23.029 26.736 24.008 27.144 ;
     RECT  23.893 28.416 24.008 29.304 ;
     RECT  23.965 30.336 24.008 32.856 ;
     RECT  24.001 36.24 24.008 37.032 ;
     RECT  23.893 38.976 24.008 48.744 ;
     RECT  23.929 49.776 24.008 50.952 ;
     RECT  23.653 52.032 24.008 53.592 ;
     RECT  23.173 55.824 24.008 57.336 ;
     RECT  23.929 58.944 24.008 62.184 ;
     RECT  22.453 63.168 24.008 63.192 ;
     RECT  22.921 64.944 24.008 64.968 ;
     RECT  23.713 66.672 24.008 67.272 ;
     RECT  22.637 68.4 24.008 68.904 ;
     RECT  23.653 70.224 24.008 72.408 ;
     RECT  23.461 73.536 24.008 74.136 ;
     RECT  23.893 75.84 24.008 76.344 ;
     RECT  23.281 77.52 24.008 78.12 ;
     RECT  23.677 79.248 24.008 79.848 ;
     RECT  23.653 81.072 24.008 86.232 ;
     RECT  24.008 0.192 24.304 86.232 ;
     RECT  24.304 84.288 24.397 86.232 ;
     RECT  24.304 19.968 24.401 20.424 ;
     RECT  24.397 84.288 24.401 86.28 ;
     RECT  24.304 25.728 24.419 25.752 ;
     RECT  24.304 75.168 24.419 80.904 ;
     RECT  24.304 22.848 24.437 24.216 ;
     RECT  24.304 0.192 24.444 10.344 ;
     RECT  24.444 0.144 24.445 10.344 ;
     RECT  24.304 60.288 24.467 61.656 ;
     RECT  24.419 75.168 24.467 78.264 ;
     RECT  24.304 70.32 24.473 71.976 ;
     RECT  24.467 75.168 24.481 75.192 ;
     RECT  24.401 85.44 24.481 86.28 ;
     RECT  24.304 55.92 24.509 57.528 ;
     RECT  24.304 43.056 24.545 54.12 ;
     RECT  24.304 66.72 24.553 69 ;
     RECT  24.467 60.288 24.563 61.08 ;
     RECT  24.545 43.104 24.581 54.12 ;
     RECT  24.304 26.784 24.604 32.856 ;
     RECT  24.563 60.288 24.611 60.888 ;
     RECT  24.473 71.952 24.625 71.976 ;
     RECT  24.553 67.824 24.689 69 ;
     RECT  24.509 55.92 24.761 55.944 ;
     RECT  24.304 38.688 24.796 42.072 ;
     RECT  24.445 0.144 24.803 9.24 ;
     RECT  24.604 27.12 24.869 32.856 ;
     RECT  24.803 9.072 24.899 9.24 ;
     RECT  24.304 58.56 24.899 59.304 ;
     RECT  24.803 0.144 24.905 7.992 ;
     RECT  24.304 21.648 24.905 21.816 ;
     RECT  24.467 76.368 24.905 78.264 ;
     RECT  24.899 58.944 24.941 59.304 ;
     RECT  24.689 67.824 24.947 68.184 ;
     RECT  24.401 19.968 24.995 19.992 ;
     RECT  24.509 56.928 25.013 57.432 ;
     RECT  24.304 65.568 25.013 65.592 ;
     RECT  24.553 66.72 25.013 66.744 ;
     RECT  24.905 76.464 25.013 78.264 ;
     RECT  24.796 38.784 25.021 42.072 ;
     RECT  24.419 79.248 25.036 80.904 ;
     RECT  24.445 10.32 25.043 10.344 ;
     RECT  24.581 43.104 25.049 48.744 ;
     RECT  24.304 72.96 25.049 73.416 ;
     RECT  24.899 9.072 25.057 9.192 ;
     RECT  24.304 36.24 25.085 36.264 ;
     RECT  24.473 70.32 25.085 70.824 ;
     RECT  24.304 34.704 25.121 34.968 ;
     RECT  24.581 49.776 25.121 54.12 ;
     RECT  25.121 34.704 25.235 34.728 ;
     RECT  24.304 64.416 25.235 64.44 ;
     RECT  25.049 72.96 25.235 72.984 ;
     RECT  24.905 0.144 25.265 7.8 ;
     RECT  25.265 0.384 25.301 7.8 ;
     RECT  24.947 67.824 25.331 67.848 ;
     RECT  24.304 82.08 25.331 83.256 ;
     RECT  25.331 82.656 25.333 83.256 ;
     RECT  24.401 84.288 25.333 84.456 ;
     RECT  25.021 38.88 25.373 42.072 ;
     RECT  25.301 0.384 25.379 6.888 ;
     RECT  25.013 76.656 25.379 78.264 ;
     RECT  25.333 82.656 25.429 84.456 ;
     RECT  24.481 85.44 25.429 86.232 ;
     RECT  24.905 21.648 25.445 21.672 ;
     RECT  25.405 54.24 25.489 54.264 ;
     RECT  24.437 23.328 25.553 24.216 ;
     RECT  25.036 79.824 25.571 80.904 ;
     RECT  25.333 37.296 25.661 37.32 ;
     RECT  25.085 70.32 25.661 70.728 ;
     RECT  25.549 13.056 25.667 13.08 ;
     RECT  24.869 27.12 25.669 29.304 ;
     RECT  24.611 60.288 25.693 60.696 ;
     RECT  25.429 82.656 25.715 86.232 ;
     RECT  25.715 82.656 25.813 82.68 ;
     RECT  25.049 43.104 25.861 48.696 ;
     RECT  24.941 58.944 25.868 58.968 ;
     RECT  25.379 2.88 25.877 6.888 ;
     RECT  25.373 38.976 25.945 42.072 ;
     RECT  25.861 43.056 25.945 48.696 ;
     RECT  25.868 58.56 25.955 58.968 ;
     RECT  25.693 60 25.985 61.176 ;
     RECT  25.379 77.184 26.017 78.264 ;
     RECT  25.585 54.576 26.053 54.6 ;
     RECT  25.571 80.16 26.053 80.904 ;
     RECT  25.669 26.64 26.057 29.304 ;
     RECT  25.945 38.976 26.089 48.696 ;
     RECT  25.121 49.776 26.089 53.256 ;
     RECT  26.005 12.912 26.093 12.936 ;
     RECT  25.553 23.616 26.125 24.216 ;
     RECT  26.057 26.64 26.129 27.144 ;
     RECT  26.057 28.128 26.129 29.304 ;
     RECT  25.985 60 26.129 60.648 ;
     RECT  26.089 38.976 26.161 53.256 ;
     RECT  25.801 63.12 26.165 63.144 ;
     RECT  26.108 66.624 26.195 66.648 ;
     RECT  25.013 57.264 26.237 57.432 ;
     RECT  26.053 70.128 26.237 70.152 ;
     RECT  26.017 77.184 26.237 78.648 ;
     RECT  26.125 23.616 26.243 24.888 ;
     RECT  25.981 68.928 26.243 68.952 ;
     RECT  26.053 54.576 26.273 54.696 ;
     RECT  26.197 75.12 26.281 75.144 ;
     RECT  26.237 57.312 26.309 57.384 ;
     RECT  26.237 77.472 26.309 78.648 ;
     RECT  25.715 83.808 26.339 86.232 ;
     RECT  26.305 73.488 26.341 73.512 ;
     RECT  26.161 38.976 26.381 53.592 ;
     RECT  26.341 73.488 26.389 74.616 ;
     RECT  25.877 2.88 26.413 4.536 ;
     RECT  25.057 9.072 26.413 9.096 ;
     RECT  26.129 28.704 26.413 29.304 ;
     RECT  24.869 30.816 26.413 32.856 ;
     RECT  26.309 78.048 26.413 78.648 ;
     RECT  25.379 0.384 26.485 1.704 ;
     RECT  26.053 80.16 26.489 81.48 ;
     RECT  26.129 60.048 26.525 60.648 ;
     RECT  26.389 74.064 26.525 74.616 ;
     RECT  26.413 9.072 26.531 9.144 ;
     RECT  26.269 66.144 26.531 66.264 ;
     RECT  26.489 80.16 26.597 80.952 ;
     RECT  26.593 56.16 26.629 56.184 ;
     RECT  26.413 76.368 26.641 76.392 ;
     RECT  26.531 9.072 26.677 9.096 ;
     RECT  26.485 0.096 26.741 1.704 ;
     RECT  26.381 46.704 26.741 53.592 ;
     RECT  26.525 74.064 26.741 74.088 ;
     RECT  26.413 28.704 26.771 32.856 ;
     RECT  26.531 66.24 26.771 66.264 ;
     RECT  26.771 30.864 26.773 32.856 ;
     RECT  26.557 34.848 26.773 34.872 ;
     RECT  26.413 78.048 26.773 78.696 ;
     RECT  26.485 10.8 26.777 10.824 ;
     RECT  26.773 78.048 26.777 79.8 ;
     RECT  26.741 46.704 26.779 53.256 ;
     RECT  26.773 34.416 26.809 34.872 ;
     RECT  26.779 46.704 26.849 53.208 ;
     RECT  26.773 37.584 26.857 37.608 ;
     RECT  26.773 30.864 26.86 33.288 ;
     RECT  26.773 67.776 26.867 67.8 ;
     RECT  26.809 34.32 26.893 34.872 ;
     RECT  26.413 2.784 26.917 4.536 ;
     RECT  26.629 55.776 26.917 56.184 ;
     RECT  25.877 5.712 26.989 6.888 ;
     RECT  25.955 58.704 26.989 58.968 ;
     RECT  26.849 46.704 26.993 53.016 ;
     RECT  26.989 58.512 27.013 58.968 ;
     RECT  25.657 64.944 27.065 64.968 ;
     RECT  26.989 5.712 27.073 7.416 ;
     RECT  26.741 0.144 27.089 1.704 ;
     RECT  26.917 2.784 27.089 4.584 ;
     RECT  26.309 57.36 27.101 57.384 ;
     RECT  26.917 55.296 27.145 56.184 ;
     RECT  27.145 55.536 27.169 56.184 ;
     RECT  26.809 10.848 27.203 11.448 ;
     RECT  27.197 62.16 27.281 62.184 ;
     RECT  26.777 78.576 27.281 79.8 ;
     RECT  27.013 58.512 27.308 59.016 ;
     RECT  27.241 71.808 27.325 71.832 ;
     RECT  27.089 0.144 27.347 4.584 ;
     RECT  26.993 46.704 27.349 50.904 ;
     RECT  27.169 55.536 27.353 56.328 ;
     RECT  26.981 83.76 27.385 83.784 ;
     RECT  26.339 84.912 27.385 86.232 ;
     RECT  27.301 25.392 27.388 25.416 ;
     RECT  27.385 83.76 27.389 86.232 ;
     RECT  26.381 39.504 27.397 45.24 ;
     RECT  27.353 55.68 27.452 56.328 ;
     RECT  27.385 62.544 27.457 62.568 ;
     RECT  26.725 82.08 27.457 82.104 ;
     RECT  27.397 83.184 27.457 83.208 ;
     RECT  27.347 2.208 27.493 4.584 ;
     RECT  27.073 5.712 27.493 6.936 ;
     RECT  27.157 14.448 27.493 14.472 ;
     RECT  27.493 2.208 27.497 6.936 ;
     RECT  27.457 62.544 27.497 63.432 ;
     RECT  27.281 78.672 27.497 79.8 ;
     RECT  27.445 36.912 27.532 36.936 ;
     RECT  27.452 55.68 27.539 56.52 ;
     RECT  26.693 70.08 27.548 70.104 ;
     RECT  27.308 58.032 27.637 59.016 ;
     RECT  26.525 60.048 27.637 60.408 ;
     RECT  27.457 73.536 27.637 73.56 ;
     RECT  26.243 23.616 27.665 24.216 ;
     RECT  27.397 39.408 27.677 45.24 ;
     RECT  26.597 80.928 27.683 80.952 ;
     RECT  27.637 58.032 27.685 60.408 ;
     RECT  27.589 66.72 27.709 66.744 ;
     RECT  27.541 77.424 27.709 77.448 ;
     RECT  27.637 72.96 27.724 73.56 ;
     RECT  27.457 82.08 27.733 83.208 ;
     RECT  27.665 23.616 27.749 24.552 ;
     RECT  27.685 58.032 27.772 61.224 ;
     RECT  27.497 62.64 27.781 63.432 ;
     RECT  27.548 69.984 27.781 70.104 ;
     RECT  27.203 10.848 27.793 11.304 ;
     RECT  27.497 2.304 27.827 6.936 ;
     RECT  26.129 26.784 27.829 27.144 ;
     RECT  27.349 46.608 27.829 50.904 ;
     RECT  27.389 84.336 27.857 86.232 ;
     RECT  27.733 81.504 27.868 83.208 ;
     RECT  26.86 30.864 27.884 33.048 ;
     RECT  27.677 39.792 27.893 45.24 ;
     RECT  27.868 83.136 27.893 83.208 ;
     RECT  27.893 39.792 27.901 42.216 ;
     RECT  27.829 46.368 27.916 50.904 ;
     RECT  26.893 34.8 27.925 34.872 ;
     RECT  27.893 43.632 27.925 45.24 ;
     RECT  27.724 73.536 27.925 73.56 ;
     RECT  26.677 8.496 27.965 9.096 ;
     RECT  27.884 30.864 27.971 33.24 ;
     RECT  27.925 34.752 27.973 34.872 ;
     RECT  27.893 83.184 28.001 83.208 ;
     RECT  27.965 8.496 28.021 8.52 ;
     RECT  27.781 69.984 28.033 70.728 ;
     RECT  27.901 39.792 28.037 42.12 ;
     RECT  27.925 73.536 28.069 74.52 ;
     RECT  27.793 11.28 28.073 11.304 ;
     RECT  27.868 81.504 28.073 82.152 ;
     RECT  27.493 13.632 28.109 14.472 ;
     RECT  27.781 62.64 28.145 63.816 ;
     RECT  27.997 19.008 28.163 19.032 ;
     RECT  27.709 66.72 28.165 66.792 ;
     RECT  28.069 75.792 28.211 75.816 ;
     RECT  28.033 69.984 28.213 70.968 ;
     RECT  27.589 17.616 28.217 17.64 ;
     RECT  27.829 26.688 28.253 27.144 ;
     RECT  28.069 73.536 28.253 74.664 ;
     RECT  28.253 74.112 28.297 74.664 ;
     RECT  28.297 74.496 28.357 74.664 ;
     RECT  27.709 76.944 28.357 77.448 ;
     RECT  28.021 7.968 28.361 8.52 ;
     RECT  28.357 74.496 28.397 75.576 ;
     RECT  28.249 21.648 28.403 21.672 ;
     RECT  27.925 43.632 28.433 45.624 ;
     RECT  27.749 23.616 28.501 24.216 ;
     RECT  27.916 46.752 28.501 50.904 ;
     RECT  26.993 52.032 28.501 53.016 ;
     RECT  28.117 54.528 28.501 54.552 ;
     RECT  28.501 54.048 28.508 54.552 ;
     RECT  27.539 55.68 28.508 56.376 ;
     RECT  28.501 46.752 28.537 53.016 ;
     RECT  28.508 54.048 28.537 56.376 ;
     RECT  28.165 66.144 28.537 66.792 ;
     RECT  27.973 34.704 28.549 34.872 ;
     RECT  28.537 46.752 28.549 56.376 ;
     RECT  27.497 78.672 28.573 78.696 ;
     RECT  28.573 78.624 28.609 78.696 ;
     RECT  28.145 62.64 28.645 63.24 ;
     RECT  26.771 28.704 28.741 29.592 ;
     RECT  27.971 30.864 28.753 33.048 ;
     RECT  28.549 46.752 28.753 56.856 ;
     RECT  27.772 58.032 28.753 60.408 ;
     RECT  28.213 69.552 28.825 70.968 ;
     RECT  28.357 72.24 28.825 72.408 ;
     RECT  28.609 78.528 28.844 78.696 ;
     RECT  28.261 79.824 28.844 79.848 ;
     RECT  28.825 69.552 28.853 72.408 ;
     RECT  27.827 2.304 28.885 6.84 ;
     RECT  28.753 46.752 28.885 60.408 ;
     RECT  28.645 61.536 28.885 63.24 ;
     RECT  28.073 81.792 28.885 82.152 ;
     RECT  28.109 14.448 28.925 14.472 ;
     RECT  27.347 0.144 28.933 1.176 ;
     RECT  28.885 2.208 28.933 6.84 ;
     RECT  28.549 34.704 28.933 35.832 ;
     RECT  28.22 37.584 29.029 37.608 ;
     RECT  28.537 66.144 29.029 67.272 ;
     RECT  28.253 26.832 29.077 27.144 ;
     RECT  28.885 81.792 29.077 82.632 ;
     RECT  28.933 0.144 29.081 6.84 ;
     RECT  28.885 10.224 29.084 10.248 ;
     RECT  28.645 11.424 29.084 11.448 ;
     RECT  29.077 81.792 29.105 83.208 ;
     RECT  28.741 28.704 29.125 29.64 ;
     RECT  28.753 30.768 29.125 33.048 ;
     RECT  28.037 39.792 29.125 39.864 ;
     RECT  29.029 65.52 29.125 67.272 ;
     RECT  28.853 69.024 29.125 72.408 ;
     RECT  29.125 28.704 29.173 33.048 ;
     RECT  28.933 34.08 29.173 35.832 ;
     RECT  28.397 74.64 29.173 75.576 ;
     RECT  28.357 76.944 29.173 77.544 ;
     RECT  29.029 37.584 29.221 38.04 ;
     RECT  29.125 39.216 29.221 39.864 ;
     RECT  28.885 46.752 29.221 63.24 ;
     RECT  28.681 64.368 29.221 64.392 ;
     RECT  27.857 84.816 29.221 86.232 ;
     RECT  29.221 37.584 29.228 39.864 ;
     RECT  29.084 10.224 29.269 11.448 ;
     RECT  28.925 14.448 29.269 15.384 ;
     RECT  28.969 16.56 29.269 16.584 ;
     RECT  29.228 37.392 29.269 39.864 ;
     RECT  29.081 0.432 29.408 6.84 ;
     RECT  28.361 7.968 29.408 7.992 ;
     RECT  29.269 9.792 29.408 11.448 ;
     RECT  29.221 13.056 29.408 13.08 ;
     RECT  29.269 14.448 29.408 16.584 ;
     RECT  28.501 22.8 29.408 24.216 ;
     RECT  28.501 25.296 29.408 25.32 ;
     RECT  29.077 26.832 29.408 27.192 ;
     RECT  29.173 28.704 29.408 35.832 ;
     RECT  29.269 37.152 29.408 39.864 ;
     RECT  28.037 41.136 29.408 42.12 ;
     RECT  28.433 43.632 29.408 45.24 ;
     RECT  29.221 46.752 29.408 64.392 ;
     RECT  29.125 65.52 29.408 72.408 ;
     RECT  29.249 73.488 29.408 73.512 ;
     RECT  29.173 74.64 29.408 77.544 ;
     RECT  28.844 78.528 29.408 79.848 ;
     RECT  29.105 81.456 29.408 83.208 ;
     RECT  29.221 84.288 29.408 86.232 ;
     RECT  29.408 0.432 29.704 86.232 ;
     RECT  29.704 35.76 29.729 35.832 ;
     RECT  29.704 38.736 29.765 39.864 ;
     RECT  29.704 83.712 29.765 86.232 ;
     RECT  29.704 14.352 29.801 14.472 ;
     RECT  29.704 15.744 29.801 15.768 ;
     RECT  29.765 84.96 29.869 86.232 ;
     RECT  29.704 75.936 29.891 78.072 ;
     RECT  29.765 38.736 29.939 39.816 ;
     RECT  29.891 75.936 29.939 76.968 ;
     RECT  29.704 13.056 29.945 13.08 ;
     RECT  29.869 84.96 29.953 86.28 ;
     RECT  29.704 68.4 30.025 69.864 ;
     RECT  29.704 79.776 30.083 81.528 ;
     RECT  29.704 5.712 30.089 7.464 ;
     RECT  30.083 80.832 30.089 81.528 ;
     RECT  29.704 23.52 30.124 25.176 ;
     RECT  29.939 38.832 30.125 39.816 ;
     RECT  29.704 71.808 30.133 72.408 ;
     RECT  29.704 46.752 30.161 54.744 ;
     RECT  30.083 79.776 30.161 79.848 ;
     RECT  29.704 28.704 30.169 34.776 ;
     RECT  29.704 62.736 30.227 62.76 ;
     RECT  29.704 41.184 30.233 45.24 ;
     RECT  29.704 64.944 30.241 64.968 ;
     RECT  30.124 23.52 30.275 24.552 ;
     RECT  30.025 68.688 30.313 69.864 ;
     RECT  30.233 42.768 30.377 45.24 ;
     RECT  30.169 30.336 30.449 34.776 ;
     RECT  30.313 68.688 30.467 69.576 ;
     RECT  30.161 46.752 30.515 52.872 ;
     RECT  30.515 46.752 30.521 48.504 ;
     RECT  30.377 43.632 30.557 45.24 ;
     RECT  30.467 68.688 30.557 68.712 ;
     RECT  30.521 46.752 30.563 48.456 ;
     RECT  30.161 79.824 30.563 79.848 ;
     RECT  30.515 49.584 30.611 52.872 ;
     RECT  30.449 30.336 30.629 34.008 ;
     RECT  29.704 60.288 30.629 60.696 ;
     RECT  30.161 54.576 30.665 54.744 ;
     RECT  30.133 71.808 30.673 71.832 ;
     RECT  29.704 26.832 30.697 27.336 ;
     RECT  29.729 35.808 30.697 35.832 ;
     RECT  29.704 55.872 30.707 58.968 ;
     RECT  30.089 80.928 30.707 81.528 ;
     RECT  29.704 82.608 30.709 82.632 ;
     RECT  29.765 83.712 30.709 83.784 ;
     RECT  30.629 30.72 30.737 34.008 ;
     RECT  30.611 49.872 30.737 52.872 ;
     RECT  30.629 60.384 30.755 60.696 ;
     RECT  30.707 80.928 30.755 80.952 ;
     RECT  29.953 84.96 30.769 86.232 ;
     RECT  30.707 56.592 30.773 58.968 ;
     RECT  30.697 35.712 30.803 35.976 ;
     RECT  29.704 66.72 30.805 66.744 ;
     RECT  30.233 41.184 30.809 41.208 ;
     RECT  29.704 0.432 30.812 4.536 ;
     RECT  30.697 26.784 30.812 27.336 ;
     RECT  30.169 28.704 30.812 29.304 ;
     RECT  30.812 0.384 30.841 4.536 ;
     RECT  29.704 8.544 30.841 8.568 ;
     RECT  29.704 10.272 30.841 10.872 ;
     RECT  30.563 46.752 30.841 48.408 ;
     RECT  30.709 82.608 30.841 83.784 ;
     RECT  30.803 35.712 30.844 35.736 ;
     RECT  30.737 30.768 30.845 34.008 ;
     RECT  30.665 54.576 30.853 54.6 ;
     RECT  29.939 76.32 30.877 76.968 ;
     RECT  30.275 23.616 30.899 24.552 ;
     RECT  30.812 26.784 30.899 29.304 ;
     RECT  30.841 82.56 30.901 83.784 ;
     RECT  30.769 84.816 30.901 86.232 ;
     RECT  30.737 49.872 30.917 50.904 ;
     RECT  30.755 60.672 30.917 60.696 ;
     RECT  30.841 8.496 30.925 8.568 ;
     RECT  29.891 78.048 30.997 78.072 ;
     RECT  30.901 82.56 30.997 86.232 ;
     RECT  29.704 74.544 31.021 74.664 ;
     RECT  30.841 10.224 31.043 10.872 ;
     RECT  30.899 26.784 31.057 27.144 ;
     RECT  30.125 39.792 31.093 39.816 ;
     RECT  30.773 57.456 31.093 58.968 ;
     RECT  31.021 74.544 31.105 75.288 ;
     RECT  30.089 5.712 31.129 6.888 ;
     RECT  30.997 78.048 31.148 78.6 ;
     RECT  31.093 57.456 31.169 59.256 ;
     RECT  30.997 70.656 31.169 70.68 ;
     RECT  31.169 58.944 31.18 59.256 ;
     RECT  31.129 5.712 31.187 7.464 ;
     RECT  30.841 46.704 31.205 48.408 ;
     RECT  31.187 7.44 31.235 7.464 ;
     RECT  31.148 78.048 31.235 78.696 ;
     RECT  31.043 10.32 31.237 10.872 ;
     RECT  29.704 11.952 31.237 11.976 ;
     RECT  29.801 14.352 31.273 14.376 ;
     RECT  30.877 76.32 31.277 77.016 ;
     RECT  31.235 78.048 31.277 78.6 ;
     RECT  31.277 76.944 31.285 77.016 ;
     RECT  31.093 38.832 31.313 39.816 ;
     RECT  31.169 57.456 31.313 57.48 ;
     RECT  31.237 10.32 31.321 11.976 ;
     RECT  31.187 5.712 31.331 6.36 ;
     RECT  31.201 62.16 31.331 62.184 ;
     RECT  30.841 0.144 31.345 4.536 ;
     RECT  30.997 82.032 31.349 86.232 ;
     RECT  31.285 76.944 31.372 77.736 ;
     RECT  30.805 66.72 31.381 67.272 ;
     RECT  31.205 47.28 31.385 48.408 ;
     RECT  31.333 62.736 31.475 62.76 ;
     RECT  31.345 68.4 31.475 68.424 ;
     RECT  31.105 74.544 31.489 74.664 ;
     RECT  31.057 26.736 31.493 27.144 ;
     RECT  30.737 52.032 31.532 52.872 ;
     RECT  31.532 52.032 31.561 53.544 ;
     RECT  31.477 69.504 31.565 69.528 ;
     RECT  31.489 74.496 31.601 74.664 ;
     RECT  31.561 52.032 31.619 53.88 ;
     RECT  31.532 72.192 31.619 72.216 ;
     RECT  30.899 23.616 31.637 23.688 ;
     RECT  31.349 82.224 31.66 86.232 ;
     RECT  31.525 61.584 31.667 61.608 ;
     RECT  31.381 66.672 31.669 67.272 ;
     RECT  31.66 82.608 31.673 86.232 ;
     RECT  31.345 0.144 31.705 4.68 ;
     RECT  31.331 5.712 31.705 6.216 ;
     RECT  31.619 53.856 31.709 53.88 ;
     RECT  31.628 75.936 31.715 75.96 ;
     RECT  31.621 79.824 31.765 79.848 ;
     RECT  31.669 66.672 31.781 67.32 ;
     RECT  31.561 9.168 31.811 9.192 ;
     RECT  31.765 79.824 31.841 80.184 ;
     RECT  31.385 47.616 31.849 48.408 ;
     RECT  30.917 49.872 31.849 50.712 ;
     RECT  31.705 0.144 31.889 6.216 ;
     RECT  31.597 70.128 31.907 70.152 ;
     RECT  31.849 47.616 31.925 50.712 ;
     RECT  31.925 47.616 31.933 50.424 ;
     RECT  31.669 62.832 31.955 62.856 ;
     RECT  31.877 27.312 31.961 27.336 ;
     RECT  31.909 55.104 31.996 55.128 ;
     RECT  30.845 30.864 31.997 34.008 ;
     RECT  30.899 28.704 32.053 29.304 ;
     RECT  31.841 79.776 32.053 80.184 ;
     RECT  32.005 61.2 32.092 61.224 ;
     RECT  31.313 39.456 32.101 39.816 ;
     RECT  30.557 44.592 32.129 45.24 ;
     RECT  32.06 68.928 32.147 68.952 ;
     RECT  32.149 24.48 32.156 24.504 ;
     RECT  32.129 44.448 32.156 45.24 ;
     RECT  32.156 24.48 32.173 25.416 ;
     RECT  32.029 22.8 32.177 23.352 ;
     RECT  31.321 10.32 32.185 10.344 ;
     RECT  32.101 39.456 32.213 40.488 ;
     RECT  32.173 24.48 32.243 26.232 ;
     RECT  31.273 14.304 32.245 14.376 ;
     RECT  31.619 52.032 32.249 52.872 ;
     RECT  31.889 0.432 32.291 6.216 ;
     RECT  32.213 39.456 32.291 39.816 ;
     RECT  32.065 72.384 32.291 72.408 ;
     RECT  32.053 79.776 32.291 80.952 ;
     RECT  32.209 36.048 32.293 36.072 ;
     RECT  31.997 30.864 32.317 33.048 ;
     RECT  31.372 76.944 32.321 77.64 ;
     RECT  32.209 8.496 32.339 8.52 ;
     RECT  32.317 30.816 32.357 33.048 ;
     RECT  32.156 44.448 32.357 45.288 ;
     RECT  32.053 28.704 32.389 29.64 ;
     RECT  32.357 44.928 32.389 45.288 ;
     RECT  32.291 2.352 32.401 6.216 ;
     RECT  32.357 30.816 32.401 32.376 ;
     RECT  32.341 38.016 32.428 38.04 ;
     RECT  32.101 20.736 32.429 20.76 ;
     RECT  31.933 47.616 32.429 48.408 ;
     RECT  32.389 44.928 32.435 45.48 ;
     RECT  32.389 28.464 32.476 29.64 ;
     RECT  32.389 71.04 32.476 71.064 ;
     RECT  32.293 73.776 32.476 73.8 ;
     RECT  32.389 65.568 32.483 65.592 ;
     RECT  32.243 24.48 32.573 24.504 ;
     RECT  32.492 43.776 32.579 43.8 ;
     RECT  32.485 35.952 32.609 35.976 ;
     RECT  32.401 31.44 32.62 32.376 ;
     RECT  32.401 3.216 32.641 6.216 ;
     RECT  32.245 13.488 32.645 14.376 ;
     RECT  32.629 34.08 32.716 34.104 ;
     RECT  31.933 49.584 32.771 50.424 ;
     RECT  32.476 28.704 32.773 29.64 ;
     RECT  31.321 11.952 32.789 11.976 ;
     RECT  32.773 28.704 32.789 30.408 ;
     RECT  32.249 52.032 32.819 52.824 ;
     RECT  32.62 31.44 32.825 32.328 ;
     RECT  32.321 76.944 32.825 76.968 ;
     RECT  32.291 0.432 32.893 1.272 ;
     RECT  31.673 83.184 32.893 86.232 ;
     RECT  32.437 63.216 32.897 63.24 ;
     RECT  32.885 35.808 32.917 35.832 ;
     RECT  32.893 82.608 32.965 86.232 ;
     RECT  32.917 35.52 32.969 35.832 ;
     RECT  32.893 0.192 32.993 1.272 ;
     RECT  32.969 35.52 33.004 35.544 ;
     RECT  32.789 28.944 33.005 30.408 ;
     RECT  32.965 82.032 33.011 86.232 ;
     RECT  32.771 50.112 33.059 50.424 ;
     RECT  32.605 79.68 33.059 79.704 ;
     RECT  33.011 82.032 33.059 82.056 ;
     RECT  32.243 26.208 33.073 26.232 ;
     RECT  33.011 83.184 33.113 86.232 ;
     RECT  32.825 32.304 33.221 32.328 ;
     RECT  32.177 23.328 33.253 23.352 ;
     RECT  33.073 56.64 33.253 56.664 ;
     RECT  33.109 75.024 33.253 75.048 ;
     RECT  32.993 0.144 33.325 1.272 ;
     RECT  32.429 48.384 33.365 48.408 ;
     RECT  33.289 50.688 33.373 50.712 ;
     RECT  32.641 3.216 33.397 6.984 ;
     RECT  33.361 42.864 33.397 42.888 ;
     RECT  32.435 45.216 33.397 45.48 ;
     RECT  33.253 22.896 33.401 23.352 ;
     RECT  33.397 3.216 33.433 7.032 ;
     RECT  33.397 45.216 33.433 45.912 ;
     RECT  33.401 23.28 33.437 23.352 ;
     RECT  33.005 28.944 33.437 28.968 ;
     RECT  33.073 26.208 33.445 26.28 ;
     RECT  33.397 42.768 33.481 42.888 ;
     RECT  33.433 3.216 33.505 7.992 ;
     RECT  33.253 74.496 33.505 75.048 ;
     RECT  32.857 9.168 33.517 9.192 ;
     RECT  33.445 26.208 33.532 26.76 ;
     RECT  31.781 66.672 33.569 67.272 ;
     RECT  33.325 0.144 33.577 1.704 ;
     RECT  33.505 2.784 33.577 7.992 ;
     RECT  33.481 42.864 33.581 42.888 ;
     RECT  33.577 0.144 33.587 7.992 ;
     RECT  32.291 80.928 33.589 80.952 ;
     RECT  33.433 45.216 33.635 46.776 ;
     RECT  33.569 66.672 33.653 67.32 ;
     RECT  33.113 83.664 33.653 86.232 ;
     RECT  33.596 36.912 33.683 36.936 ;
     RECT  33.653 66.672 33.725 67.272 ;
     RECT  32.819 52.032 33.781 52.44 ;
     RECT  32.291 39.792 33.788 39.816 ;
     RECT  33.253 56.448 33.829 56.664 ;
     RECT  33.437 23.28 33.833 23.304 ;
     RECT  33.653 83.664 33.833 83.688 ;
     RECT  33.433 49.008 33.901 49.128 ;
     RECT  32.437 78.048 33.901 78.072 ;
     RECT  33.253 79.824 33.925 79.848 ;
     RECT  33.589 80.928 33.925 81.48 ;
     RECT  33.653 84.72 33.925 86.232 ;
     RECT  33.721 10.944 33.973 10.968 ;
     RECT  33.781 52.032 33.973 52.488 ;
     RECT  33.973 52.032 34.045 52.968 ;
     RECT  33.505 74.496 34.069 75.864 ;
     RECT  33.925 84.72 34.085 86.28 ;
     RECT  34.069 74.496 34.117 76.104 ;
     RECT  33.587 0.144 34.163 7.512 ;
     RECT  33.901 77.76 34.213 78.072 ;
     RECT  33.788 39.072 34.225 39.816 ;
     RECT  34.045 41.088 34.225 41.112 ;
     RECT  33.829 56.208 34.225 56.664 ;
     RECT  33.725 66.672 34.268 67.224 ;
     RECT  34.213 77.76 34.297 78.12 ;
     RECT  33.005 30.384 34.369 30.408 ;
     RECT  33.937 70.656 34.369 70.68 ;
     RECT  34.117 74.112 34.477 76.104 ;
     RECT  34.297 77.76 34.477 78.168 ;
     RECT  33.973 10.848 34.513 10.968 ;
     RECT  34.268 65.712 34.513 67.224 ;
     RECT  33.901 49.008 34.549 49.224 ;
     RECT  34.225 39.072 34.597 41.112 ;
     RECT  34.333 47.28 34.597 47.832 ;
     RECT  34.045 52.032 34.597 53.016 ;
     RECT  34.597 46.752 34.621 47.832 ;
     RECT  34.477 72.144 34.645 72.168 ;
     RECT  31.18 58.944 34.657 58.968 ;
     RECT  34.597 52.032 34.693 53.064 ;
     RECT  34.477 54.096 34.693 54.12 ;
     RECT  33.98 68.832 34.693 68.856 ;
     RECT  34.369 70.128 34.693 70.68 ;
     RECT  34.513 10.32 34.765 10.968 ;
     RECT  34.765 10.08 34.801 10.968 ;
     RECT  34.693 12.576 34.801 12.6 ;
     RECT  34.163 0.192 34.808 7.512 ;
     RECT  33.613 8.688 34.808 8.76 ;
     RECT  34.801 9.888 34.808 10.968 ;
     RECT  34.801 12 34.808 12.6 ;
     RECT  34.765 14.64 34.808 14.664 ;
     RECT  34.693 17.088 34.808 17.112 ;
     RECT  34.309 19.872 34.808 19.896 ;
     RECT  33.532 26.208 34.808 26.232 ;
     RECT  34.765 29.04 34.808 29.064 ;
     RECT  34.369 30.384 34.808 30.456 ;
     RECT  34.364 32.448 34.808 32.472 ;
     RECT  34.045 33.84 34.808 33.864 ;
     RECT  34.597 38.784 34.808 41.112 ;
     RECT  33.635 45.216 34.808 45.432 ;
     RECT  34.621 46.704 34.808 47.832 ;
     RECT  34.549 49.008 34.808 49.56 ;
     RECT  34.225 50.736 34.808 50.76 ;
     RECT  34.693 52.032 34.808 54.12 ;
     RECT  34.225 56.208 34.808 57 ;
     RECT  34.657 58.128 34.808 58.968 ;
     RECT  34.261 62.736 34.808 62.76 ;
     RECT  34.513 65.664 34.808 67.224 ;
     RECT  34.693 68.832 34.808 70.68 ;
     RECT  34.645 72.144 34.808 72.792 ;
     RECT  34.477 74.112 34.808 78.168 ;
     RECT  33.925 79.824 34.808 81.48 ;
     RECT  34.621 82.656 34.808 82.68 ;
     RECT  34.085 84.72 34.808 86.232 ;
     RECT  34.808 0.192 35.104 86.232 ;
     RECT  35.104 0.192 35.219 10.824 ;
     RECT  35.104 12 35.219 12.504 ;
     RECT  35.219 9.072 35.245 9.768 ;
     RECT  35.219 0.192 35.267 7.992 ;
     RECT  35.104 14.544 35.267 14.808 ;
     RECT  35.104 17.088 35.273 17.544 ;
     RECT  35.104 29.04 35.273 29.064 ;
     RECT  35.104 49.104 35.273 49.224 ;
     RECT  35.104 58.656 35.273 58.776 ;
     RECT  35.267 14.784 35.309 14.808 ;
     RECT  35.104 25.104 35.309 25.128 ;
     RECT  35.104 21.024 35.315 22.008 ;
     RECT  35.104 32.352 35.315 32.856 ;
     RECT  35.104 80.976 35.315 82.68 ;
     RECT  35.104 33.84 35.317 38.808 ;
     RECT  35.273 49.104 35.345 49.128 ;
     RECT  35.317 35.328 35.356 38.808 ;
     RECT  35.267 0.192 35.363 5.256 ;
     RECT  35.267 6.288 35.363 7.992 ;
     RECT  35.104 30.384 35.381 30.792 ;
     RECT  35.104 83.76 35.381 86.232 ;
     RECT  35.104 51.264 35.389 53.592 ;
     RECT  35.104 74.16 35.411 75.672 ;
     RECT  35.104 45.072 35.417 46.776 ;
     RECT  35.104 56.976 35.417 57.576 ;
     RECT  35.273 58.656 35.461 58.728 ;
     RECT  35.104 42.72 35.507 42.744 ;
     RECT  35.411 74.4 35.507 75.672 ;
     RECT  35.315 80.976 35.507 81 ;
     RECT  35.389 51.264 35.533 51.288 ;
     RECT  35.245 9.072 35.555 9.72 ;
     RECT  35.417 56.976 35.569 57 ;
     RECT  35.273 17.088 35.597 17.112 ;
     RECT  35.381 30.432 35.597 30.792 ;
     RECT  35.315 32.832 35.597 32.856 ;
     RECT  35.104 39.792 35.597 40.152 ;
     RECT  35.104 72.144 35.597 72.168 ;
     RECT  35.104 76.944 35.605 78.552 ;
     RECT  35.417 45.216 35.633 46.776 ;
     RECT  35.104 64.8 35.633 66.6 ;
     RECT  35.219 12 35.651 12.024 ;
     RECT  35.363 6.864 35.705 7.992 ;
     RECT  35.705 6.864 35.747 6.888 ;
     RECT  35.363 0.192 35.773 5.16 ;
     RECT  35.381 84.384 35.777 86.232 ;
     RECT  35.555 9.696 35.795 9.72 ;
     RECT  35.605 76.944 35.795 76.968 ;
     RECT  35.315 82.032 35.813 82.68 ;
     RECT  35.633 66.48 35.836 66.6 ;
     RECT  35.705 7.968 35.843 7.992 ;
     RECT  35.597 30.768 35.857 30.792 ;
     RECT  35.104 70.608 35.885 70.632 ;
     RECT  35.356 35.328 35.891 35.448 ;
     RECT  35.104 55.872 35.891 55.896 ;
     RECT  35.836 66.576 35.891 66.6 ;
     RECT  35.605 78.048 35.891 78.552 ;
     RECT  35.219 10.8 35.893 10.824 ;
     RECT  35.773 0.144 35.921 5.16 ;
     RECT  35.777 84.384 35.921 84.6 ;
     RECT  35.921 2.256 35.939 5.16 ;
     RECT  35.356 36.48 35.957 38.808 ;
     RECT  35.317 33.84 35.987 34.2 ;
     RECT  35.389 52.56 35.987 53.592 ;
     RECT  35.987 52.656 35.993 53.592 ;
     RECT  35.987 33.84 36.029 33.864 ;
     RECT  35.891 35.328 36.029 35.352 ;
     RECT  35.633 45.888 36.085 46.776 ;
     RECT  35.104 47.952 36.085 47.976 ;
     RECT  35.921 0.144 36.131 1.176 ;
     RECT  36.085 45.888 36.131 47.976 ;
     RECT  35.104 61.584 36.131 61.608 ;
     RECT  35.957 37.44 36.137 38.808 ;
     RECT  36.131 45.888 36.172 47.496 ;
     RECT  35.939 2.352 36.173 5.16 ;
     RECT  35.104 68.352 36.173 68.376 ;
     RECT  35.993 53.568 36.227 53.592 ;
     RECT  35.597 39.792 36.229 39.816 ;
     RECT  35.891 78.432 36.277 78.552 ;
     RECT  35.507 74.736 36.281 75.672 ;
     RECT  36.133 66.72 36.317 67.272 ;
     RECT  36.131 0.288 36.323 1.176 ;
     RECT  35.104 79.824 36.325 79.848 ;
     RECT  36.173 5.136 36.349 5.16 ;
     RECT  36.281 74.736 36.353 74.856 ;
     RECT  35.104 62.592 36.371 63.336 ;
     RECT  36.313 25.68 36.397 25.704 ;
     RECT  36.325 79.824 36.421 80.424 ;
     RECT  36.341 76.368 36.425 76.392 ;
     RECT  36.349 5.136 36.433 5.736 ;
     RECT  36.173 2.352 36.461 4.104 ;
     RECT  36.325 43.872 36.461 43.896 ;
     RECT  36.353 74.832 36.461 74.856 ;
     RECT  35.813 82.56 36.461 82.68 ;
     RECT  36.38 60.384 36.467 60.408 ;
     RECT  36.317 67.248 36.469 67.272 ;
     RECT  36.421 79.632 36.497 80.424 ;
     RECT  36.421 55.296 36.505 55.32 ;
     RECT  36.137 37.44 36.515 37.464 ;
     RECT  36.277 50.976 36.517 51 ;
     RECT  36.133 58.56 36.565 58.584 ;
     RECT  36.517 50.448 36.604 51.528 ;
     RECT  35.633 64.8 36.605 64.824 ;
     RECT  35.777 85.92 36.629 86.232 ;
     RECT  36.172 45.888 36.637 46.728 ;
     RECT  36.181 11.04 36.641 11.064 ;
     RECT  36.373 53.952 36.641 53.976 ;
     RECT  36.461 2.352 36.652 3.528 ;
     RECT  36.277 78.432 36.661 78.648 ;
     RECT  36.497 79.632 36.661 80.376 ;
     RECT  36.652 3.504 36.677 3.528 ;
     RECT  36.565 58.56 36.709 59.304 ;
     RECT  36.461 82.608 36.709 82.68 ;
     RECT  36.629 85.92 36.713 86.28 ;
     RECT  36.604 50.448 36.745 51.336 ;
     RECT  36.745 50.112 36.757 51.336 ;
     RECT  36.757 50.112 36.785 50.472 ;
     RECT  36.709 58.224 36.793 59.304 ;
     RECT  36.433 5.136 36.803 5.688 ;
     RECT  36.637 44.976 36.812 46.728 ;
     RECT  36.469 42.096 36.821 42.12 ;
     RECT  36.785 50.112 36.829 50.136 ;
     RECT  36.652 2.352 36.851 2.52 ;
     RECT  36.757 81.456 36.853 81.48 ;
     RECT  36.323 0.336 36.889 1.176 ;
     RECT  36.851 2.352 36.893 2.424 ;
     RECT  36.812 44.88 36.899 46.728 ;
     RECT  36.709 82.608 36.901 83.064 ;
     RECT  35.921 84.384 36.901 84.408 ;
     RECT  36.853 81.36 36.917 81.48 ;
     RECT  36.229 39.12 36.925 39.816 ;
     RECT  36.893 2.352 36.947 2.376 ;
     RECT  36.899 44.976 36.965 46.728 ;
     RECT  36.889 36.432 36.973 36.456 ;
     RECT  36.965 46.704 37.001 46.728 ;
     RECT  36.925 39.12 37.009 39.864 ;
     RECT  36.949 42.72 37.036 42.744 ;
     RECT  36.917 81.36 37.039 81.528 ;
     RECT  36.901 82.608 37.045 84.408 ;
     RECT  36.889 0.336 37.069 1.272 ;
     RECT  37.045 82.608 37.073 84.84 ;
     RECT  37.039 81.36 37.109 81.48 ;
     RECT  37.073 82.608 37.109 82.632 ;
     RECT  36.965 44.976 37.145 45 ;
     RECT  37.009 39.12 37.189 39.816 ;
     RECT  37.073 84.336 37.237 84.84 ;
     RECT  36.713 85.92 37.237 86.232 ;
     RECT  36.949 73.536 37.253 73.56 ;
     RECT  37.189 38.928 37.276 39.816 ;
     RECT  36.565 6.816 37.285 6.84 ;
     RECT  36.793 58.704 37.289 59.304 ;
     RECT  37.069 0.336 37.331 1.704 ;
     RECT  36.661 78.432 37.333 80.376 ;
     RECT  36.385 56.4 37.357 56.424 ;
     RECT  37.105 13.104 37.379 13.128 ;
     RECT  37.285 6.816 37.475 6.888 ;
     RECT  36.371 62.592 37.501 62.616 ;
     RECT  37.237 76.56 37.505 76.584 ;
     RECT  37.213 10.8 37.523 10.824 ;
     RECT  37.289 58.752 37.573 59.304 ;
     RECT  37.285 9.696 37.577 9.72 ;
     RECT  37.493 53.52 37.577 53.544 ;
     RECT  37.501 62.592 37.613 62.712 ;
     RECT  37.333 78.048 37.613 80.376 ;
     RECT  36.469 67.248 37.621 67.512 ;
     RECT  37.573 58.752 37.657 59.4 ;
     RECT  37.613 79.248 37.685 80.376 ;
     RECT  37.331 0.384 37.715 1.704 ;
     RECT  37.357 55.92 37.753 56.424 ;
     RECT  37.532 5.712 37.757 6.264 ;
     RECT  37.621 67.248 37.757 68.088 ;
     RECT  37.757 67.248 37.789 67.32 ;
     RECT  37.645 18.768 37.793 18.792 ;
     RECT  37.657 58.752 37.793 59.304 ;
     RECT  37.753 55.296 37.813 56.424 ;
     RECT  37.772 57.552 37.813 57.576 ;
     RECT  37.813 55.296 37.859 57.576 ;
     RECT  36.805 25.344 37.901 25.368 ;
     RECT  37.285 4.56 37.907 4.584 ;
     RECT  37.789 66.672 37.937 67.32 ;
     RECT  37.859 55.296 37.955 56.76 ;
     RECT  37.957 49.728 37.969 49.752 ;
     RECT  37.889 12 37.973 12.024 ;
     RECT  37.861 47.856 37.973 47.88 ;
     RECT  37.969 49.008 38.044 49.752 ;
     RECT  38.044 49.008 38.053 49.032 ;
     RECT  37.573 82.464 38.053 82.488 ;
     RECT  38.053 82.08 38.077 82.488 ;
     RECT  37.997 26.736 38.081 26.76 ;
     RECT  37.276 39.792 38.081 39.816 ;
     RECT  37.645 10.848 38.099 10.872 ;
     RECT  37.955 55.44 38.099 56.76 ;
     RECT  37.793 58.752 38.117 58.776 ;
     RECT  37.781 3.408 38.185 3.432 ;
     RECT  37.669 64.416 38.185 64.44 ;
     RECT  37.573 31.872 38.189 31.896 ;
     RECT  37.669 38.16 38.189 38.184 ;
     RECT  37.765 78 38.189 78.024 ;
     RECT  37.757 6.192 38.195 6.264 ;
     RECT  38.077 82.08 38.225 82.632 ;
     RECT  38.149 37.008 38.233 37.032 ;
     RECT  37.937 67.248 38.233 67.32 ;
     RECT  38.156 44.88 38.243 44.904 ;
     RECT  37.715 0.384 38.293 1.32 ;
     RECT  38.185 2.976 38.293 3.432 ;
     RECT  38.225 82.56 38.297 82.632 ;
     RECT  38.245 51.936 38.333 51.96 ;
     RECT  38.357 34.176 38.441 34.2 ;
     RECT  38.099 56.736 38.513 56.76 ;
     RECT  37.685 79.824 38.533 80.376 ;
     RECT  38.233 67.248 38.549 67.272 ;
     RECT  37.237 84.336 38.617 86.232 ;
     RECT  38.257 70.656 38.621 70.68 ;
     RECT  38.293 0.144 38.701 1.32 ;
     RECT  38.185 63.84 38.701 64.44 ;
     RECT  38.195 6.192 38.723 6.216 ;
     RECT  38.701 64.272 38.761 64.44 ;
     RECT  38.533 79.824 38.765 80.712 ;
     RECT  38.617 83.712 38.765 86.232 ;
     RECT  38.617 7.44 38.771 7.464 ;
     RECT  38.297 82.608 38.821 82.632 ;
     RECT  38.765 83.712 38.821 83.784 ;
     RECT  38.629 42.144 38.837 42.168 ;
     RECT  38.761 64.272 38.837 64.488 ;
     RECT  38.837 64.464 38.845 64.488 ;
     RECT  37.613 62.592 38.865 62.616 ;
     RECT  38.821 53.52 38.908 53.544 ;
     RECT  38.701 0.144 38.909 1.224 ;
     RECT  38.833 8.544 38.917 8.568 ;
     RECT  37.621 60.672 38.945 60.696 ;
     RECT  38.293 2.88 39.005 3.432 ;
     RECT  38.965 78.672 39.013 78.696 ;
     RECT  39.005 2.88 39.089 3.528 ;
     RECT  38.909 0.528 39.107 1.224 ;
     RECT  38.821 82.608 39.125 83.784 ;
     RECT  39.089 2.88 39.161 3 ;
     RECT  38.765 80.256 39.161 80.376 ;
     RECT  38.765 84.912 39.161 86.232 ;
     RECT  39.161 2.976 39.203 3 ;
     RECT  39.161 84.912 39.233 86.184 ;
     RECT  39.107 0.528 39.269 1.176 ;
     RECT  39.233 84.912 39.269 85.56 ;
     RECT  39.269 0.528 39.299 0.552 ;
     RECT  39.269 85.536 39.347 85.56 ;
     RECT  39.452 74.64 39.473 74.664 ;
     RECT  39.349 55.536 40.208 55.56 ;
     RECT  39.473 74.544 40.208 74.664 ;
     RECT  39.013 78.672 40.208 79.224 ;
     RECT  39.161 80.304 40.208 80.376 ;
     RECT  39.125 83.184 40.208 83.208 ;
     RECT  40.208 2.148 40.312 84.252 ;
     RECT  40.312 2.418 40.504 83.982 ;
     RECT  45.608 2.148 45.712 84.252 ;
     RECT  45.712 2.418 45.904 83.982 ;
    LAYER M5 ;
     RECT  13.344 0.016 39.288 0.181 ;
     RECT  13.104 0.181 39.288 0.563 ;
     RECT  13.104 0.563 39.24 1.187 ;
     RECT  13.104 1.187 39.192 2.207 ;
     RECT  2.4 2.137 2.52 2.407 ;
     RECT  7.8 2.137 7.92 2.407 ;
     RECT  40.2 2.137 40.32 2.407 ;
     RECT  45.6 2.137 45.72 2.407 ;
     RECT  13.056 2.207 39.192 3.011 ;
     RECT  13.056 3.011 39.048 3.385 ;
     RECT  13.104 3.385 39.048 3.539 ;
     RECT  13.104 3.539 38.904 5.113 ;
     RECT  13.104 5.113 15 5.315 ;
     RECT  16.176 5.113 38.904 6.323 ;
     RECT  13.2 5.315 15 6.815 ;
     RECT  16.176 6.323 16.2 6.815 ;
     RECT  17.52 6.323 38.904 6.947 ;
     RECT  13.2 6.815 16.2 7.417 ;
     RECT  28.032 6.947 38.904 7.523 ;
     RECT  13.2 7.417 15 8.437 ;
     RECT  17.52 6.947 27.048 8.485 ;
     RECT  28.032 7.523 33.816 8.485 ;
     RECT  34.8 7.523 38.904 8.579 ;
     RECT  17.52 8.485 33.816 8.687 ;
     RECT  34.8 8.579 38.088 8.687 ;
     RECT  17.52 8.687 38.088 8.771 ;
     RECT  13.104 8.437 15 9.119 ;
     RECT  16.176 7.417 16.2 9.119 ;
     RECT  13.104 9.119 16.2 9.203 ;
     RECT  13.104 9.203 15 9.619 ;
     RECT  12.192 9.619 15 9.707 ;
     RECT  17.52 8.771 33.816 10.271 ;
     RECT  34.8 8.771 38.088 10.271 ;
     RECT  11.52 10.195 11.544 10.283 ;
     RECT  17.52 10.271 38.088 10.883 ;
     RECT  17.52 10.883 37.944 11.017 ;
     RECT  11.52 11.637 11.544 11.725 ;
     RECT  13.008 9.707 15 11.941 ;
     RECT  34.8 11.017 37.944 12.035 ;
     RECT  17.52 11.017 33.816 12.527 ;
     RECT  34.8 12.035 37.368 12.527 ;
     RECT  17.52 12.527 37.368 12.611 ;
     RECT  34.8 12.611 37.368 13.139 ;
     RECT  16.176 9.203 16.2 13.173 ;
     RECT  16.176 13.173 16.296 13.285 ;
     RECT  15.984 13.285 16.296 13.331 ;
     RECT  15.984 13.331 16.2 13.715 ;
     RECT  12.912 11.941 15 13.861 ;
     RECT  12.528 13.861 15 14.149 ;
     RECT  16.08 13.715 16.2 14.773 ;
     RECT  12.528 14.149 15.096 14.915 ;
     RECT  17.52 12.611 33.816 15.637 ;
     RECT  16.08 14.773 16.344 15.925 ;
     RECT  17.472 15.637 33.816 15.925 ;
     RECT  12.624 14.915 15.096 16.261 ;
     RECT  12.576 16.261 15.096 16.981 ;
     RECT  16.08 15.925 33.816 16.981 ;
     RECT  12.576 16.981 33.816 17.077 ;
     RECT  34.8 13.139 36.744 17.077 ;
     RECT  11.184 18.229 11.208 18.419 ;
     RECT  11.04 20.213 11.064 20.301 ;
     RECT  7.8 2.407 8.112 21.139 ;
     RECT  7.8 21.139 8.856 21.227 ;
     RECT  9.648 21.621 9.672 21.709 ;
     RECT  2.4 2.407 2.712 22.789 ;
     RECT  12.576 17.077 36.744 23.029 ;
     RECT  12.528 23.029 36.744 23.123 ;
     RECT  2.304 22.789 2.712 23.269 ;
     RECT  4.368 22.995 4.392 23.339 ;
     RECT  2.304 23.269 2.856 23.353 ;
     RECT  4.416 23.893 4.44 24.805 ;
     RECT  4.032 24.805 4.44 24.939 ;
     RECT  2.304 23.353 2.712 25.077 ;
     RECT  0.144 23.941 0.168 25.093 ;
     RECT  2.304 25.077 3.432 25.165 ;
     RECT  12.576 23.123 36.744 25.333 ;
     RECT  0.144 25.093 0.504 26.005 ;
     RECT  2.304 25.165 2.712 26.627 ;
     RECT  2.4 26.627 2.712 26.643 ;
     RECT  4.416 24.939 4.44 26.643 ;
     RECT  2.4 26.643 4.44 26.731 ;
     RECT  0.144 26.005 0.552 27.349 ;
     RECT  4.416 26.731 4.44 27.733 ;
     RECT  4.32 27.733 4.44 27.819 ;
     RECT  0.144 27.349 1.416 27.925 ;
     RECT  2.4 26.731 2.712 27.925 ;
     RECT  4.416 27.819 4.44 28.069 ;
     RECT  9.648 28.341 9.672 28.429 ;
     RECT  4.416 28.069 4.488 28.499 ;
     RECT  7.8 21.227 8.112 29.365 ;
     RECT  7.68 29.365 8.112 29.507 ;
     RECT  0.096 27.925 2.712 30.133 ;
     RECT  0.048 30.133 2.712 30.421 ;
     RECT  0.048 30.421 3.24 30.507 ;
     RECT  9.408 30.453 9.432 30.563 ;
     RECT  10.464 30.675 10.488 30.763 ;
     RECT  4.416 28.499 4.44 30.997 ;
     RECT  4.416 30.997 4.536 31.083 ;
     RECT  12.576 25.333 36.84 31.861 ;
     RECT  38.016 26.725 38.04 31.861 ;
     RECT  0.048 30.507 2.856 32.427 ;
     RECT  0.096 32.427 2.856 32.491 ;
     RECT  7.8 29.507 8.112 32.543 ;
     RECT  9.504 32.629 9.528 32.723 ;
     RECT  7.8 32.543 8.232 33.097 ;
     RECT  4.416 31.083 4.44 33.363 ;
     RECT  4.416 33.363 5.304 33.451 ;
     RECT  1.968 32.491 2.856 33.939 ;
     RECT  7.8 33.097 8.112 33.973 ;
     RECT  1.968 33.939 2.904 34.027 ;
     RECT  7.296 33.973 8.112 34.067 ;
     RECT  12.576 31.861 38.04 34.165 ;
     RECT  4.416 33.451 4.44 35.653 ;
     RECT  4.416 35.653 4.584 35.755 ;
     RECT  0.096 32.491 0.84 36.037 ;
     RECT  1.968 34.027 2.856 36.037 ;
     RECT  0.096 36.037 2.856 36.275 ;
     RECT  0.096 36.275 0.552 36.323 ;
     RECT  1.968 36.275 2.856 36.515 ;
     RECT  0.096 36.323 0.456 36.981 ;
     RECT  0.048 36.981 0.456 37.035 ;
     RECT  0.048 37.035 0.408 38.437 ;
     RECT  0.048 38.437 0.6 38.581 ;
     RECT  0.048 38.581 1.032 38.723 ;
     RECT  2.4 36.515 2.856 38.965 ;
     RECT  2.4 38.965 2.952 39.155 ;
     RECT  0.048 38.723 0.84 40.181 ;
     RECT  2.4 39.155 2.856 40.549 ;
     RECT  4.416 35.755 4.44 40.549 ;
     RECT  12.576 34.165 38.424 40.597 ;
     RECT  2.4 40.549 4.44 41.029 ;
     RECT  2.4 41.029 5.112 41.131 ;
     RECT  10.848 40.549 10.872 41.131 ;
     RECT  2.4 41.131 4.584 41.209 ;
     RECT  2.4 41.209 4.44 41.323 ;
     RECT  9.12 41.077 9.144 41.651 ;
     RECT  12.24 40.597 38.424 42.133 ;
     RECT  4.416 41.323 4.44 44.149 ;
     RECT  4.416 44.149 5.16 44.233 ;
     RECT  9.12 44.053 9.144 44.771 ;
     RECT  0.048 40.181 1.416 45.493 ;
     RECT  2.4 41.323 2.856 45.493 ;
     RECT  0.048 45.493 2.856 46.059 ;
     RECT  0.048 46.059 1.416 47.157 ;
     RECT  2.4 46.059 2.856 47.157 ;
     RECT  0.048 47.157 2.856 49.139 ;
     RECT  0.048 49.139 2.808 49.465 ;
     RECT  12.24 42.133 38.664 50.667 ;
     RECT  4.416 44.233 4.44 50.997 ;
     RECT  0.048 49.465 2.712 51.011 ;
     RECT  0.048 51.011 0.84 51.107 ;
     RECT  4.032 50.997 4.44 51.107 ;
     RECT  12.528 50.667 38.664 51.347 ;
     RECT  5.52 50.485 5.544 51.395 ;
     RECT  1.968 51.011 2.712 51.491 ;
     RECT  0.048 51.107 0.6 52.075 ;
     RECT  0.144 52.075 0.6 52.267 ;
     RECT  10.944 52.463 10.968 52.547 ;
     RECT  13.2 51.347 38.664 52.835 ;
     RECT  7.8 34.067 8.112 52.947 ;
     RECT  2.4 51.491 2.712 52.981 ;
     RECT  7.8 52.947 8.472 53.035 ;
     RECT  2.4 52.981 2.856 53.065 ;
     RECT  5.712 52.981 5.736 53.065 ;
     RECT  13.2 52.835 31.896 53.395 ;
     RECT  0.144 52.267 0.552 53.483 ;
     RECT  12.864 53.395 31.896 53.483 ;
     RECT  33.264 52.835 38.664 53.493 ;
     RECT  10.848 52.549 10.872 53.555 ;
     RECT  0.192 53.483 0.552 53.557 ;
     RECT  33.264 53.493 38.856 53.581 ;
     RECT  0.192 53.557 0.6 53.611 ;
     RECT  0.24 53.611 0.6 53.641 ;
     RECT  7.8 53.035 8.112 54.069 ;
     RECT  0.24 53.641 0.552 54.083 ;
     RECT  6.912 54.069 8.112 54.157 ;
     RECT  0.24 54.083 0.504 54.581 ;
     RECT  0.144 54.581 0.504 54.659 ;
     RECT  0.144 54.659 0.168 54.669 ;
     RECT  13.2 53.483 31.896 54.867 ;
     RECT  12.576 54.867 31.896 55.029 ;
     RECT  2.4 53.065 2.712 55.045 ;
     RECT  4.416 51.107 4.44 55.045 ;
     RECT  12.576 55.029 31.944 55.093 ;
     RECT  12.528 55.093 31.944 55.139 ;
     RECT  2.4 55.045 3.336 55.147 ;
     RECT  4.416 55.045 4.536 55.147 ;
     RECT  5.856 55.045 5.88 55.147 ;
     RECT  7.8 54.157 8.112 55.349 ;
     RECT  10.704 55.349 10.728 55.381 ;
     RECT  7.8 55.349 8.328 55.437 ;
     RECT  10.704 55.381 10.824 55.437 ;
     RECT  7.8 55.437 8.112 55.443 ;
     RECT  10.8 55.437 10.824 55.467 ;
     RECT  33.264 53.581 38.664 55.477 ;
     RECT  40.2 2.407 40.512 55.477 ;
     RECT  33.264 55.477 40.512 55.571 ;
     RECT  0.288 55.765 0.312 55.861 ;
     RECT  0.144 55.861 0.312 55.907 ;
     RECT  12.528 55.139 31.896 55.955 ;
     RECT  9.312 55.989 9.336 56.077 ;
     RECT  0.144 55.907 0.168 56.099 ;
     RECT  6.912 55.443 8.112 56.341 ;
     RECT  5.664 56.275 5.688 56.363 ;
     RECT  6.864 56.341 8.112 56.427 ;
     RECT  33.264 55.571 38.664 56.483 ;
     RECT  4.416 55.147 4.44 56.677 ;
     RECT  12.048 57.013 12.072 57.253 ;
     RECT  13.2 55.955 31.896 57.253 ;
     RECT  4.416 56.677 5.016 57.323 ;
     RECT  12.048 57.253 31.896 57.323 ;
     RECT  4.416 57.323 4.536 57.515 ;
     RECT  7.8 56.427 8.112 57.973 ;
     RECT  6.72 57.973 8.112 58.057 ;
     RECT  2.4 55.147 2.712 58.079 ;
     RECT  7.68 58.057 8.112 58.115 ;
     RECT  2.4 58.079 2.856 58.163 ;
     RECT  12.288 57.323 31.896 58.607 ;
     RECT  11.424 58.607 31.896 58.691 ;
     RECT  9.216 58.613 9.24 58.701 ;
     RECT  10.8 58.933 10.824 59.017 ;
     RECT  11.808 58.691 31.896 59.027 ;
     RECT  33.312 56.483 38.664 59.315 ;
     RECT  37.584 59.315 38.664 59.411 ;
     RECT  4.416 57.515 4.44 59.637 ;
     RECT  7.8 58.115 8.112 59.701 ;
     RECT  4.416 59.637 4.776 59.731 ;
     RECT  6.864 59.701 8.112 59.795 ;
     RECT  4.416 59.731 5.016 59.819 ;
     RECT  12.48 59.027 31.896 60.035 ;
     RECT  6.336 60.021 6.36 60.109 ;
     RECT  7.8 59.795 8.112 60.341 ;
     RECT  33.312 59.315 36.408 60.341 ;
     RECT  7.8 60.341 8.568 60.429 ;
     RECT  33.312 60.341 36.456 60.429 ;
     RECT  37.632 59.411 38.664 60.707 ;
     RECT  7.8 60.429 8.112 61.189 ;
     RECT  13.2 60.035 31.896 61.189 ;
     RECT  6.864 61.189 8.112 61.291 ;
     RECT  13.2 61.189 32.04 61.291 ;
     RECT  2.4 58.163 2.712 61.365 ;
     RECT  2.4 61.365 2.808 61.453 ;
     RECT  4.416 59.819 4.44 61.813 ;
     RECT  4.416 61.813 5.208 62.195 ;
     RECT  7.8 61.291 8.112 62.581 ;
     RECT  13.2 61.291 31.896 62.581 ;
     RECT  37.68 60.707 38.664 62.581 ;
     RECT  4.416 62.195 5.112 62.629 ;
     RECT  7.8 62.581 8.472 62.739 ;
     RECT  4.224 62.629 5.112 62.763 ;
     RECT  37.68 62.581 38.808 62.763 ;
     RECT  7.8 62.739 8.568 62.773 ;
     RECT  12.24 62.581 31.896 62.773 ;
     RECT  11.424 62.773 31.896 62.803 ;
     RECT  4.416 62.763 5.112 62.827 ;
     RECT  7.68 62.773 8.568 62.827 ;
     RECT  11.424 62.803 31.944 62.827 ;
     RECT  7.68 62.827 8.472 62.857 ;
     RECT  13.2 62.827 31.944 63.187 ;
     RECT  33.312 60.429 36.408 63.187 ;
     RECT  13.2 63.187 36.408 63.275 ;
     RECT  11.424 62.827 11.448 63.299 ;
     RECT  2.4 61.453 2.712 63.861 ;
     RECT  7.8 62.857 8.472 63.865 ;
     RECT  2.4 63.861 2.808 64.115 ;
     RECT  37.68 62.763 38.664 64.415 ;
     RECT  37.68 64.415 38.808 64.451 ;
     RECT  38.16 64.451 38.808 64.499 ;
     RECT  13.2 63.275 31.896 64.501 ;
     RECT  12.528 64.501 31.896 64.595 ;
     RECT  4.416 62.827 4.44 64.659 ;
     RECT  4.08 64.659 4.44 64.747 ;
     RECT  5.424 64.851 5.448 64.939 ;
     RECT  13.2 64.595 31.896 65.519 ;
     RECT  33.312 63.275 36.408 65.519 ;
     RECT  13.2 65.519 36.408 65.589 ;
     RECT  13.104 65.589 36.408 65.603 ;
     RECT  13.104 65.603 31.896 65.677 ;
     RECT  7.8 63.865 8.112 66.101 ;
     RECT  9.696 66.067 9.72 66.155 ;
     RECT  7.8 66.101 8.472 66.189 ;
     RECT  7.8 66.189 8.112 66.229 ;
     RECT  4.416 64.747 4.44 66.451 ;
     RECT  7.68 66.229 8.112 66.469 ;
     RECT  4.416 66.451 4.536 66.539 ;
     RECT  5.952 66.373 5.976 66.539 ;
     RECT  7.44 66.469 8.112 66.553 ;
     RECT  2.4 64.115 2.712 66.579 ;
     RECT  4.416 66.539 4.44 66.661 ;
     RECT  2.4 66.579 2.904 66.667 ;
     RECT  38.16 64.499 38.184 67.237 ;
     RECT  3.936 66.661 4.44 67.283 ;
     RECT  37.632 67.237 38.184 67.331 ;
     RECT  33.312 65.603 36.408 67.477 ;
     RECT  13.2 65.677 31.896 67.861 ;
     RECT  37.632 67.331 37.656 68.099 ;
     RECT  12.624 67.861 31.896 68.139 ;
     RECT  33.312 67.477 36.504 68.139 ;
     RECT  7.8 66.553 8.112 68.277 ;
     RECT  7.8 68.277 8.76 68.387 ;
     RECT  4.416 67.283 4.44 68.691 ;
     RECT  3.984 68.691 4.44 68.779 ;
     RECT  13.104 68.139 31.896 68.883 ;
     RECT  10.752 68.883 10.776 68.971 ;
     RECT  13.104 68.883 32.136 68.971 ;
     RECT  2.4 66.667 2.712 68.975 ;
     RECT  2.4 68.975 2.856 69.059 ;
     RECT  7.8 68.387 8.112 69.215 ;
     RECT  6.816 69.215 8.112 69.299 ;
     RECT  7.632 69.299 8.112 69.731 ;
     RECT  13.104 68.971 31.896 69.877 ;
     RECT  12.432 69.877 31.896 69.971 ;
     RECT  10.752 70.773 10.776 70.861 ;
     RECT  13.104 69.971 31.896 70.965 ;
     RECT  33.312 68.139 36.408 70.965 ;
     RECT  13.104 70.965 36.408 71.075 ;
     RECT  4.416 68.779 4.44 71.269 ;
     RECT  3.936 71.269 4.44 71.353 ;
     RECT  7.8 69.731 8.112 71.443 ;
     RECT  7.8 71.443 8.904 71.531 ;
     RECT  13.104 71.075 31.512 71.541 ;
     RECT  12.048 71.541 31.512 71.651 ;
     RECT  7.8 71.531 8.112 71.797 ;
     RECT  12.528 71.651 31.512 71.843 ;
     RECT  27.6 71.843 31.512 72.117 ;
     RECT  7.632 71.797 8.112 72.373 ;
     RECT  27.6 72.117 31.608 72.373 ;
     RECT  7.44 72.373 8.112 72.467 ;
     RECT  13.008 71.843 26.472 72.619 ;
     RECT  4.08 71.353 4.44 72.995 ;
     RECT  4.08 72.995 4.104 73.283 ;
     RECT  33.312 71.075 36.408 73.525 ;
     RECT  10.752 73.477 10.776 73.579 ;
     RECT  27.6 72.373 32.28 73.717 ;
     RECT  33.312 73.525 36.984 73.717 ;
     RECT  2.4 69.059 2.712 73.765 ;
     RECT  27.6 73.717 36.984 73.811 ;
     RECT  2.4 73.765 2.856 73.849 ;
     RECT  27.6 73.811 32.328 73.849 ;
     RECT  13.104 72.619 26.472 74.053 ;
     RECT  27.6 73.849 32.28 74.053 ;
     RECT  13.104 74.053 32.28 74.195 ;
     RECT  40.2 55.571 40.512 74.533 ;
     RECT  39.504 74.533 40.512 74.675 ;
     RECT  33.312 73.811 36.984 75.059 ;
     RECT  4.32 75.189 4.344 75.277 ;
     RECT  2.4 73.849 2.712 75.381 ;
     RECT  2.4 75.381 3 75.469 ;
     RECT  4.512 75.733 4.536 75.819 ;
     RECT  6.192 75.733 6.216 75.819 ;
     RECT  7.8 72.467 8.112 75.829 ;
     RECT  13.2 74.195 32.28 75.829 ;
     RECT  33.552 75.059 36.984 75.875 ;
     RECT  9.744 75.317 9.768 75.883 ;
     RECT  7.8 75.829 8.232 75.923 ;
     RECT  12.912 75.829 32.28 75.923 ;
     RECT  6 76.051 6.024 76.139 ;
     RECT  13.104 75.923 32.28 76.139 ;
     RECT  33.984 75.875 36.984 76.549 ;
     RECT  10.848 76.661 10.872 76.749 ;
     RECT  7.8 75.923 8.112 77.039 ;
     RECT  9.312 76.693 9.336 77.039 ;
     RECT  7.8 77.039 9.336 77.123 ;
     RECT  4.896 77.493 4.92 77.581 ;
     RECT  9.36 77.493 9.384 77.581 ;
     RECT  13.2 76.139 32.28 77.701 ;
     RECT  33.984 76.549 37.272 77.795 ;
     RECT  34.032 77.795 37.272 77.989 ;
     RECT  3.744 77.907 3.768 77.995 ;
     RECT  12.48 77.701 32.28 78.037 ;
     RECT  12.48 78.037 32.472 78.059 ;
     RECT  7.8 77.123 8.112 78.277 ;
     RECT  7.488 78.277 8.112 78.613 ;
     RECT  7.488 78.613 8.904 78.955 ;
     RECT  38.976 78.661 39 79.189 ;
     RECT  13.2 78.059 32.472 79.669 ;
     RECT  13.2 79.669 33.048 79.813 ;
     RECT  34.032 77.989 37.8 79.813 ;
     RECT  38.976 79.189 39.048 79.813 ;
     RECT  5.088 79.861 5.112 79.955 ;
     RECT  13.2 79.813 39.048 80.083 ;
     RECT  13.104 80.083 39.048 80.171 ;
     RECT  13.2 80.171 39.048 80.245 ;
     RECT  13.2 80.245 39.144 80.293 ;
     RECT  40.2 74.675 40.512 80.293 ;
     RECT  7.8 78.955 8.232 80.629 ;
     RECT  3.84 80.595 3.864 80.683 ;
     RECT  7.296 80.629 8.232 80.851 ;
     RECT  7.296 80.851 8.904 80.939 ;
     RECT  10.848 80.869 10.872 80.953 ;
     RECT  7.296 80.939 8.112 81.635 ;
     RECT  13.2 80.293 40.512 81.653 ;
     RECT  13.008 81.653 40.512 81.733 ;
     RECT  12.96 81.733 40.512 82.069 ;
     RECT  12.912 82.069 40.512 82.403 ;
     RECT  9.12 82.405 9.144 82.489 ;
     RECT  6.192 82.421 6.216 82.509 ;
     RECT  7.44 81.635 8.112 82.837 ;
     RECT  5.424 82.789 5.448 82.923 ;
     RECT  7.152 82.837 8.808 82.923 ;
     RECT  10.272 82.847 10.296 82.931 ;
     RECT  4.176 82.869 4.2 82.957 ;
     RECT  2.4 75.469 2.712 84.201 ;
     RECT  7.8 82.923 8.112 84.201 ;
     RECT  13.2 82.403 40.512 84.201 ;
     RECT  45.6 2.407 45.912 84.201 ;
     RECT  2.4 84.201 2.52 84.263 ;
     RECT  7.8 84.201 7.92 84.263 ;
     RECT  13.2 84.201 40.32 84.263 ;
     RECT  45.6 84.201 45.72 84.263 ;
     RECT  13.44 84.263 39.288 85.525 ;
     RECT  13.44 85.525 39.336 85.749 ;
     RECT  13.2 85.749 39.336 86.352 ;
     RECT  13.2 86.352 13.32 86.387 ;
    LAYER M6 ;
     RECT  0.037 36.992 0.085 37.024 ;
     RECT  0.037 52.032 0.085 52.064 ;
     RECT  0.037 40.576 0.133 41.312 ;
     RECT  0.085 51.584 0.133 52.064 ;
     RECT  0.037 32.384 0.181 32.416 ;
     RECT  0.133 34.944 0.181 35.296 ;
     RECT  0.085 36.8 0.181 37.024 ;
     RECT  0.085 46.592 0.181 46.624 ;
     RECT  0.133 48.256 0.181 48.288 ;
     RECT  0.181 32.384 0.229 33.12 ;
     RECT  0.133 39.296 0.229 41.312 ;
     RECT  0.085 42.688 0.229 42.72 ;
     RECT  0.229 31.104 0.325 33.12 ;
     RECT  0.181 46.464 0.325 49.12 ;
     RECT  0.325 46.016 0.354 49.12 ;
     RECT  0.133 50.624 0.354 54.624 ;
     RECT  0.325 30.976 0.371 33.12 ;
     RECT  0.229 39.296 0.371 42.72 ;
     RECT  0.133 44.16 0.373 44.192 ;
     RECT  0.354 46.016 0.419 54.624 ;
     RECT  0.181 34.944 0.421 37.024 ;
     RECT  0.371 30.976 0.427 32.608 ;
     RECT  0.419 46.016 0.427 50.848 ;
     RECT  0.421 34.816 0.467 37.024 ;
     RECT  0.427 31.296 0.515 32.608 ;
     RECT  0.419 52.224 0.515 54.624 ;
     RECT  0.427 50.624 0.563 50.848 ;
     RECT  0.427 46.016 0.611 48.8 ;
     RECT  0.515 52.224 0.611 53.6 ;
     RECT  0.611 46.016 0.899 48.416 ;
     RECT  0.515 31.296 1.427 32.48 ;
     RECT  0.899 46.016 2.005 48.16 ;
     RECT  1.427 31.296 2.16 31.328 ;
     RECT  0.563 50.624 2.16 50.72 ;
     RECT  0.611 52.48 2.16 53.344 ;
     RECT  2.005 45.504 2.293 48.16 ;
     RECT  2.16 50.624 2.293 53.344 ;
     RECT  0.467 34.816 2.339 35.936 ;
     RECT  2.16 61.929 2.741 62.601 ;
     RECT  2.293 45.504 2.819 53.344 ;
     RECT  2.741 61.376 2.819 63.904 ;
     RECT  2.16 24.129 2.821 24.801 ;
     RECT  2.16 56.529 2.821 57.201 ;
     RECT  2.16 67.329 2.821 68.001 ;
     RECT  2.16 72.729 2.821 73.401 ;
     RECT  2.16 29.529 2.867 31.328 ;
     RECT  2.339 34.816 2.869 35.744 ;
     RECT  2.821 67.329 2.869 69.024 ;
     RECT  0.371 39.808 2.917 42.528 ;
     RECT  2.869 66.624 2.923 69.024 ;
     RECT  2.869 33.984 2.933 35.744 ;
     RECT  2.923 66.624 2.938 68.768 ;
     RECT  2.933 33.6 2.987 35.744 ;
     RECT  2.917 38.976 2.987 42.528 ;
     RECT  2.821 23.296 3.397 24.801 ;
     RECT  2.16 78.129 3.733 78.801 ;
     RECT  2.821 72.729 3.829 73.824 ;
     RECT  2.965 75.392 3.829 75.424 ;
     RECT  2.16 83.529 3.829 84.201 ;
     RECT  3.81 80.64 3.883 80.672 ;
     RECT  3.925 71.296 4.069 71.328 ;
     RECT  3.829 72.729 4.069 75.424 ;
     RECT  3.397 23.296 4.075 25.12 ;
     RECT  2.938 67.329 4.075 68.768 ;
     RECT  4.069 71.296 4.075 75.424 ;
     RECT  4.069 64.704 4.139 64.736 ;
     RECT  4.075 71.808 4.139 73.401 ;
     RECT  3.589 26.688 4.309 26.72 ;
     RECT  4.075 75.2 4.355 75.424 ;
     RECT  4.075 23.296 4.357 24.801 ;
     RECT  4.309 26.688 4.395 27.808 ;
     RECT  2.867 29.529 4.469 30.496 ;
     RECT  2.987 33.6 4.469 33.632 ;
     RECT  4.075 67.329 4.501 68.001 ;
     RECT  4.469 33.408 4.523 33.632 ;
     RECT  4.501 75.776 4.533 75.808 ;
     RECT  3.733 77.952 4.533 78.801 ;
     RECT  4.469 29.529 4.547 31.072 ;
     RECT  4.533 75.776 4.587 78.801 ;
     RECT  2.987 34.929 4.595 35.744 ;
     RECT  2.819 61.376 4.715 62.752 ;
     RECT  4.661 59.776 4.741 59.808 ;
     RECT  4.715 61.824 5.077 62.752 ;
     RECT  4.587 76.096 5.077 78.801 ;
     RECT  2.821 56.529 5.099 58.144 ;
     RECT  0.373 43.84 5.171 44.192 ;
     RECT  4.741 59.648 5.173 59.808 ;
     RECT  5.173 59.648 5.227 60.064 ;
     RECT  5.077 61.824 5.242 62.816 ;
     RECT  5.413 64.896 5.483 64.928 ;
     RECT  2.819 50.624 5.621 53.344 ;
     RECT  3.301 55.104 5.621 55.136 ;
     RECT  5.099 56.529 5.621 57.312 ;
     RECT  5.621 50.624 5.891 57.312 ;
     RECT  5.077 76.096 6.181 79.904 ;
     RECT  3.829 82.88 6.181 84.201 ;
     RECT  6.181 75.776 6.251 79.904 ;
     RECT  5.227 60.032 6.371 60.064 ;
     RECT  5.891 55.488 6.709 57.312 ;
     RECT  4.501 66.496 6.805 68.001 ;
     RECT  4.523 33.408 6.837 33.44 ;
     RECT  4.595 34.929 6.837 35.601 ;
     RECT  5.242 61.929 6.853 62.816 ;
     RECT  6.837 59.712 6.91 59.744 ;
     RECT  6.181 82.432 7.266 84.201 ;
     RECT  6.251 76.096 7.285 79.904 ;
     RECT  7.266 81.536 7.285 84.201 ;
     RECT  6.837 33.024 7.331 35.601 ;
     RECT  7.285 76.096 7.546 84.201 ;
     RECT  6.805 66.496 7.575 69.28 ;
     RECT  4.139 72.384 7.605 73.401 ;
     RECT  4.547 29.529 7.669 30.201 ;
     RECT  7.575 66.496 7.669 69.536 ;
     RECT  6.709 55.488 7.715 58.016 ;
     RECT  6.853 61.248 7.989 62.816 ;
     RECT  7.989 60.352 8.043 62.816 ;
     RECT  7.331 33.024 8.197 33.056 ;
     RECT  7.546 76.096 8.197 80.928 ;
     RECT  8.197 32.576 8.243 33.056 ;
     RECT  8.197 75.84 8.243 80.928 ;
     RECT  7.669 66.24 8.245 69.536 ;
     RECT  5.891 50.624 8.293 54.112 ;
     RECT  7.715 55.488 8.293 57.312 ;
     RECT  8.245 66.112 8.299 69.536 ;
     RECT  8.043 61.929 8.437 62.816 ;
     RECT  8.437 61.929 8.506 63.84 ;
     RECT  8.043 60.352 8.579 60.384 ;
     RECT  8.299 66.112 8.771 68.32 ;
     RECT  7.669 29.376 8.821 30.201 ;
     RECT  7.605 71.808 8.869 73.401 ;
     RECT  8.802 21.184 8.875 21.216 ;
     RECT  8.243 32.576 8.875 32.672 ;
     RECT  8.243 75.84 8.915 78.944 ;
     RECT  7.546 82.432 9.155 84.201 ;
     RECT  8.293 50.624 9.387 57.312 ;
     RECT  8.821 29.248 9.397 30.201 ;
     RECT  8.915 75.84 9.451 78.801 ;
     RECT  9.397 29.248 9.637 30.496 ;
     RECT  9.637 21.632 9.707 21.664 ;
     RECT  9.637 28.352 9.707 30.496 ;
     RECT  8.771 66.112 9.731 68.001 ;
     RECT  9.451 75.84 9.733 76.768 ;
     RECT  9.155 82.88 10.307 84.201 ;
     RECT  9.707 29.248 10.453 30.496 ;
     RECT  10.453 29.248 10.485 30.752 ;
     RECT  8.875 32.64 10.485 32.672 ;
     RECT  10.485 29.248 10.539 32.672 ;
     RECT  9.731 66.24 10.722 68.001 ;
     RECT  8.869 71.488 10.722 73.401 ;
     RECT  9.387 55.36 10.739 57.312 ;
     RECT  9.205 58.624 10.789 58.656 ;
     RECT  10.722 66.24 10.795 68.96 ;
     RECT  10.722 70.784 10.795 73.568 ;
     RECT  9.733 75.328 10.795 76.768 ;
     RECT  9.387 50.624 10.883 53.536 ;
     RECT  8.243 80.896 10.883 80.928 ;
     RECT  10.883 50.624 10.979 53.344 ;
     RECT  2.16 18.729 11.029 19.401 ;
     RECT  11.029 18.729 11.147 20.256 ;
     RECT  11.147 18.24 11.243 20.256 ;
     RECT  11.49 10.24 11.563 10.272 ;
     RECT  11.49 11.648 11.563 11.68 ;
     RECT  11.243 18.24 11.563 19.401 ;
     RECT  2.16 7.929 12.181 8.601 ;
     RECT  2.16 13.329 12.213 14.001 ;
     RECT  10.979 50.624 12.275 51.801 ;
     RECT  10.795 76.096 12.45 76.768 ;
     RECT  9.451 78.129 12.45 78.801 ;
     RECT  10.795 66.24 12.469 68.001 ;
     RECT  10.789 58.624 12.515 58.976 ;
     RECT  12.421 69.888 12.523 69.92 ;
     RECT  12.213 13.329 12.563 14.304 ;
     RECT  4.357 23.04 12.563 24.801 ;
     RECT  10.739 55.424 12.563 57.312 ;
     RECT  10.795 71.552 12.565 73.401 ;
     RECT  10.979 53.312 12.834 53.344 ;
     RECT  12.45 76.096 12.901 78.801 ;
     RECT  12.469 81.536 12.901 81.568 ;
     RECT  10.307 83.529 12.901 84.201 ;
     RECT  12.834 53.312 12.907 53.472 ;
     RECT  12.469 66.24 12.917 68.128 ;
     RECT  12.901 75.84 12.971 78.801 ;
     RECT  2.16 2.529 13.045 3.201 ;
     RECT  12.563 13.329 13.045 14.001 ;
     RECT  5.171 43.84 13.093 44.128 ;
     RECT  2.819 45.504 13.093 48.16 ;
     RECT  12.517 64.512 13.093 64.544 ;
     RECT  12.917 66.24 13.093 68.32 ;
     RECT  8.506 61.929 13.109 62.816 ;
     RECT  13.093 64.512 13.109 69.28 ;
     RECT  12.971 76.096 13.139 78.801 ;
     RECT  13.093 43.84 13.163 48.16 ;
     RECT  13.109 61.929 13.163 69.28 ;
     RECT  13.045 86.08 13.173 86.112 ;
     RECT  13.173 86.016 13.189 86.112 ;
     RECT  13.189 85.76 13.333 86.112 ;
     RECT  13.333 85.76 13.355 86.176 ;
     RECT  13.045 12.032 13.419 14.001 ;
     RECT  13.045 2.24 13.429 3.488 ;
     RECT  12.917 80.128 13.602 80.16 ;
     RECT  12.901 81.536 13.602 84.201 ;
     RECT  12.565 72.576 13.611 73.401 ;
     RECT  13.55 5.12 13.619 5.152 ;
     RECT  13.493 0.32 13.621 0.352 ;
     RECT  13.611 72.729 13.669 73.401 ;
     RECT  13.429 1.728 13.675 3.488 ;
     RECT  12.181 7.929 13.715 9.696 ;
     RECT  11.563 18.729 13.717 19.401 ;
     RECT  10.539 29.248 13.717 30.201 ;
     RECT  13.139 76.416 13.717 78.801 ;
     RECT  13.602 80.128 13.717 84.201 ;
     RECT  13.669 72.729 13.739 74.528 ;
     RECT  13.163 43.84 13.763 44.128 ;
     RECT  12.515 58.624 13.763 58.656 ;
     RECT  13.717 76.416 14.059 84.201 ;
     RECT  13.621 0.192 14.197 0.352 ;
     RECT  13.355 85.824 14.261 86.176 ;
     RECT  13.163 66.048 14.266 68.128 ;
     RECT  14.059 76.416 14.291 80.416 ;
     RECT  14.261 85.824 14.291 86.24 ;
     RECT  13.717 18.176 14.293 19.401 ;
     RECT  14.293 18.176 14.325 19.936 ;
     RECT  14.197 21.824 14.325 21.856 ;
     RECT  14.059 81.792 14.325 84.201 ;
     RECT  12.275 50.688 14.339 51.801 ;
     RECT  10.539 31.68 14.379 31.712 ;
     RECT  14.325 18.176 14.389 21.856 ;
     RECT  14.325 81.792 14.398 84.32 ;
     RECT  14.069 6.208 14.533 6.24 ;
     RECT  14.325 33.472 14.571 33.504 ;
     RECT  13.717 28.864 14.581 30.201 ;
     RECT  14.389 18.176 14.645 22.56 ;
     RECT  12.563 24 14.645 24.801 ;
     RECT  14.291 85.952 14.65 86.24 ;
     RECT  14.533 6.208 14.675 6.304 ;
     RECT  14.645 18.176 14.699 24.801 ;
     RECT  13.675 1.984 14.763 3.488 ;
     RECT  14.65 85.952 14.763 86.112 ;
     RECT  14.763 2.112 14.773 3.488 ;
     RECT  14.773 2.112 14.842 4.576 ;
     RECT  14.398 81.792 14.867 84.201 ;
     RECT  2.987 39.808 14.946 42.528 ;
     RECT  13.763 43.84 14.946 43.872 ;
     RECT  14.763 86.016 14.955 86.112 ;
     RECT  14.699 18.176 14.963 20.576 ;
     RECT  13.163 45.504 14.963 48.16 ;
     RECT  14.266 66.048 14.963 68.001 ;
     RECT  14.699 22.528 15.013 24.801 ;
     RECT  13.621 36.928 15.059 36.96 ;
     RECT  14.197 0.192 15.061 0.608 ;
     RECT  14.581 27.84 15.109 30.201 ;
     RECT  14.842 2.176 15.155 4.576 ;
     RECT  13.163 61.929 15.205 63.392 ;
     RECT  15.061 0.192 15.275 0.736 ;
     RECT  15.155 2.304 15.349 4.576 ;
     RECT  13.715 7.929 15.349 9.184 ;
     RECT  7.331 34.929 15.349 35.601 ;
     RECT  14.955 86.08 15.403 86.112 ;
     RECT  15.349 6.848 15.418 9.184 ;
     RECT  15.418 7.36 15.443 8.601 ;
     RECT  12.565 54.912 15.443 54.944 ;
     RECT  14.867 82.112 15.443 84.201 ;
     RECT  14.946 39.808 15.491 43.872 ;
     RECT  15.443 83.392 15.491 84.201 ;
     RECT  14.339 51.008 15.685 51.801 ;
     RECT  15.541 38.144 15.723 38.176 ;
     RECT  15.685 50.176 15.854 51.801 ;
     RECT  15.349 34.368 15.877 35.601 ;
     RECT  15.854 50.176 15.923 51.936 ;
     RECT  15.877 33.792 15.925 35.601 ;
     RECT  15.109 27.84 15.979 31.072 ;
     RECT  15.491 39.808 16.019 43.36 ;
     RECT  14.963 45.504 16.019 47.584 ;
     RECT  14.291 76.416 16.019 79.2 ;
     RECT  15.013 22.528 16.065 25.696 ;
     RECT  14.963 18.176 16.067 19.552 ;
     RECT  16.065 22.528 16.107 25.12 ;
     RECT  13.739 72.729 16.245 73.401 ;
     RECT  13.419 13.329 16.261 14.001 ;
     RECT  14.963 66.24 16.299 68.001 ;
     RECT  16.019 76.416 16.299 78.801 ;
     RECT  15.925 33.792 16.307 36.32 ;
     RECT  16.307 33.792 16.405 35.744 ;
     RECT  15.979 28.992 16.437 31.072 ;
     RECT  16.437 28.992 16.491 31.904 ;
     RECT  16.405 33.6 16.491 35.744 ;
     RECT  12.563 56.529 16.501 57.312 ;
     RECT  16.501 56.529 16.57 57.376 ;
     RECT  16.019 40.329 16.595 43.36 ;
     RECT  16.299 77.312 16.595 78.801 ;
     RECT  15.989 27.584 16.597 27.616 ;
     RECT  15.205 61.929 16.597 63.84 ;
     RECT  15.349 2.304 16.622 5.088 ;
     RECT  16.597 61.824 16.683 63.84 ;
     RECT  12.907 53.312 16.693 53.344 ;
     RECT  16.57 56.529 16.811 57.312 ;
     RECT  16.622 2.304 16.949 5.728 ;
     RECT  16.949 2.24 16.981 5.728 ;
     RECT  16.981 2.24 17.067 6.304 ;
     RECT  16.019 45.729 17.075 47.584 ;
     RECT  17.013 60.224 17.086 60.256 ;
     RECT  17.067 2.24 17.123 5.088 ;
     RECT  16.491 31.872 17.123 31.904 ;
     RECT  15.253 58.752 17.171 58.784 ;
     RECT  16.501 16 17.198 16.032 ;
     RECT  16.067 18.176 17.198 19.401 ;
     RECT  17.123 2.304 17.267 5.088 ;
     RECT  16.597 27.328 17.363 27.616 ;
     RECT  17.198 16 17.413 19.401 ;
     RECT  17.413 16 17.459 19.552 ;
     RECT  17.459 17.088 17.515 19.552 ;
     RECT  16.107 24.129 17.605 24.928 ;
     RECT  16.491 28.992 17.699 30.201 ;
     RECT  16.595 43.328 17.747 43.36 ;
     RECT  16.107 22.528 17.909 22.56 ;
     RECT  17.515 17.088 17.963 19.401 ;
     RECT  17.909 15.36 17.987 15.392 ;
     RECT  16.299 67.329 18.037 68.001 ;
     RECT  17.269 69.376 18.037 69.408 ;
     RECT  16.245 71.872 18.037 73.401 ;
     RECT  16.683 61.929 18.085 63.84 ;
     RECT  18.037 67.329 18.091 73.401 ;
     RECT  18.091 70.08 18.106 73.401 ;
     RECT  17.605 24.129 18.133 25.696 ;
     RECT  17.363 27.328 18.133 27.36 ;
     RECT  17.909 22.272 18.165 22.56 ;
     RECT  18.133 24.129 18.165 27.36 ;
     RECT  17.699 29.248 18.219 30.201 ;
     RECT  18.165 22.272 18.229 27.36 ;
     RECT  15.491 83.529 18.229 84.201 ;
     RECT  18.229 21.376 18.275 27.36 ;
     RECT  15.923 50.176 18.275 51.801 ;
     RECT  16.693 53.312 18.275 54.624 ;
     RECT  18.091 67.329 18.275 68.128 ;
     RECT  18.275 54.592 18.277 54.624 ;
     RECT  16.811 56.529 18.277 57.201 ;
     RECT  16.491 34.929 18.373 35.601 ;
     RECT  17.267 2.304 18.469 4.576 ;
     RECT  16.595 40.329 18.469 41.248 ;
     RECT  18.106 70.08 18.515 70.112 ;
     RECT  18.229 83.529 18.539 84.896 ;
     RECT  17.075 45.729 18.677 47.328 ;
     RECT  18.469 40.329 18.731 42.08 ;
     RECT  17.963 18.624 18.997 19.401 ;
     RECT  18.731 40.329 18.997 41.001 ;
     RECT  18.106 71.872 18.997 73.401 ;
     RECT  18.677 45.568 19.043 47.328 ;
     RECT  18.997 71.872 19.043 74.08 ;
     RECT  17.963 17.088 19.091 17.12 ;
     RECT  15.443 7.929 19.125 8.601 ;
     RECT  18.469 2.24 19.189 4.576 ;
     RECT  18.275 21.376 19.189 21.408 ;
     RECT  18.997 18.624 19.235 19.552 ;
     RECT  19.189 21.12 19.235 21.408 ;
     RECT  16.261 13.184 19.253 14.001 ;
     RECT  19.189 2.176 19.285 4.576 ;
     RECT  19.125 7.929 19.307 8.736 ;
     RECT  19.307 7.929 19.31 8.601 ;
     RECT  19.285 2.176 19.317 5.152 ;
     RECT  18.275 22.72 19.427 27.36 ;
     RECT  19.429 10.816 19.499 10.848 ;
     RECT  19.381 31.936 19.637 31.968 ;
     RECT  18.373 34.176 19.637 35.601 ;
     RECT  19.637 31.936 19.691 36.32 ;
     RECT  19.691 31.936 19.715 33.056 ;
     RECT  19.427 26.752 19.811 27.36 ;
     RECT  15.275 0.192 19.861 0.544 ;
     RECT  19.317 2.176 19.861 5.664 ;
     RECT  19.861 0.192 19.947 5.664 ;
     RECT  18.085 61.929 19.957 64.864 ;
     RECT  18.275 67.329 19.957 68.001 ;
     RECT  19.235 21.12 20.003 21.152 ;
     RECT  19.691 34.368 20.003 36.32 ;
     RECT  19.043 45.729 20.003 47.328 ;
     RECT  19.957 67.2 20.026 68.001 ;
     RECT  16.595 78.129 20.085 78.801 ;
     RECT  18.373 81.536 20.139 81.568 ;
     RECT  19.947 2.24 20.197 5.664 ;
     RECT  19.957 61.929 20.243 65.504 ;
     RECT  19.253 13.12 20.341 14.001 ;
     RECT  18.997 39.168 20.341 41.001 ;
     RECT  18.275 51.129 20.341 51.801 ;
     RECT  19.043 72.729 20.341 74.08 ;
     RECT  20.341 39.168 20.387 42.208 ;
     RECT  20.341 72.576 20.395 74.08 ;
     RECT  20.322 76.16 20.395 76.192 ;
     RECT  20.085 78.129 20.395 79.776 ;
     RECT  20.341 11.968 20.523 14.001 ;
     RECT  20.387 39.872 20.523 42.208 ;
     RECT  18.277 54.592 20.533 57.201 ;
     RECT  20.197 2.24 20.581 6.304 ;
     RECT  19.31 7.808 20.581 8.601 ;
     RECT  20.395 72.576 20.675 73.401 ;
     RECT  20.523 40.329 20.771 41.632 ;
     RECT  20.533 54.592 21.011 58.144 ;
     RECT  20.581 2.24 21.013 8.601 ;
     RECT  20.341 50.752 21.045 51.801 ;
     RECT  21.013 2.24 21.099 9.76 ;
     RECT  21.011 54.592 21.155 57.201 ;
     RECT  20.243 61.929 21.163 64.736 ;
     RECT  20.523 13.184 21.355 14.001 ;
     RECT  19.715 31.936 21.365 31.968 ;
     RECT  20.003 34.368 21.365 35.601 ;
     RECT  19.811 26.752 21.419 26.784 ;
     RECT  21.282 16.192 21.483 16.224 ;
     RECT  21.397 21.12 21.483 21.152 ;
     RECT  18.219 29.529 21.589 30.201 ;
     RECT  21.365 31.936 21.589 35.601 ;
     RECT  21.099 2.24 21.614 9.696 ;
     RECT  19.235 18.624 21.635 19.401 ;
     RECT  19.947 0.192 21.829 0.672 ;
     RECT  21.614 2.176 21.829 9.696 ;
     RECT  21.045 49.984 21.971 51.801 ;
     RECT  20.026 67.329 22.005 68.001 ;
     RECT  20.003 45.729 22.021 47.008 ;
     RECT  21.163 64.704 22.059 64.736 ;
     RECT  22.005 66.688 22.115 68.576 ;
     RECT  21.829 0.192 22.251 9.696 ;
     RECT  22.165 11.968 22.251 12 ;
     RECT  22.115 67.329 22.693 68.576 ;
     RECT  19.427 24.129 22.741 24.801 ;
     RECT  21.589 31.872 22.835 35.601 ;
     RECT  22.693 67.329 22.835 68.64 ;
     RECT  19.427 22.72 22.883 22.752 ;
     RECT  21.637 37.12 22.883 37.152 ;
     RECT  21.589 28.48 22.979 30.201 ;
     RECT  22.741 24.129 23.125 25.76 ;
     RECT  22.789 70.144 23.699 70.176 ;
     RECT  22.251 0.192 23.845 8.601 ;
     RECT  23.845 0.192 24.053 9.184 ;
     RECT  22.979 29.529 24.373 30.201 ;
     RECT  23.125 24 24.419 25.76 ;
     RECT  24.325 86.016 24.437 86.048 ;
     RECT  24.437 86.016 24.491 86.24 ;
     RECT  24.053 0.192 24.515 10.336 ;
     RECT  24.491 86.208 24.515 86.24 ;
     RECT  21.163 61.929 24.517 63.264 ;
     RECT  21.155 55.872 24.611 57.201 ;
     RECT  24.515 2.529 24.707 10.336 ;
     RECT  24.707 7.808 24.899 10.336 ;
     RECT  20.771 40.329 24.901 41.001 ;
     RECT  22.021 45.729 24.997 47.072 ;
     RECT  24.997 45.729 25.013 47.328 ;
     RECT  24.899 7.929 25.043 10.336 ;
     RECT  25.043 10.304 25.067 10.336 ;
     RECT  25.013 45.568 25.067 47.328 ;
     RECT  24.515 0.192 25.091 0.672 ;
     RECT  21.971 51.129 25.093 51.801 ;
     RECT  24.707 2.529 25.139 5.792 ;
     RECT  23.893 81.152 25.314 81.184 ;
     RECT  25.139 5.76 25.323 5.792 ;
     RECT  18.539 83.529 25.333 84.201 ;
     RECT  25.314 80.32 25.387 81.184 ;
     RECT  25.333 82.688 25.427 84.201 ;
     RECT  24.373 28.224 25.715 30.201 ;
     RECT  24.517 61.056 25.909 63.264 ;
     RECT  24.853 58.56 25.963 58.592 ;
     RECT  25.909 59.968 26.003 63.264 ;
     RECT  25.957 42.752 26.027 42.784 ;
     RECT  23.893 76.224 26.037 76.256 ;
     RECT  20.395 78.129 26.037 78.801 ;
     RECT  25.387 80.32 26.037 80.992 ;
     RECT  26.101 49.216 26.149 49.248 ;
     RECT  25.093 51.129 26.149 52.576 ;
     RECT  22.835 67.329 26.149 68.192 ;
     RECT  26.149 49.216 26.165 52.576 ;
     RECT  26.037 76.224 26.197 80.992 ;
     RECT  26.165 49.216 26.219 52.96 ;
     RECT  26.197 75.136 26.219 80.992 ;
     RECT  24.419 24 26.243 24.801 ;
     RECT  24.901 39.296 26.293 41.001 ;
     RECT  26.293 39.296 26.347 41.376 ;
     RECT  22.835 33.28 26.357 35.601 ;
     RECT  26.357 32.832 26.435 35.601 ;
     RECT  25.715 29.056 26.725 30.201 ;
     RECT  26.149 66.624 26.725 68.192 ;
     RECT  26.389 44.224 26.741 44.256 ;
     RECT  26.741 43.84 26.795 44.256 ;
     RECT  25.139 2.529 26.805 3.36 ;
     RECT  26.795 43.84 26.819 43.872 ;
     RECT  26.725 66.24 26.867 68.192 ;
     RECT  26.805 2.368 26.917 3.36 ;
     RECT  26.798 5.696 26.917 5.728 ;
     RECT  26.347 39.36 26.917 41.376 ;
     RECT  26.917 2.368 26.933 5.728 ;
     RECT  26.933 2.304 26.997 5.728 ;
     RECT  26.997 2.304 27.109 5.984 ;
     RECT  25.091 0.192 27.125 0.224 ;
     RECT  27.109 2.24 27.157 5.984 ;
     RECT  25.043 7.929 27.157 8.601 ;
     RECT  26.917 10.88 27.157 10.912 ;
     RECT  27.157 10.88 27.243 11.424 ;
     RECT  26.243 24.129 27.301 24.801 ;
     RECT  24.611 56.529 27.349 57.201 ;
     RECT  26.773 37.568 27.381 37.6 ;
     RECT  26.725 29.056 27.443 30.368 ;
     RECT  26.917 39.36 27.443 41.568 ;
     RECT  27.381 36.928 27.491 37.6 ;
     RECT  27.157 2.24 27.499 8.601 ;
     RECT  27.499 2.24 27.539 5.984 ;
     RECT  27.125 0.192 27.573 0.544 ;
     RECT  27.301 24.129 27.618 25.376 ;
     RECT  26.003 61.056 27.637 63.264 ;
     RECT  27.349 56.529 27.685 58.144 ;
     RECT  27.618 23.872 27.691 25.376 ;
     RECT  26.219 51.129 27.701 52.96 ;
     RECT  27.637 61.056 27.706 63.392 ;
     RECT  27.685 56.128 27.755 58.144 ;
     RECT  26.435 33.28 27.781 35.601 ;
     RECT  27.253 10.816 27.819 10.848 ;
     RECT  27.573 0.192 27.971 0.672 ;
     RECT  25.067 45.568 27.971 46.401 ;
     RECT  26.219 75.136 28.011 80.032 ;
     RECT  26.219 49.216 28.067 49.248 ;
     RECT  20.675 72.729 28.069 73.401 ;
     RECT  28.011 75.136 28.069 76.256 ;
     RECT  28.069 72.729 28.267 76.256 ;
     RECT  28.213 26.816 28.282 26.848 ;
     RECT  27.443 29.529 28.395 30.368 ;
     RECT  27.781 33.024 28.523 35.601 ;
     RECT  27.691 24.129 28.547 25.376 ;
     RECT  27.701 51.129 28.547 54.112 ;
     RECT  28.645 11.392 28.715 11.424 ;
     RECT  27.755 56.529 28.725 58.144 ;
     RECT  28.547 51.129 28.779 53.024 ;
     RECT  27.706 61.056 28.779 63.264 ;
     RECT  28.779 61.929 28.798 63.264 ;
     RECT  27.539 2.24 28.837 3.616 ;
     RECT  27.539 5.12 28.837 5.984 ;
     RECT  28.547 24.129 28.981 24.801 ;
     RECT  28.981 16.576 29.05 16.608 ;
     RECT  28.395 29.529 29.173 30.201 ;
     RECT  27.443 40.329 29.267 41.568 ;
     RECT  28.837 2.24 29.269 5.984 ;
     RECT  27.499 7.929 29.269 8.601 ;
     RECT  29.269 2.24 29.301 6.304 ;
     RECT  28.267 74.88 29.315 76.256 ;
     RECT  29.315 76.224 29.355 76.256 ;
     RECT  29.301 2.112 29.365 6.304 ;
     RECT  29.365 1.984 29.419 6.304 ;
     RECT  29.419 1.984 29.547 5.024 ;
     RECT  29.269 7.929 29.547 9.76 ;
     RECT  29.173 29.056 29.611 30.201 ;
     RECT  26.867 66.24 29.611 68.001 ;
     RECT  27.491 37.568 29.621 37.6 ;
     RECT  29.621 37.568 29.675 38.816 ;
     RECT  29.675 38.784 29.891 38.816 ;
     RECT  29.797 86.08 29.939 86.112 ;
     RECT  28.011 78.129 29.987 80.032 ;
     RECT  28.981 23.552 30.005 24.801 ;
     RECT  29.547 7.929 30.037 8.601 ;
     RECT  30.005 23.552 30.083 25.12 ;
     RECT  27.589 69.824 30.275 69.856 ;
     RECT  30.085 86.016 30.371 86.048 ;
     RECT  28.523 33.024 30.373 33.056 ;
     RECT  29.611 29.529 30.453 30.201 ;
     RECT  30.373 32.448 30.453 33.056 ;
     RECT  28.523 34.816 30.453 35.601 ;
     RECT  28.779 51.129 30.453 51.801 ;
     RECT  30.453 32.448 30.469 35.601 ;
     RECT  30.453 29.529 30.526 30.56 ;
     RECT  30.453 49.408 30.526 49.44 ;
     RECT  30.469 31.936 30.571 35.601 ;
     RECT  30.571 32.448 30.659 35.601 ;
     RECT  27.971 0.192 30.709 0.544 ;
     RECT  29.547 1.984 30.709 4.576 ;
     RECT  28.267 72.729 30.709 73.568 ;
     RECT  29.315 74.88 30.709 74.912 ;
     RECT  30.659 34.816 30.757 35.601 ;
     RECT  28.341 27.328 30.853 27.36 ;
     RECT  30.453 51.129 30.949 52.192 ;
     RECT  30.037 7.424 31.022 8.601 ;
     RECT  31.022 6.848 31.091 8.601 ;
     RECT  28.837 59.712 31.139 59.744 ;
     RECT  31.214 10.944 31.283 10.976 ;
     RECT  21.355 13.329 31.285 14.001 ;
     RECT  29.987 78.129 31.285 78.801 ;
     RECT  31.285 13.329 31.354 14.304 ;
     RECT  31.221 5.952 31.475 5.984 ;
     RECT  30.709 0.192 31.477 4.576 ;
     RECT  30.949 51.129 31.541 52.448 ;
     RECT  30.805 54.592 31.541 54.624 ;
     RECT  30.709 72.729 31.573 74.912 ;
     RECT  31.477 0.192 31.595 5.728 ;
     RECT  31.541 51.129 31.595 54.624 ;
     RECT  31.573 72.128 31.605 74.912 ;
     RECT  31.595 53.504 31.619 54.624 ;
     RECT  31.605 70.976 31.65 74.912 ;
     RECT  31.285 76.992 31.65 78.801 ;
     RECT  31.65 70.976 31.659 78.801 ;
     RECT  30.181 64.96 31.723 64.992 ;
     RECT  31.659 72.729 31.723 78.801 ;
     RECT  29.611 67.2 31.738 68.001 ;
     RECT  31.091 7.929 31.765 8.601 ;
     RECT  31.765 7.929 31.861 9.184 ;
     RECT  31.619 54.592 31.861 54.624 ;
     RECT  28.798 61.929 31.909 62.601 ;
     RECT  31.861 54.592 31.915 55.072 ;
     RECT  31.909 61.929 31.925 62.88 ;
     RECT  31.595 0.192 31.93 5.664 ;
     RECT  31.915 55.04 31.955 55.072 ;
     RECT  31.93 2.24 32.003 5.664 ;
     RECT  31.925 61.248 32.051 63.264 ;
     RECT  31.738 67.329 32.101 68.001 ;
     RECT  31.861 7.929 32.171 10.336 ;
     RECT  32.101 67.329 32.171 68.96 ;
     RECT  30.083 23.552 32.181 24.801 ;
     RECT  27.971 45.729 32.197 46.401 ;
     RECT  32.181 23.552 32.243 25.376 ;
     RECT  29.267 40.329 32.245 41.001 ;
     RECT  32.243 24.129 32.254 25.376 ;
     RECT  30.526 29.529 32.341 30.201 ;
     RECT  30.853 27.328 32.373 27.872 ;
     RECT  32.341 29.529 32.373 30.816 ;
     RECT  32.309 38.016 32.387 38.048 ;
     RECT  32.373 27.328 32.427 30.816 ;
     RECT  31.659 70.976 32.435 71.008 ;
     RECT  31.723 72.729 32.435 74.912 ;
     RECT  32.427 27.328 32.437 30.201 ;
     RECT  32.437 26.752 32.491 30.201 ;
     RECT  32.051 61.929 32.491 63.264 ;
     RECT  32.491 26.752 32.506 26.784 ;
     RECT  32.437 65.536 32.506 65.568 ;
     RECT  30.757 34.816 32.565 36 ;
     RECT  32.501 43.776 32.579 43.808 ;
     RECT  30.659 32.448 32.625 32.48 ;
     RECT  32.565 34.048 32.675 36 ;
     RECT  31.723 78.016 33.013 78.801 ;
     RECT  32.053 80.896 33.013 80.928 ;
     RECT  33.013 78.016 33.059 80.928 ;
     RECT  32.491 28.928 33.203 30.201 ;
     RECT  32.003 2.304 33.326 5.664 ;
     RECT  33.326 2.304 33.397 5.728 ;
     RECT  32.171 7.929 33.515 9.184 ;
     RECT  33.515 7.929 33.518 8.736 ;
     RECT  33.397 2.304 33.589 6.304 ;
     RECT  33.518 7.808 33.589 8.736 ;
     RECT  32.675 34.816 33.637 36 ;
     RECT  31.93 0.192 33.781 0.48 ;
     RECT  33.059 78.016 33.971 79.968 ;
     RECT  32.435 74.88 33.973 74.912 ;
     RECT  32.171 67.329 34.021 68.001 ;
     RECT  33.973 10.944 34.042 10.976 ;
     RECT  32.245 39.36 34.069 41.001 ;
     RECT  32.197 45.312 34.069 46.401 ;
     RECT  33.973 74.88 34.115 76.128 ;
     RECT  34.069 39.36 34.155 41.12 ;
     RECT  33.637 34.816 34.165 36.96 ;
     RECT  34.021 67.329 34.165 68.896 ;
     RECT  33.971 78.016 34.259 78.801 ;
     RECT  34.069 10.816 34.549 10.848 ;
     RECT  33.589 2.304 34.613 8.736 ;
     RECT  34.613 2.176 34.693 8.736 ;
     RECT  31.354 13.329 34.693 14.001 ;
     RECT  34.165 67.2 34.693 68.896 ;
     RECT  32.435 72.729 34.693 73.401 ;
     RECT  34.549 10.304 34.739 10.848 ;
     RECT  34.693 2.048 34.795 8.736 ;
     RECT  34.693 12.544 34.795 14.001 ;
     RECT  34.405 32.448 34.805 32.48 ;
     RECT  34.165 33.856 34.805 36.96 ;
     RECT  34.155 39.36 34.805 41.001 ;
     RECT  34.805 32.448 34.859 41.001 ;
     RECT  34.693 72.128 34.859 73.401 ;
     RECT  34.795 7.424 34.997 8.736 ;
     RECT  34.693 67.2 35.115 69.536 ;
     RECT  35.173 86.208 35.189 86.24 ;
     RECT  34.997 7.424 35.219 9.888 ;
     RECT  35.219 7.929 35.243 9.76 ;
     RECT  35.189 86.08 35.243 86.24 ;
     RECT  34.859 38.144 35.267 38.176 ;
     RECT  31.595 51.129 35.317 51.801 ;
     RECT  34.069 45.056 35.363 46.401 ;
     RECT  34.115 74.88 35.363 75.68 ;
     RECT  35.243 86.08 35.363 86.112 ;
     RECT  34.859 72.729 35.365 73.401 ;
     RECT  34.859 40.329 35.461 41.001 ;
     RECT  34.859 32.832 35.555 36.512 ;
     RECT  34.597 65.536 35.795 65.568 ;
     RECT  33.781 0.192 35.822 0.608 ;
     RECT  34.795 2.048 35.822 5.728 ;
     RECT  35.822 0.192 35.891 5.728 ;
     RECT  35.555 33.856 35.939 36.512 ;
     RECT  35.115 67.329 35.939 68.384 ;
     RECT  35.939 33.856 35.987 35.601 ;
     RECT  35.891 2.24 36.179 5.728 ;
     RECT  35.365 72.729 36.203 74.08 ;
     RECT  35.363 75.648 36.203 75.68 ;
     RECT  36.179 2.24 36.227 3.488 ;
     RECT  36.179 5.12 36.459 5.728 ;
     RECT  35.461 40.329 36.515 42.144 ;
     RECT  35.939 67.329 36.515 68.128 ;
     RECT  36.45 37.44 36.523 37.472 ;
     RECT  36.227 2.304 36.611 3.488 ;
     RECT  35.891 0.192 36.715 0.544 ;
     RECT  35.317 51.129 36.757 51.936 ;
     RECT  28.725 56.529 36.789 58.4 ;
     RECT  36.421 60.352 36.789 60.384 ;
     RECT  36.459 5.12 36.843 5.152 ;
     RECT  36.757 50.112 36.843 51.936 ;
     RECT  36.715 0.192 36.851 0.416 ;
     RECT  35.363 45.729 36.853 46.401 ;
     RECT  36.469 38.912 36.949 38.944 ;
     RECT  36.515 40.329 36.949 41.001 ;
     RECT  36.851 0.384 36.971 0.416 ;
     RECT  36.611 2.304 36.971 3.201 ;
     RECT  36.949 38.912 37.035 41.001 ;
     RECT  36.949 42.688 37.035 42.72 ;
     RECT  37.035 38.912 37.235 38.944 ;
     RECT  36.789 56.529 37.667 60.384 ;
     RECT  37.667 56.529 37.859 58.272 ;
     RECT  34.693 47.808 37.995 47.84 ;
     RECT  37.941 49.664 38.014 49.696 ;
     RECT  37.859 56.529 38.053 57.201 ;
     RECT  36.853 44.864 38.243 46.401 ;
     RECT  36.843 51.129 38.291 51.936 ;
     RECT  32.491 61.929 38.773 62.601 ;
     RECT  38.773 61.929 38.842 62.752 ;
     RECT  38.773 64.448 38.842 64.48 ;
     RECT  37.525 53.504 38.867 53.536 ;
     RECT  38.053 55.488 39.395 57.201 ;
     RECT  36.971 2.529 50.49 3.201 ;
     RECT  35.243 7.929 50.49 8.601 ;
     RECT  34.795 13.329 50.49 14.001 ;
     RECT  21.635 18.729 50.49 19.401 ;
     RECT  32.254 24.129 50.49 24.801 ;
     RECT  33.203 29.529 50.49 30.201 ;
     RECT  35.987 34.929 50.49 35.601 ;
     RECT  37.035 40.329 50.49 41.001 ;
     RECT  38.243 45.729 50.49 46.401 ;
     RECT  38.291 51.129 50.49 51.801 ;
     RECT  39.395 56.529 50.49 57.201 ;
     RECT  38.842 61.929 50.49 62.601 ;
     RECT  36.515 67.329 50.49 68.001 ;
     RECT  36.203 72.729 50.49 73.401 ;
     RECT  34.259 78.129 50.49 78.801 ;
     RECT  25.427 83.529 50.49 84.201 ;
    LAYER M7 ;
     RECT  13.632 0.181 36.576 0.309 ;
     RECT  13.504 0.309 36.576 0.373 ;
     RECT  13.504 0.373 36.96 2.229 ;
     RECT  13.056 2.229 36.96 2.347 ;
     RECT  13.056 2.347 36.832 3.371 ;
     RECT  13.056 3.371 25.312 3.499 ;
     RECT  13.248 3.499 25.312 4.587 ;
     RECT  26.816 3.371 36.832 5.163 ;
     RECT  13.248 4.587 17.504 5.739 ;
     RECT  26.816 5.163 36.448 5.739 ;
     RECT  19.136 4.587 25.312 5.803 ;
     RECT  17.024 5.739 17.504 6.315 ;
     RECT  19.136 5.803 25.056 7.851 ;
     RECT  19.136 7.851 22.112 8.747 ;
     RECT  13.248 5.739 15.392 9.195 ;
     RECT  23.872 7.851 25.056 9.195 ;
     RECT  27.008 5.739 35.232 9.195 ;
     RECT  13.248 9.195 13.408 9.653 ;
     RECT  19.264 8.747 22.112 9.653 ;
     RECT  19.264 9.653 22.24 9.771 ;
     RECT  33.984 9.195 35.232 9.771 ;
     RECT  33.984 9.771 35.04 9.899 ;
     RECT  12.224 9.653 13.408 10.229 ;
     RECT  24.064 9.195 25.056 10.347 ;
     RECT  27.008 9.195 32.16 10.347 ;
     RECT  27.008 10.347 31.328 10.859 ;
     RECT  27.008 10.859 27.232 10.923 ;
     RECT  33.984 9.899 34.784 10.987 ;
     RECT  27.2 10.923 27.232 11.435 ;
     RECT  28.672 10.859 31.328 11.435 ;
     RECT  19.264 9.771 20.512 12.011 ;
     RECT  22.208 9.771 22.24 12.011 ;
     RECT  11.52 10.229 13.408 12.075 ;
     RECT  34.752 10.987 34.784 12.587 ;
     RECT  11.52 12.075 13.28 13.099 ;
     RECT  19.264 12.011 19.296 13.163 ;
     RECT  11.52 13.099 12.256 14.315 ;
     RECT  28.992 11.435 31.328 14.315 ;
     RECT  17.216 6.315 17.504 15.349 ;
     RECT  21.312 13.173 21.344 16.181 ;
     RECT  21.312 16.181 21.472 16.235 ;
     RECT  28.992 14.315 30.56 16.619 ;
     RECT  17.216 15.349 17.952 17.131 ;
     RECT  11.52 14.315 11.552 18.229 ;
     RECT  11.2 18.229 11.552 18.283 ;
     RECT  17.472 17.131 17.952 18.613 ;
     RECT  17.472 18.613 19.04 19.563 ;
     RECT  14.656 19.509 14.688 19.893 ;
     RECT  11.2 18.283 11.232 20.267 ;
     RECT  14.336 19.893 14.688 20.587 ;
     RECT  21.44 16.235 21.472 21.163 ;
     RECT  8.832 21.173 8.864 21.621 ;
     RECT  17.92 19.563 17.952 22.261 ;
     RECT  17.92 22.261 18.208 22.315 ;
     RECT  18.176 22.315 18.208 23.989 ;
     RECT  14.656 20.587 14.688 24.043 ;
     RECT  4.032 23.285 4.064 25.131 ;
     RECT  16.064 23.285 16.096 25.131 ;
     RECT  27.648 23.861 27.68 25.333 ;
     RECT  27.648 25.333 28.256 25.387 ;
     RECT  32.192 23.541 32.224 25.387 ;
     RECT  18.176 23.989 18.4 25.707 ;
     RECT  28.224 25.387 28.256 26.859 ;
     RECT  29.568 16.619 30.56 27.317 ;
     RECT  16 25.653 16.032 27.627 ;
     RECT  32.448 26.741 32.48 28.011 ;
     RECT  14.848 27.829 15.968 28.907 ;
     RECT  28.352 27.317 30.56 29.099 ;
     RECT  18.176 25.707 18.208 29.291 ;
     RECT  15.936 28.907 15.968 30.325 ;
     RECT  4.352 26.677 4.384 30.453 ;
     RECT  4.352 30.453 4.512 30.507 ;
     RECT  8.832 21.621 9.696 30.507 ;
     RECT  30.528 29.099 30.56 30.517 ;
     RECT  32.384 28.469 32.416 30.827 ;
     RECT  15.552 30.325 15.968 31.029 ;
     RECT  15.552 31.029 16.48 31.669 ;
     RECT  30.464 30.517 30.56 31.979 ;
     RECT  0.384 30.965 0.416 32.619 ;
     RECT  8.832 30.507 8.864 32.619 ;
     RECT  10.496 30.709 10.528 32.683 ;
     RECT  21.376 26.741 21.408 33.077 ;
     RECT  21.376 33.077 21.536 33.131 ;
     RECT  28.352 29.099 28.384 33.141 ;
     RECT  28.352 33.141 28.512 33.195 ;
     RECT  14.336 31.669 16.48 33.515 ;
     RECT  4.48 30.507 4.512 33.643 ;
     RECT  30.464 31.979 30.496 33.771 ;
     RECT  34.816 32.437 34.848 33.899 ;
     RECT  6.848 33.013 6.88 34.027 ;
     RECT  32.576 32.437 32.608 34.091 ;
     RECT  19.648 33.013 19.68 34.357 ;
     RECT  26.368 32.821 26.4 34.357 ;
     RECT  25.984 34.357 26.4 34.677 ;
     RECT  25.984 34.677 26.72 34.859 ;
     RECT  28.48 33.195 28.512 34.859 ;
     RECT  14.528 33.515 16.48 35.755 ;
     RECT  0.192 34.933 0.224 35.947 ;
     RECT  19.648 34.357 19.936 35.947 ;
     RECT  14.528 35.755 15.968 36.331 ;
     RECT  33.664 34.805 33.696 36.469 ;
     RECT  33.664 36.469 34.144 36.523 ;
     RECT  34.112 36.523 34.144 36.917 ;
     RECT  14.528 36.331 15.584 36.971 ;
     RECT  15.552 36.971 15.584 38.133 ;
     RECT  15.552 38.133 15.712 38.187 ;
     RECT  29.632 37.557 29.664 38.827 ;
     RECT  36.48 37.429 36.512 38.955 ;
     RECT  2.944 33.589 2.976 39.019 ;
     RECT  19.648 35.947 19.68 39.211 ;
     RECT  25.984 34.859 26.016 39.285 ;
     RECT  27.392 36.917 27.424 39.285 ;
     RECT  25.984 39.285 27.424 39.403 ;
     RECT  32.32 38.005 32.352 39.403 ;
     RECT  21.504 33.131 21.536 39.861 ;
     RECT  34.112 36.917 34.848 39.979 ;
     RECT  34.112 39.979 34.144 41.131 ;
     RECT  0.192 39.541 0.224 41.195 ;
     RECT  25.984 39.403 26.336 41.387 ;
     RECT  20.48 39.861 21.536 42.219 ;
     RECT  25.984 41.387 26.016 42.795 ;
     RECT  14.144 42.037 14.176 43.253 ;
     RECT  15.68 38.187 15.712 43.253 ;
     RECT  14.144 43.253 15.712 43.371 ;
     RECT  36.992 39.861 37.024 44.907 ;
     RECT  14.144 43.371 15.008 45.045 ;
     RECT  32.512 43.765 32.544 45.355 ;
     RECT  13.12 45.045 15.008 45.611 ;
     RECT  18.688 42.037 18.72 45.611 ;
     RECT  26.752 43.829 26.784 45.611 ;
     RECT  21.504 42.219 21.536 46.965 ;
     RECT  25.024 45.557 25.056 47.339 ;
     RECT  0.384 48.117 0.416 49.643 ;
     RECT  37.952 47.797 37.984 49.707 ;
     RECT  13.312 45.611 15.008 50.165 ;
     RECT  16.704 47.221 16.736 50.165 ;
     RECT  21.056 46.965 21.536 50.795 ;
     RECT  13.312 50.165 16.736 51.947 ;
     RECT  30.464 49.397 30.496 52.203 ;
     RECT  26.176 50.101 26.208 52.971 ;
     RECT  4.544 50.997 4.576 52.981 ;
     RECT  13.312 51.947 15.008 53.429 ;
     RECT  8.384 52.981 8.416 53.493 ;
     RECT  28.736 52.981 28.768 54.069 ;
     RECT  16.704 51.947 16.736 54.453 ;
     RECT  31.552 52.405 31.584 54.581 ;
     RECT  16.704 54.453 16.928 54.635 ;
     RECT  31.552 54.581 31.904 54.635 ;
     RECT  19.904 54.645 19.936 54.827 ;
     RECT  12.864 53.429 15.008 54.955 ;
     RECT  31.872 54.635 31.904 55.083 ;
     RECT  8.384 53.493 9.376 55.403 ;
     RECT  21.504 50.795 21.536 55.797 ;
     RECT  4.544 52.981 5.664 56.373 ;
     RECT  16.768 54.635 16.8 57.269 ;
     RECT  16.64 57.269 16.8 57.323 ;
     RECT  16.64 57.323 16.672 57.333 ;
     RECT  4.544 56.373 6.88 58.155 ;
     RECT  20.544 55.797 21.536 58.155 ;
     RECT  27.712 54.069 28.768 58.155 ;
     RECT  9.344 55.403 9.376 58.667 ;
     RECT  16.512 57.333 16.672 58.795 ;
     RECT  36.8 50.101 36.832 59.307 ;
     RECT  5.056 58.155 6.88 59.755 ;
     RECT  5.056 59.755 5.664 59.765 ;
     RECT  4.672 59.765 5.664 60.075 ;
     RECT  16.64 58.795 16.672 60.213 ;
     RECT  28.736 58.155 28.768 61.237 ;
     RECT  25.92 58.549 25.952 61.291 ;
     RECT  4.672 60.075 5.216 61.867 ;
     RECT  16.64 60.213 17.056 61.867 ;
     RECT  4.672 61.867 4.704 62.709 ;
     RECT  4.096 62.709 4.704 62.763 ;
     RECT  8 60.341 8.032 62.763 ;
     RECT  17.024 61.867 17.056 62.763 ;
     RECT  21.504 58.155 21.536 63.221 ;
     RECT  31.936 61.237 31.968 63.221 ;
     RECT  21.12 63.221 21.536 63.275 ;
     RECT  31.936 63.221 32.48 63.275 ;
     RECT  13.312 54.955 15.008 63.349 ;
     RECT  27.648 61.237 28.768 63.403 ;
     RECT  13.12 63.349 15.008 63.669 ;
     RECT  21.12 63.275 21.152 63.851 ;
     RECT  2.752 61.365 2.784 63.915 ;
     RECT  38.784 62.709 38.816 64.491 ;
     RECT  32.448 63.275 32.48 64.949 ;
     RECT  31.68 64.949 32.48 65.579 ;
     RECT  13.12 63.669 16.288 65.643 ;
     RECT  8.448 63.797 8.48 66.101 ;
     RECT  8.256 66.101 8.48 66.155 ;
     RECT  28.736 63.403 28.768 66.229 ;
     RECT  28.736 66.229 29.6 66.283 ;
     RECT  5.44 64.885 5.472 66.539 ;
     RECT  4.096 62.763 4.128 66.613 ;
     RECT  19.968 65.461 20 67.243 ;
     RECT  31.68 65.579 31.712 67.243 ;
     RECT  13.312 65.643 16.288 68.085 ;
     RECT  35.072 67.189 35.104 68.085 ;
     RECT  26.176 66.613 26.208 68.203 ;
     RECT  22.016 64.693 22.048 68.587 ;
     RECT  2.88 66.613 4.128 69.035 ;
     RECT  8.256 66.155 8.288 69.493 ;
     RECT  35.072 68.085 36.192 69.493 ;
     RECT  7.616 69.493 8.288 69.547 ;
     RECT  34.816 69.493 36.192 69.547 ;
     RECT  32.128 68.917 32.16 70.965 ;
     RECT  31.616 70.965 32.16 71.019 ;
     RECT  18.048 68.085 18.08 71.339 ;
     RECT  12.48 68.085 16.288 71.595 ;
     RECT  4.032 69.035 4.128 71.851 ;
     RECT  7.616 69.547 7.648 71.851 ;
     RECT  34.816 69.547 34.848 72.171 ;
     RECT  29.568 66.283 29.6 73.525 ;
     RECT  29.312 73.525 29.6 73.579 ;
     RECT  31.616 71.019 31.648 73.781 ;
     RECT  31.616 73.781 31.712 74.539 ;
     RECT  29.312 73.579 29.344 74.613 ;
     RECT  4.032 71.851 4.064 74.677 ;
     RECT  28.224 74.613 29.344 75.125 ;
     RECT  27.968 75.125 29.344 75.179 ;
     RECT  36.16 69.547 36.192 75.691 ;
     RECT  3.84 74.677 4.064 75.765 ;
     RECT  12.928 71.595 16.288 75.883 ;
     RECT  3.84 75.765 4.576 76.085 ;
     RECT  6.208 75.765 6.24 76.085 ;
     RECT  29.312 75.179 29.344 76.267 ;
     RECT  13.12 75.883 16.288 76.459 ;
     RECT  10.752 68.917 10.784 76.715 ;
     RECT  3.84 76.085 6.24 76.779 ;
     RECT  31.68 74.539 31.712 77.035 ;
     RECT  5.696 76.779 6.24 77.099 ;
     RECT  27.968 75.179 28 77.483 ;
     RECT  9.408 75.829 9.44 77.547 ;
     RECT  13.12 76.459 15.008 78.005 ;
     RECT  33.984 75.637 34.016 78.005 ;
     RECT  33.664 78.005 34.016 78.059 ;
     RECT  20.352 72.565 20.384 79.733 ;
     RECT  20.096 79.733 20.384 79.787 ;
     RECT  7.488 78.901 7.52 79.861 ;
     RECT  5.696 77.099 5.728 79.915 ;
     RECT  33.664 78.059 33.696 79.979 ;
     RECT  26.048 77.429 26.08 79.989 ;
     RECT  26.048 79.989 26.208 80.309 ;
     RECT  25.344 80.309 26.208 81.003 ;
     RECT  7.296 79.861 7.52 81.579 ;
     RECT  12.48 78.005 15.008 81.579 ;
     RECT  20.096 79.787 20.128 81.579 ;
     RECT  7.488 81.579 7.52 82.155 ;
     RECT  12.928 81.579 15.008 82.347 ;
     RECT  25.344 81.003 25.376 82.731 ;
     RECT  3.84 76.779 3.872 82.923 ;
     RECT  8.832 78.901 8.864 82.923 ;
     RECT  13.056 82.347 15.008 83.381 ;
     RECT  18.496 81.525 18.528 84.907 ;
     RECT  13.056 83.381 15.392 86.123 ;
     RECT  13.376 86.123 14.624 86.187 ;
     RECT  14.272 86.187 14.624 86.251 ;
     RECT  24.448 86.005 24.48 86.251 ;
     RECT  35.2 86.069 35.232 86.251 ;
  END
END ot_qfd_emb_tap
END LIBRARY
